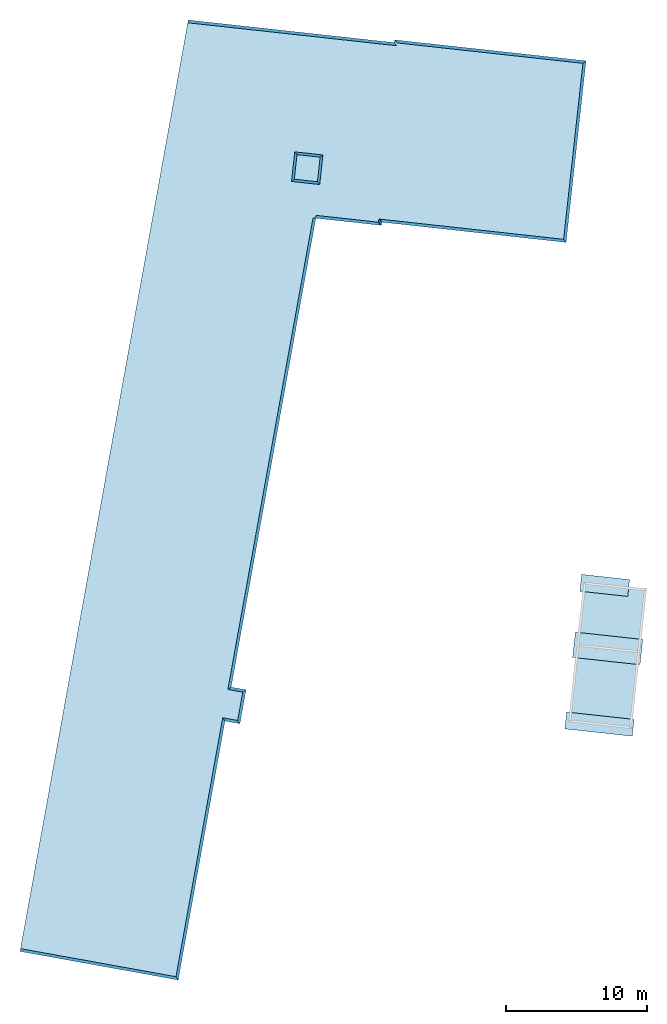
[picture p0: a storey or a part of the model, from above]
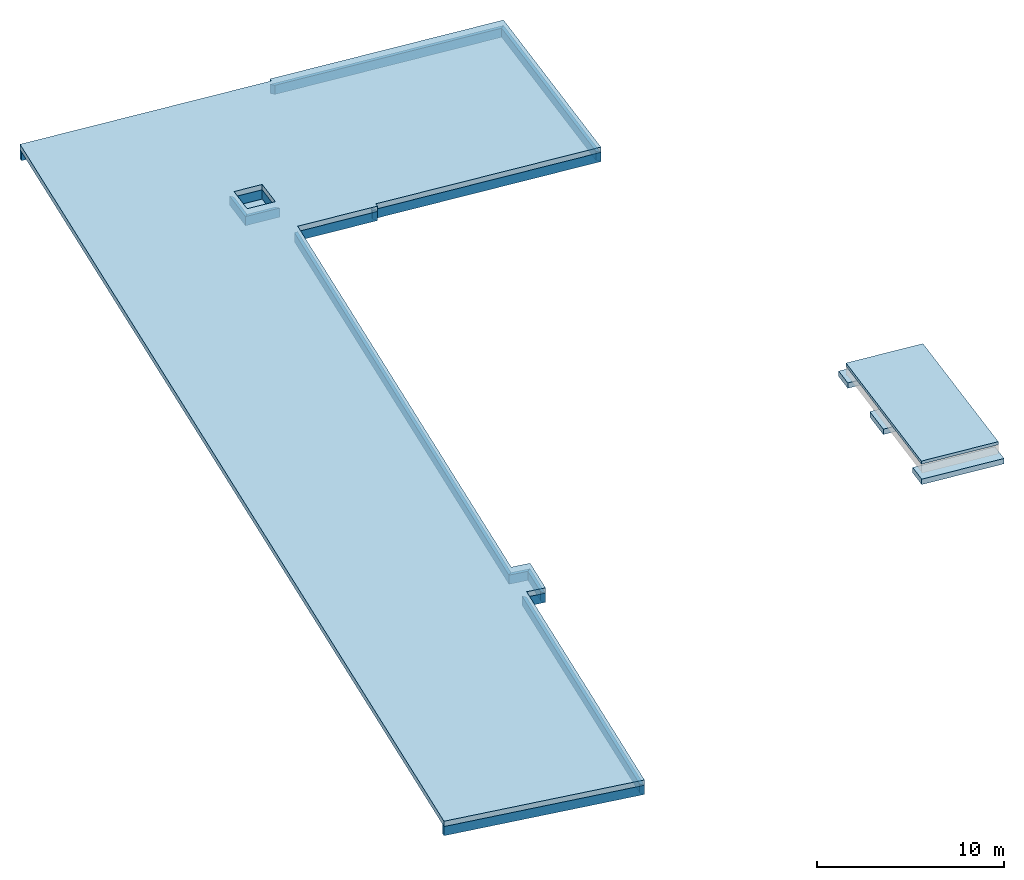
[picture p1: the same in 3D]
Properties of the parts of a building model (IFC2X3), part 1 of 10

# File
Description: ViewDefinition [CoordinationView_V2.0], Option [Elements to export: Visible elements (on all stories)], Option [Partial Structure Display: Entire Model], Option [IFC Domain: All], Option [Structural Function: All Elements], Option [Convert Grid elements: On], Option [Convert IFC Annotations and Archicad 2D elements: Off], Option [Convert 2D symbols of Doors and Windows: Off], Option [Export geometries that Participates in Collision Detection only: Off], Option [Split complex elements: Off], Option [Material Preservation: Explode where necessary], Option [Elements in Solid Element Operations: Extruded/revolved], Option [Elements with junctions: Extruded/revolved without junctions], Option [IFC Model position: Survey Point and Project Origin], Option [Curtain Wall export mode: Container Element], Option [Railing export mode: Single Element], Option [Stair export mode: Container Element], Option [Properties To Export: All properties], Option [Space containment: Off], Option [Geometry to type objects: Off], Option [Element Properties: Off], Option [Building Material Properties: Off], Option [Element Parameters: Off], Option [Component Parameters: Off], Option [IFC Base Quantities: Off], Option [Door Window Parameters: Off], Option [IFC Space boundaries: Off], Option [Archicad Zone Categories as IFC Space classification data: Off], Option [Element Classifications: On]
File name: /Users/julienlaragne/Desktop/ORLEANS TOUR jan 2023/ÉCOLE BOURG D OISANS jan 2023.ifc
Time: 2023-01-25T17:30:47
Author: Architect
Organization: Building Designer Office
Written by: The EXPRESS Data Manager Version 5.02.0100.09 : 18 Aug 2016
Made in: IFC file generated by Graphisoft Archicad 26.0.0 FRA FULL Macintosh version (IFC add-on version: 3001 FRA FULL).
Authorization: The authorising person

# IfcProject, BO
Phase: PRO

# IfcSite, Site
RefLatitude: 45, 3, 7, 23600; RefLongitude: 6, 1, 48, 230400; RefElevation: 719.29 m

# IfcBuildingStorey (4)
In: Bâtiment
Name | Elevation (m)
Fondations | -1.1
RDC | 0
R+1 | 3.2
Toit & PM | 6.55

# IfcBeam: _BA banché 180 x 100, POUTRE
In: R+1
Classification: Poutre (Classification ARCHICAD); Poutre (Classification Archicad); Material: _BA banché
ArchiCADProperties - ID de l'élément: POUTRE; Lien et ID d'élément: POUTRE; Calque: 10_M x baseGO__; Matériau de construction / Composite / Profil / Hachure: _BA banché; Matériau de construction: _BA banché; Nom de zone liée: Circulation 2; Verrouillé: no; Nom d'étage d'implantation: R+1; Numéro d'étage d'implantation: 1; Type d'élément: Poutre; Type de structure: Basique; ID de Parent: POUTRE; Matériaux de construction (Tous): _BA banché; Surfaces (Toutes): _Béton - Lissé; Angle d'inclinaison: 0 deg; Nombre de percements: 0; Surface supérieure: _Béton - Lissé; Surface inférieure: _Béton - Lissé; Position: Intérieur; État de rénovation: Existant; Affichage sur filtre de rénovation: Tous les filtres appropriés; Fonction structurelle: Élément porteur; Coupe transversale de Poutre: Rectangulaire; Surface de fin: _Béton - Lissé; Surface gauche: _Béton - Lissé; Surface droite: _Béton - Lissé; Angle d'inclinaison de Poutre: 0 deg; Génération de modèle analytique structurel: yes; Classification ARCHICAD - 20: Poutre
Pset_BeamCommon - Reference: _BA banché 180 x 100; Span: 2.39006 m; Slope: 0 deg; IsExternal: no; LoadBearing: yes
AC_Pset_RenovationAndPhasing - Renovation Status: Existing

# IfcBeam: _BA banché 240 x 100, POUTRE
In: R+1
Classification: Poutre (Classification ARCHICAD); Poutre (Classification Archicad); Material: _BA banché
ArchiCADProperties - ID de l'élément: POUTRE; Lien et ID d'élément: POUTRE; Calque: 10_M x baseGO__; Matériau de construction / Composite / Profil / Hachure: _BA banché; Matériau de construction: _BA banché; Nom de zone liée: Circulation 2; Verrouillé: no; Nom d'étage d'implantation: R+1; Numéro d'étage d'implantation: 1; Type d'élément: Poutre; Type de structure: Basique; ID de Parent: POUTRE; Matériaux de construction (Tous): _BA banché; Surfaces (Toutes): _Béton - Lissé; Angle d'inclinaison: 0 deg; Nombre de percements: 0; Surface supérieure: _Béton - Lissé; Surface inférieure: _Béton - Lissé; Position: Intérieur; État de rénovation: Existant; Affichage sur filtre de rénovation: Tous les filtres appropriés; Fonction structurelle: Élément porteur; Coupe transversale de Poutre: Rectangulaire; Surface de fin: _Béton - Lissé; Surface gauche: _Béton - Lissé; Surface droite: _Béton - Lissé; Angle d'inclinaison de Poutre: 0 deg; Génération de modèle analytique structurel: yes; Classification ARCHICAD - 20: Poutre
Pset_BeamCommon - Reference: _BA banché 240 x 100; Span: 2.39006 m; Slope: 0 deg; IsExternal: no; LoadBearing: yes
AC_Pset_RenovationAndPhasing - Renovation Status: Existing

# IfcBeam: _BA banché RAL9007 180 x 300, POUTRE
In: R+1
Classification: Poutre (Classification ARCHICAD); Poutre (Classification Archicad); Material: _BA banché RAL9007
ArchiCADProperties - ID de l'élément: POUTRE; Lien et ID d'élément: POUTRE; Calque: 10_M x baseGO__; Matériau de construction / Composite / Profil / Hachure: _BA banché RAL9007; Matériau de construction: _BA banché RAL9007; Nom de zone liée: Terrasse; Verrouillé: no; Nom d'étage d'implantation: R+1; Numéro d'étage d'implantation: 1; Type d'élément: Poutre; Type de structure: Basique; ID de Parent: POUTRE; Matériaux de construction (Tous): _BA banché RAL9007; Surfaces (Toutes): _MENEAU gris RAL 9007; _Enduit minéral RAL7004; Angle d'inclinaison: 0 deg; Nombre de percements: 0; Surface supérieure: _MENEAU gris RAL 9007; Surface inférieure: _Enduit minéral RAL7004; Position: Intérieur; État de rénovation: Existant; Affichage sur filtre de rénovation: Tous les filtres appropriés; Fonction structurelle: Élément porteur; Coupe transversale de Poutre: Rectangulaire; Surface de fin: _MENEAU gris RAL 9007; Surface gauche: _Enduit minéral RAL7004; Surface droite: _Enduit minéral RAL7004; Angle d'inclinaison de Poutre: 0 deg; Génération de modèle analytique structurel: yes; Classification ARCHICAD - 20: Poutre
Pset_BeamCommon - Reference: _BA banché RAL9007 180 x 300; Span: 4.895 m; Slope: 0 deg; IsExternal: no; LoadBearing: yes
AC_Pset_RenovationAndPhasing - Renovation Status: Existing

# IfcBuildingElementPart (15)
In: RDC
Name | Material
10 x _Fini placo poché 590 | _Fini placo poché 590
5 x _Cloison armature 300 | _Cloison armature 300

# IfcBuildingElementProxy: 160 x 170 x 20, Panel-Main-190
In: R+1
Classification: Element de construction non défini (Classification Archicad); Material: Matériau de construction IFC
ArchiCADProperties - ID de l'élément: Panel-Main-190; Lien et ID d'élément: Panel-Main-190; Calque: 10_M x baseGO__; Nom Élément de Bibliothèque: Panneau MR 21; Matériau de construction / Composite / Profil / Hachure: MANQUANT; Matériau de construction: MANQUANT; Verrouillé: no; Nom d'étage d'implantation: R+1; Numéro d'étage d'implantation: 1; Type d'élément: Panneau (Mur-rideau); ID de Parent: pare-vue CTA; Surfaces (Toutes): _Bois-Horiz ocre; Angle d'inclinaison: 90 deg; Surface latérale: GENERAL; État de rénovation: Existant; Affichage sur filtre de rénovation: Tous les filtres appropriés; Abbréviation d'orientation: E; Angle par rapport nord: -100.24 deg; Fonction de panneau: Fixe; Surface intérieure: GENERAL; Surface extérieure: GENERAL; Catégorie de panneau: Panneau personnalisé; Type de panneau: Panneau MR 21; Angle d'inclinaison Panneau mur-rideau: 90 deg
AC_Pset_Panneau_MR_21 - Afficher points chauds 2D en 3D: yes; Modèle schématique automatique: yes; 0-fixe, 1-porte, 2-fenêtre: 0; Direction haut: 0 deg; Direction d'ouverture (ac_openingDir): 0; Angle panneau arrière: 90 deg; Niveau de détail 2D: -1; Stylo coupe: Ouvertures - Coupé non structurel; Hachure coupée: Sans Trame; Stylo hachure coupée: Fond - Couleur 1; Stylo fond hachure coupée: Fond - Couleur 1; Hachure revêtement: Hachure solide; Hachure intérieure: Isolation laine de verre; Stylo hachure revêtement: Ouvertures - Général; Stylo hachure intérieure: Ouvertures - Général; Stylo fond hachure revêtement: Fond - Couleur 1; Stylo fond hachure intérieure: Fond - Couleur 1; Ombre: yes; Intérieur: _Bois-Horiz ocre; Extérieur: _Bois-Horiz ocre; Coût: 0; Surface vitrée totale (gs_list_glassarea_tmp): 0; Supplanter surface vitrée: no; Surface vitrée totale (gs_list_glassarea): 0; Périmètre total vitrage: 0; Type de groupe (FM_Type): Objets par défaut; Type de groupe (iFMType): 1; Numéro de série: Sans; Poids de l'objet: 0; Unité poids de l'objet: kg
AC_Pset_RenovationAndPhasing - Renovation Status: Non défini

# IfcBuildingElementProxy: 245 x 170 x 20, Panel-Main-190
In: R+1
Classification: Element de construction non défini (Classification Archicad); Material: Matériau de construction IFC
ArchiCADProperties - ID de l'élément: Panel-Main-190; Lien et ID d'élément: Panel-Main-190; Calque: 10_M x baseGO__; Nom Élément de Bibliothèque: Panneau MR 21; Matériau de construction / Composite / Profil / Hachure: MANQUANT; Matériau de construction: MANQUANT; Verrouillé: no; Nom d'étage d'implantation: R+1; Numéro d'étage d'implantation: 1; Type d'élément: Panneau (Mur-rideau); ID de Parent: pare-vue CTA; Surfaces (Toutes): _Bois-Horiz ocre; Angle d'inclinaison: 90 deg; Surface latérale: GENERAL; État de rénovation: Existant; Affichage sur filtre de rénovation: Tous les filtres appropriés; Abbréviation d'orientation: E; Angle par rapport nord: -100.24 deg; Fonction de panneau: Fixe; Surface intérieure: GENERAL; Surface extérieure: GENERAL; Catégorie de panneau: Panneau personnalisé; Type de panneau: Panneau MR 21; Angle d'inclinaison Panneau mur-rideau: 90 deg
AC_Pset_Panneau_MR_21 - Afficher points chauds 2D en 3D: yes; Modèle schématique automatique: yes; 0-fixe, 1-porte, 2-fenêtre: 0; Direction haut: 0 deg; Direction d'ouverture (ac_openingDir): 0; Angle panneau arrière: 90 deg; Niveau de détail 2D: -1; Stylo coupe: Ouvertures - Coupé non structurel; Hachure coupée: Sans Trame; Stylo hachure coupée: Fond - Couleur 1; Stylo fond hachure coupée: Fond - Couleur 1; Hachure revêtement: Hachure solide; Hachure intérieure: Isolation laine de verre; Stylo hachure revêtement: Ouvertures - Général; Stylo hachure intérieure: Ouvertures - Général; Stylo fond hachure revêtement: Fond - Couleur 1; Stylo fond hachure intérieure: Fond - Couleur 1; Ombre: yes; Intérieur: _Bois-Horiz ocre; Extérieur: _Bois-Horiz ocre; Coût: 0; Surface vitrée totale (gs_list_glassarea_tmp): 0; Supplanter surface vitrée: no; Surface vitrée totale (gs_list_glassarea): 0; Périmètre total vitrage: 0; Type de groupe (FM_Type): Objets par défaut; Type de groupe (iFMType): 1; Numéro de série: Sans; Poids de l'objet: 0; Unité poids de l'objet: kg
AC_Pset_RenovationAndPhasing - Renovation Status: Non défini

# IfcBuildingElementProxy: 470 x 170 x 20, Panel-Main-847
In: R+1
ArchiCADProperties - ID de l'élément: Panel-Main-847; Lien et ID d'élément: Panel-Main-847; Calque: 10_M x baseGO__; Nom Élément de Bibliothèque: Porte mr 21; Matériau de construction / Composite / Profil / Hachure: MANQUANT; Matériau de construction: MANQUANT; Nom de zone liée: local CTA; Verrouillé: no; Nom d'étage d'implantation: R+1; Numéro d'étage d'implantation: 1; Type d'élément: Panneau (Mur-rideau); ID de Parent: pare-vue CTA; Matériaux de construction (Tous): _Acier; Bois - Equarri 02; Surfaces (Toutes): _Men ext_RAL9007; _Métal - Acier; _INVISIBLE_; _Bois-Horiz ocre; Angle d'inclinaison: 90 deg; De Zone: local CTA; Surface latérale: GENERAL; État de rénovation: Existant; Affichage sur filtre de rénovation: Tous les filtres appropriés; Abbréviation d'orientation: S; Angle par rapport nord: 169.76 deg; Fonction de panneau: Porte; Surface intérieure: GENERAL; Orientation: G; Surface extérieure: GENERAL; Catégorie de panneau: Panneau personnalisé; Type de panneau: Porte mr 21; Angle d'inclinaison Panneau mur-rideau: 90 deg
AC_Pset_Porte_mr_21 - Afficher points chauds 2D en 3D: yes; Modèle schématique automatique: yes; 0-fixe, 1-porte, 2-fenêtre: 1; Direction d'ouverture (gs_opening_dir): Extérieur; Direction d'ouverture (gs_opening_dir_m): 2; Type d'ouverture (gs_optype): Battant; Type d'ouverture (gs_optype_m): 2; Direction haut: 0 deg; Jonction éléments cadree (gs_SashText_typ): Assemblage à onglet; Jonction éléments cadree (gs_SashText_typ_m): 1; Côté ouverture (G/D): G; Direction d'ouverture (0/1/2): 2; Type de cadre (frameType): Sous-cadre; Type de cadre (iFrameType): 1; Type battant: Battant de porte personnalisé; Nbre panneaux horizontaux: 2; Nbre panneaux verticaux: 2; Position grille (grillPosition): Les deux; Position grille (grillPosition_m): 3; Nom de battant de porte: Battant porte CTA; Type poignée (gs_handle_typ): Sans; Type poignée (gs_handle_typ_m): 0; Seuil (bTreshold): no; Angle ouverture en 2D: 45 deg; Angle ouverture horizontal: 0 deg; Angle ouverture vertical: 0 deg; Suppl. Opt. vue pour aff. symb. 2D: no; Type ligne ouverture: 1; Forme ligne ouverture (or_SwingType): Courbé; Forme ligne ouverture (or_iSwingType): 1; Forme ligne ouverture (or_SlidingType): Sans; Forme ligne ouverture (or_iSlidingType): 0; Stylo ligne ouverture 2D/3D (or_opLinePen): Ouvertures - Général; Stylo ligne ouverture 2D/3D (or_iOpLinePen): 3; Suppl. Opt. vue pour proj. 3D: no; Afficher ligne d'ouverture: yes; Type ligne côté ouverture (or_opLineType3dIn): Ligne continue; Type ligne côté ouverture (or_iOpLineType3dIn): 0; Type ligne côté opposé (or_opLineType3dOut): Ligne continue; Type ligne côté opposé (or_iOpLineType3dOut): 0; Orient. ligne (or_oplineStyle): Poignée; Orient. ligne (or_iOplineStyle): 1; Niveau de détail 2D: 1; Stylo panneaux: Eléments 2D - Général; Stylo cadre: Eléments 2D - Général; Stylo seuil: Eléments 2D - Général; Stylo vitrage: Eléments 2D - Général; Hachure de battant: Sans Trame; Hachure de cadre: Sans Trame; Hachure seuil: Sans Trame; Stylo hachure de battant: Eléments 2D - Général; Stylo hachure cadre: Eléments 2D - Général; Stylo hachure recouvr. seuil: Eléments 2D - Général; Stylo fond de hachure battant: Transparent; Stylo fond de hachure cadre: Transparent; Stylo fond de hachure de seuil: Transparent; Stylo coupe/contour: Eléments 2D - Général; Hachure coupée: Sans Trame; Stylo hachure coupée: Fond - Couleur 1; Stylo fond hachure coupée: Fond - Couleur 1; Niveau de détail 3D (gs_detlevel_3D): Simple; Niveau de détail 3D (gs_detlevel_3d_m): 1; Ombre: yes; Résolution: 5; Cadre (matFrame): _Men ext_RAL9007; Battant (matSash): _Bois-Horiz ocre; Grille: _Métal - Zinc; Vitrage (matGlass): _Transp - Verre; Seuil (matTreshold): _Métal - Acier inoxydable; Poignée: _Men ext_RAL9007; Accessoire poignée: _Men ext_RAL9007; Adaptateur: _Métal - Zinc; Fixation: _INVISIBLE_; Coût: 0; Surface vitrée totale (gs_list_glassarea_tmp): 0; Supplanter surface vitrée: no; Surface vitrée totale (gs_list_glassarea): 0; Périmètre total vitrage: 0; Type de groupe (FM_Type): Objets par défaut; Type de groupe (iFMType): 1; Numéro de série: Sans; Poids de l'objet: 0; Unité poids de l'objet: kg; Affichage symbolique de l'ouverture: no
AC_Pset_RenovationAndPhasing - Renovation Status: Non défini

# IfcBuildingElementProxy: 600 x 170 x 20 (5)
In: R+1
Classification: Element de construction non défini (Classification Archicad); Material: Matériau de construction IFC
ArchiCADProperties - ID de l'élément: Panel-Main-190; Lien et ID d'élément: Panel-Main-190; Calque: 10_M x baseGO__; Nom Élément de Bibliothèque: Panneau MR 21; Matériau de construction / Composite / Profil / Hachure: MANQUANT; Matériau de construction: MANQUANT; Verrouillé: no; Nom d'étage d'implantation: R+1; Numéro d'étage d'implantation: 1; Type d'élément: Panneau (Mur-rideau); ID de Parent: pare-vue CTA; Surfaces (Toutes): _Bois-Horiz ocre; Angle d'inclinaison: 90 deg; Surface latérale: GENERAL; État de rénovation: Existant; Affichage sur filtre de rénovation: Tous les filtres appropriés; Abbréviation d'orientation: E; Angle par rapport nord: -100.24 deg; Fonction de panneau: Fixe; Surface intérieure: GENERAL; Surface extérieure: GENERAL; Catégorie de panneau: Panneau personnalisé; Type de panneau: Panneau MR 21; Angle d'inclinaison Panneau mur-rideau: 90 deg
AC_Pset_Panneau_MR_21 - Afficher points chauds 2D en 3D: yes; Modèle schématique automatique: yes; 0-fixe, 1-porte, 2-fenêtre: 0; Direction haut: 0 deg; Direction d'ouverture (ac_openingDir): 0; Angle panneau arrière: 90 deg; Niveau de détail 2D: -1; Stylo coupe: Ouvertures - Coupé non structurel; Hachure coupée: Sans Trame; Stylo hachure coupée: Fond - Couleur 1; Stylo fond hachure coupée: Fond - Couleur 1; Hachure revêtement: Hachure solide; Hachure intérieure: Isolation laine de verre; Stylo hachure revêtement: Ouvertures - Général; Stylo hachure intérieure: Ouvertures - Général; Stylo fond hachure revêtement: Fond - Couleur 1; Stylo fond hachure intérieure: Fond - Couleur 1; Ombre: yes; Intérieur: _Bois-Horiz ocre; Extérieur: _Bois-Horiz ocre; Coût: 0; Surface vitrée totale (gs_list_glassarea_tmp): 0; Supplanter surface vitrée: no; Surface vitrée totale (gs_list_glassarea): 0; Périmètre total vitrage: 0; Type de groupe (FM_Type): Objets par défaut; Type de groupe (iFMType): 1; Numéro de série: Sans; Poids de l'objet: 0; Unité poids de l'objet: kg
AC_Pset_RenovationAndPhasing - Renovation Status: Non défini

# IfcBuildingElementProxy: Basin 03 16 (8)
Classification: Element de construction non défini (Classification Archicad); Material: Matériau de construction IFC
ArchiCADProperties - Calque: 21_App Sanit_____; Nom Élément de Bibliothèque: Basin 03 16; Matériau de construction / Composite / Profil / Hachure: Sans Trame; Type Hachure: Sans Trame; Verrouillé: no; Type d'élément: Équipement; Surfaces (Toutes): _Metal-Inox; _Sanitaire-porcelaine; Position: Non défini; État de rénovation: Existant; Affichage sur filtre de rénovation: Tous les filtres appropriés; Surface: _Peinture-11
AC_Pset_Basin_03_16 - 3D (gs_detlevel_3D): Detailed; 3D (gs_detlevel_3D_m): 2; Show 2D Hotspots in 3D: no; Set Program: no; Tap Type (tapGroup): Single Level Mixer; Tap Type (iTapGroup): 1; Tap Style (gs_tap_type): Style 1; Tap Style (gs_tap_type_m): 1; Hot Water Connection: yes; Tool Type (ConToolType_1): 2; MEP System (ConSystem_1): Undefined; Shape Type (ConType_1): Circle; Connection Type (ConConnectorType_1): Soudé; Cold Water Connection: yes; Tool Type (ConToolType_2): 2; MEP System (ConSystem_2): Undefined; Shape Type (ConType_2): Circle; Connection Type (ConConnectorType_2): Soudé; Waste Water Connection: yes; Tool Type (ConToolType_3): 2; MEP System (ConSystem_3): Undefined; Shape Type (ConType_3): Circle; Connection Type (ConConnectorType_3): Soudé; Resolution: 12; Shadow: yes; 2D Detail Level (gs_detlevel_2D): Scale Sensitive; 2D Detail Level (gs_detlevel_2D_m): 0; Tap Symbol Type (TapSymbol): Detailed; Tap Symbol Type (TapSymbol_m): 2; Contour Pen: Eléments 2D - Général; Fill Type: Sans Trame; Fill Background Pen: Transparent; Basin Material: _Sanitaire-porcelaine; Tap Material: _Métal - Or; Drain Material: _Metal-Inox; Connection Material: _Metal-Inox; Use System Material: no; System Material: _Peinture - Cadmium jaune; Version: 4; Number of Connections: 3; Cost: 0; Type de groupe: 12; Area: 0; Volume: 0; Object Weight: 0; Object Weight Unit: kg
AC_Pset_RenovationAndPhasing - Renovation Status: Existing
Name | In | ID de l'élément = Lien et ID d'élément = ID de Parent | Zones conflictuelles = Nom de zone liée | Nom d'étage d'implantation | Numéro d'étage d'implantation | Fonction structurelle | Angle de rotation (deg) | Fill Pen | Group Type
lavabo-WC | RDC | lavabo-WC | Sanitaires | RDC | 0 | Non défini | 180 | Général - Dessin 0.12 | Sanitation
lavabo-WC | RDC | lavabo-WC | Sanitaires | RDC | 0 | Non défini | 273.96 | Jaune | Sanitation
lavabo-WC | RDC | lavabo-WC | Sanitaires | RDC | 0 | Non défini | 0 | Général - Dessin 0.12 | Sanitaires
lavabo-WC | RDC | lavabo-WC | Sanitaires | RDC | 0 | Non défini | 93.9336 | Jaune | Sanitation
2 x lavabo-BlocSanit | RDC | lavabo-BlocSanit |  | RDC | 0 | Élément non porteur | 184.017 | Général - Dessin 0.12 | Sanitation
lavabo-couloir | R+1 | lavabo-couloir | Sanitaires | R+1 | 1 | Non défini | 0 | Général - Dessin 0.12 | Sanitaires
lavabo-couloir | R+1 | lavabo-couloir | Sanitaires | R+1 | 1 | Non défini | 179.985 | Général - Dessin 0.12 | Sanitation

# IfcBuildingElementProxy: Elément Modèle 215, MOBILIER-001
In: R+1
Material: Matériau de construction IFC
AC_Pset_RenovationAndPhasing - Renovation Status: Existing

# IfcBuildingElementProxy: Elément Modèle 216, Bois - Equarri 02
In: R+1
Material: Bois - Equarri 02
AC_Pset_RenovationAndPhasing - Renovation Status: Existing

# IfcBuildingElementProxy: Elément simple avec deux portes 21 (11)
Classification: Element de construction non défini (Classification Archicad); Material: Matériau de construction IFC
ArchiCADProperties - Calque: 21_App Sanit_____; Nom Élément de Bibliothèque: Elément simple avec deux portes 21; Matériau de construction / Composite / Profil / Hachure: Sans Trame; Type Hachure: Sans Trame; Verrouillé: no; Type d'élément: Équipement; Position: Non défini; État de rénovation: Existant; Affichage sur filtre de rénovation: Tous les filtres appropriés; Fonction structurelle: Non défini; Surface: _Peinture - Ocre jaune
AC_Pset_Elément_simple_avec_deux_portes_21 - Niveau de détail 3D: Détaillé; 3D: 2; Afficher points chauds 2D en 3D: no; Définir programme: no; Taille A B =: Comptoir; Taille 'A' 'B' = Taille élément: no; Type plinthe (gs_toe_type): Entier; Type plinthe (gs_toe_type_m): 1; Nbre d'étagères: 1; Visibilité arête comptoir 3D (side_vis): Droite; Côtés visibles: 2; Visibilité arête comptoir 3D (side_vis_mirror): Gauche; Porte: Style 1; Style porte: 1; Biseau arête: no; Largeurs Portes égales: yes; Angle ouverture porte: 0 deg; Nb. grilles porte vert.: 1; Nb. grilles porte hor.: 2; Tiroir (bDrawer): no; Tiroir no.: 2; Front de tiroir identique à porte: no; Bouton (gs_knob_type): Style 1; Style bouton: 1; Placement (gs_knob_p): Vertical; Placement (gs_knob_p_m): 0; Double face: no; Panneau de finition gauche (left_panel): no; Panneau de finition droit (right_panel): no; Panneau de finition gauche (left_panel_mirror): no; Panneau de finition droit (right_panel_mirror): no; Panneau de finition arrière: no; Type panneau de fin: Style 1; Comptoir (gs_count_type): Rectangulaire; Type comptoir: 1; Evier (gs_sink_type): Style 4; Style évier: 4; Evier sous plan de travail: no; Robinet (gs_tap_type): Style 3; Style de robinet: 3; Connexion d'eau chaude: yes; Type outil (ConToolType_1): 2; Système MEP (ConSystem_1): Non défini; Type de forme (ConType_1): Cercle; Type connexion (ConConnectorType_1): Soudé; Connexion d'eau froide: yes; Type outil (ConToolType_2): 2; Système MEP (ConSystem_2): Non défini; Type de forme (ConType_2): Cercle; Type connexion (ConConnectorType_2): Soudé; Connexion eau résiduaire: yes; Type outil (ConToolType_3): 2; Système MEP (ConSystem_3): Non défini; Type de forme (ConType_3): Cercle; Type connexion (ConConnectorType_3): Soudé; Type symbole meuble: Type 1; Visibilité arête 2D (side_vis2D): Les deux; Visibilité arête 2D (side_vis2D_m): 3; Visibilité arête 2D (side_vis2D_mirror): Les deux; Type symbole évier (SinkSymbol): Détaillé; Type symbole évier (SinkSymbol_m): 2; Type symbole robinet (TapSymbol): Détaillé; Type symbole robinet (TapSymbol_m): 2; Stylo contour: gris moyen (007); Motif de hachure: Sans Trame; Stylo hachure: Fond - Couleur 1; Stylo fond de hachure: Fond - Couleur 1; Résolution: 10; Ombre: yes; Edition points chauds extra: yes; Meuble (gs_cabinet_mat): _Mur int blanc; Dosseret: _Carrelage - Blanc mat 15x15; Plinthe: _MENEAU gris RAL 9007; Porte (vitre): _Verre clair (rapide); Tiroir (DrawerMat): _Mur int blanc; Panneau de fin: _Men ext_RAL9007; Bouton (gs_knob_mat): _Métal - Acier inoxydable; Etagère: _Mur int blanc; Evier (gs_sink_mat): _Métal - Chrome; Robinet (gs_tap_mat): _Métal - Acier inoxydable; Connexion: _Métal - Acier inoxydable; Utiliser surface de système: no; Surface de système: _Peinture - Cadmium jaune; Nombre connexions: 3; Coût: 0; Aire: 0; Volume: 0; Type de groupe (FM_Type): Equipement CVCA; Type de groupe (iFMType): 12; Poids de l'objet: 0; Unité poids de l'objet: kg
AC_Pset_RenovationAndPhasing - Renovation Status: Existing
Name | In | ID de l'élément = Lien et ID d'élément = ID de Parent | Zones conflictuelles = Nom de zone liée | Nom d'étage d'implantation | Numéro d'étage d'implantation | Surfaces (Toutes) | Angle de rotation (deg) | Comptoir (count_mat) | Porte (cadre)
evier-classe | RDC | evier-classe | Salle de classe 1 | RDC | 0 | _Métal - Acier inoxydable; _Métal - Chrome; _Mur int blanc; _Classe 1-RAL2000; _Carrelage - Blanc mat 15x15; _MENEAU gris RAL 9007; _Transp - Invisible | 90 | _Transp - Invisible | _Classe 1-RAL2000
evier-classe | RDC | evier-classe | Salle de classe 5 | RDC | 0 | _Métal - Acier inoxydable; _Métal - Chrome; _Mur int blanc; _Carrelage - Blanc mat 15x15; _Classe 5-RAL4006; _MENEAU gris RAL 9007; _Transp - Invisible | 90 | _Transp - Invisible | _Classe 5-RAL4006
evier-classe | RDC | evier-classe | Salle de classe 2 | RDC | 0 | _Métal - Acier inoxydable; _Métal - Chrome; _Mur int blanc; _Carrelage - Blanc mat 15x15; _MENEAU gris RAL 9007; _Classe 2-RAL5018; _Transp - Invisible | 90 | _Transp - Invisible | _Classe 2-RAL5018
evier-classe | RDC | evier-classe | Salle de classe 3 | RDC | 0 | _Métal - Acier inoxydable; _Métal - Chrome; _Mur int blanc; _Carrelage - Blanc mat 15x15; _MENEAU gris RAL 9007; _Classe 3-RAL3003; _Transp - Invisible | 90 | _Transp - Invisible | _Classe 3-RAL3003
evier-classe | RDC | evier-classe | Salle de classe 4 | RDC | 0 | _Métal - Acier inoxydable; _Métal - Chrome; _Mur int blanc; _Carrelage - Blanc mat 15x15; _MENEAU gris RAL 9007; _Classe 4-RAL6026; _Transp - Invisible | 90 | _Transp - Invisible | _Classe 4-RAL6026
evier-maitres | R+1 | evier-maitres | Salle de réunion (maîtres) | R+1 | 1 | _Métal - Acier inoxydable; _Métal - Chrome; _Mur int blanc; _Carrelage - Blanc mat 15x15; _MENEAU gris RAL 9007 | 273.97 | _Carrelage - Blanc mat 15x15 | _Mur int blanc
evier-classe | R+1 | evier-classe | Salle de classe 6 | R+1 | 1 | _Métal - Acier inoxydable; _Métal - Chrome; _Mur int blanc; _Classe 1-RAL2000; _Carrelage - Blanc mat 15x15; _MENEAU gris RAL 9007; _Transp - Invisible | 90 | _Transp - Invisible | _Classe 1-RAL2000
evier-classe | R+1 | evier-classe | Salle de classe 7 | R+1 | 1 | _Métal - Acier inoxydable; _Métal - Chrome; _Mur int blanc; _Carrelage - Blanc mat 15x15; _MENEAU gris RAL 9007; _Classe 2-RAL5018; _Transp - Invisible | 90 | _Transp - Invisible | _Classe 2-RAL5018
evier-classe | R+1 | evier-classe | Salle de classe 8 | R+1 | 1 | _Métal - Acier inoxydable; _Métal - Chrome; _Mur int blanc; _Carrelage - Blanc mat 15x15; _MENEAU gris RAL 9007; _Classe 3-RAL3003; _Transp - Invisible | 90 | _Transp - Invisible | _Classe 3-RAL3003
evier-classe | R+1 | evier-classe | Salle de classe 10 | R+1 | 1 | _Métal - Acier inoxydable; _Métal - Chrome; _Mur int blanc; _Carrelage - Blanc mat 15x15; _Classe 5-RAL4006; _MENEAU gris RAL 9007; _Transp - Invisible | 90 | _Transp - Invisible | _Classe 5-RAL4006
evier-classe | R+1 | evier-classe | Salle de classe 9 | R+1 | 1 | _Métal - Acier inoxydable; _Métal - Chrome; _Mur int blanc; _Carrelage - Blanc mat 15x15; _MENEAU gris RAL 9007; _Classe 4-RAL6026; _Transp - Invisible | 90 | _Transp - Invisible | _Classe 4-RAL6026

# IfcBuildingElementProxy: Evier Belfast 21 (3)
In: RDC
Classification: Element de construction non défini (Classification Archicad); Material: Matériau de construction IFC
ArchiCADProperties - ID de l'élément: lavabo_BlocSanit; Lien et ID d'élément: lavabo_BlocSanit; Calque: 21_App Sanit_____; Nom Élément de Bibliothèque: Evier Belfast 21; Matériau de construction / Composite / Profil / Hachure: Sans Trame; Type Hachure: Sans Trame; Verrouillé: no; Nom d'étage d'implantation: RDC; Numéro d'étage d'implantation: 0; Type d'élément: Équipement; ID de Parent: lavabo_BlocSanit; Surfaces (Toutes): _Metal-Inox; _Sanitaire-porcelaine; Position: Non défini; État de rénovation: Existant; Affichage sur filtre de rénovation: Tous les filtres appropriés; Angle de rotation: 184.017 deg; Surface: _Peinture - Ocre jaune
AC_Pset_Evier_Belfast_21 - Afficher points chauds 2D en 3D: no; Définir programme: no; Niveau de détail 3D (gs_detlevel_3D): Détaillé; Styles évier (gs_sink_type): Style 1; Styles robinet (gs_tap_type): Sans; Connexion d'eau chaude: yes; Type outil (ConToolType_1): 2; Système MEP (ConSystem_1): Non défini; Type de forme (ConType_1): Cercle; Type connexion (ConConnectorType_1): Soudé; Connexion d'eau froide: yes; Type outil (ConToolType_2): 2; Système MEP (ConSystem_2): Non défini; Type de forme (ConType_2): Cercle; Type connexion (ConConnectorType_2): Soudé; Connexion eau résiduaire: yes; Type outil (ConToolType_3): 2; Système MEP (ConSystem_3): Non défini; Type de forme (ConType_3): Cercle; Type connexion (ConConnectorType_3): Soudé; Connexion eau résiduaire 2: no; Type outil (ConToolType_4): 2; Système MEP (ConSystem_4): Non défini; Type de forme (ConType_4): Cercle; Type connexion (ConConnectorType_4): Soudé; Connexion eau résiduaire 3: no; Type outil (ConToolType_5): 2; Système MEP (ConSystem_5): Non défini; Type de forme (ConType_5): Cercle; Type connexion (ConConnectorType_5): Soudé; Type symbole évier (SinkSymbol): Simple; Type symbole robinet (TapSymbol): Détaillé; Stylo contour: Eléments 2D - Général; Motif de hachure: Sans Trame; Stylo hachure: Général - Dessin 0.12; Stylo fond de hachure: Transparent; Résolution: 16; Ombre: yes; Evier: _Sanitaire-porcelaine; Robinet: _Metal-Inox; Connexion: _Metal-Inox; Utiliser surface de système: no; Surface de système: _Peinture - Cadmium jaune; Niveau de détail 3D (gs_detlevel_3D_m): 2; Styles évier (gs_sink_type_m): 1; Styles robinet (gs_tap_type_m): 0; Type symbole évier (SinkSymbol_m): 1; Type symbole robinet (TapSymbol_m): 2; Nombre connexions: 3; Coût: 0; Type de groupe (FM_Type): Equipement CVCA; Type de groupe (iFMType): 12; Aire: 0; Volume: 0; Poids de l'objet: 0; Unité poids de l'objet: kg
AC_Pset_RenovationAndPhasing - Renovation Status: Existing
Name | Fonction structurelle
2 x lavabo_BlocSanit | Élément non porteur
lavabo_BlocSanit | Non défini

# IfcBuildingElementProxy: Fenêtre double 21 (30)
Classification: Element de construction non défini (Classification Archicad); Fenêtre (Classification ARCHICAD); Material: Matériau de construction IFC
ArchiCADProperties - Calque: 10_M x baseGO__; Nom Élément de Bibliothèque: Fenêtre double 21; Matériau de construction / Composite / Profil / Hachure: Sans Trame; Type Hachure: Sans Trame; Verrouillé: no; Type d'élément: Fenêtre; ID de Parent: M ext-Est; État de rénovation: Existant; Affichage sur filtre de rénovation: Tous les filtres appropriés; Fonction structurelle: Non défini; Structure de Mur: _M ext 18 +18 gris; Nom élément de bibliothèque d'ouverture: Fenêtre double 21; Index hachure latérale ouverture: Sans Trame; Classification ARCHICAD - 21: Fenêtre
AC_Pset_Fenêtre_double_21 - Contours Mur (0-Sans,1-Tout,2-Côté,3-Longueur): 0; Point ch.0-Non,1-2D,2-3D,3-Tous: 3; Option affichage en plan: 3; Angle de position baie: 0 deg; Trou reprend surface latérale de mur: yes; Division de surface du trou courbe dans murs courbes: no; Afficher points chauds 2D en 3D: yes; Type de mur: 1; Type de direction de mur: 1; Position ancre ébrasuer: 1; Fonction de debug Fenêtre Angle: no; Placement (1=Angle, 0=Centre): no; Basculer: no; Démolition / Nouvelle constr.: 1; Nouveau motif de hachure de mur: Parpaing; Nouveau stylo de hachure de mur: Général - Dessin 0.12; Nouveau stylo fond hachure mur: Fond - Couleur 1; Afficher nouv. constr. sur mur: no; Type de ligne démolition: 4; Aff. param. Démolition/Nouveau: no; Fonction Fenêtre Angle: yes; Angle Murs: 90 deg; Murs connectés d'épaiss. diff.: no; Poteau d'angle: no; Coin 2: no; Angle de coin 2: 90 deg; Murs connectés d'épaiss. diff. 2: no; Coin 1: no; Angle de coin 1: 90 deg; Murs connectés d'épaiss. diff. 1: no; Type connexion angle 1: 1; Type connexion angle 2: 1; Entièrement éditable: yes; Niveau de détail 2D: 2; Afficher ébrasure sur symbole: 1; Niveau de détail 3D: 2; Activer niveau détail 3D: 14; Taille nominale: 0; Taille trou comme taille nominale: yes; Taille ébrasure comme nominale: no; Taille unité comme nominale: no; Transmettre taille nominale actuelle à sélection: no; Largeur cadre uniforme: no; Traverse supérieure: no; Traverse supérieure divisée: no; Traverse inférieure: no; Traverse inférieure divisée: no; Panneaux verticaux (gs_PanesConfigVertical): Asymétrique; Panneaux verticaux (gs_iPanesConfigVertical): 3; Direction vitrage fixe (FixGlassDir): Par direction d'ouverture; Direction vitrage fixe (FixGlassDir_m): 1; Type d'opération châssis princ. 2: Battant symétrie; Type d'ouverture (gs_optype_m_01): 4; Type d'ouverture (gs_optype_m_07): 1; Type d'ouverture (gs_optype_m_03): 1; Type d'ouverture (gs_optype_m_06): 1; Type d'ouverture (gs_optype_m_02): 1; Type châssis (MullionStyle_00): Pas de grille; Type châssis (iMullionStyle_00): 1; Type châssis, châssis princ. 1: Pas de grille; Type châssis (iMullionStyle_05): 1; Type châssis, châssis princ. 2: Pas de grille; Type châssis (iMullionStyle_01): 1; Type châssis (iMullionStyle_07): 1; Type châssis (iMullionStyle_03): 1; Type châssis (iMullionStyle_06): 1; Type châssis (iMullionStyle_02): 1; Châssis vitré: no; Meneau jusqu'en haut: no; Meneau jusqu'en bas: no; Edition point chaud de grille: yes; Position grille (MullionPosition): Les deux; Position grille (iMullionPosition): 3; Nbre panneaux V châssis princ. 1: 2; Nbre panneaux H châssis princ. 1: 2; Nbre panneaux V 2 châssis princ. 1: 2; Nbre panneaux H 2 châssis princ. 1: 2; Nbre panneaux V châssis princ. 2: 2; Nbre panneaux H châssis princ. 2: 2; Nbre panneaux V 2 châssis princ. 2: 2; Nbre panneaux H 2 châssis princ. 2: 2; Nbre panneaux V châssis inf.1: 2; Nbre panneaux H châssis inf.1: 2; Nbre panneaux V 2 châssis inf. 1: 2; Nbre panneaux H 2 châssis inf. 1: 2; Nbre panneaux V châssis inf. 2: 2; Nbre panneaux H châssis inf. 2: 2; Nbre panneaux V 2 châssis inf. 2: 2; Nbre panneaux H 2 châssis inf. 2: 2; Nbre panneaux V châssis imposte 1: 2; Nbre panneaux H châssis imposte 1: 2; Nbre panneaux V 2 châssis imposte 1: 2; Nbre panneaux H 2 châssis imposte 1: 2; Nbre panneaux V châssis imposte 2: 2; Nbre panneaux H châssis imposte 2: 2; Nbre panneaux V 2 châssis imposte 2: 2; Nbre panneaux H 2 châssis imposte 2: 2; Style persiennes (iLouverStyle): 1; Angle d'ouverture persiennes: 0 deg; Chambranle extérieur (gs_trim_outside): no; Type chambr. ext. (gs_trimtype_out): Simple; Type chambr. ext. (gs_trimtype_out_int): 1; Type tête chambr. ext.: 1; Chapiteau architrave: yes; Type chapiteau architrave: 1; Chambranle inférieur extérieur: yes; Couvre surface mur ext.: yes; Largeurs uniformes de chambranle (gs_trim_outside_uniform): yes; Chambranle intérieur.: no; Type chambr. intérieur (gs_trimtype_in): Simple; Type chambr. intérieur (gs_trimtype_in_int): 1; Couvre surface mur int.: yes; Largeurs uniformes de chambranle (gs_trim_inside_uniform): yes; Appui (gs_sill_outside): yes; Dépassement appui: no; Type d'appui/seuil: 1; Appui courbe dans murs courbes: yes; Isolation sous appui: yes; Utiliser couche isolation mur: no; Niveau détail 3D seuil brique: 1; Tablette (gs_board_inside): no; Angle tablette: 0 deg; Tabl. courbe dans murs courbes: yes; Tableau dans murs polygonaux: 1; Aération naturelle: no; Type d'aération naturelle: 2; Châssis principal 1: yes; Châssis principal 2: no; Châssis inférieur 1: no; Châssis inférieur 2: no; Châssis imposte 1: no; Châssis imposte 2: no; Volet: yes; Type volet: 6; Types volet activés: 126; Nombre de panneaux: 2; Nombre de panneaux 2: 1; Position panneau (gs_shutter_panelPos): Symétrique; Position panneau (gs_shutter_iPanelPos): 1; Hauteur volet automatique: yes; Cadre supplémentaire: no; Type de couverture (gs_slidingShutter_cover): Profil en Z; Type de couverture (gs_slidingShutter_iCover): 1; Direction articulation (gs_foldingShutter_stacking): Intérieur; Direction articulation (gs_foldingShutter_iStacking): 1; Ouvert en 3D: yes; Angle ouverture en 3D: 180 deg; Afficher symbole 2D: no; Afficher lignes d'ouverture sur symbole: no; Type de panneau: (gs_shutPanel_type): Style 1; Type de panneau: (gs_shutPanel_iType): 1; Largeur cadre inf. différente: no; Largeur volets automatiques: yes; Angle persienne: 30 deg; Nombre trous horizontaux: 5; Nombre trous verticaux: 8; Placement volet roulant (gs_shutRoll_placement): A fenêtre; Placement volet roulant (gs_shutRoll_iPlacement): 2; Type boîte (gs_shutRoll_boxType): Rectangulaire; Type boîte (gs_shutRoll_iBoxType): 1; Position rampe (gs_shutRoll_railPos): Sur revêtement; Position rampe (gs_shutRoll_iRailPos): 1; Afficher revêtement derrière parasol (gs_shutRoll_showCasingBehind): no; Isolation derrière cellule (gs_shutRoll_cutWallBehind): no; Inclure hauteur dans hauteur de trou de mur: no; Angle supérieur boîte: 10 deg; Taille boîte par défaut (gs_shutRoll_boxDefaultSize): A largeur d'ébrasure; Taille boîte par défaut (gs_shutRoll_iBoxDefaultSize): 1; Placement stores (gs_shutLam_placement): Fixé sur façade; Placement stores (gs_shutLam_iPlacement): 1; Isolation derrière cellule (gs_shutLam_cutWallBehind): no; Boîte ouverte: yes; Rampe: yes; Position rampe (gs_shutLam_railPos): Sur revêtement; Position rampe (gs_shutLam_iRailPos): 1; Afficher revêtement derrière parasol (gs_shutLam_showCasingBehind): no; Angle de rotation des lamelles (gs_shutLam_rotation): 45 deg; Angle de rotation des lamelles (gs_shutLam2_rotation): 45 deg; Linteau (bMasonryArch): no; Linteau (gs_masonry_arch_int): 2; Type linteau (gs_masonry_arch_structure): Stuc; Type linteau (gs_masonry_arch_structure_int): 1; Arche sur linteau: yes; Niche sous arche: yes; Angle inclinaison: 75 deg; Surface niche personnalisée: no; Type ébrasure (gs_reveal_type_new): Baie simple; Type ébrasure (gs_reveal_type_int): 2; Type ébrasure inférieure (gs_reveal_type_bottom): Uniforme; Type ébrasure inférieure (gs_reveal_type_bottom_int): 1; Type ébrasure extérieure: Baie simple; Type ébrasure (gs_reveal_doubleOuterTypeInt): 0; Type ébrasure intérieure: Baie simple; Type ébrasure (gs_reveal_doubleInnerTypeInt): 0; Profondeur montant uniforme: yes; Côté angle 2: 20 deg; Côté angle: 20 deg; Angle côté supérieur: 20 deg; Angle côté inférieur: 20 deg; Utiliser composant finition mur: no; Tourner automatiquement plâtre surface intérieure: yes; Tourner plâtre surface intérieure: 0; Tourner automatiquement plâtre surface extérieure: yes; Tourner plâtre surface extérieure: 0; Peut être coté en 2D: no; Afficher en 3D: no; Type de fermeture (gs_closure_type): Pas de fermeture; Type de fermeture (gs_closure_type_int): 1; Tourner couche sur côté (gs_cavity_side): Les deux; Tourner couche sur côté (iCavityClosureSide): 1; Nbre de couches retournées: 1; Num. à partir de (gs_nTurnDir): Face extérieure; Num. à partir de (iCavityClosureTurnDir): 1; Placer fermeture sur côté 2: yes; Placer fermeture sur côté 1: yes; Placer fermeture en haut: no; Placer fermeture en bas: no; Placer fermeture sur couche: 1; Placer fermeture de côté (gs_cc_dutch_ClosureToSide): 1; Ecart à couche externe: yes; Tourner couche sur fermeture: no; Insérer bande d'isolation: yes; Afficher bande d'isolation: yes; Stylo contour (gs_penJoint): Ouvertures - Coupé non structurel; Type de ligne de contour (gs_ltJoint): 1; Motif de hachure (gs_fillJoint): Isolation polystyrène; Stylo hachure (gs_penJointFg): Général - Dessin 0.12; Stylo fond de hachure (gs_penJointBg): Eléments 2D - Dessin; Surface personnalisée: no; Surface: _Men ext_RAL9007; Stylo contour (gs_penPlug): Ouvertures - Coupé non structurel; Type de ligne de contour (gs_ltPlug): 1; Motif de hachure (gs_fillPlug): Isolation polystyrène; Stylo hachure (gs_penPlugFg): Général - Dessin 0.12; Stylo fond de hachure (gs_penPlugBg): Eléments 2D - Dessin; Côté montant édité: 1; Côté mur édité: 1; Numéro couche éditée: 1; Tourner couche: no; Considérer couches comme plâtre: no; Tourner épaiseur: 1; Orientation hachure: 1; Ligne de séparation tournant: no; Stylo ligne de séparation: Général - Dessin 0.12; Dernier côté sélectionné: no; Méthode fermeture changée auto.: no; Connexion à gauche: no; Connexion à droite: no; Connexion en haut: no; Connexion en bas: no; Incrustation allège: no; Tailles incrustation mur (gs_parapet_sizes_st): Automatique; Tailles incrustation mur (iParapetSize): 1; Cotes largeur et longueur auto: yes; Incrustation base mur à (gs_parapet_bottom_st): Etage actuel; Incrustation base mur à (iParapetBottom): 1; Afficher allège masquée: yes; Type ligne allège masquée: 1; Angle ouv. châssis principal 1 (openingAngle_05): 0 deg; Angle ouv. châssis principal 1 (openingAngle2_05): 0 deg; Angle ouv. châssis principal 2 (openingAngle_01): 0 deg; Angle ouv. châssis principal 2 (openingAngle2_01): 0 deg; Angle d'ouverture châssis inf. 1 (openingAngle_07): 0 deg; Angle d'ouverture châssis inf. 1 (openingAngle2_07): 0 deg; Angle d'ouverture châssis inf. 2 (openingAngle_03): 0 deg; Angle d'ouverture châssis inf. 2 (openingAngle2_03): 0 deg; Angle ouv. châssis imposte 1 (openingAngle_06): 0 deg; Angle ouv. châssis imposte 1 (openingAngle2_06): 0 deg; Angle ouv. châssis imposte 2 (openingAngle_02): 0 deg; Angle ouv. châssis imposte 2 (openingAngle2_02): 0 deg; Angle ouverture en 2D: 0 deg; Suppl. Opt. vue pour aff. symb. 2D: no; Type ligne ouverture: 1; Forme ligne ouverture (or_SwingType): Courbé; Forme ligne ouverture (or_iSwingType): 1; Forme ligne ouverture (or_SlidingType): Sans; Forme ligne ouverture (or_iSlidingType): 0; Stylo ligne ouverture 2D/3D (or_opLinePen): Général - Dessin 0.12; Stylo ligne ouverture 2D/3D (or_iOpLinePen): 1; Suppl. Opt. vue pour proj. 3D: no; Afficher ligne d'ouverture: yes; Type ligne côté ouverture (or_opLineType3dIn): Ligne continue; Type ligne côté ouverture (or_iOpLineType3dIn): 0; Type ligne côté opposé (or_opLineType3dOut): Ligne continue; Type ligne côté opposé (or_iOpLineType3dOut): 0; Orient. ligne (or_oplineStyle): Poignée; Orient. ligne (or_iOplineStyle): 1; Stylo ligne non coupée: Ouvertures - Général; Stylo ligne coupée: Ouvertures - Général; Stylo ligne coupée chambranle des deux côtés: Ouvertures - Général; Ligne de contour de mur (gs_wcont_line): Des deux côtés; Ligne de contour de mur (iWallContourLine): 4; Type ligne contour int. mur: 1; Type ligne contour ext. mur: 1; Type ligne contour int. mur masqué: 26; Type ligne contour ext. mur masqué: 26; Stylo ligne contour de mur: Ouvertures - Général; Utiliser hachures: yes; Motif de hachure cadre: Sans Trame; Stylo hachure cadre: Général - Dessin 0.12; Stylo fond de hachure cadre: Ouvertures - fonds de hachure; Motif de hachure châssis: Lame d'air; Stylo fond de châssis: Général - Dessin 0.12; Stylo fond de hachure châssis: Ouvertures - fonds de hachure; Type hachure non coupée: Sans Trame; Stylo hachure non coupée: Général - Dessin 0.12; Stylo fond de hachure non coupé: Ouvertures - fonds de hachure; Motif hachure symbole en plan: Sans Trame; Stylo hachure symbole en plan: Fond - Couleur 1; Stylo fond hachure symbole plan: Fond - Couleur 1; Stylo appui 3D et non coupé: Général - Dessin 0.12; Stylo contour appui en Coupe: Ouvertures - Général; Motif hachure appui en Coupe: Lame d'air; Stylo hachure d'appui en Coupe: Ouvertures - Général; Stylo fond hachure appui Coupe: Ouvertures - fonds de hachure; Stylo contour isolation coupe: Ouvertures - Général; Motif hachure isolation Coupe: Sans Trame; Stylo hachure isolation Coupe: Général - Dessin 0.12; Stylo fond hachure isol. Coupe: Ouvertures - fonds de hachure; Stylo latte 3D et non coupé: Général - Dessin 0.12; Stylo contour latte en Coupe: Général - Dessin 0.12; Motif hachure tablette en Coupe: Lame d'air; Stylo hachure tablette en Coupe: Fond - Couleur 1; Stylo fond hach. tablette Coupe: Fond - Couleur 1; Type hachure chambr. intérieur: Lame d'air; Stylo hachure chambr. int.: Fond - Couleur 1; Stylo fond hachure chambr. int.: Fond - Couleur 1; Type hachure chambr. ext.: Lame d'air; Stylo hachure chambr. ext.: Fond - Couleur 1; Stylo fond hachure chambr. ext.: Fond - Couleur 1; Motif de hachure arche coupe: Sans Trame; Stylo hachure en coupe d'arche: Fond - Couleur 1; Stylo fond hachure appui arche Coupe: Fond - Couleur 1; Motif de hachure de Coupe de Profil de ventilation: Lame d'air; Stylo de hachure de Coupe de Profil de ventilation: Fond - Couleur 1; Stylo de fond de hachure de Coupe de Profil de ventilation: Fond - Couleur 1; Type de ligne symbole volet: 1; Stylo ligne coupée volet: Général - Dessin 0.12; Type hachure coupée volet: Sans Trame; Stylo hachure coupée volet: Général - Dessin 0.12; Stylo fond hachure coupé volet: Ouvertures - fonds de hachure; Motif de hachure d'isolation de volet: Dallage; Stylo de hachure d'isolation de volet: Général - Dessin 0.12; Stylo de fond d'isolation de volet: Fond de fenêtre; Jonction éléments cadree: 2; Stylo cadre: Ouvertures - Général; Stylo châssis: Ouvertures - Général; Stylo vitrage: Ouvertures - Général; Stylo linteau: Murs - Général; Ombre: yes; Surfaces de fenêtre uniformes: no; Cadre extérieur: _Men ext_RAL9007; Cadre intérieur: _Men ext_RAL9007; Châssis extérieur: _Men ext_RAL9007; Châssis intérieur: _Men ext_RAL9007; Persiennes: _Men ext_RAL9007; Vitrage (gs_glass_mat): _Verre clair (rapide); Grille extérieure: _Men ext_RAL9007; Grille intérieure: _Men ext_RAL9007; Panneau solide extérieur: _Men ext_RAL9007; Panneau solide intérieur: _Men ext_RAL9007; Surfaces uniformes de chambranle: yes; Chambranle intérieur: _Men ext_RAL9007; Chambranle extérieur (gs_trim_out_mat): _Men ext_RAL9007; Profil Ventilation: _Métal BAVETTE; Panneau volet: _Men ext_RAL9007; Cadre panneau volet: _Men ext_RAL9007; Rail volet roulant: _Men ext_RAL9007; Boîte store vénitien: _Métal - Acier inoxydable; Segments store vénitien: _Peinture - Blanc brillant; Rail volet coulissant: _Métal - Acier inoxydable; Appui (gs_sill_mat): _Métal BAVETTE; Mortier appui briques: _Enduit - Blanc nature; Tablette (gs_board_mat): _Men ext_RAL9007; Brique linteau: _Coupe3D_; Mortier linteau: _Enduit - Blanc nature; Clef de voûte linteau: _Pierre - Grès 01; Niche: _Mur int Hall; Surface poteau d'angle: _Men ext_RAL9007; Direction d'ouverture: 1; Afficher comme imposte: no; Stylo ligne tête de mur: Général - Dessin 0.12; Type de ligne tête de mur: 21; Prof. linteau sur symbole: no; Type ligne symbole prof. linteau: 21; Stylo symbole prof. linteau: Texte d'annotation - Général; Fenêtre appartient à Zone vers laquelle elle donne: no; Coût: 0; Surface vitrée totale (gs_list_glassarea_tmp): 0; Supplanter surface vitrée: no; Périmètre total vitrage: 0; Performance air libre (mm2/l/m): 0; Type de groupe (FM_Type): Objets par défaut; Type de groupe (iFMType): 1; Poids de l'objet: 0; Unité poids de l'objet: kg; Définition d'orientation de fenêtre: 0; Opération IFC (ifc_optypestr): Vertical double; Opération IFC (ifc_optype): 2; Angle ouverture volet: 180 deg; Style lignes d'ouverture: 1
AC_Pset_RenovationAndPhasing - Renovation Status: Existing
Name | In | ID de l'élément = Lien et ID d'élément | Nom de zone liée = À Zone | Nom d'étage d'implantation | Numéro d'étage d'implantation | Surfaces (Toutes) | Position | Dimensions ébrasure = Dimensions trou mur = Dimensions unité = Taille L x H nominale | Taille L x H x E nominale | Panneaux horizontaux (gs_PanesConfig) | Panneaux horizontaux (gs_iPanesConfig) | Châssis uniformes | Type d'ouverture châssis princ. 1 | Type d'ouverture (gs_optype_m_05) | Angle appui (deg) | Stylo ligne non coupée 3D/Coupe | Boîte volet roulant = Lames volet roulant | Surface vitrée totale (gs_list_glassarea)
2 x Fen classe-200 | RDC | Fen classe-200 | Salle de classe 1 | RDC | 0 | _Men ext_RAL9007; _Verre clair (rapide); _Métal BAVETTE; _Classe 1-RAL2000; _Enduit minéral blanc | Non défini | 200×150 | 200×150×36 | Panneaux uniformes | 1 | no | Bascule | 5 | 0 | classe1 | _Classe 1-RAL2000 | 2.236
2 x Fen classe-200 | RDC | Fen classe-200 | Salle de classe 2 | RDC | 0 | _Men ext_RAL9007; _Verre clair (rapide); _Métal BAVETTE; _Enduit minéral blanc; _Classe 2-RAL5018 | Non défini | 200×150 | 200×150×36 | Panneaux uniformes | 1 | no | Bascule | 5 | 0 | classe2 | _Classe 2-RAL5018 | 2.236
2 x Fen classe-200 | RDC | Fen classe-200 | Salle de classe 3 | RDC | 0 | _Men ext_RAL9007; _Verre clair (rapide); _Métal BAVETTE; _Enduit minéral blanc; _Classe 3-RAL3003 | Non défini | 200×150 | 200×150×36 | Panneaux uniformes | 1 | yes | Bascule | 5 | 0 | classe3 | _Classe 3-RAL3003 | 2.236
2 x Fen classe-200 | RDC | Fen classe-200 | Salle de classe 4 | RDC | 0 | _Men ext_RAL9007; _Verre clair (rapide); _Métal BAVETTE; _Enduit minéral blanc; _Classe 4-RAL6026 | Non défini | 200×150 | 200×150×36 | Panneaux uniformes | 1 | yes | Bascule | 5 | 0 | classe4 | _Classe 4-RAL6026 | 2.236
2 x Fen classe-200 | RDC | Fen classe-200 | Salle de classe 5 | RDC | 0 | _Men ext_RAL9007; _Verre clair (rapide); _Métal BAVETTE; _Enduit minéral blanc; _Classe 5-RAL4006 | Non défini | 200×150 | 200×150×36 | Panneaux uniformes | 1 | yes | Bascule | 5 | 0 | classe5 | _Classe 5-RAL4006 | 2.236
2 x Fen classe-200 | R+1 | Fen classe-200 | Salle de classe 9 | R+1 | 1 | _Men ext_RAL9007; _Verre clair (rapide); _Métal BAVETTE; _Enduit minéral blanc; _Classe 4-RAL6026 | Extérieur | 200×150 | 200×150×36 | Panneaux uniformes | 1 | yes | Bascule | 5 | 0 | classe4 | _Classe 4-RAL6026 | 2.236
2 x Fen classe-200 | R+1 | Fen classe-200 | Salle de classe 10 | R+1 | 1 | _Men ext_RAL9007; _Verre clair (rapide); _Métal BAVETTE; _Enduit minéral blanc; _Classe 5-RAL4006 | Extérieur | 200×150 | 200×150×36 | Panneaux uniformes | 1 | yes | Bascule | 5 | 0 | classe5 | _Classe 5-RAL4006 | 2.236
2 x Fen classe-150 | R+1 | Fen classe-150 | Salle de classe 10 | R+1 | 1 | _Men ext_RAL9007; _Verre clair (rapide); _Métal BAVETTE; _Enduit minéral blanc; _Classe 5-RAL4006 | Extérieur | 150×150 | 150×150×36 | Asymétrique | 3 | yes | Châssis fixe | 2 | 0 | classe5 | _Classe 5-RAL4006 | 1.521
2 x Fen classe-150 | R+1 | Fen classe-150 | Salle de classe 9 | R+1 | 1 | _Men ext_RAL9007; _Verre clair (rapide); _Métal BAVETTE; _Enduit minéral blanc; _Classe 4-RAL6026 | Extérieur | 150×150 | 150×150×36 | Asymétrique | 3 | yes | Châssis fixe | 2 | 0 | classe4 | _Classe 4-RAL6026 | 1.521
2 x Fen classe-200 | R+1 | Fen classe-200 | Salle de classe 6 | R+1 | 1 | _Men ext_RAL9007; _Verre clair (rapide); _Métal BAVETTE; _Classe 1-RAL2000; _Enduit minéral blanc | Non défini | 200×150 | 200×150×36 | Panneaux uniformes | 1 | no | Bascule | 5 | 0 | classe1 | _Classe 1-RAL2000 | 2.236
2 x Fen classe-200 | R+1 | Fen classe-200 | Salle de classe 7 | R+1 | 1 | _Men ext_RAL9007; _Verre clair (rapide); _Métal BAVETTE; _Enduit minéral blanc; _Classe 2-RAL5018 | Extérieur | 200×150 | 200×150×36 | Panneaux uniformes | 1 | no | Bascule | 5 | 0 | classe2 | _Classe 2-RAL5018 | 2.236
2 x Fen classe-150 | R+1 | Fen classe-150 | Salle de classe 7 | R+1 | 1 | _Men ext_RAL9007; _Verre clair (rapide); _Métal BAVETTE; _Enduit minéral blanc; _Classe 2-RAL5018 | Extérieur | 150×150 | 150×150×36 | Asymétrique | 3 | yes | Châssis fixe | 2 | 0 | classe2 | _Classe 2-RAL5018 | 1.521
2 x Fen classe-150 | R+1 | Fen classe-150 | Salle de classe 6 | R+1 | 1 | _Men ext_RAL9007; _Verre clair (rapide); _Métal BAVETTE; _Classe 1-RAL2000; _Enduit minéral blanc | Extérieur | 150×150 | 150×150×36 | Asymétrique | 3 | yes | Châssis fixe | 2 | 0 | classe1 | _Classe 1-RAL2000 | 1.521
2 x Fen classe-200 | R+1 | Fen classe-200 | Salle de classe 8 | R+1 | 1 | _Men ext_RAL9007; _Verre clair (rapide); _Métal BAVETTE; _Enduit minéral blanc; _Classe 3-RAL3003 | Extérieur | 200×150 | 200×150×36 | Panneaux uniformes | 1 | yes | Bascule | 5 | 0 | classe3 | _Classe 3-RAL3003 | 2.236
Fen classe-150 | R+1 | Fen classe-150 | Salle de classe 8 | R+1 | 1 | _Men ext_RAL9007; _Verre clair (rapide); _Métal BAVETTE; _Enduit minéral blanc; _Classe 3-RAL3003 | Extérieur | 150×150 | 150×150×36 | Asymétrique | 3 | yes | Châssis fixe | 2 | 0 | classe3 | _Classe 3-RAL3003 | 1.521
Fen classe-150 | R+1 | Fen classe-150 | Salle de classe 8 | R+1 | 1 | _Men ext_RAL9007; _Verre clair (rapide); _Métal BAVETTE; _Enduit minéral blanc; _Classe 3-RAL3003 | Extérieur | 150×150 | 150×150×36 | Asymétrique | 3 | yes | Châssis fixe | 2 | 2 | classe3 | _Classe 3-RAL3003 | 1.521

# IfcBuildingElementProxy: Fenêtre horizontale à châssis multiples 21 (11)
Material: Matériau de construction IFC
ArchiCADProperties - Nom Élément de Bibliothèque: Fenêtre horizontale à châssis multiples 21; Verrouillé: no; Type d'élément: Fenêtre; État de rénovation: Existant; Affichage sur filtre de rénovation: Tous les filtres appropriés; Fonction structurelle: Non défini; Nom élément de bibliothèque d'ouverture: Fenêtre horizontale à châssis multiples 21
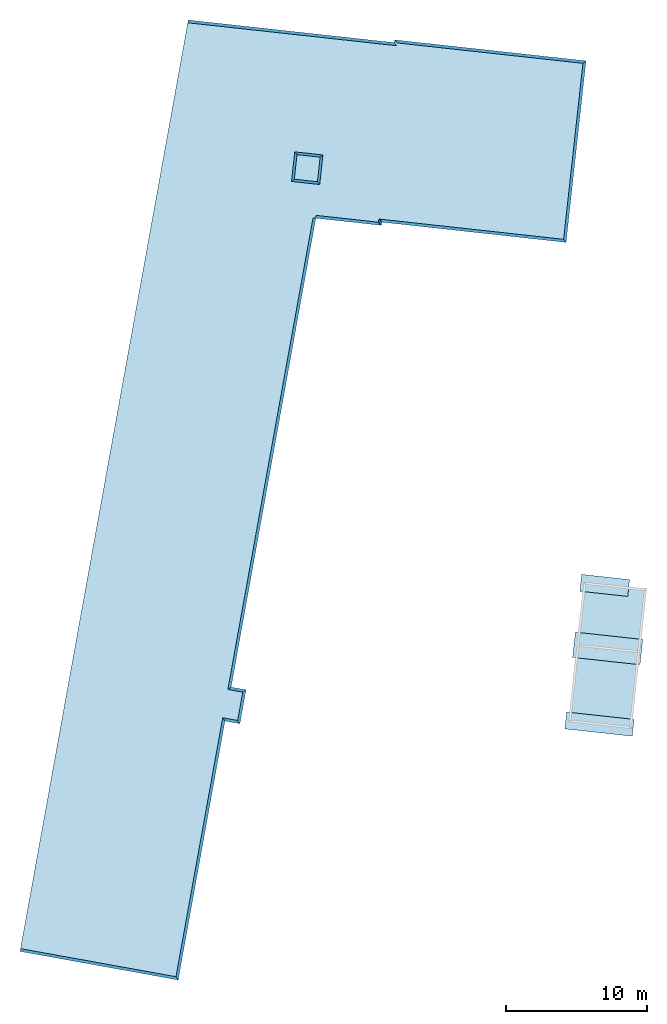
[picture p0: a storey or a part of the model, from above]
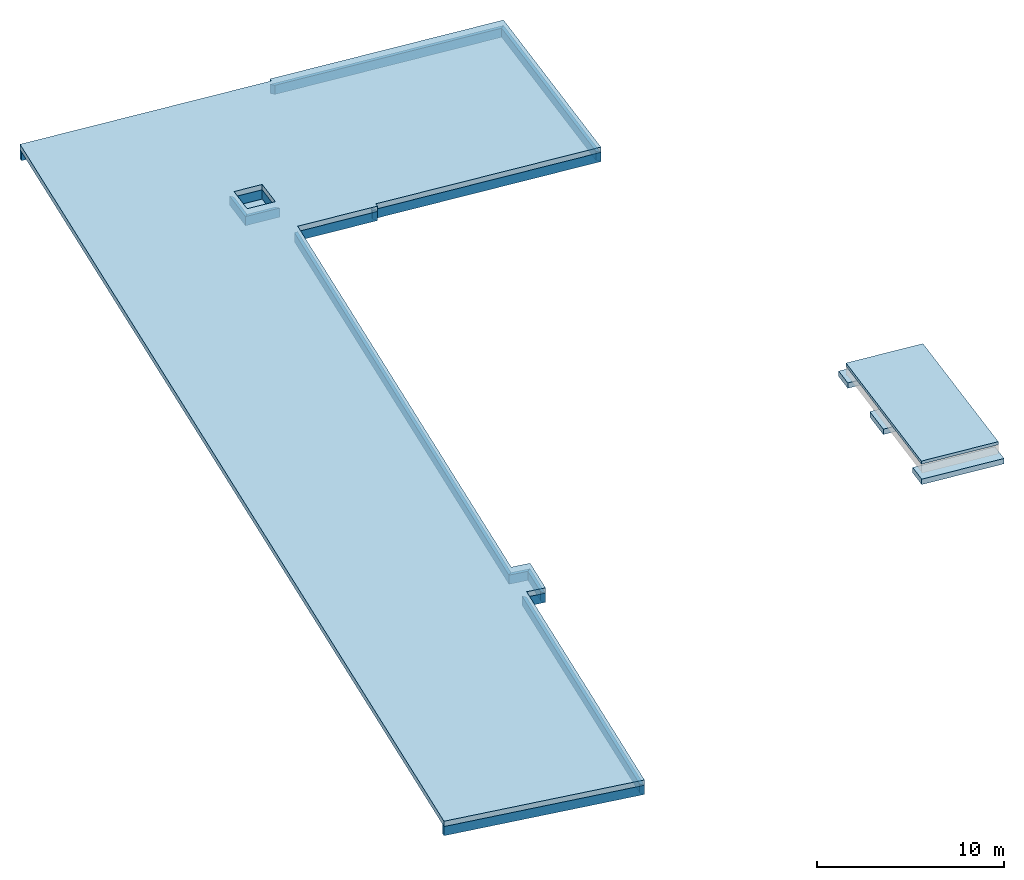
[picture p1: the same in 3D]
Properties of the parts of a building model (IFC2X3), part 2 of 10

# IfcBuildingElementProxy: Fenêtre horizontale à châssis multiples 21 (11)
AC_Pset_Fenêtre_horizontale_à_châssis_multiples_21 - Contours Mur (0-Sans,1-Tout,2-Côté,3-Longueur): 0; Point ch.0-Non,1-2D,2-3D,3-Tous: 3; Option affichage en plan: 3; Angle de position baie: 0 deg; Division de surface du trou courbe dans murs courbes: no; Afficher points chauds 2D en 3D: yes; Type de mur: 1; Position ancre ébrasuer: 1; Fonction de debug Fenêtre Angle: no; Placement (1=Angle, 0=Centre): no; Basculer: no; Démolition / Nouvelle constr.: 1; Nouveau motif de hachure de mur: Parpaing; Nouveau stylo de hachure de mur: Général - Dessin 0.12; Nouveau stylo fond hachure mur: Fond - Couleur 1; Afficher nouv. constr. sur mur: no; Aff. param. Démolition/Nouveau: no; Fonction Fenêtre Angle: yes; Angle Murs: 90 deg; Murs connectés d'épaiss. diff.: no; Poteau d'angle: no; Coin 2: no; Angle de coin 2: 90 deg; Murs connectés d'épaiss. diff. 2: no; Coin 1: no; Angle de coin 1: 90 deg; Murs connectés d'épaiss. diff. 1: no; Type connexion angle 1: 1; Type connexion angle 2: 1; Entièrement éditable: yes; Afficher ébrasure sur symbole: 1; Niveau de détail 3D: 2; Activer niveau détail 3D: 14; Taille nominale: 0; Taille trou comme taille nominale: yes; Taille ébrasure comme nominale: no; Taille unité comme nominale: no; Transmettre taille nominale actuelle à sélection: no; Multiplier unité: no; Nombre de copies: 2; Conserver distance d'axe: yes; Direction vitrage fixe (FixGlassDir): Par direction d'ouverture; Direction vitrage fixe (FixGlassDir_m): 1; Type d'ouverture Châssis 4: Vitrage fixe; Type d'ouverture (gs_optype_m_04): 1; Type d'ouverture Châssis 5: Vitrage fixe; Type d'ouverture (gs_optype_m_05): 1; Type d'ouverture Châssis 6: Vitrage fixe; Type d'ouverture (gs_optype_m_06): 1; Type d'ouverture Châssis 7: Vitrage fixe; Type d'ouverture (gs_optype_m_07): 1; Type d'ouverture Châssis 8: Vitrage fixe; Type d'ouverture (gs_optype_m_08): 1; Type d'ouverture Châssis 9: Vitrage fixe; Type d'ouverture (gs_optype_m_09): 1; Type d'ouverture Châssis 10: Vitrage fixe; Type d'ouverture (gs_optype_m_10): 1; Type de châssis Châssis 1: Pas de grille; Type châssis (iMullionStyle_01): 1; Type de châssis Châssis 2: Pas de grille; Type châssis (iMullionStyle_02): 1; Type de châssis Châssis 3: Pas de grille; Type châssis (iMullionStyle_03): 1; Type de châssis Châssis 4: Pas de grille; Type châssis (iMullionStyle_04): 1; Type de châssis Châssis 5: Pas de grille; Type châssis (iMullionStyle_05): 1; Type de châssis Châssis 6: Pas de grille; Type châssis (iMullionStyle_06): 1; Type de châssis Châssis 7: Pas de grille; Type châssis (iMullionStyle_07): 1; Type de châssis Châssis 8: Pas de grille; Type châssis (iMullionStyle_08): 1; Type de châssis Châssis 9: Pas de grille; Type châssis (iMullionStyle_09): 1; Type châssis (iMullionStyle_10): 1; Edition point chaud de grille: yes; Position grille (MullionPosition): Les deux; Position grille (iMullionPosition): 3; Nbre de panneaux verticaux 2 Châssis 1: 2; Nbre de panneaux horizontaux 2 Châssis 1: 2; Nbre de panneaux verticaux Châssis 2: 2; Nbre de panneaux horizontaux Châssis 2: 2; Nbre de panneaux verticaux 2 Châssis 2: 2; Nbre de panneaux horizontaux 2 Châssis 2: 2; Nbre de panneaux verticaux Châssis 3: 2; Nbre de panneaux horizontaux Châssis 3: 2; Nbre de panneaux verticaux 2 Châssis 3: 2; Nbre de panneaux horizontaux 2 Châssis 3: 2; Nbre de panneaux verticaux Châssis 4: 2; Nbre de panneaux horizontaux Châssis 4: 2; Nbre de panneaux verticaux 2 Châssis 4: 2; Nbre de panneaux horizontaux 2 Châssis 4: 2; Nbre de panneaux verticaux Châssis 5: 2; Nbre de panneaux horizontaux Châssis 5: 2; Nbre de panneaux verticaux 2 Châssis 5: 2; Nbre de panneaux horizontaux 2 Châssis 5: 2; Nbre de panneaux verticaux Châssis 6: 2; Nbre de panneaux horizontaux Châssis 6: 2; Nbre de panneaux verticaux 2 Châssis 6: 2; Nbre de panneaux horizontaux 2 Châssis 6: 2; Nbre de panneaux verticaux Châssis 7: 2; Nbre de panneaux horizontaux Châssis 7: 2; Nbre de panneaux verticaux 2 Châssis 7: 2; Nbre de panneaux horizontaux 2 Châssis 7: 2; Nbre de panneaux verticaux Châssis 8: 2; Nbre de panneaux horizontaux Châssis 8: 2; Nbre de panneaux verticaux 2 Châssis 8: 2; Nbre de panneaux horizontaux 2 Châssis 8: 2; Nbre de panneaux verticaux Châssis 9: 2; Nbre de panneaux horizontaux Châssis 9: 2; Nbre de panneaux verticaux 2 Châssis 9: 2; Nbre de panneaux horizontaux 2 Châssis 9: 2; Nbre de panneaux verticaux Châssis 10: 2; Nbre de panneaux horizontaux Châssis 10: 2; Nbre de panneaux verticaux 2 Châssis 10: 2; Nbre de panneaux horizontaux 2 Châssis 10: 2; Style persiennes (iLouverStyle): 1; Angle d'ouverture persiennes: 0 deg; Chambranle extérieur (gs_trim_outside): no; Type chambr. ext. (gs_trimtype_out): Simple; Type chambr. ext. (gs_trimtype_out_int): 1; Type tête chambr. ext.: 1; Chapiteau architrave: yes; Type chapiteau architrave: 1; Chambranle inférieur extérieur: yes; Couvre surface mur ext.: yes; Largeurs uniformes de chambranle (gs_trim_outside_uniform): yes; Chambranle intérieur.: no; Type chambr. intérieur (gs_trimtype_in): Simple; Type chambr. intérieur (gs_trimtype_in_int): 1; Couvre surface mur int.: yes; Largeurs uniformes de chambranle (gs_trim_inside_uniform): yes; Dépassement appui: no; Angle appui: 3 deg; Appui courbe dans murs courbes: yes; Isolation sous appui: yes; Utiliser couche isolation mur: no; Niveau détail 3D seuil brique: 1; Tablette (gs_board_inside): no; Angle tablette: 0 deg; Tabl. courbe dans murs courbes: yes; Tableau dans murs polygonaux: 1; Aération naturelle: no; Type d'aération naturelle: 2; Châssis 2: no; Châssis 3: no; Châssis 4: no; Châssis 5: no; Châssis 6: no; Châssis 7: no; Châssis 8: no; Châssis 9: no; Châssis 10: no; Volet: no; Type volet: 1; Types volet activés: 126; Nombre de panneaux (gs_shutter_nPanels): 2; Nombre de panneaux 2: 1; Position panneau (gs_shutter_panelPos): Symétrique; Position panneau (gs_shutter_iPanelPos): 1; Hauteur volet automatique: yes; Cadre supplémentaire: no; Type de couverture (gs_slidingShutter_cover): Profil en Z; Type de couverture (gs_slidingShutter_iCover): 1; Direction articulation (gs_foldingShutter_stacking): Intérieur; Direction articulation (gs_foldingShutter_iStacking): 1; Ouvert en 3D: yes; Angle ouverture en 3D: 180 deg; Afficher symbole 2D: yes; Afficher lignes d'ouverture sur symbole: no; Type de panneau: (gs_shutPanel_type): Style 1; Type de panneau: (gs_shutPanel_iType): 1; Largeur cadre inf. différente: no; Largeur volets automatiques: yes; Angle persienne: 30 deg; Nombre trous horizontaux: 5; Nombre trous verticaux: 8; Placement volet roulant (gs_shutRoll_placement): Sur façade; Placement volet roulant (gs_shutRoll_iPlacement): 1; Type boîte (gs_shutRoll_boxType): Rectangulaire; Type boîte (gs_shutRoll_iBoxType): 1; Position rampe (gs_shutRoll_railPos): Sur revêtement; Position rampe (gs_shutRoll_iRailPos): 1; Afficher revêtement derrière parasol (gs_shutRoll_showCasingBehind): no; Isolation derrière cellule (gs_shutRoll_cutWallBehind): no; Inclure hauteur dans hauteur de trou de mur: no; Angle supérieur boîte: 10 deg; Taille boîte par défaut (gs_shutRoll_boxDefaultSize): Largeur ébrasure; Taille boîte par défaut (gs_shutRoll_iBoxDefaultSize): 1; Placement stores (gs_shutLam_placement): Fixé sur façade; Placement stores (gs_shutLam_iPlacement): 1; Isolation derrière cellule (gs_shutLam_cutWallBehind): no; Boîte ouverte: yes; Rampe: yes; Position rampe (gs_shutLam_railPos): Sur revêtement; Position rampe (gs_shutLam_iRailPos): 1; Afficher revêtement derrière parasol (gs_shutLam_showCasingBehind): no; Angle de rotation des lamelles (gs_shutLam_rotation): 45 deg; Angle de rotation des lamelles (gs_shutLam2_rotation): 45 deg; Linteau (bMasonryArch): no; Linteau (gs_masonry_arch_int): 2; Type linteau (gs_masonry_arch_structure): Stuc; Type linteau (gs_masonry_arch_structure_int): 1; Arche sur linteau: yes; Niche sous arche: yes; Angle inclinaison: 75 deg; Surface niche personnalisée: no; Type ébrasure inférieure (gs_reveal_type_bottom): Uniforme; Type ébrasure inférieure (gs_reveal_type_bottom_int): 1; Type ébrasure extérieure: Baie simple; Type ébrasure (gs_reveal_doubleOuterTypeInt): 0; Type ébrasure intérieure: Baie simple; Type ébrasure (gs_reveal_doubleInnerTypeInt): 0; Profondeur montant uniforme: yes; Côté angle 2: 20 deg; Côté angle: 20 deg; Angle côté supérieur: 20 deg; Angle côté inférieur: 20 deg; Utiliser composant finition mur: no; Tourner plâtre surface intérieure: 0; Tourner plâtre surface extérieure: 0; Peut être coté en 2D: no; Afficher en 3D: no; Type de fermeture (gs_closure_type): Pas de fermeture; Type de fermeture (gs_closure_type_int): 1; Tourner couche sur côté (gs_cavity_side): Les deux; Tourner couche sur côté (iCavityClosureSide): 1; Nbre de couches retournées: 1; Num. à partir de (gs_nTurnDir): Face extérieure; Num. à partir de (iCavityClosureTurnDir): 1; Placer fermeture sur côté 2: yes; Placer fermeture sur côté 1: yes; Placer fermeture en haut: no; Placer fermeture en bas: no; Placer fermeture sur couche: 1; Placer fermeture de côté (gs_cc_dutch_ClosureToSide): 1; Ecart à couche externe: yes; Tourner couche sur fermeture: no; Insérer bande d'isolation: yes; Afficher bande d'isolation: yes; Stylo contour (gs_penJoint): Ouvertures - Coupé non structurel; Type de ligne de contour (gs_ltJoint): 1; Motif de hachure (gs_fillJoint): Isolation polystyrène; Stylo hachure (gs_penJointFg): Général - Dessin 0.12; Stylo fond de hachure (gs_penJointBg): Eléments 2D - Dessin; Surface personnalisée: no; Stylo contour (gs_penPlug): Ouvertures - Coupé non structurel; Type de ligne de contour (gs_ltPlug): 1; Motif de hachure (gs_fillPlug): Isolation polystyrène; Stylo hachure (gs_penPlugFg): Général - Dessin 0.12; Stylo fond de hachure (gs_penPlugBg): Eléments 2D - Dessin; Côté montant édité: 1; Côté mur édité: 1; Numéro couche éditée: 1; Tourner couche: no; Considérer couches comme plâtre: no; Tourner épaiseur: 1; Orientation hachure: 1; Ligne de séparation tournant: no; Stylo ligne de séparation: Général - Dessin 0.12; Dernier côté sélectionné: no; Méthode fermeture changée auto.: no; Connexion à gauche: no; Connexion à droite: no; Connexion en haut: no; Connexion en bas: no; Incrustation allège: no; Tailles incrustation mur (gs_parapet_sizes_st): Automatique; Tailles incrustation mur (iParapetSize): 1; Cotes largeur et longueur auto: yes; Incrustation base mur à (gs_parapet_bottom_st): Etage actuel; Incrustation base mur à (iParapetBottom): 1; Afficher allège masquée: yes; Type ligne allège masquée: 1; Angle d'ouverture de Châssis 1 (openingAngle2_01): 0 deg; Angle d'ouverture de Châssis 2 (openingAngle_02): 0 deg; Angle d'ouverture de Châssis 2 (openingAngle2_02): 0 deg; Angle d'ouverture de Châssis 3 (openingAngle_03): 0 deg; Angle d'ouverture de Châssis 3 (openingAngle2_03): 0 deg; Angle d'ouverture de Châssis 4 (openingAngle_04): 0 deg; Angle d'ouverture de Châssis 4 (openingAngle2_04): 0 deg; Angle d'ouverture de Châssis 5 (openingAngle_05): 0 deg; Angle d'ouverture de Châssis 5 (openingAngle2_05): 0 deg; Angle d'ouverture de Châssis 6 (openingAngle_06): 0 deg; Angle d'ouverture de Châssis 6 (openingAngle2_06): 0 deg; Angle d'ouverture de Châssis 7 (openingAngle_07): 0 deg; Angle d'ouverture de Châssis 7 (openingAngle2_07): 0 deg; Angle d'ouverture de Châssis 8 (openingAngle_08): 0 deg; Angle d'ouverture de Châssis 8 (openingAngle2_08): 0 deg; Angle d'ouverture de Châssis 9 (openingAngle_09): 0 deg; Angle d'ouverture de Châssis 9 (openingAngle2_09): 0 deg; Angle d'ouverture de Châssis 10 (openingAngle_10): 0 deg; Angle d'ouverture de Châssis 10 (openingAngle2_10): 0 deg; Angle ouverture en 2D: 0 deg; Type ligne ouverture: 1; Forme ligne ouverture (or_SwingType): Courbé; Forme ligne ouverture (or_iSwingType): 1; Forme ligne ouverture (or_SlidingType): Sans; Forme ligne ouverture (or_iSlidingType): 0; Suppl. Opt. vue pour proj. 3D: no; Type ligne côté ouverture (or_opLineType3dIn): Ligne continue; Type ligne côté ouverture (or_iOpLineType3dIn): 0; Type ligne côté opposé (or_opLineType3dOut): Ligne continue; Type ligne côté opposé (or_iOpLineType3dOut): 0; Orient. ligne (or_oplineStyle): Poignée; Orient. ligne (or_iOplineStyle): 1; Stylo ligne non coupée: Ouvertures - Général; Stylo ligne coupée chambranle des deux côtés: Ouvertures - Général; Type ligne contour int. mur: 1; Type ligne contour ext. mur: 1; Stylo ligne contour de mur: Ouvertures - Général; Motif de hachure cadre: Sans Trame; Motif de hachure châssis: Lame d'air; Type hachure non coupée: Sans Trame; Motif hachure symbole en plan: Sans Trame; Stylo appui 3D et non coupé: Général - Dessin 0.12; Stylo contour appui en Coupe: Général - Dessin 0.12; Stylo contour isolation coupe: Général - Dessin 0.12; Motif hachure isolation Coupe: Isolation polystyrène; Stylo hachure isolation Coupe: Général - Dessin 0.12; Stylo fond hachure isol. Coupe: Fond - Couleur 1; Stylo latte 3D et non coupé: Général - Dessin 0.12; Stylo contour latte en Coupe: Général - Dessin 0.12; Motif hachure tablette en Coupe: Lame d'air; Stylo hachure tablette en Coupe: Fond - Couleur 1; Stylo fond hach. tablette Coupe: Fond - Couleur 1; Type hachure chambr. intérieur: Lame d'air; Stylo hachure chambr. int.: Fond - Couleur 1; Stylo fond hachure chambr. int.: Fond - Couleur 1; Type hachure chambr. ext.: Lame d'air; Stylo hachure chambr. ext.: Fond - Couleur 1; Stylo fond hachure chambr. ext.: Fond - Couleur 1; Stylo hachure en coupe d'arche: Fond - Couleur 1; Stylo fond hachure appui arche Coupe: Fond - Couleur 1; Motif de hachure de Coupe de Profil de ventilation: Lame d'air; Stylo de hachure de Coupe de Profil de ventilation: Fond - Couleur 1; Stylo de fond de hachure de Coupe de Profil de ventilation: Fond - Couleur 1; Type de ligne symbole volet: 1; Stylo ligne coupée volet: Général - Dessin 0.12; Stylo ligne non coupée 3D/Coupe: Général - Dessin 0.12; Stylo hachure coupée volet: Général - Dessin 0.12; Stylo fond hachure coupé volet: Fond de fenêtre; Motif de hachure d'isolation de volet: Dallage; Stylo de hachure d'isolation de volet: Général - Dessin 0.12; Stylo de fond d'isolation de volet: Fond de fenêtre; Jonction éléments cadree: 2; Stylo cadre: Ouvertures - Général; Stylo châssis: Ouvertures - Général; Stylo linteau: Murs - Général; Ombre: yes; Surfaces uniformes de chambranle: yes; Profil Ventilation: _Métal BAVETTE; Boîte volet roulant: _Métal - Acier inoxydable; Lames volet roulant: _Peinture - Blanc brillant; Rail volet roulant: _Peinture - Blanc brillant; Boîte store vénitien: _Métal - Acier inoxydable; Segments store vénitien: _Peinture - Blanc brillant; Rail volet coulissant: _Métal - Acier inoxydable; Mortier appui briques: _Enduit - Blanc nature; Brique linteau: _Coupe3D_; Mortier linteau: _Enduit - Blanc nature; Clef de voûte linteau: _Pierre - Grès 01; Niche: _Mur int Hall; Afficher comme imposte: no; Stylo ligne tête de mur: Général - Dessin 0.12; Type de ligne tête de mur: 21; Prof. linteau sur symbole: no; Type ligne symbole prof. linteau: 21; Stylo symbole prof. linteau: Texte d'annotation - Général; Fenêtre appartient à Zone vers laquelle elle donne: no; Coût: 0; Surface vitrée totale (gs_list_glassarea_tmp): 0; Supplanter surface vitrée: no; Périmètre total vitrage: 0; Performance air libre (mm2/l/m): 0; Type de groupe (FM_Type): Objets par défaut; Type de groupe (iFMType): 1; Poids de l'objet: 0; Unité poids de l'objet: kg; Définition d'orientation de fenêtre: 0; Angle ouverture volet: 180 deg; Style lignes d'ouverture: 1
AC_Pset_RenovationAndPhasing - Renovation Status: Existing
Name | In | Classification | ID de l'élément = Lien et ID d'élément | Calque | Matériau de construction / Composite / Profil / Hachure = Type Hachure = Index hachure latérale ouverture | Nom de zone liée | Nom d'étage d'implantation | Numéro d'étage d'implantation | ID de Parent | Surfaces (Toutes) | À Zone | Position | Dimensions ébrasure = Dimensions trou mur = Dimensions unité = Taille L x H nominale | Taille L x H x E nominale | Structure de Mur | Classification ARCHICAD - 21 | Trou reprend surface latérale de mur | Type de direction de mur | Type de ligne démolition = Type ligne contour int. mur masqué = Type ligne contour ext. mur masqué | Niveau de détail 2D | Nombre de panneaux (gs_panes_number) | Configuration panneaux | Panneaux horizontaux = Stylo ligne ouverture 2D/3D (or_iOpLinePen) | Largeur cadre uniforme | Châssis uniformes | Type d'ouverture Châssis 1 | Type d'ouverture (gs_optype_m_01) | Type d'ouverture Châssis 2 | Type d'ouverture (gs_optype_m_02) | Type d'ouverture Châssis 3 | Type d'ouverture (gs_optype_m_03) | Type châssis (MullionStyle_00) | Type châssis (iMullionStyle_00) | Nbre de panneaux verticaux Châssis 1 | Nbre de panneaux horizontaux Châssis 1 | Appui (gs_sill_outside) | Type d'appui/seuil | Châssis 1 | Type ébrasure (gs_reveal_type_new) | Type ébrasure (gs_reveal_type_int) | Tourner automatiquement plâtre surface intérieure = Tourner automatiquement plâtre surface extérieure | Surface = Persiennes = Chambranle intérieur = Chambranle extérieur (gs_trim_out_mat) = Panneau volet = Cadre panneau volet = Tablette (gs_board_mat) = Surface poteau d'angle | Angle d'ouverture de Châssis 1 (openingAngle_01) (deg) | Suppl. Opt. vue pour aff. symb. 2D | Stylo ligne ouverture 2D/3D (or_opLinePen) | Afficher ligne d'ouverture | Stylo ligne coupée | Ligne de contour de mur (gs_wcont_line) | Ligne de contour de mur (iWallContourLine) | Utiliser hachures | Stylo hachure cadre = Stylo fond de châssis = Stylo hachure non coupée | Stylo fond de hachure cadre = Stylo fond de hachure châssis | Stylo fond de hachure non coupé | Stylo hachure symbole en plan | Stylo fond hachure symbole plan | Motif hachure appui en Coupe | Stylo hachure d'appui en Coupe | Stylo fond hachure appui Coupe | Motif de hachure arche coupe = Type hachure coupée volet | Stylo vitrage | Surfaces de fenêtre uniformes | Cadre extérieur = Cadre intérieur | Châssis extérieur = Châssis intérieur | Vitrage (gs_glass_mat) | Grille extérieure = Grille intérieure = Panneau solide extérieur = Panneau solide intérieur | Appui (gs_sill_mat) | Direction d'ouverture | Surface vitrée totale (gs_list_glassarea) | Opération IFC (ifc_optypestr) | Opération IFC (ifc_optype)
Fen bureau | RDC | Element de construction non défini (Classification Archicad); Fenêtre (Classification ARCHICAD) | Fen bureau | 10_M x baseGO__ | Sans Trame | Activités RASED | RDC | 0 | M ext-Ouest | _Men ext_RAL9007; _Verre clair (rapide); _Métal BAVETTE | Activités RASED | Non défini | 290×70 | 290×70×36 | _M ext 18 +18 gris | Fenêtre | yes | 0 | 4 | 1 | 3 | Panneaux uniformes | 1 | no | yes | Accrochée par le bas | 7 | Accrochée par le bas | 7 | Accrochée par le bas | 7 | Pas de grille | 1 | 2 | 1 | yes | 11 | yes | Baie simple | 2 | yes | _Men ext_RAL9007 | 0 | no | Général - Dessin 0.12 | yes | Ouvertures - Général | Des deux côtés | 4 | no | Général - Dessin 0.12 | Transparent | Transparent | Fond - Couleur 1 | Fond - Couleur 1 | Sans Trame | Général - Dessin 0.12 | Transparent | Sans Trame | Ouvertures - Général | yes | _Men ext_RAL9007 | _Men ext_RAL9007 | _Verre clair (rapide) | _Men ext_RAL9007 | _Métal BAVETTE | 1 | 1.22 | Triple vertical | 4
Fen bureau | RDC | Element de construction non défini (Classification Archicad); Fenêtre (Classification ARCHICAD) | Fen bureau | 10_M x baseGO__ | Sans Trame | Bureau RASED | RDC | 0 | M ext-Ouest | _Men ext_RAL9007; _Verre clair (rapide); _Métal BAVETTE | Bureau RASED | Non défini | 290×70 | 290×70×36 | _M ext 18 +18 gris | Fenêtre | yes | 0 | 4 | 1 | 3 | Panneaux uniformes | 1 | no | yes | Accrochée par le bas | 7 | Accrochée par le bas | 7 | Accrochée par le bas | 7 | Pas de grille | 1 | 2 | 1 | yes | 11 | yes | Baie simple | 2 | yes | _Men ext_RAL9007 | 0 | no | Général - Dessin 0.12 | yes | Ouvertures - Général | Des deux côtés | 4 | no | Général - Dessin 0.12 | Transparent | Transparent | Fond - Couleur 1 | Fond - Couleur 1 | Sans Trame | Général - Dessin 0.12 | Transparent | Sans Trame | Ouvertures - Général | yes | _Men ext_RAL9007 | _Men ext_RAL9007 | _Verre clair (rapide) | _Men ext_RAL9007 | _Métal BAVETTE | 1 | 1.22 | Triple vertical | 4
Baie salle-pluri-Est | RDC | Element de construction non défini (Classification Archicad); Fenêtre (Classification ARCHICAD) | Baie salle-pluri-Est | 10_M x baseGO__ | Sans Trame | Salle plurivalente | RDC | 0 | M ext pluri-Est | _Men ext_RAL9007; _Verre clair (rapide) | Salle plurivalente | Non défini | 630×240 | 630×240×56 | _M ext pluri Est | Fenêtre | yes | 1 | 4 | 1 | 6 | Panneaux uniformes | 1 | yes | yes | Vitrage fixe | 1 | Vitrage fixe | 1 | Vitrage fixe | 1 | A carreaux | 2 | 4 | 1 | no | 11 | yes | Baie simple | 2 | yes | _Men ext_RAL9007 | 0 | yes | Général - Dessin 0.12 | yes | Ouvertures - Général | Des deux côtés | 4 | no | Général - Dessin 0.12 | Transparent | Transparent | Fond - Couleur 1 | Fond - Couleur 1 | Sans Trame | Général - Dessin 0.12 | Transparent | Sans Trame | Ouvertures - Général | yes | _Men ext_RAL9007 | _Men ext_RAL9007 | _Verre clair (rapide) | _Men ext_RAL9007 | _Métal BAVETTE | 1 | 11.6944 | Autre | 10
Bandeau BlocSanit | RDC | Element de construction non défini (Classification Archicad); Fenêtre (Classification ARCHICAD) | Bandeau BlocSanit | 10_M x baseGO__ | Hachure solide |  | RDC | 0 | M-Ext_BlocSanit | _Men ext_RAL9007; _Transp - Verre |  | Non défini | 590×45 | 590×45×30 | _M ext 18 +12 | Fenêtre | yes | 0 | 37 | 1 | 5 | Asymétrique | 3 | no | yes | Vitrage fixe | 1 | Vitrage fixe | 1 | Vitrage fixe | 1 | Pas de grille | 1 | 2 | 2 | yes | 11 | no | Baie simple | 2 | yes | _Bois - Pin granuleux horizontal | 30 | no | Ouvertures - Général | yes | Ouvertures - Coupé structurel | Des deux côtés | 4 | no | Ouvertures - Hachures coupées | Fond - Couleur 1 | Fond - Couleur 1 | Fond - Couleur 1 | Fond - Couleur 1 | Lame d'air | Fond - Couleur 1 | Fond - Couleur 1 | Isolation - Panneau rigide | Eléments 2D - Général | no | _Men ext_RAL9007 | _Bois - Acajou horizontal | _Transp - Verre | _Bois - Pin granuleux horizontal | _Men ext_RAL9007 | 0 | 1.911 | Autre | 10
Fen vide-sur-hall-Est | R+1 | Element de construction non défini (Classification Archicad); Fenêtre (Classification ARCHICAD) | Fen vide-sur-hall-Est | 10_M x baseGO__ | Sans Trame (3) |  | R+1 | 1 | M ext-hall-Est | _Verre clair (rapide); _Métal BAVETTE; _chassis int |  | Extérieur | 230×122 | 230×122×36 | _M ext 18 +18 gris | Fenêtre | yes | 1 | 4 | 1 | 2 | Panneaux uniformes | 1 | yes | yes | Vitrage fixe | 1 | Accrochée par le bas | 7 | Vitrage fixe | 1 | Pas de grille | 1 | 2 | 1 | yes | 11 | yes | Baie simple | 2 | yes | _Men ext_RAL9007 | 0 | yes | Général - Dessin 0.12 | yes | Ouvertures - Général | Intérieur | 2 | yes | Général - Dessin 0.12 | Transparent | Général - fonds de hachures | Fond - Couleur 1 | Fond - Couleur 1 | Sans Trame | Général - Dessin 0.12 | Transparent | Sans Trame | Ouvertures - Général | yes | _chassis int | _chassis int | _Verre clair (rapide) | _chassis int | _Métal BAVETTE | 1 | 2.0145 | Vertical double | 2
Baie vide-sur-hall-Est | R+1 | Element de construction non défini (Classification Archicad); Fenêtre (Classification ARCHICAD) | Baie vide-sur-hall-Est | 10_M x baseGO__ | Sans Trame (3) |  | R+1 | 1 | M ext-hall-Est | _Men ext_RAL9007; _Verre clair (rapide); _Métal BAVETTE |  | Extérieur | 680×122 | 680×122×36 | _M ext 18 +18 gris | Fenêtre | yes | 1 | 4 | 1 | 4 | Panneaux uniformes | 1 | yes | yes | Vitrage fixe | 1 | Vitrage fixe | 1 | Vitrage fixe | 1 | Pas de grille | 1 | 2 | 1 | yes | 11 | yes | Baie simple | 2 | yes | _Men ext_RAL9007 | 0 | yes | Général - Dessin 0.12 | yes | Ouvertures - Général | Intérieur | 2 | yes | Général - Dessin 0.12 | Transparent | Général - fonds de hachures | Fond - Couleur 1 | Fond - Couleur 1 | Sans Trame | Général - Dessin 0.12 | Transparent | Sans Trame | Ouvertures - Général | yes | _Men ext_RAL9007 | _Men ext_RAL9007 | _Verre clair (rapide) | _Men ext_RAL9007 | _Métal BAVETTE | 1 | 6.87475 | Autre | 10
Fen vide-sur-hall-Est | R+1 | Element de construction non défini (Classification Archicad); Fenêtre (Classification ARCHICAD) | Fen vide-sur-hall-Est | 10_M x baseGO__ | Sans Trame (3) |  | R+1 | 1 | M ext-hall-Est | _Men ext_RAL9007; _Verre clair (rapide); _Métal BAVETTE |  | Extérieur | 230×122 | 230×122×36 | _M ext 18 +18 gris | Fenêtre | yes | 1 | 4 | 1 | 2 | Panneaux uniformes | 1 | yes | yes | Accrochée par le bas | 7 | Vitrage fixe | 1 | Vitrage fixe | 1 | Pas de grille | 1 | 2 | 1 | yes | 11 | yes | Baie simple | 2 | yes | _Men ext_RAL9007 | 0 | yes | Général - Dessin 0.12 | yes | Ouvertures - Général | Intérieur | 2 | yes | Général - Dessin 0.12 | Transparent | Général - fonds de hachures | Fond - Couleur 1 | Fond - Couleur 1 | Sans Trame | Général - Dessin 0.12 | Transparent | Sans Trame | Ouvertures - Général | yes | _Men ext_RAL9007 | _Men ext_RAL9007 | _Verre clair (rapide) | _Men ext_RAL9007 | _Métal BAVETTE | 1 | 2.0145 | Vertical double | 2
45 | R+1 | Element de construction non défini (Classification Archicad); Porte (Classification ARCHICAD) | 45 | 10_M refendGO__ | Sans Trame (3) | Salle de réunion (maîtres) | R+1 | 1 | M refend | _Verre clair (rapide); _Mur int Hall |  | Intérieur | 596×150 | 596×150×18 | _BA banché RAL9007 | Porte | no | 0 | 4 | 4 | 5 | Panneaux uniformes | 1 | no | no | Vitrage fixe | 1 | Vitrage fixe | 1 | Vitrage fixe | 1 | Pas de grille | 1 | 2 | 2 | no | 1 | yes | Pas d'ébrasure - arête | 1 | yes | _Men ext_RAL9007 | 0 | yes | Général - Dessin 0.12 | yes | Ouvertures - Général | Des deux côtés | 4 | yes | Général - Dessin 0.12 | Transparent | Transparent | Général - Dessin 0.12 | Transparent | Lame d'air | Fond - Couleur 1 | Fond - Couleur 1 | Sans Trame | Ouvertures - Général | no | _Mur int Hall | _Men ext_RAL9007 | _Verre clair (rapide) | _Men ext_RAL9007 | _Men ext_RAL9007 | 1 | 7.51938 | Autre | 10 | Description: réunion; Pset_FireRatingProperties - FireResistanceRating: CF 1/2H; ArchiCADProperties - De Zone: Salle de réunion (maîtres); Résistance au feu: CF 1/2H; AC_Pset_Fenêtre_horizontale_à_châssis_multiples_21 - Degré de protection au feu: CF 1/2H
44 | R+1 | Element de construction non défini (Classification Archicad); Porte (Classification ARCHICAD) | 44 | 10_M refendGO__ | Sans Trame (3) | Salle de réunion (maîtres) | R+1 | 1 | M refend | _Verre clair (rapide); _Mur int Hall | Salle de réunion (maîtres) | Intérieur | 357×120 | 357×120×18 | _BA banché RAL9007 | Porte | yes | 0 | 4 | 4 | 4 | Panneaux uniformes | 1 | no | no | Vitrage fixe | 1 | Vitrage fixe | 1 | Vitrage fixe | 1 | Pas de grille | 1 | 2 | 2 | no | 1 | yes | Pas d'ébrasure - arête | 1 | yes | _Men ext_RAL9007 | 0 | yes | Général - Dessin 0.12 | yes | Ouvertures - Général | Des deux côtés | 4 | yes | Général - Dessin 0.12 | Transparent | Transparent | Général - Dessin 0.12 | Transparent | Lame d'air | Fond - Couleur 1 | Fond - Couleur 1 | Sans Trame | Ouvertures - Général | no | _Mur int Hall | _Men ext_RAL9007 | _Verre clair (rapide) | _Men ext_RAL9007 | _Men ext_RAL9007 | 0 | 3.41264 | Autre | 10 | Description: réunion; Pset_FireRatingProperties - FireResistanceRating: CF 1/2H; ArchiCADProperties - Résistance au feu: CF 1/2H; AC_Pset_Fenêtre_horizontale_à_châssis_multiples_21 - Degré de protection au feu: CF 1/2H
Baie couloir | R+1 | Element de construction non défini (Classification Archicad); Fenêtre (Classification ARCHICAD) | Baie couloir | 10_M x baseGO__ | Sans Trame (3) | Circulation 3 | R+1 | 1 | M ext entretien-Est | _Men ext_RAL9007; _Verre clair (rapide); _Métal BAVETTE | Circulation 3 | Extérieur | 815×160 | 815×160×36 | _M ext 18 +18 MILIEU | Fenêtre | yes | 0 | 4 | 1 | 7 | Panneaux uniformes | 1 | no | yes | Vitrage fixe | 1 | Vitrage fixe | 1 | Vitrage fixe | 1 | Pas de grille | 1 | 2 | 2 | yes | 11 | yes | Baie simple | 2 | yes | _Men ext_RAL9007 | 0 | no | Général - Dessin 0.12 | no | Ouvertures - Général | Des deux côtés | 4 | no | Général - Dessin 0.12 | Transparent | Transparent | Général - Dessin 0.12 | Transparent | Sans Trame | Général - Dessin 0.12 | Transparent | Sans Trame | Ouvertures - Général | yes | _Men ext_RAL9007 | _Men ext_RAL9007 | _Verre clair (rapide) | _Men ext_RAL9007 | _Métal BAVETTE | 1 | 11.4074 | Autre | 10
43 | R+1 | Element de construction non défini (Classification Archicad); Porte (Classification ARCHICAD) | 43 | 20_Cloison________ | Sans Trame (3) | Salle de réunion (maîtres) | R+1 | 1 | Clois reunion | _Verre clair (rapide); _Mur int Hall | Salle de réunion (maîtres) | Intérieur | 285×120 | 285×120×10 | _Cloison 10cm | Porte | yes | 0 | 4 | 4 | 3 | Panneaux uniformes | 1 | no | no | Vitrage fixe | 1 | Vitrage fixe | 1 | Vitrage fixe | 1 | Pas de grille | 1 | 2 | 2 | no | 1 | yes | Pas d'ébrasure - arête | 1 | no | _Men ext_RAL9007 | 0 | yes | Général - Dessin 0.12 | yes | Ouvertures - Général | Des deux côtés | 4 | yes | Général - Dessin 0.12 | Transparent | Transparent | Général - Dessin 0.12 | Transparent | Lame d'air | Fond - Couleur 1 | Fond - Couleur 1 | Sans Trame | Ouvertures - Général | no | _Mur int Hall | _Men ext_RAL9007 | _Verre clair (rapide) | _Men ext_RAL9007 | _Men ext_RAL9007 | 0 | 2.7468 | Triple vertical | 4 | Description: réunion; Pset_FireRatingProperties - FireResistanceRating: CF 1/2H; ArchiCADProperties - Résistance au feu: CF 1/2H; AC_Pset_Fenêtre_horizontale_à_châssis_multiples_21 - Degré de protection au feu: CF 1/2H

# IfcBuildingElementProxy: Fenêtre ronde 21, oeil-de-boeuf
In: RDC
Classification: Element de construction non défini (Classification Archicad); Fenêtre (Classification ARCHICAD); Material: Matériau de construction IFC
ArchiCADProperties - ID de l'élément: oeil-de-boeuf; Lien et ID d'élément: oeil-de-boeuf; Calque: 10_M x baseGO__; Nom Élément de Bibliothèque: Fenêtre ronde 21; Matériau de construction / Composite / Profil / Hachure: Sans Trame; Type Hachure: Sans Trame; Nom de zone liée: Local entretien; Verrouillé: no; Nom d'étage d'implantation: RDC; Numéro d'étage d'implantation: 0; Type d'élément: Fenêtre; ID de Parent: M ext entretien-Est; Surfaces (Toutes): _Men ext_RAL9007; _Verre clair (rapide); De Zone: Local entretien; Position: Non défini; État de rénovation: Existant; Affichage sur filtre de rénovation: Tous les filtres appropriés; Fonction structurelle: Non défini; Dimensions ébrasure: 120×120; Dimensions trou mur: 120×120; Dimensions unité: 120×120; Taille L x H nominale: 120×120; Taille L x H x E nominale: 120×120×42; Structure de Mur: _M ext bard. 6+18+18 gris; Nom élément de bibliothèque d'ouverture: Fenêtre ronde 21; Index hachure latérale ouverture: Sans Trame; Classification ARCHICAD - 21: Fenêtre
AC_Pset_Fenêtre_ronde_21 - Contours Mur (0-Sans,1-Tout,2-Côté,3-Longueur): 0; Point ch.0-Non,1-2D,2-3D,3-Tous: 3; Option affichage en plan: 3; Angle de position baie: 0 deg; Trou reprend surface latérale de mur: yes; Division de surface du trou courbe dans murs courbes: no; Afficher points chauds 2D en 3D: yes; Type de mur: 1; Type de direction de mur: 1; Position ancre ébrasuer: 1; Basculer: no; Démolition / Nouvelle constr.: 1; Nouveau motif de hachure de mur: Parpaing; Nouveau stylo de hachure de mur: Général - Dessin 0.12; Nouveau stylo fond hachure mur: Fond - Couleur 1; Afficher nouv. constr. sur mur: no; Type de ligne démolition: 4; Aff. param. Démolition/Nouveau: no; Entièrement éditable: yes; Niveau de détail 2D: 2; Afficher ébrasure sur symbole: 1; Niveau de détail 3D: 2; Activer niveau détail 3D: 14; Taille nominale: 0; Taille trou comme taille nominale: yes; Taille ébrasure comme nominale: no; Taille unité comme nominale: no; Transmettre taille nominale actuelle à sélection: no; Châssis uniformes: no; Direction vitrage fixe (FixGlassDir): Par direction d'ouverture; Direction vitrage fixe (FixGlassDir_m): 1; Type d'opération châssis princ.: Vitrage fixe; Type d'ouverture: 1; Type châssis (MullionStyle_00): Pas de grille; Type châssis (iMullionStyle_00): 1; Type châssis (MullionStyle_01): Pas de grille; Type châssis (iMullionStyle_01): 1; Position grille (MullionPosition): Les deux; Position grille (iMullionPosition): 3; Nombre panneaux verticalement: 3; Nombre panneaux horizontalement: 3; Nombre panneaux verticalement 2: 2; Nombre panneaux horizontalement 2: 2; Chambranle extérieur (gs_trim_outside): no; Type chambr. ext. (gs_trimtype_out): Simple; Type chambr. ext. (gs_trimtype_out_int): 1; Largeurs uniformes de chambranle (gs_trim_outside_uniform): no; Chambranle intérieur.: yes; Type chambr. intérieur (gs_trimtype_in): Simple; Type chambr. intérieur (gs_trimtype_in_int): 1; Largeurs uniformes de chambranle (gs_trim_inside_uniform): no; Appui (gs_sill_outside): no; Dépassement appui: no; Type d'appui/seuil: 1; Angle appui: 3 deg; Appui courbe dans murs courbes: yes; Isolation sous appui: yes; Utiliser couche isolation mur: no; Niveau détail 3D seuil brique: 1; Tablette (gs_board_inside): no; Angle tablette: 0 deg; Tabl. courbe dans murs courbes: yes; Tableau dans murs polygonaux: 1; Volet: no; Type volet: 1; Types volet activés: 38; Nombre de panneaux: 2; Nombre de panneaux 2: 1; Position panneau (gs_shutter_panelPos): Symétrique; Position panneau (gs_shutter_iPanelPos): 1; Hauteur volet automatique: yes; Cadre supplémentaire: no; Type de couverture (gs_slidingShutter_cover): Profil en Z; Type de couverture (gs_slidingShutter_iCover): 1; Direction articulation (gs_foldingShutter_stacking): Intérieur; Direction articulation (gs_foldingShutter_iStacking): 1; Ouvert en 3D: yes; Angle ouverture en 3D: 180 deg; Afficher symbole 2D: yes; Afficher lignes d'ouverture sur symbole: no; Type de panneau: (gs_shutPanel_type): Style 1; Type de panneau: (gs_shutPanel_iType): 1; Largeur cadre inf. différente: no; Largeur volets automatiques: yes; Angle persienne: 30 deg; Nombre trous horizontaux: 5; Nombre trous verticaux: 8; Placement volet roulant (gs_shutRoll_placement): Sur façade; Placement volet roulant (gs_shutRoll_iPlacement): 1; Type boîte (gs_shutRoll_boxType): Rectangulaire; Type boîte (gs_shutRoll_iBoxType): 1; Position rampe (gs_shutRoll_railPos): Sur revêtement; Position rampe (gs_shutRoll_iRailPos): 1; Afficher revêtement derrière parasol (gs_shutRoll_showCasingBehind): no; Isolation derrière cellule (gs_shutRoll_cutWallBehind): no; Inclure hauteur dans hauteur de trou de mur: no; Angle supérieur boîte: 10 deg; Taille boîte par défaut (gs_shutRoll_boxDefaultSize): Largeur ébrasure; Taille boîte par défaut (gs_shutRoll_iBoxDefaultSize): 1; Placement stores (gs_shutLam_placement): Fixé sur façade; Placement stores (gs_shutLam_iPlacement): 1; Isolation derrière cellule (gs_shutLam_cutWallBehind): no; Boîte ouverte: yes; Rampe: yes; Position rampe (gs_shutLam_railPos): Sur revêtement; Position rampe (gs_shutLam_iRailPos): 1; Afficher revêtement derrière parasol (gs_shutLam_showCasingBehind): no; Angle de rotation des lamelles (gs_shutLam_rotation): 45 deg; Angle de rotation des lamelles (gs_shutLam2_rotation): 45 deg; Linteau (bMasonryArch): no; Linteau (gs_masonry_arch_int): 7; Type linteau (gs_masonry_arch_structure): Stuc; Type linteau (gs_masonry_arch_structure_int): 1; Arche sur linteau: yes; Niche sous arche: yes; Angle inclinaison: 75 deg; Surface niche personnalisée: no; Type ébrasure (gs_reveal_type_new): Pas d'ébrasure - arête; Type ébrasure (gs_reveal_type_int): 1; Type ébrasure inférieure (gs_reveal_type_bottom): Baie simple; Type ébrasure inférieure (gs_reveal_type_bottom_int): 2; Type ébrasure extérieure: Baie simple; Type ébrasure (gs_reveal_doubleOuterTypeInt): 0; Type ébrasure intérieure: Baie simple; Type ébrasure (gs_reveal_doubleInnerTypeInt): 0; Profondeur montant uniforme: yes; Côté angle 2: 20 deg; Côté angle: 20 deg; Angle côté supérieur: 20 deg; Angle côté inférieur: 20 deg; Utiliser composant finition mur: no; Tourner automatiquement plâtre surface intérieure: yes; Tourner plâtre surface intérieure: 0; Tourner automatiquement plâtre surface extérieure: yes; Tourner plâtre surface extérieure: 0; Peut être coté en 2D: no; Afficher en 3D: no; Type de fermeture (gs_closure_type): Pas de fermeture; Type de fermeture (gs_closure_type_int): 1; Tourner couche sur côté (gs_cavity_side): Les deux; Tourner couche sur côté (iCavityClosureSide): 1; Nbre de couches retournées: 1; Num. à partir de (gs_nTurnDir): Face extérieure; Num. à partir de (iCavityClosureTurnDir): 1; Placer fermeture sur côté 2: yes; Placer fermeture sur côté 1: yes; Placer fermeture en haut: no; Placer fermeture en bas: no; Placer fermeture sur couche: 1; Placer fermeture de côté (gs_cc_dutch_ClosureToSide): 1; Ecart à couche externe: yes; Tourner couche sur fermeture: no; Insérer bande d'isolation: yes; Afficher bande d'isolation: yes; Stylo contour (gs_penJoint): Ouvertures - Coupé non structurel; Type de ligne de contour (gs_ltJoint): 1; Motif de hachure (gs_fillJoint): Isolation polystyrène; Stylo hachure (gs_penJointFg): Général - Dessin 0.12; Stylo fond de hachure (gs_penJointBg): Eléments 2D - Dessin; Surface personnalisée: no; Surface: _Men ext_RAL9007; Stylo contour (gs_penPlug): Ouvertures - Coupé non structurel; Type de ligne de contour (gs_ltPlug): 1; Motif de hachure (gs_fillPlug): Isolation polystyrène; Stylo hachure (gs_penPlugFg): Général - Dessin 0.12; Stylo fond de hachure (gs_penPlugBg): Eléments 2D - Dessin; Côté montant édité: 1; Côté mur édité: 1; Numéro couche éditée: 1; Tourner couche: no; Considérer couches comme plâtre: no; Tourner épaiseur: 1; Orientation hachure: 1; Ligne de séparation tournant: no; Stylo ligne de séparation: Général - Dessin 0.12; Dernier côté sélectionné: no; Méthode fermeture changée auto.: no; Connexion à gauche: no; Connexion à droite: no; Connexion en haut: no; Connexion en bas: no; Incrustation allège: no; Tailles incrustation mur (gs_parapet_sizes_st): Automatique; Tailles incrustation mur (iParapetSize): 1; Cotes largeur et longueur auto: yes; Incrustation base mur à (gs_parapet_bottom_st): Etage actuel; Incrustation base mur à (iParapetBottom): 1; Afficher allège masquée: yes; Type ligne allège masquée: 1; Angle ouv. châssis principal (openingAngle_01): 0 deg; Angle ouv. châssis principal (openingAngle2_01): 0 deg; Angle ouverture en 2D: 0 deg; Suppl. Opt. vue pour aff. symb. 2D: no; Type ligne ouverture: 1; Forme ligne ouverture (or_SwingType): Courbé; Forme ligne ouverture (or_iSwingType): 1; Forme ligne ouverture (or_SlidingType): Sans; Forme ligne ouverture (or_iSlidingType): 0; Stylo ligne ouverture 2D/3D (or_opLinePen): Ouvertures - Général; Stylo ligne ouverture 2D/3D (or_iOpLinePen): 3; Suppl. Opt. vue pour proj. 3D: no; Afficher ligne d'ouverture: yes; Type ligne côté ouverture (or_opLineType3dIn): Ligne continue; Type ligne côté ouverture (or_iOpLineType3dIn): 0; Type ligne côté opposé (or_opLineType3dOut): Ligne continue; Type ligne côté opposé (or_iOpLineType3dOut): 0; Orient. ligne (or_oplineStyle): Poignée; Orient. ligne (or_iOplineStyle): 1; Stylo ligne non coupée: Ouvertures - Général; Stylo ligne coupée: Ouvertures - Général; Stylo ligne coupée chambranle des deux côtés: Ouvertures - Général; Ligne de contour de mur (gs_wcont_line): Des deux côtés; Ligne de contour de mur (iWallContourLine): 4; Type ligne contour int. mur: 1; Type ligne contour ext. mur: 1; Type ligne contour int. mur masqué: 4; Type ligne contour ext. mur masqué: 4; Stylo ligne contour de mur: Ouvertures - Général; Utiliser hachures: yes; Motif de hachure cadre: Sans Trame; Stylo hachure cadre: Général - Dessin 0.12; Stylo fond de hachure cadre: Ouvertures - fonds de hachure; Motif de hachure châssis: Lame d'air; Stylo fond de châssis: Ouvertures - Hachures coupées; Stylo fond de hachure châssis: Fond - Couleur 1; Type hachure non coupée: Sans Trame; Stylo hachure non coupée: Général - Dessin 0.12; Stylo fond de hachure non coupé: Ouvertures - fonds de hachure; Motif hachure symbole en plan: Sans Trame; Stylo hachure symbole en plan: Général - Dessin 0.12; Stylo fond hachure symbole plan: Ouvertures - fonds de hachure; Stylo appui 3D et non coupé: Général - Dessin 0.12; Stylo contour appui en Coupe: Général - Dessin 0.12; Motif hachure appui en Coupe: Lame d'air; Stylo hachure d'appui en Coupe: Fond - Couleur 1; Stylo fond hachure appui Coupe: Fond - Couleur 1; Stylo contour isolation coupe: Général - Dessin 0.12; Motif hachure isolation Coupe: Isolation polystyrène; Stylo hachure isolation Coupe: Général - Dessin 0.12; Stylo fond hachure isol. Coupe: Fond - Couleur 1; Stylo latte 3D et non coupé: Général - Dessin 0.12; Stylo contour latte en Coupe: Général - Dessin 0.12; Motif hachure tablette en Coupe: Lame d'air; Stylo hachure tablette en Coupe: Fond - Couleur 1; Stylo fond hach. tablette Coupe: Fond - Couleur 1; Type hachure chambr. intérieur: Sans Trame; Stylo hachure chambr. int.: Ouvertures - Général; Stylo fond hachure chambr. int.: Ouvertures - fonds de hachure; Type hachure chambr. ext.: Lame d'air; Stylo hachure chambr. ext.: Fond - Couleur 1; Stylo fond hachure chambr. ext.: Fond - Couleur 1; Motif de hachure arche coupe: Sans Trame; Stylo hachure en coupe d'arche: Fond - Couleur 1; Stylo fond hachure appui arche Coupe: Fond - Couleur 1; Type de ligne symbole volet: 1; Stylo ligne coupée volet: Général - Dessin 0.12; Stylo ligne non coupée 3D/Coupe: Général - Dessin 0.12; Type hachure coupée volet: Sans Trame; Stylo hachure coupée volet: Général - Dessin 0.12; Stylo fond hachure coupé volet: Fond de fenêtre; Motif de hachure d'isolation de volet: Dallage; Stylo de hachure d'isolation de volet: Général - Dessin 0.12; Stylo de fond d'isolation de volet: Fond de fenêtre; Résolution de courbe: 32; Stylo cadre: Ouvertures - Général; Stylo châssis: Ouvertures - Général; Stylo vitrage: Ouvertures - Général; Stylo linteau: Murs - Général; Ombre: yes; Surfaces de fenêtre uniformes: no; Cadre extérieur: _Men ext_RAL9007; Cadre intérieur: _Men ext_RAL9007; Châssis extérieur: _Men ext_RAL9007; Châssis intérieur: _Men ext_RAL9007; Vitrage (gs_glass_mat): _Verre clair (rapide); Grille extérieure: _Men ext_RAL9007; Grille intérieure: _Men ext_RAL9007; Panneau solide extérieur: _Men ext_RAL9007; Panneau solide intérieur: _Men ext_RAL9007; Surfaces uniformes de chambranle: yes; Chambranle intérieur: _Men ext_RAL9007; Chambranle extérieur (gs_trim_out_mat): _Men ext_RAL9007; Panneau volet: _Men ext_RAL9007; Cadre panneau volet: _Men ext_RAL9007; Boîte volet roulant: _Métal - Acier inoxydable; Lames volet roulant: _Peinture - Blanc brillant; Rail volet roulant: _Peinture - Blanc brillant; Boîte store vénitien: _Métal - Acier inoxydable; Segments store vénitien: _Peinture - Blanc brillant; Rail volet coulissant: _Métal - Acier inoxydable; Appui (gs_sill_mat): _Men ext_RAL9007; Mortier appui briques: _Enduit - Blanc nature; Tablette (gs_board_mat): _Men ext_RAL9007; Brique linteau: _Coupe3D_; Mortier linteau: _Enduit - Blanc nature; Clef de voûte linteau: _Pierre - Grès 01; Niche: _Mur int Hall; Direction d'ouverture: 1; Prof. linteau sur symbole: no; Type ligne symbole prof. linteau: 21; Stylo symbole prof. linteau: Texte d'annotation - Général; Fenêtre appartient à Zone vers laquelle elle donne: no; Coût: 0; Surface vitrée totale (gs_list_glassarea_tmp): 0; Supplanter surface vitrée: no; Surface vitrée totale (gs_list_glassarea): 0.865901; Périmètre total vitrage: 0; Type de groupe (FM_Type): Objets par défaut; Type de groupe (iFMType): 1; Poids de l'objet: 0; Unité poids de l'objet: kg; Définition d'orientation de fenêtre: 0; Opération IFC (ifc_optypestr): Autre; Opération IFC (ifc_optype): 10; Angle ouverture volet: 180 deg; Style lignes d'ouverture: 1
AC_Pset_RenovationAndPhasing - Renovation Status: Existing

# IfcBuildingElementProxy: Fenêtre variable 21 (43)
Classification: Element de construction non défini (Classification Archicad); Fenêtre (Classification ARCHICAD); Material: Matériau de construction IFC
ArchiCADProperties - Calque: 10_M x baseGO__; Nom Élément de Bibliothèque: Fenêtre variable 21; Matériau de construction / Composite / Profil / Hachure: Air space; Type Hachure: Air space; Verrouillé: no; Type d'élément: Fenêtre; Surfaces (Toutes): _Men ext_RAL9007; _Verre clair (rapide); _Métal BAVETTE; État de rénovation: Existant; Affichage sur filtre de rénovation: Tous les filtres appropriés; Fonction structurelle: Non défini; Nom élément de bibliothèque d'ouverture: Fenêtre variable 21; Index hachure latérale ouverture: Air space; Classification ARCHICAD - 21: Fenêtre
AC_Pset_Fenêtre_variable_21 - Contours Mur (0-Sans,1-Tout,2-Côté,3-Longueur): 0; Point ch.0-Non,1-2D,2-3D,3-Tous: 3; Option affichage en plan: 3; Angle de position baie: 0 deg; Division de surface du trou courbe dans murs courbes: no; Afficher points chauds 2D en 3D: yes; Type de mur: 1; Type de direction de mur: 0; Position ancre ébrasuer: 1; Fonction de debug Fenêtre Angle: no; Placement (1=Angle, 0=Centre): no; Basculer: no; Démolition / Nouvelle constr.: 1; Nouveau motif de hachure de mur: Parpaing; Nouveau stylo de hachure de mur: Général - Dessin 0.12; Nouveau stylo fond hachure mur: Fond - Couleur 1; Afficher nouv. constr. sur mur: no; Type de ligne démolition: 4; Aff. param. Démolition/Nouveau: no; Fonction Fenêtre Angle: yes; Angle Murs: 90 deg; Murs connectés d'épaiss. diff.: no; Poteau d'angle: no; Coin 2: no; Angle de coin 2: 90 deg; Murs connectés d'épaiss. diff. 2: no; Coin 1: no; Angle de coin 1: 90 deg; Murs connectés d'épaiss. diff. 1: no; Type connexion angle 1: 1; Type connexion angle 2: 1; Entièrement éditable: yes; Niveau de détail 2D: 1; Afficher ébrasure sur symbole: 1; Niveau de détail 3D: 2; Activer niveau détail 3D: 14; Taille nominale: 0; Taille trou comme taille nominale: yes; Taille ébrasure comme nominale: no; Taille unité comme nominale: no; Transmettre taille nominale actuelle à sélection: no; Panneaux horizontaux (gs_PanesConfig): Panneaux uniformes; Panneaux horizontaux (gs_iPanesConfig): 1; Traverse supérieure: no; Châssis vitré (gs_bSLight): no; Panneaux verticaux (gs_PanesConfigVertical): Asymétrique; Panneaux verticaux (gs_iPanesConfigVertical): 3; Meneau jusqu'en haut: yes; Meneau jusqu'en bas: no; Châssis uniformes: no; Direction vitrage fixe (FixGlassDir): Par direction d'ouverture; Direction vitrage fixe (FixGlassDir_m): 1; Type ouverture panneau adj.: Vitrage fixe; Type d'ouverture (gs_optype_m_05): 1; Type ouverture châssis inf.: Vitrage fixe; Type d'ouverture (gs_optype_m_03): 1; Type ouverture châssis imposte: Vitrage fixe; Type d'ouverture (gs_optype_m_02): 1; Type châssis (MullionStyle_00): Pas de grille; Type châssis (iMullionStyle_00): 1; Type châssis tierce vitrée: Pas de grille; Type châssis (iMullionStyle_05): 1; Type châssis, châssis imposte: Pas de grille; Type châssis (iMullionStyle_02): 1; Panneau personnalisé symétrie (gs_bMirr_cust_panel_01): no; Panneau personnalisé symétrie (gs_bMirr_cust_panel2_01): no; Panneau personnalisé symétrie (gs_bMirr_cust_panel_02): no; Panneau personnalisé symétrie (gs_bMirr_cust_panel2_02): no; Panneau personnalisé symétrie (gs_bMirr_cust_panel_03): no; Panneau personnalisé symétrie (gs_bMirr_cust_panel2_03): no; Panneau personnalisé symétrie (gs_bMirr_cust_panel_05): no; Panneau personnalisé symétrie (gs_bMirr_cust_panel2_05): no; Edition point chaud de grille: yes; Position grille (MullionPosition): Les deux; Position grille (iMullionPosition): 3; Nbre panneaux H châssis princ.: 2; Nbre panneaux V 2 châssis princ.: 2; Nbre panneaux H 2 châssis princ.: 2; Nbre panneaux V tierce vitrée: 3; Nbre panneaux H tierce vitrée: 2; Nbre panneaux V 2 tierce vitrée: 3; Nbre panneaux H 2 tierce vitrée: 2; Nbre panneaux H châssis inf.: 2; Nbre panneaux V 2 châssis inf.: 2; Nbre panneaux H 2 châssis inf.: 2; Nbre panneaux V châssis imposte: 2; Nbre panneaux H châssis imposte: 2; Nbre panneaux V 2 châssis imposte: 2; Nbre panneaux H 2 châssis imposte: 2; Style persiennes (iLouverStyle): 1; Angle d'ouverture persiennes: 0 deg; Chambranle extérieur (gs_trim_outside): no; Type chambr. ext. (gs_trimtype_out): Simple; Type chambr. ext. (gs_trimtype_out_int): 1; Type tête chambr. ext.: 1; Chapiteau architrave: yes; Type chapiteau architrave: 1; Chambranle inférieur extérieur: yes; Couvre surface mur ext.: yes; Largeurs uniformes de chambranle (gs_trim_outside_uniform): yes; Chambranle intérieur.: no; Type chambr. intérieur (gs_trimtype_in): Simple; Type chambr. intérieur (gs_trimtype_in_int): 1; Couvre surface mur int.: yes; Largeurs uniformes de chambranle (gs_trim_inside_uniform): yes; Appui (gs_sill_outside): yes; Dépassement appui: no; Type d'appui/seuil: 11; Angle appui: 3 deg; Appui courbe dans murs courbes: yes; Isolation sous appui: yes; Utiliser couche isolation mur: no; Niveau détail 3D seuil brique: 1; Tablette (gs_board_inside): no; Angle tablette: 0 deg; Tableau dans murs polygonaux: 1; Aération naturelle: no; Type d'aération naturelle: 2; Châssis principal: no; Châssis vitré (isVentilationProfileInSash_05): no; Châssis inférieur: no; Châssis imposte: yes; Volet: no; Nombre de panneaux: 2; Nombre de panneaux 2: 1; Position panneau (gs_shutter_panelPos): Symétrique; Position panneau (gs_shutter_iPanelPos): 1; Hauteur volet automatique: yes; Cadre supplémentaire: no; Type de couverture (gs_slidingShutter_cover): Profil en Z; Type de couverture (gs_slidingShutter_iCover): 1; Direction articulation (gs_foldingShutter_stacking): Intérieur; Direction articulation (gs_foldingShutter_iStacking): 1; Ouvert en 3D: yes; Angle ouverture en 3D: 180 deg; Afficher symbole 2D: yes; Afficher lignes d'ouverture sur symbole: no; Type de panneau: (gs_shutPanel_type): Style 1; Type de panneau: (gs_shutPanel_iType): 1; Largeur cadre inf. différente: no; Largeur volets automatiques: yes; Angle persienne: 30 deg; Nombre trous horizontaux: 5; Nombre trous verticaux: 8; Placement volet roulant (gs_shutRoll_placement): Sur façade; Placement volet roulant (gs_shutRoll_iPlacement): 1; Type boîte (gs_shutRoll_boxType): Rectangulaire; Type boîte (gs_shutRoll_iBoxType): 1; Position rampe (gs_shutRoll_railPos): Sur revêtement; Position rampe (gs_shutRoll_iRailPos): 1; Afficher revêtement derrière parasol (gs_shutRoll_showCasingBehind): no; Isolation derrière cellule (gs_shutRoll_cutWallBehind): no; Inclure hauteur dans hauteur de trou de mur: no; Angle supérieur boîte: 10 deg; Taille boîte par défaut (gs_shutRoll_boxDefaultSize): Largeur ébrasure; Taille boîte par défaut (gs_shutRoll_iBoxDefaultSize): 1; Placement stores (gs_shutLam_placement): Fixé sur façade; Placement stores (gs_shutLam_iPlacement): 1; Isolation derrière cellule (gs_shutLam_cutWallBehind): no; Boîte ouverte: yes; Rampe: yes; Position rampe (gs_shutLam_railPos): Sur revêtement; Position rampe (gs_shutLam_iRailPos): 1; Afficher revêtement derrière parasol (gs_shutLam_showCasingBehind): no; Angle de rotation des lamelles (gs_shutLam_rotation): 45 deg; Angle de rotation des lamelles (gs_shutLam2_rotation): 45 deg; Linteau (bMasonryArch): no; Linteau (gs_masonry_arch_int): 2; Type linteau (gs_masonry_arch_structure): Stuc; Type linteau (gs_masonry_arch_structure_int): 1; Arche sur linteau: yes; Niche sous arche: yes; Angle inclinaison: 75 deg; Surface niche personnalisée: no; Type ébrasure (gs_reveal_type_new): Baie simple; Type ébrasure (gs_reveal_type_int): 2; Type ébrasure inférieure (gs_reveal_type_bottom): Uniforme; Type ébrasure inférieure (gs_reveal_type_bottom_int): 1; Type ébrasure extérieure: Baie simple; Type ébrasure (gs_reveal_doubleOuterTypeInt): 0; Type ébrasure intérieure: Baie simple; Type ébrasure (gs_reveal_doubleInnerTypeInt): 0; Profondeur montant uniforme: yes; Côté angle 2: 20 deg; Côté angle: 20 deg; Angle côté supérieur: 20 deg; Angle côté inférieur: 20 deg; Utiliser composant finition mur: no; Tourner automatiquement plâtre surface intérieure: yes; Tourner plâtre surface intérieure: 0; Tourner automatiquement plâtre surface extérieure: yes; Tourner plâtre surface extérieure: 0; Peut être coté en 2D: no; Afficher en 3D: no; Type de fermeture (gs_closure_type): Pas de fermeture; Type de fermeture (gs_closure_type_int): 1; Tourner couche sur côté (gs_cavity_side): Les deux; Tourner couche sur côté (iCavityClosureSide): 1; Nbre de couches retournées: 1; Num. à partir de (gs_nTurnDir): Face extérieure; Num. à partir de (iCavityClosureTurnDir): 1; Placer fermeture sur côté 2: yes; Placer fermeture sur côté 1: yes; Placer fermeture en haut: no; Placer fermeture en bas: no; Placer fermeture sur couche: 1; Placer fermeture de côté (gs_cc_dutch_ClosureToSide): 1; Ecart à couche externe: yes; Tourner couche sur fermeture: no; Insérer bande d'isolation: yes; Afficher bande d'isolation: yes; Stylo contour (gs_penJoint): Ouvertures - Coupé non structurel; Type de ligne de contour (gs_ltJoint): 1; Motif de hachure (gs_fillJoint): Isolation polystyrène; Stylo hachure (gs_penJointFg): Général - Dessin 0.12; Stylo fond de hachure (gs_penJointBg): Eléments 2D - Dessin; Surface personnalisée: no; Surface: _Men ext_RAL9007; Stylo contour (gs_penPlug): Ouvertures - Coupé non structurel; Type de ligne de contour (gs_ltPlug): 1; Motif de hachure (gs_fillPlug): Isolation polystyrène; Stylo hachure (gs_penPlugFg): Général - Dessin 0.12; Stylo fond de hachure (gs_penPlugBg): Eléments 2D - Dessin; Côté montant édité: 1; Côté mur édité: 1; Numéro couche éditée: 1; Tourner couche: no; Considérer couches comme plâtre: no; Tourner épaiseur: 1; Orientation hachure: 1; Ligne de séparation tournant: no; Stylo ligne de séparation: Général - Dessin 0.12; Dernier côté sélectionné: no; Méthode fermeture changée auto.: no; Connexion en haut: no; Connexion en bas: no; Incrustation allège: no; Tailles incrustation mur (gs_parapet_sizes_st): Automatique; Tailles incrustation mur (iParapetSize): 1; Cotes largeur et longueur auto: yes; Incrustation base mur à (gs_parapet_bottom_st): Etage actuel; Incrustation base mur à (iParapetBottom): 1; Afficher allège masquée: yes; Type ligne allège masquée: 1; Angle ouv. châssis principal (openingAngle2_01): 0 deg; Angle ouv. tierce vitrée (openingAngle_05): 0 deg; Angle ouv. tierce vitrée (openingAngle2_05): 0 deg; Angle d'ouverture châssis inf. (openingAngle_03): 0 deg; Angle d'ouverture châssis inf. (openingAngle2_03): 0 deg; Angle ouv. châssis imposte (openingAngle_02): 0 deg; Angle ouv. châssis imposte (openingAngle2_02): 0 deg; Angle ouverture en 2D: 0 deg; Suppl. Opt. vue pour aff. symb. 2D: no; Type ligne ouverture: 1; Forme ligne ouverture (or_SwingType): Courbé; Forme ligne ouverture (or_iSwingType): 1; Forme ligne ouverture (or_SlidingType): Sans; Forme ligne ouverture (or_iSlidingType): 0; Stylo ligne ouverture 2D/3D (or_opLinePen): Général - Dessin 0.12; Stylo ligne ouverture 2D/3D (or_iOpLinePen): 1; Suppl. Opt. vue pour proj. 3D: no; Type ligne côté ouverture (or_opLineType3dIn): Tirets; Type ligne côté ouverture (or_iOpLineType3dIn): 1; Type ligne côté opposé (or_opLineType3dOut): Tirets; Type ligne côté opposé (or_iOpLineType3dOut): 1; Orient. ligne (or_oplineStyle): Poignée; Orient. ligne (or_iOplineStyle): 1; Stylo ligne non coupée: Ouvertures - Général; Stylo ligne coupée: Ouvertures - Général; Stylo ligne coupée chambranle des deux côtés: Ouvertures - Général; Ligne de contour de mur (gs_wcont_line): Des deux côtés; Ligne de contour de mur (iWallContourLine): 4; Type ligne contour int. mur: 1; Type ligne contour ext. mur: 1; Type ligne contour int. mur masqué: 4; Type ligne contour ext. mur masqué: 4; Stylo ligne contour de mur: Ouvertures - Général; Utiliser hachures: no; Motif de hachure cadre: Sans Trame; Stylo hachure cadre: Général - Dessin 0.12; Stylo fond de hachure cadre: Transparent; Motif de hachure châssis: Sans Trame*; Stylo fond de châssis: Général - Dessin 0.12; Stylo fond de hachure châssis: Transparent; Type hachure non coupée: Sans Trame; Stylo hachure non coupée: Général - Dessin 0.12; Stylo fond de hachure non coupé: Transparent; Motif hachure symbole en plan: Sans Trame; Stylo hachure symbole en plan: Général - Dessin 0.12; Stylo fond hachure symbole plan: Transparent; Stylo appui 3D et non coupé: Général - Dessin 0.12; Stylo contour appui en Coupe: Général - Dessin 0.12; Motif hachure appui en Coupe: Sans Trame; Stylo hachure d'appui en Coupe: Général - Dessin 0.12; Stylo fond hachure appui Coupe: Transparent; Stylo contour isolation coupe: Général - Dessin 0.12; Motif hachure isolation Coupe: Isolation polystyrène; Stylo hachure isolation Coupe: Général - Dessin 0.12; Stylo fond hachure isol. Coupe: Fond - Couleur 1; Stylo latte 3D et non coupé: Général - Dessin 0.12; Stylo contour latte en Coupe: Général - Dessin 0.12; Motif hachure tablette en Coupe: Lame d'air; Stylo hachure tablette en Coupe: Fond - Couleur 1; Stylo fond hach. tablette Coupe: Fond - Couleur 1; Type hachure chambr. intérieur: Lame d'air; Stylo hachure chambr. int.: Fond - Couleur 1; Stylo fond hachure chambr. int.: Fond - Couleur 1; Type hachure chambr. ext.: Lame d'air; Stylo hachure chambr. ext.: Fond - Couleur 1; Stylo fond hachure chambr. ext.: Fond - Couleur 1; Motif de hachure arche coupe: Sans Trame; Stylo hachure en coupe d'arche: Fond - Couleur 1; Stylo fond hachure appui arche Coupe: Fond - Couleur 1; Motif de hachure de Coupe de Profil de ventilation: Lame d'air; Stylo de hachure de Coupe de Profil de ventilation: Fond - Couleur 1; Stylo de fond de hachure de Coupe de Profil de ventilation: Fond - Couleur 1; Type de ligne symbole volet: 1; Stylo ligne coupée volet: Général - Dessin 0.12; Stylo ligne non coupée 3D/Coupe: Général - Dessin 0.12; Type hachure coupée volet: Sans Trame; Stylo hachure coupée volet: Général - Dessin 0.12; Stylo fond hachure coupé volet: Fond de fenêtre; Motif de hachure d'isolation de volet: Dallage; Stylo de hachure d'isolation de volet: Général - Dessin 0.12; Stylo de fond d'isolation de volet: Fond de fenêtre; Jonction éléments cadree: 2; Stylo cadre: Ouvertures - Général; Stylo vitrage: Ouvertures - Général; Stylo linteau: Murs - Général; Ombre: yes; Surfaces de fenêtre uniformes: yes; Cadre extérieur: _Men ext_RAL9007; Cadre intérieur: _Men ext_RAL9007; Châssis extérieur: _Men ext_RAL9007; Châssis intérieur: _Men ext_RAL9007; Persiennes: _Men ext_RAL9007; Vitrage (gs_glass_mat): _Verre clair (rapide); Grille extérieure: _Men ext_RAL9007; Grille intérieure: _Men ext_RAL9007; Panneau solide extérieur: _Men ext_RAL9007; Panneau solide intérieur: _Men ext_RAL9007; Surfaces uniformes de chambranle: yes; Chambranle intérieur: _Men ext_RAL9007; Chambranle extérieur (gs_trim_out_mat): _Men ext_RAL9007; Profil Ventilation: _Métal BAVETTE; Panneau volet: _Men ext_RAL9007; Cadre panneau volet: _Men ext_RAL9007; Boîte volet roulant: _Métal - Acier inoxydable; Lames volet roulant: _Peinture - Blanc brillant; Rail volet roulant: _Peinture - Blanc brillant; Boîte store vénitien: _Métal - Acier inoxydable; Segments store vénitien: _Peinture - Blanc brillant; Rail volet coulissant: _Métal - Acier inoxydable; Appui (gs_sill_mat): _Métal BAVETTE; Mortier appui briques: _Enduit - Blanc nature; Brique linteau: _Coupe3D_; Mortier linteau: _Enduit - Blanc nature; Clef de voûte linteau: _Pierre - Grès 01; Niche: _Mur int Hall; Surface poteau d'angle: _Men ext_RAL9007; Afficher comme imposte: no; Stylo ligne tête de mur: Général - Dessin 0.12; Type de ligne tête de mur: 21; Prof. linteau sur symbole: no; Type ligne symbole prof. linteau: 21; Stylo symbole prof. linteau: Texte d'annotation - Général; Fenêtre appartient à Zone vers laquelle elle donne: no; Coût: 0; Surface vitrée totale (gs_list_glassarea_tmp): 0; Supplanter surface vitrée: no; Périmètre total vitrage: 0; Performance air libre (mm2/l/m): 0; Type de groupe (FM_Type): Objets par défaut; Type de groupe (iFMType): 1; Poids de l'objet: 0; Unité poids de l'objet: kg; Définition d'orientation de fenêtre: 0; Angle ouverture volet: 180 deg; Style lignes d'ouverture: 1
AC_Pset_RenovationAndPhasing - Renovation Status: Existing
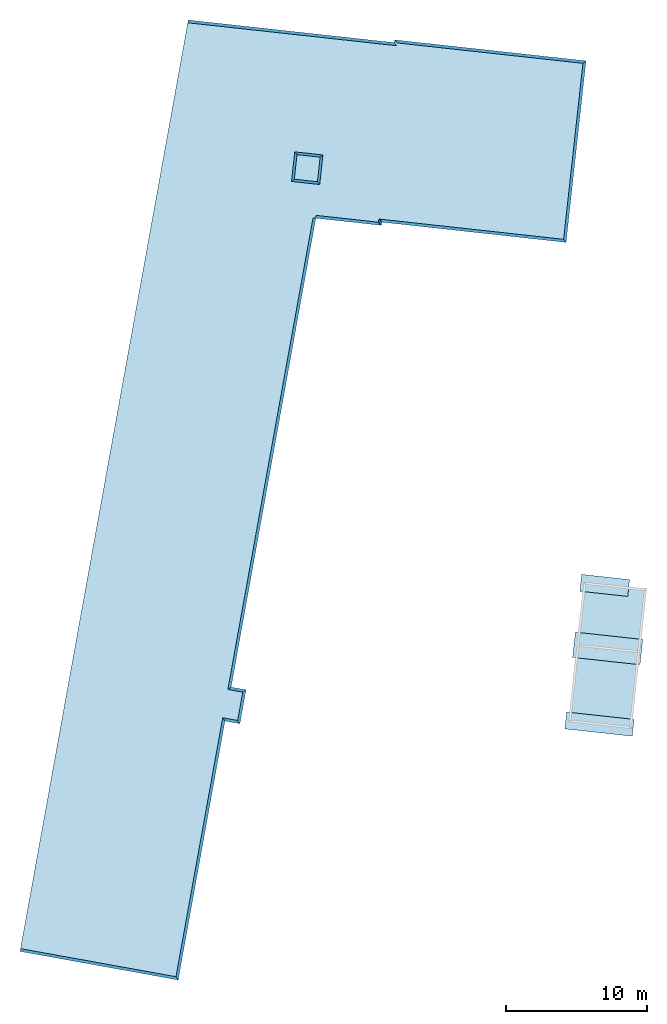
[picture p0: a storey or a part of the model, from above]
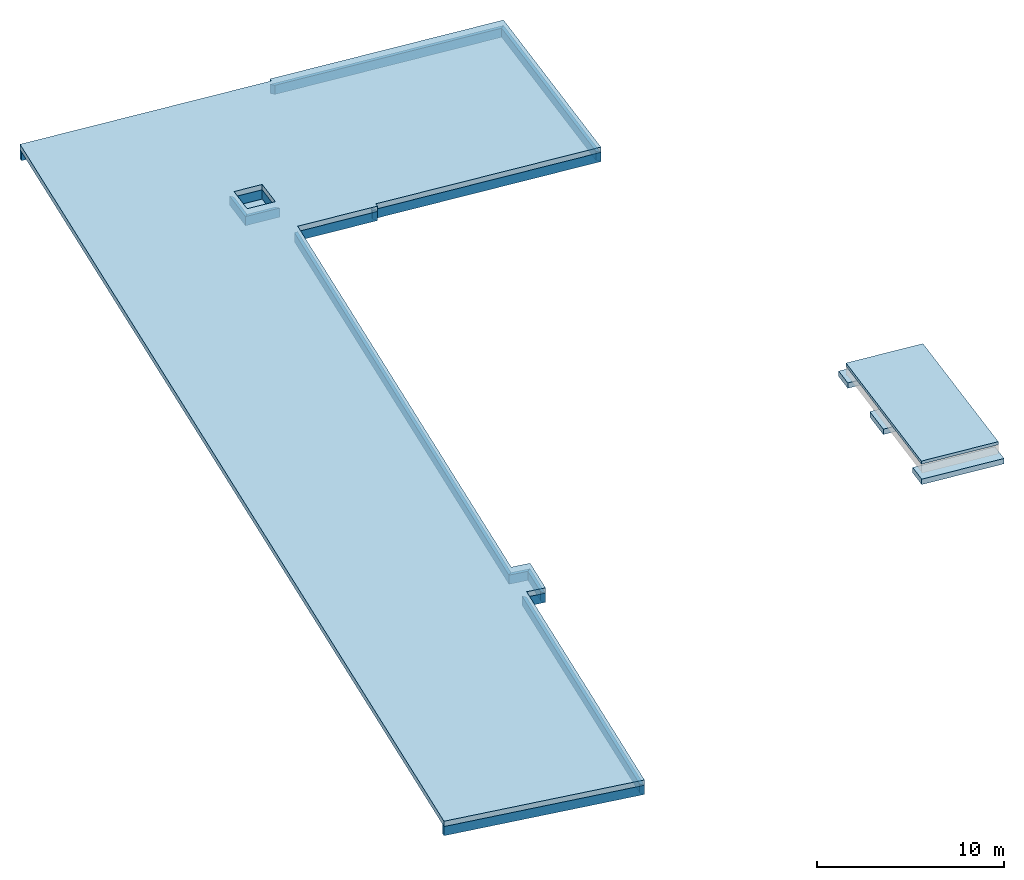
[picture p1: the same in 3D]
Properties of the parts of a building model (IFC2X3), part 3 of 10

# IfcBuildingElementProxy: Fenêtre variable 21 (43)
Name | In | ID de l'élément = Lien et ID d'élément | Nom de zone liée = À Zone | Nom d'étage d'implantation | Numéro d'étage d'implantation | ID de Parent | Position | Dimensions ébrasure = Dimensions trou mur = Dimensions unité = Taille L x H nominale | Taille L x H x E nominale | Structure de Mur | Trou reprend surface latérale de mur | Largeur cadre uniforme | Traverse inférieure | Type d'opération châssis princ. | Type d'ouverture (gs_optype_m_01) | Type châssis, châssis princ. = Type châssis, châssis inf. | Type châssis (iMullionStyle_01) = Type châssis (iMullionStyle_03) | Nbre panneaux V châssis princ. = Nbre panneaux V châssis inf. | Tabl. courbe dans murs courbes | Type volet | Types volet activés | Connexion à gauche | Connexion à droite | Angle ouv. châssis principal (openingAngle_01) (deg) | Afficher ligne d'ouverture | Stylo châssis | Tablette (gs_board_mat) | Direction d'ouverture | Surface vitrée totale (gs_list_glassarea) | Opération IFC (ifc_optypestr) | Opération IFC (ifc_optype)
7 x Fen couloir | RDC | Fen couloir | Circulation 1 | RDC | 0 | M ext-Ouest | Non défini | 191×70 | 191×70×36 | _M ext couloir | yes | yes | no | Vitrage fixe | 1 | Pas de grille | 1 | 2 | yes | 1 | 126 | no | no | 0 | yes | Général - Dessin 0.12 | _Men ext_RAL9007 | 1 | 0.968 | Simple | 1
6 x Fen salle-pluri-Nord | RDC | Fen salle-pluri-Nord |  | RDC | 0 | M ext pluri-Nord | Non défini | 166×78 | 166×78×56 | _M ext pluri Nord | no | yes | no | Vitrage fixe | 1 | Pas de grille | 1 | 2 | yes | 1 | 126 | no | no | 0 | yes | Général - Dessin 0.12 | _Men ext_RAL9007 | 1 | 0.9513 | Simple | 1
5 x Fen couloir | RDC | Fen couloir | Circulation 1 | RDC | 0 | M ext-Ouest | Non défini | 238×70 | 238×70×36 | _M ext couloir | yes | yes | no | Vitrage fixe | 1 | Pas de grille | 1 | 2 | yes | 1 | 126 | no | no | 0 | yes | Général - Dessin 0.12 | _Men ext_RAL9007 | 1 | 1.2265 | Simple | 1
Fen couloir | RDC | Fen couloir | Circulation 1 | RDC | 0 | M ext-Ouest | Non défini | 238×70 | 238×70×36 | _M ext couloir | yes | yes | no | Vitrage fixe | 1 | Pas de grille | 1 | 2 | no | 1 | 126 | no | no | 0 | yes | Général - Dessin 0.12 | _Bois - Pin granuleux horiz | 1 | 1.2265 | Simple | 1
3 x Fen couloir | RDC | Fen couloir | Circulation 1 | RDC | 0 | M ext-Ouest | Non défini | 193×70 | 193×70×36 | _M ext couloir | yes | yes | no | Vitrage fixe | 1 | Pas de grille | 1 | 2 | yes | 1 | 126 | no | no | 0 | yes | Général - Dessin 0.12 | _Men ext_RAL9007 | 1 | 0.98175 | Simple | 1
Baie angle-Nord | R+1 | Baie angle-Nord | Circulation 2 | R+1 | 1 | M ext-Nord | Extérieur | 116×220 | 116×220×36 | _M ext 18 +18 gris | yes | no | yes | Vitrage fixe | 1 | Pas de grille | 1 | 2 | yes | 6 | 102 | yes | no | 45 | no | Ouvertures - Général | _Men ext_RAL9007 | 1 | 2.10834 | Horizontal double | 3
Baie vide-sur-hall-Nord | R+1 | Baie vide-sur-hall-Nord |  | R+1 | 1 | M ext-Nord | Extérieur | 105×220 | 105×220×36 | _M ext 18 +18 gris | yes | no | yes | Vitrage fixe | 1 | Pas de grille | 1 | 2 | yes | 6 | 102 | yes | no | 45 | no | Ouvertures - Général | _Men ext_RAL9007 | 0 | 1.88955 | Horizontal double | 3
Baie angle-Nord | R+1 | Baie angle-Nord |  | R+1 | 1 | M ext-Nord | Extérieur | 116×220 | 116×220×36 | _M ext 18 +18 gris | yes | no | yes | Vitrage fixe | 1 | Pas de grille | 1 | 2 | yes | 6 | 64 | yes | yes | 45 | no | Ouvertures - Général | _Men ext_RAL9007 | 1 | 2.10834 | Horizontal double | 3
Baie angle-Nord | R+1 | Baie angle-Nord |  | R+1 | 1 | M ext-Nord | Extérieur | 232×220 | 232×220×36 | _M ext 18 +18 gris | yes | no | yes | Accrochée par le bas | 7 | A carreaux | 2 | 1 | yes | 6 | 102 | yes | no | 0 | no | Ouvertures - Général | _Men ext_RAL9007 | 1 | 3.79404 | Horizontal double | 3
Baie angle-Nord | R+1 | Baie angle-Nord | Circulation 2 | R+1 | 1 | M ext-Nord | Extérieur | 116×220 | 116×220×36 | _M ext 18 +18 gris | yes | no | yes | Vitrage fixe | 1 | Pas de grille | 1 | 2 | yes | 6 | 64 | yes | yes | 45 | no | Ouvertures - Général | _Men ext_RAL9007 | 1 | 2.10834 | Horizontal double | 3
2 x Baie vide-sur-hall-Nord | R+1 | Baie vide-sur-hall-Nord |  | R+1 | 1 | M ext-Nord | Extérieur | 105×220 | 105×220×36 | _M ext 18 +18 gris | yes | no | yes | Vitrage fixe | 1 | Pas de grille | 1 | 2 | yes | 6 | 64 | yes | yes | 45 | no | Ouvertures - Général | _Men ext_RAL9007 | 0 | 1.88955 | Horizontal double | 3
Baie vide-sur-hall-Nord | R+1 | Baie vide-sur-hall-Nord |  | R+1 | 1 | M ext-Nord | Extérieur | 105×220 | 105×220×36 | _M ext 18 +18 gris | yes | no | yes | Vitrage fixe | 1 | Pas de grille | 1 | 2 | yes | 6 | 102 | no | yes | 45 | no | Ouvertures - Général | _Men ext_RAL9007 | 0 | 1.88955 | Horizontal double | 3
Fen couloir | R+1 | Fen couloir | Circulation 2 | R+1 | 1 | M ext-Ouest | Extérieur | 120×220 | 120×220×36 | _M ext 18 +18 | yes | no | yes | Bascule | 5 | Pas de grille | 1 | 2 | yes | 1 | 126 | no | no | 0 | no | Ouvertures - Général | _Men ext_RAL9007 | 1 | 2.14826 | Horizontal double | 3 | ArchiCADProperties - Orientation: G; AC_Pset_Fenêtre_variable_21 - Orientation de fenêtre: G
2 x Fen couloir | R+1 | Fen couloir | Circulation 2 | R+1 | 1 | M ext-Ouest | Extérieur | 120×220 | 120×220×36 | _M ext 18 +18 | yes | no | yes | Bascule | 5 | Pas de grille | 1 | 2 | yes | 1 | 126 | no | no | 0 | no | Ouvertures - Général | _Men ext_RAL9007 | 1 | 2.14826 | Horizontal double | 3 | ArchiCADProperties - Orientation: D; AC_Pset_Fenêtre_variable_21 - Orientation de fenêtre: D
3 x Fen couloir | R+1 | Fen couloir | Circulation 3 | R+1 | 1 | M ext entretien-Est | Extérieur | 120×220 | 120×220×36 | _M ext 18 +18 MILIEU | yes | no | yes | Bascule | 5 | Pas de grille | 1 | 2 | yes | 1 | 126 | no | no | 0 | no | Ouvertures - Général | _Men ext_RAL9007 | 1 | 2.14826 | Horizontal double | 3 | ArchiCADProperties - Orientation: G; AC_Pset_Fenêtre_variable_21 - Orientation de fenêtre: G
2 x Fen couloir | R+1 | Fen couloir | Circulation 3 | R+1 | 1 | M ext entretien-Est | Extérieur | 120×220 | 120×220×36 | _M ext 18 +18 MILIEU | yes | no | yes | Bascule | 5 | Pas de grille | 1 | 2 | yes | 1 | 126 | no | no | 0 | no | Ouvertures - Général | _Men ext_RAL9007 | 1 | 2.14826 | Horizontal double | 3 | ArchiCADProperties - Orientation: D; AC_Pset_Fenêtre_variable_21 - Orientation de fenêtre: D
Fen couloir | R+1 | Fen couloir | Circulation 3 | R+1 | 1 | M ext entretien-Est | Extérieur | 120×220 | 120×220×36 | _M ext 18 +18 MILIEU | yes | no | yes | Bascule | 5 | Pas de grille | 1 | 2 | yes | 1 | 126 | no | no | 0 | yes | Ouvertures - Général | _Men ext_RAL9007 | 1 | 2.14826 | Horizontal double | 3 | ArchiCADProperties - Orientation: D; AC_Pset_Fenêtre_variable_21 - Orientation de fenêtre: D
Baie angle-Ouest | R+1 | Baie angle-Ouest | Circulation 2 | R+1 | 1 | M ext-Ouest | Extérieur | 120×220 | 120×220×36 | _M ext 18 +18 gris | yes | no | yes | Vitrage fixe | 1 | Pas de grille | 1 | 2 | yes | 6 | 102 | yes | no | 45 | no | Ouvertures - Général | _Men ext_RAL9007 | 1 | 2.1879 | Horizontal double | 3
2 x Baie angle-Ouest | R+1 | Baie angle-Ouest | Circulation 2 | R+1 | 1 | M ext-Ouest | Extérieur | 120×220 | 120×220×36 | _M ext 18 +18 gris | yes | no | yes | Vitrage fixe | 1 | Pas de grille | 1 | 2 | yes | 6 | 64 | yes | yes | 45 | no | Ouvertures - Général | _Men ext_RAL9007 | 1 | 2.1879 | Horizontal double | 3
Baie angle-Ouest | R+1 | Baie angle-Ouest | Circulation 2 | R+1 | 1 | M ext-Ouest | Extérieur | 120×220 | 120×220×36 | _M ext 18 +18 gris | yes | no | yes | Vitrage fixe | 1 | Pas de grille | 1 | 2 | yes | 6 | 102 | no | yes | 45 | no | Ouvertures - Général | _Men ext_RAL9007 | 1 | 2.1879 | Horizontal double | 3

# IfcBuildingElementProxy: Fenêtre verticale à châssis multiples 21 (11)
Classification: Element de construction non défini (Classification Archicad); Fenêtre (Classification ARCHICAD); Material: Matériau de construction IFC
ArchiCADProperties - Calque: 10_M x baseGO__; Nom Élément de Bibliothèque: Fenêtre verticale à châssis multiples 21; Verrouillé: no; Type d'élément: Fenêtre; Surfaces (Toutes): _Men ext_RAL9007; _Verre clair (rapide); Position: Non défini; État de rénovation: Existant; Affichage sur filtre de rénovation: Tous les filtres appropriés; Fonction structurelle: Non défini; Nom élément de bibliothèque d'ouverture: Fenêtre verticale à châssis multiples 21; Classification ARCHICAD - 21: Fenêtre
AC_Pset_Fenêtre_verticale_à_châssis_multiples_21 - Contours Mur (0-Sans,1-Tout,2-Côté,3-Longueur): 0; Point ch.0-Non,1-2D,2-3D,3-Tous: 3; Option affichage en plan: 3; Angle de position baie: 0 deg; Division de surface du trou courbe dans murs courbes: no; Afficher points chauds 2D en 3D: yes; Type de mur: 1; Type de direction de mur: 1; Position ancre ébrasuer: 1; Fonction de debug Fenêtre Angle: no; Placement (1=Angle, 0=Centre): no; Basculer: no; Démolition / Nouvelle constr.: 1; Nouveau motif de hachure de mur: Parpaing; Nouveau stylo de hachure de mur: Général - Dessin 0.12; Nouveau stylo fond hachure mur: Fond - Couleur 1; Afficher nouv. constr. sur mur: no; Type de ligne démolition: 4; Aff. param. Démolition/Nouveau: no; Fonction Fenêtre Angle: yes; Angle Murs: 90 deg; Murs connectés d'épaiss. diff.: no; Poteau d'angle: no; Coin 2: no; Angle de coin 2: 90 deg; Murs connectés d'épaiss. diff. 2: no; Coin 1: no; Angle de coin 1: 90 deg; Murs connectés d'épaiss. diff. 1: no; Type connexion angle 1: 1; Type connexion angle 2: 1; Châssis à afficher dans symbole (gs_ShowSashOnSymbol): 1er châssis; Châssis à afficher dans symbole (gs_iShowSashOnSymbol): 1; Entièrement éditable: yes; Niveau de détail 2D: 1; Afficher ébrasure sur symbole: 1; Niveau de détail 3D: 2; Activer niveau détail 3D: 14; Taille nominale: 0; Taille trou comme taille nominale: yes; Taille ébrasure comme nominale: no; Taille unité comme nominale: no; Transmettre taille nominale actuelle à sélection: no; Multiplier unité: no; Nombre de copies: 2; Conserver distance d'axe: yes; Configuration panneaux: Asymétrique; Panneaux verticaux: 3; Largeur cadre uniforme: no; Direction vitrage fixe (FixGlassDir): Par direction d'ouverture; Direction vitrage fixe (FixGlassDir_m): 1; Type d'ouverture Châssis 8: Vitrage fixe; Type d'ouverture (gs_optype_m_08): 1; Type d'ouverture Châssis 9: Vitrage fixe; Type d'ouverture (gs_optype_m_09): 1; Type d'ouverture Châssis 10: Vitrage fixe; Type d'ouverture (gs_optype_m_10): 1; Type de châssis Châssis 4: Pas de grille; Type châssis (iMullionStyle_04): 1; Type de châssis Châssis 5: Pas de grille; Type châssis (iMullionStyle_05): 1; Type de châssis Châssis 6: Pas de grille; Type châssis (iMullionStyle_06): 1; Type de châssis Châssis 7: Pas de grille; Type châssis (iMullionStyle_07): 1; Type de châssis Châssis 8: Pas de grille; Type châssis (iMullionStyle_08): 1; Type de châssis Châssis 9: Pas de grille; Type châssis (iMullionStyle_09): 1; Type châssis (iMullionStyle_10): 1; Edition point chaud de grille: yes; Position grille (MullionPosition): Les deux; Position grille (iMullionPosition): 3; Nbre de panneaux horizontaux Châssis 1: 1; Nbre de panneaux verticaux Châssis 2: 2; Nbre de panneaux horizontaux Châssis 2: 2; Nbre de panneaux verticaux 2 Châssis 2: 2; Nbre de panneaux horizontaux 2 Châssis 2: 2; Nbre de panneaux verticaux Châssis 3: 2; Nbre de panneaux horizontaux Châssis 3: 2; Nbre de panneaux verticaux 2 Châssis 3: 2; Nbre de panneaux horizontaux 2 Châssis 3: 2; Nbre de panneaux verticaux Châssis 4: 2; Nbre de panneaux horizontaux Châssis 4: 2; Nbre de panneaux verticaux 2 Châssis 4: 2; Nbre de panneaux horizontaux 2 Châssis 4: 2; Nbre de panneaux verticaux Châssis 5: 2; Nbre de panneaux horizontaux Châssis 5: 2; Nbre de panneaux verticaux 2 Châssis 5: 2; Nbre de panneaux horizontaux 2 Châssis 5: 2; Nbre de panneaux verticaux Châssis 6: 2; Nbre de panneaux horizontaux Châssis 6: 2; Nbre de panneaux verticaux 2 Châssis 6: 2; Nbre de panneaux horizontaux 2 Châssis 6: 2; Nbre de panneaux verticaux Châssis 7: 2; Nbre de panneaux horizontaux Châssis 7: 2; Nbre de panneaux verticaux 2 Châssis 7: 2; Nbre de panneaux horizontaux 2 Châssis 7: 2; Nbre de panneaux verticaux Châssis 8: 2; Nbre de panneaux horizontaux Châssis 8: 2; Nbre de panneaux verticaux 2 Châssis 8: 2; Nbre de panneaux horizontaux 2 Châssis 8: 2; Nbre de panneaux verticaux Châssis 9: 2; Nbre de panneaux horizontaux Châssis 9: 2; Nbre de panneaux verticaux 2 Châssis 9: 2; Nbre de panneaux horizontaux 2 Châssis 9: 2; Nbre de panneaux verticaux Châssis 10: 2; Nbre de panneaux horizontaux Châssis 10: 2; Nbre de panneaux verticaux 2 Châssis 10: 2; Nbre de panneaux horizontaux 2 Châssis 10: 2; Style persiennes (iLouverStyle): 1; Angle d'ouverture persiennes: 0 deg; Chambranle extérieur (gs_trim_outside): no; Type chambr. ext. (gs_trimtype_out): Simple; Type chambr. ext. (gs_trimtype_out_int): 1; Type tête chambr. ext.: 1; Chapiteau architrave: yes; Type chapiteau architrave: 1; Chambranle inférieur extérieur: yes; Couvre surface mur ext.: yes; Largeurs uniformes de chambranle (gs_trim_outside_uniform): yes; Chambranle intérieur.: no; Type chambr. intérieur (gs_trimtype_in): Simple; Type chambr. intérieur (gs_trimtype_in_int): 1; Couvre surface mur int.: yes; Largeurs uniformes de chambranle (gs_trim_inside_uniform): yes; Appui (gs_sill_outside): no; Dépassement appui: no; Type d'appui/seuil: 11; Angle appui: 3 deg; Appui courbe dans murs courbes: yes; Isolation sous appui: yes; Utiliser couche isolation mur: no; Niveau détail 3D seuil brique: 1; Tablette (gs_board_inside): no; Angle tablette: 0 deg; Tabl. courbe dans murs courbes: yes; Tableau dans murs polygonaux: 1; Aération naturelle: no; Type d'aération naturelle: 2; Châssis 1: yes; Châssis 2: no; Châssis 3: no; Châssis 4: no; Châssis 5: no; Châssis 6: no; Châssis 7: no; Châssis 8: no; Châssis 9: no; Châssis 10: no; Volet: no; Nombre de panneaux (gs_shutter_nPanels): 2; Nombre de panneaux 2: 1; Position panneau (gs_shutter_panelPos): Symétrique; Position panneau (gs_shutter_iPanelPos): 1; Hauteur volet automatique: yes; Cadre supplémentaire: no; Type de couverture (gs_slidingShutter_cover): Profil en Z; Type de couverture (gs_slidingShutter_iCover): 1; Direction articulation (gs_foldingShutter_stacking): Intérieur; Direction articulation (gs_foldingShutter_iStacking): 1; Ouvert en 3D: yes; Angle ouverture en 3D: 180 deg; Afficher symbole 2D: yes; Afficher lignes d'ouverture sur symbole: no; Type de panneau: (gs_shutPanel_type): Style 1; Type de panneau: (gs_shutPanel_iType): 1; Largeur cadre inf. différente: no; Largeur volets automatiques: yes; Angle persienne: 30 deg; Nombre trous horizontaux: 5; Nombre trous verticaux: 8; Placement volet roulant (gs_shutRoll_placement): Sur façade; Placement volet roulant (gs_shutRoll_iPlacement): 1; Type boîte (gs_shutRoll_boxType): Rectangulaire; Type boîte (gs_shutRoll_iBoxType): 1; Position rampe (gs_shutRoll_railPos): Sur revêtement; Position rampe (gs_shutRoll_iRailPos): 1; Afficher revêtement derrière parasol (gs_shutRoll_showCasingBehind): no; Isolation derrière cellule (gs_shutRoll_cutWallBehind): no; Inclure hauteur dans hauteur de trou de mur: no; Angle supérieur boîte: 10 deg; Taille boîte par défaut (gs_shutRoll_boxDefaultSize): Largeur ébrasure; Taille boîte par défaut (gs_shutRoll_iBoxDefaultSize): 1; Placement stores (gs_shutLam_placement): Fixé sur façade; Placement stores (gs_shutLam_iPlacement): 1; Isolation derrière cellule (gs_shutLam_cutWallBehind): no; Boîte ouverte: yes; Rampe: yes; Position rampe (gs_shutLam_railPos): Sur revêtement; Position rampe (gs_shutLam_iRailPos): 1; Afficher revêtement derrière parasol (gs_shutLam_showCasingBehind): no; Angle de rotation des lamelles (gs_shutLam_rotation): 45 deg; Angle de rotation des lamelles (gs_shutLam2_rotation): 45 deg; Linteau (bMasonryArch): no; Linteau (gs_masonry_arch_int): 2; Type linteau (gs_masonry_arch_structure): Stuc; Type linteau (gs_masonry_arch_structure_int): 1; Arche sur linteau: yes; Niche sous arche: yes; Angle inclinaison: 75 deg; Surface niche personnalisée: no; Type ébrasure inférieure (gs_reveal_type_bottom): Uniforme; Type ébrasure inférieure (gs_reveal_type_bottom_int): 1; Type ébrasure extérieure: Baie simple; Type ébrasure (gs_reveal_doubleOuterTypeInt): 0; Type ébrasure intérieure: Baie simple; Type ébrasure (gs_reveal_doubleInnerTypeInt): 0; Profondeur montant uniforme: yes; Côté angle 2: 20 deg; Côté angle: 20 deg; Angle côté supérieur: 20 deg; Angle côté inférieur: 20 deg; Utiliser composant finition mur: no; Tourner automatiquement plâtre surface intérieure: yes; Tourner plâtre surface intérieure: 0; Tourner automatiquement plâtre surface extérieure: yes; Tourner plâtre surface extérieure: 0; Peut être coté en 2D: no; Afficher en 3D: no; Type de fermeture (gs_closure_type): Pas de fermeture; Type de fermeture (gs_closure_type_int): 1; Tourner couche sur côté (gs_cavity_side): Les deux; Tourner couche sur côté (iCavityClosureSide): 1; Nbre de couches retournées: 1; Num. à partir de (gs_nTurnDir): Face extérieure; Num. à partir de (iCavityClosureTurnDir): 1; Placer fermeture sur côté 2: yes; Placer fermeture sur côté 1: yes; Placer fermeture en haut: no; Placer fermeture en bas: no; Placer fermeture sur couche: 1; Placer fermeture de côté (gs_cc_dutch_ClosureToSide): 1; Ecart à couche externe: yes; Tourner couche sur fermeture: no; Insérer bande d'isolation: yes; Afficher bande d'isolation: yes; Stylo contour (gs_penJoint): Ouvertures - Coupé non structurel; Type de ligne de contour (gs_ltJoint): 1; Motif de hachure (gs_fillJoint): Isolation polystyrène; Stylo hachure (gs_penJointFg): Général - Dessin 0.12; Stylo fond de hachure (gs_penJointBg): Eléments 2D - Dessin; Surface personnalisée: no; Surface: _Men ext_RAL9007; Stylo contour (gs_penPlug): Ouvertures - Coupé non structurel; Type de ligne de contour (gs_ltPlug): 1; Motif de hachure (gs_fillPlug): Isolation polystyrène; Stylo hachure (gs_penPlugFg): Général - Dessin 0.12; Stylo fond de hachure (gs_penPlugBg): Eléments 2D - Dessin; Côté montant édité: 1; Côté mur édité: 1; Numéro couche éditée: 1; Tourner couche: no; Considérer couches comme plâtre: no; Tourner épaiseur: 1; Orientation hachure: 1; Ligne de séparation tournant: no; Stylo ligne de séparation: Général - Dessin 0.12; Dernier côté sélectionné: no; Méthode fermeture changée auto.: no; Connexion en haut: no; Connexion en bas: no; Incrustation allège: no; Tailles incrustation mur (gs_parapet_sizes_st): Automatique; Tailles incrustation mur (iParapetSize): 1; Cotes largeur et longueur auto: yes; Incrustation base mur à (gs_parapet_bottom_st): Etage actuel; Incrustation base mur à (iParapetBottom): 1; Afficher allège masquée: yes; Type ligne allège masquée: 1; Angle d'ouverture de Châssis 1 (openingAngle_01): 0 deg; Angle d'ouverture de Châssis 1 (openingAngle2_01): 0 deg; Angle d'ouverture de Châssis 2 (openingAngle_02): 0 deg; Angle d'ouverture de Châssis 2 (openingAngle2_02): 0 deg; Angle d'ouverture de Châssis 3 (openingAngle_03): 0 deg; Angle d'ouverture de Châssis 3 (openingAngle2_03): 0 deg; Angle d'ouverture de Châssis 4 (openingAngle_04): 0 deg; Angle d'ouverture de Châssis 4 (openingAngle2_04): 0 deg; Angle d'ouverture de Châssis 5 (openingAngle_05): 0 deg; Angle d'ouverture de Châssis 5 (openingAngle2_05): 0 deg; Angle d'ouverture de Châssis 6 (openingAngle_06): 0 deg; Angle d'ouverture de Châssis 6 (openingAngle2_06): 0 deg; Angle d'ouverture de Châssis 7 (openingAngle_07): 0 deg; Angle d'ouverture de Châssis 7 (openingAngle2_07): 0 deg; Angle d'ouverture de Châssis 8 (openingAngle_08): 0 deg; Angle d'ouverture de Châssis 8 (openingAngle2_08): 0 deg; Angle d'ouverture de Châssis 9 (openingAngle_09): 0 deg; Angle d'ouverture de Châssis 9 (openingAngle2_09): 0 deg; Angle d'ouverture de Châssis 10 (openingAngle_10): 0 deg; Angle d'ouverture de Châssis 10 (openingAngle2_10): 0 deg; Angle ouverture en 2D: 0 deg; Suppl. Opt. vue pour aff. symb. 2D: yes; Type ligne ouverture: 1; Forme ligne ouverture (or_SwingType): Courbé; Forme ligne ouverture (or_iSwingType): 1; Forme ligne ouverture (or_SlidingType): Sans; Forme ligne ouverture (or_iSlidingType): 0; Stylo ligne ouverture 2D/3D (or_opLinePen): Général - Dessin 0.12; Stylo ligne ouverture 2D/3D (or_iOpLinePen): 1; Suppl. Opt. vue pour proj. 3D: no; Type ligne côté ouverture (or_opLineType3dIn): Ligne continue; Type ligne côté ouverture (or_iOpLineType3dIn): 0; Type ligne côté opposé (or_opLineType3dOut): Ligne continue; Type ligne côté opposé (or_iOpLineType3dOut): 0; Orient. ligne (or_oplineStyle): Poignée; Orient. ligne (or_iOplineStyle): 1; Stylo ligne non coupée: Ouvertures - Général; Stylo ligne coupée: Ouvertures - Général; Stylo ligne coupée chambranle des deux côtés: Ouvertures - Général; Ligne de contour de mur (gs_wcont_line): Des deux côtés; Ligne de contour de mur (iWallContourLine): 4; Type ligne contour int. mur masqué: 4; Type ligne contour ext. mur masqué: 4; Stylo ligne contour de mur: Ouvertures - Général; Motif de hachure cadre: Sans Trame; Stylo hachure cadre: Général - Dessin 0.12; Stylo fond de hachure cadre: Transparent; Motif de hachure châssis: Lame d'air; Stylo fond de châssis: Général - Dessin 0.12; Stylo fond de hachure châssis: Transparent; Type hachure non coupée: Sans Trame; Stylo hachure non coupée: Général - Dessin 0.12; Stylo fond de hachure non coupé: Transparent; Motif hachure symbole en plan: Sans Trame; Stylo appui 3D et non coupé: Général - Dessin 0.12; Stylo contour appui en Coupe: Général - Dessin 0.12; Motif hachure appui en Coupe: Sans Trame; Stylo hachure d'appui en Coupe: Général - Dessin 0.12; Stylo fond hachure appui Coupe: Transparent; Stylo contour isolation coupe: Général - Dessin 0.12; Motif hachure isolation Coupe: Isolation polystyrène; Stylo hachure isolation Coupe: Général - Dessin 0.12; Stylo fond hachure isol. Coupe: Fond - Couleur 1; Stylo latte 3D et non coupé: Général - Dessin 0.12; Stylo contour latte en Coupe: Général - Dessin 0.12; Motif hachure tablette en Coupe: Lame d'air; Stylo hachure tablette en Coupe: Fond - Couleur 1; Stylo fond hach. tablette Coupe: Fond - Couleur 1; Type hachure chambr. intérieur: Lame d'air; Stylo hachure chambr. int.: Fond - Couleur 1; Stylo fond hachure chambr. int.: Fond - Couleur 1; Type hachure chambr. ext.: Lame d'air; Stylo hachure chambr. ext.: Fond - Couleur 1; Stylo fond hachure chambr. ext.: Fond - Couleur 1; Motif de hachure arche coupe: Sans Trame; Stylo hachure en coupe d'arche: Fond - Couleur 1; Stylo fond hachure appui arche Coupe: Fond - Couleur 1; Motif de hachure de Coupe de Profil de ventilation: Lame d'air; Stylo de hachure de Coupe de Profil de ventilation: Fond - Couleur 1; Stylo de fond de hachure de Coupe de Profil de ventilation: Fond - Couleur 1; Type de ligne symbole volet: 1; Stylo ligne coupée volet: Général - Dessin 0.12; Stylo ligne non coupée 3D/Coupe: Général - Dessin 0.12; Type hachure coupée volet: Sans Trame; Stylo hachure coupée volet: Général - Dessin 0.12; Stylo fond hachure coupé volet: Fond de fenêtre; Motif de hachure d'isolation de volet: Dallage; Stylo de hachure d'isolation de volet: Général - Dessin 0.12; Stylo de fond d'isolation de volet: Fond de fenêtre; Jonction éléments cadree: 2; Stylo cadre: Ouvertures - Général; Stylo châssis: Ouvertures - Général; Stylo vitrage: Ouvertures - Général; Stylo linteau: Murs - Général; Ombre: yes; Surfaces de fenêtre uniformes: yes; Cadre extérieur: _Men ext_RAL9007; Cadre intérieur: _Men ext_RAL9007; Châssis extérieur: _Men ext_RAL9007; Châssis intérieur: _Men ext_RAL9007; Persiennes: _Men ext_RAL9007; Vitrage (gs_glass_mat): _Verre clair (rapide); Grille extérieure: _Men ext_RAL9007; Grille intérieure: _Men ext_RAL9007; Panneau solide extérieur: _Men ext_RAL9007; Panneau solide intérieur: _Men ext_RAL9007; Surfaces uniformes de chambranle: yes; Chambranle intérieur: _Men ext_RAL9007; Chambranle extérieur (gs_trim_out_mat): _Men ext_RAL9007; Profil Ventilation: _Métal BAVETTE; Panneau volet: _Men ext_RAL9007; Cadre panneau volet: _Men ext_RAL9007; Boîte volet roulant: _Métal - Acier inoxydable; Lames volet roulant: _Peinture - Blanc brillant; Rail volet roulant: _Peinture - Blanc brillant; Boîte store vénitien: _Métal - Acier inoxydable; Segments store vénitien: _Peinture - Blanc brillant; Rail volet coulissant: _Métal - Acier inoxydable; Appui (gs_sill_mat): _Métal BAVETTE; Mortier appui briques: _Enduit - Blanc nature; Tablette (gs_board_mat): _Men ext_RAL9007; Brique linteau: _Coupe3D_; Mortier linteau: _Enduit - Blanc nature; Clef de voûte linteau: _Pierre - Grès 01; Niche: _Mur int Hall; Surface poteau d'angle: _Men ext_RAL9007; Direction d'ouverture: 1; Afficher comme imposte: no; Stylo ligne tête de mur: Général - Dessin 0.12; Type de ligne tête de mur: 21; Prof. linteau sur symbole: no; Type ligne symbole prof. linteau: 21; Stylo symbole prof. linteau: Texte d'annotation - Général; Fenêtre appartient à Zone vers laquelle elle donne: no; Coût: 0; Surface vitrée totale (gs_list_glassarea_tmp): 0; Supplanter surface vitrée: no; Périmètre total vitrage: 0; Performance air libre (mm2/l/m): 0; Type de groupe (FM_Type): Objets par défaut; Type de groupe (iFMType): 1; Poids de l'objet: 0; Unité poids de l'objet: kg; Définition d'orientation de fenêtre: 0; Angle ouverture volet: 180 deg; Style lignes d'ouverture: 1
AC_Pset_RenovationAndPhasing - Renovation Status: Existing
Name | In | ID de l'élément = Lien et ID d'élément | Matériau de construction / Composite / Profil / Hachure = Type Hachure = Index hachure latérale ouverture | Nom de zone liée | Nom d'étage d'implantation | Numéro d'étage d'implantation | ID de Parent | À Zone | Dimensions ébrasure = Dimensions trou mur = Dimensions unité = Taille L x H nominale | Taille L x H x E nominale | Structure de Mur | Trou reprend surface latérale de mur = Utiliser hachures | Nombre de panneaux (gs_panes_number) | Châssis uniformes = Connexion à gauche = Afficher ligne d'ouverture | Type d'ouverture Châssis 1 = Type d'ouverture Châssis 2 | Type d'ouverture (gs_optype_m_01) = Type d'ouverture (gs_optype_m_02) = Type ligne contour int. mur | Type d'ouverture Châssis 3 = Type d'ouverture Châssis 5 = Type d'ouverture Châssis 6 = Type d'ouverture Châssis 7 | Type d'ouverture (gs_optype_m_03) = Type d'ouverture (gs_optype_m_05) = Type d'ouverture (gs_optype_m_06) = Type d'ouverture (gs_optype_m_07) | Type d'ouverture Châssis 4 | Type d'ouverture (gs_optype_m_04) | Type châssis (MullionStyle_00) = Type de châssis Châssis 3 | Type châssis (iMullionStyle_00) = Type châssis (iMullionStyle_03) | Type de châssis Châssis 1 | Type châssis (iMullionStyle_01) | Type de châssis Châssis 2 | Type châssis (iMullionStyle_02) | Nbre de panneaux verticaux Châssis 1 | Nbre de panneaux verticaux 2 Châssis 1 = Nbre de panneaux horizontaux 2 Châssis 1 = Type ébrasure (gs_reveal_type_int) | Type volet | Types volet activés | Type ébrasure (gs_reveal_type_new) | Connexion à droite | Type ligne contour ext. mur | Stylo hachure symbole en plan | Stylo fond hachure symbole plan | Surface vitrée totale (gs_list_glassarea) | Opération IFC (ifc_optypestr) | Opération IFC (ifc_optype)
2 x Baie salle-pluri-Sud -detail- | RDC | Baie salle-pluri-Sud -detail- | Sans Trame | Salle plurivalente | RDC | 0 | M ext pluri-Sud | Salle plurivalente | 100×240 | 100×240×36 | _M ext 18 +18 gris | no | 4 | yes | Vitrage fixe | 1 | Vitrage fixe | 1 | Accrochée par le bas | 7 | Pas de grille | 1 | Pas de grille | 1 | Pas de grille | 1 | 4 | 2 | 6 | 102 | Baie simple | no | 5 | Fond - Couleur 1 | Fond - Couleur 1 | 1.686 | Autre | 10
3 x Baie salle-pluri-Sud -detail- | RDC | Baie salle-pluri-Sud -detail- | Sans Trame | Salle plurivalente | RDC | 0 | M ext pluri-Sud | Salle plurivalente | 100×240 | 100×240×36 | _M ext 18 +18 gris | no | 4 | yes | Vitrage fixe | 1 | Vitrage fixe | 1 | Vitrage fixe | 1 | Pas de grille | 1 | Pas de grille | 1 | Pas de grille | 1 | 4 | 2 | 6 | 64 | Baie simple | yes | 5 | Fond - Couleur 1 | Fond - Couleur 1 | 1.818 | Autre | 10
2 x Baie salle-pluri-Sud -detail- | RDC | Baie salle-pluri-Sud -detail- | Sans Trame | Salle plurivalente | RDC | 0 | M ext pluri-Sud | Salle plurivalente | 100×240 | 100×240×36 | _M ext 18 +18 gris | no | 4 | yes | Vitrage fixe | 1 | Vitrage fixe | 1 | Accrochée par le bas | 7 | Pas de grille | 1 | Pas de grille | 1 | Pas de grille | 1 | 4 | 2 | 6 | 64 | Baie simple | yes | 5 | Fond - Couleur 1 | Fond - Couleur 1 | 1.686 | Autre | 10
Baie terrasse_ATTENTE | R+1 | Baie terrasse_ATTENTE | Sans Trame (3) | Terrasse | R+1 | 1 | MR-enCours | Circulation 3 | 126×290 | 126×290×7 | _M. ossat. terrasse | yes | 2 | no | Châssis fixe | 2 | Battant | 3 | Battant | 3 | Panneau solide | 15 | Divisé | 6 | Panneau solide | 15 | 1 | 1 | 1 | 126 | Pas d'ébrasure - arête | no | 1 | Général - Dessin 0.12 | Transparent | 2.51646 | Horizontal double | 3 | ArchiCADProperties - De Zone: Terrasse
Baie terrasse_ATTENTE | R+1 | Baie terrasse_ATTENTE | Sans Trame (3) | Terrasse | R+1 | 1 | MR-enCours | Circulation 3 | 126×290 | 126×290×7 | _M. ossat. terrasse | yes | 2 | no | Châssis fixe | 2 | Battant | 3 | Battant | 3 | Pas de grille | 1 | Divisé | 6 | Panneau solide | 15 | 1 | 1 | 1 | 102 | Pas d'ébrasure - arête | yes | 1 | Général - Dessin 0.12 | Transparent | 2.51646 | Horizontal double | 3 | ArchiCADProperties - De Zone: Terrasse
Baie terrasse_ATTENTE | R+1 | Baie terrasse_ATTENTE | Sans Trame (3) | Terrasse | R+1 | 1 | MR-enCours |  | 150×255 | 150×255×7 | _M. ossat. terrasse | yes | 1 | no | Châssis fixe | 2 | Battant | 3 | Battant | 3 | Panneau solide | 15 | Divisé | 6 | Panneau solide | 15 | 1 | 1 | 1 | 126 | Pas d'ébrasure - arête | no | 1 | Général - Dessin 0.12 | Transparent | 3.0686 | Simple | 1 | ArchiCADProperties - De Zone: Terrasse
Baie terrasse_ATTENTE | R+1 | Baie terrasse_ATTENTE | Sans Trame (3) | Circulation 3 | R+1 | 1 | MR-enCours | Circulation 3 | 128×290 | 128×290×7 | _M. ossat. terrasse | yes | 2 | no | Châssis fixe | 2 | Battant | 3 | Battant | 3 | Panneau solide | 15 | Divisé | 6 | Panneau solide | 15 | 1 | 1 | 1 | 126 | Pas d'ébrasure - arête | no | 1 | Général - Dessin 0.12 | Transparent | 2.5564 | Horizontal double | 3 | ArchiCADProperties - Zones conflictuelles: Terrasse

# IfcBuildingElementProxy: IFC Extruded (4)
In: RDC
AC_Pset_RenovationAndPhasing - Renovation Status: Existing
Name | Material
2 x _BA banché RAL9007 | _BA banché RAL9007
2 x Bois - Bardage | Bois - Bardage

# IfcBuildingElementProxy: IfcBuildingElementProxy (66)
Classification: Element de construction non défini (Classification Archicad)
ArchiCADProperties - Verrouillé: no; État de rénovation: Existant; Affichage sur filtre de rénovation: Tous les filtres appropriés
AC_Pset_RenovationAndPhasing - Renovation Status: Existing
Name | In | Material | ID de l'élément = Lien et ID d'élément | Calque | Nom d'étage d'implantation | Numéro d'étage d'implantation | Type d'élément | Étage supérieur lié absolu | Étage supérieur lié relatif | Étage supérieur lié | ID de Parent | Matériaux de construction (Tous) | Surfaces (Toutes) | Nom Élément de Bibliothèque | Index volée | Type de segment | Index de marche
VOLEE-002 | RDC | _BA banché | VOLEE-002 | 10_M refendGO__ | RDC | 0 | Structure (Escalier) | R+1 | Étage d'implantation + 1 | Étage d'implantation + 1 (R+1) | ESC-001 | _BA banché | _Béton - Lissé | ArchiCADProperties - Matériau de construction / Composite / Profil / Hachure: _BA banché; Type construction: Monolithique; Type forme: Plat; Position structure escalier: Sous l'escalier; Index volée structure escalier: 1
C-MARCHE-001 | RDC | Bois - Massif 01 | C-MARCHE-001 | 10_M refendGO__ | RDC | 0 | Contremarche (Escalier) | R+1 | Étage d'implantation + 1 | Étage d'implantation + 1 (R+1) | ESC-001 | Bois - Massif 01 | _Sol PVC couloir | Contremarche intégrée | 1 | Volée | 1
C-MARCHE-002 | RDC | Bois - Massif 01 | C-MARCHE-002 | 10_M refendGO__ | RDC | 0 | Contremarche (Escalier) | R+1 | Étage d'implantation + 1 | Étage d'implantation + 1 (R+1) | ESC-001 | Bois - Massif 01 | _Sol PVC couloir | Contremarche intégrée | 1 | Volée | 2
C-MARCHE-003 | RDC | Bois - Massif 01 | C-MARCHE-003 | 10_M refendGO__ | RDC | 0 | Contremarche (Escalier) | R+1 | Étage d'implantation + 1 | Étage d'implantation + 1 (R+1) | ESC-001 | Bois - Massif 01 | _Sol PVC couloir | Contremarche intégrée | 1 | Volée | 3
C-MARCHE-004 | RDC | Bois - Massif 01 | C-MARCHE-004 | 10_M refendGO__ | RDC | 0 | Contremarche (Escalier) | R+1 | Étage d'implantation + 1 | Étage d'implantation + 1 (R+1) | ESC-001 | Bois - Massif 01 | _Sol PVC couloir | Contremarche intégrée | 1 | Volée | 4
C-MARCHE-005 | RDC | Bois - Massif 01 | C-MARCHE-005 | 10_M refendGO__ | RDC | 0 | Contremarche (Escalier) | R+1 | Étage d'implantation + 1 | Étage d'implantation + 1 (R+1) | ESC-001 | Bois - Massif 01 | _Sol PVC couloir | Contremarche intégrée | 1 | Volée | 5
C-MARCHE-006 | RDC | Bois - Massif 01 | C-MARCHE-006 | 10_M refendGO__ | RDC | 0 | Contremarche (Escalier) | R+1 | Étage d'implantation + 1 | Étage d'implantation + 1 (R+1) | ESC-001 | Bois - Massif 01 | _Sol PVC couloir | Contremarche intégrée | 1 | Volée | 6
C-MARCHE-007 | RDC | Bois - Massif 01 | C-MARCHE-007 | 10_M refendGO__ | RDC | 0 | Contremarche (Escalier) | R+1 | Étage d'implantation + 1 | Étage d'implantation + 1 (R+1) | ESC-001 | Bois - Massif 01 | _Sol PVC couloir | Contremarche intégrée | 1 | Volée | 7
C-MARCHE-008 | RDC | Bois - Massif 01 | C-MARCHE-008 | 10_M refendGO__ | RDC | 0 | Contremarche (Escalier) | R+1 | Étage d'implantation + 1 | Étage d'implantation + 1 (R+1) | ESC-001 | Bois - Massif 01 | _Sol PVC couloir | Contremarche intégrée | 1 | Volée | 8
C-MARCHE-009 | RDC | Bois - Massif 01 | C-MARCHE-009 | 10_M refendGO__ | RDC | 0 | Contremarche (Escalier) | R+1 | Étage d'implantation + 1 | Étage d'implantation + 1 (R+1) | ESC-001 | Bois - Massif 01 | _Sol PVC couloir | Contremarche intégrée | 1 | Volée | 9
C-MARCHE-010 | RDC | Bois - Massif 01 | C-MARCHE-010 | 10_M refendGO__ | RDC | 0 | Contremarche (Escalier) | R+1 | Étage d'implantation + 1 | Étage d'implantation + 1 (R+1) | ESC-001 | Bois - Massif 01 | _Sol PVC couloir | Contremarche intégrée | 1 | Volée | 10
C-MARCHE-011 | RDC | Bois - Massif 01 | C-MARCHE-011 | 10_M refendGO__ | RDC | 0 | Contremarche (Escalier) | R+1 | Étage d'implantation + 1 | Étage d'implantation + 1 (R+1) | ESC-001 | Bois - Massif 01 | _Sol PVC couloir | Contremarche intégrée | 1 | Volée | 11
C-MARCHE-012 | RDC | Bois - Massif 01 | C-MARCHE-012 | 10_M refendGO__ | RDC | 0 | Contremarche (Escalier) | R+1 | Étage d'implantation + 1 | Étage d'implantation + 1 (R+1) | ESC-001 | Bois - Massif 01 | _Sol PVC couloir | Contremarche intégrée | 1 | Volée | 12
C-MARCHE-013 | RDC | Bois - Massif 01 | C-MARCHE-013 | 10_M refendGO__ | RDC | 0 | Contremarche (Escalier) | R+1 | Étage d'implantation + 1 | Étage d'implantation + 1 (R+1) | ESC-001 | Bois - Massif 01 | _Sol PVC couloir | Contremarche intégrée | 1 | Volée | 13
C-MARCHE-014 | RDC | Bois - Massif 01 | C-MARCHE-014 | 10_M refendGO__ | RDC | 0 | Contremarche (Escalier) | R+1 | Étage d'implantation + 1 | Étage d'implantation + 1 (R+1) | ESC-001 | Bois - Massif 01 | _Sol PVC couloir | Contremarche intégrée | 1 | Volée | 14
C-MARCHE-015 | RDC | Bois - Massif 01 | C-MARCHE-015 | 10_M refendGO__ | RDC | 0 | Contremarche (Escalier) | R+1 | Étage d'implantation + 1 | Étage d'implantation + 1 (R+1) | ESC-001 | Bois - Massif 01 | _Sol PVC couloir | Contremarche intégrée | 1 | Volée | 15
C-MARCHE-016 | RDC | Bois - Massif 01 | C-MARCHE-016 | 10_M refendGO__ | RDC | 0 | Contremarche (Escalier) | R+1 | Étage d'implantation + 1 | Étage d'implantation + 1 (R+1) | ESC-001 | Bois - Massif 01 | _Sol PVC couloir | Contremarche intégrée | 1 | Volée | 16
C-MARCHE-017 | RDC | Bois - Massif 01 | C-MARCHE-017 | 10_M refendGO__ | RDC | 0 | Contremarche (Escalier) | R+1 | Étage d'implantation + 1 | Étage d'implantation + 1 (R+1) | ESC-001 | Bois - Massif 01 | _Sol PVC couloir | Contremarche intégrée | 1 | Volée | 17
C-MARCHE-018 | RDC | Bois - Massif 01 | C-MARCHE-018 | 10_M refendGO__ | RDC | 0 | Contremarche (Escalier) | R+1 | Étage d'implantation + 1 | Étage d'implantation + 1 (R+1) | ESC-001 | Bois - Massif 01 | _Sol PVC couloir | Contremarche intégrée | 1 | Volée | 18
C-MARCHE-019 | RDC | Bois - Massif 01 | C-MARCHE-019 | 10_M refendGO__ | RDC | 0 | Contremarche (Escalier) | R+1 | Étage d'implantation + 1 | Étage d'implantation + 1 (R+1) | ESC-001 | Bois - Massif 01 | _Sol PVC couloir | Contremarche intégrée | 1 | Volée | 19
C-MARCHE-020 | RDC | Bois - Massif 01 | C-MARCHE-020 | 10_M refendGO__ | RDC | 0 | Contremarche (Escalier) | R+1 | Étage d'implantation + 1 | Étage d'implantation + 1 (R+1) | ESC-001 | Bois - Massif 01 | _Sol PVC couloir | Contremarche intégrée | 1 | Volée | 20
MARCHE-001 | RDC | Bois - Massif 01 | MARCHE-001 | 10_M refendGO__ | RDC | 0 | Giron (Escalier) | R+1 | Étage d'implantation + 1 | Étage d'implantation + 1 (R+1) | ESC-001 | Bois - Massif 01 | _Plastique - Caoutchouc (2); _Sol PVC couloir | Marche 21 | 1 | Volée | 1
MARCHE-002 | RDC | Bois - Massif 01 | MARCHE-002 | 10_M refendGO__ | RDC | 0 | Giron (Escalier) | R+1 | Étage d'implantation + 1 | Étage d'implantation + 1 (R+1) | ESC-001 | Bois - Massif 01 | _Plastique - Caoutchouc (2); _Sol PVC couloir | Marche 21 | 1 | Volée | 2
MARCHE-003 | RDC | Bois - Massif 01 | MARCHE-003 | 10_M refendGO__ | RDC | 0 | Giron (Escalier) | R+1 | Étage d'implantation + 1 | Étage d'implantation + 1 (R+1) | ESC-001 | Bois - Massif 01 | _Plastique - Caoutchouc (2); _Sol PVC couloir | Marche 21 | 1 | Volée | 3
MARCHE-004 | RDC | Bois - Massif 01 | MARCHE-004 | 10_M refendGO__ | RDC | 0 | Giron (Escalier) | R+1 | Étage d'implantation + 1 | Étage d'implantation + 1 (R+1) | ESC-001 | Bois - Massif 01 | _Plastique - Caoutchouc (2); _Sol PVC couloir | Marche 21 | 1 | Volée | 4
MARCHE-005 | RDC | Bois - Massif 01 | MARCHE-005 | 10_M refendGO__ | RDC | 0 | Giron (Escalier) | R+1 | Étage d'implantation + 1 | Étage d'implantation + 1 (R+1) | ESC-001 | Bois - Massif 01 | _Plastique - Caoutchouc (2); _Sol PVC couloir | Marche 21 | 1 | Volée | 5
MARCHE-006 | RDC | Bois - Massif 01 | MARCHE-006 | 10_M refendGO__ | RDC | 0 | Giron (Escalier) | R+1 | Étage d'implantation + 1 | Étage d'implantation + 1 (R+1) | ESC-001 | Bois - Massif 01 | _Plastique - Caoutchouc (2); _Sol PVC couloir | Marche 21 | 1 | Volée | 6
MARCHE-007 | RDC | Bois - Massif 01 | MARCHE-007 | 10_M refendGO__ | RDC | 0 | Giron (Escalier) | R+1 | Étage d'implantation + 1 | Étage d'implantation + 1 (R+1) | ESC-001 | Bois - Massif 01 | _Plastique - Caoutchouc (2); _Sol PVC couloir | Marche 21 | 1 | Volée | 7
MARCHE-008 | RDC | Bois - Massif 01 | MARCHE-008 | 10_M refendGO__ | RDC | 0 | Giron (Escalier) | R+1 | Étage d'implantation + 1 | Étage d'implantation + 1 (R+1) | ESC-001 | Bois - Massif 01 | _Plastique - Caoutchouc (2); _Sol PVC couloir | Marche 21 | 1 | Volée | 8
MARCHE-009 | RDC | Bois - Massif 01 | MARCHE-009 | 10_M refendGO__ | RDC | 0 | Giron (Escalier) | R+1 | Étage d'implantation + 1 | Étage d'implantation + 1 (R+1) | ESC-001 | Bois - Massif 01 | _Plastique - Caoutchouc (2); _Sol PVC couloir | Marche 21 | 1 | Volée | 9
MARCHE-010 | RDC | Bois - Massif 01 | MARCHE-010 | 10_M refendGO__ | RDC | 0 | Giron (Escalier) | R+1 | Étage d'implantation + 1 | Étage d'implantation + 1 (R+1) | ESC-001 | Bois - Massif 01 | _Plastique - Caoutchouc (2); _Sol PVC couloir | Marche 21 | 1 | Volée | 10
MARCHE-011 | RDC | Bois - Massif 01 | MARCHE-011 | 10_M refendGO__ | RDC | 0 | Giron (Escalier) | R+1 | Étage d'implantation + 1 | Étage d'implantation + 1 (R+1) | ESC-001 | Bois - Massif 01 | _Plastique - Caoutchouc (2); _Sol PVC couloir | Marche 21 | 1 | Volée | 11
MARCHE-012 | RDC | Bois - Massif 01 | MARCHE-012 | 10_M refendGO__ | RDC | 0 | Giron (Escalier) | R+1 | Étage d'implantation + 1 | Étage d'implantation + 1 (R+1) | ESC-001 | Bois - Massif 01 | _Plastique - Caoutchouc (2); _Sol PVC couloir | Marche 21 | 1 | Volée | 12
MARCHE-013 | RDC | Bois - Massif 01 | MARCHE-013 | 10_M refendGO__ | RDC | 0 | Giron (Escalier) | R+1 | Étage d'implantation + 1 | Étage d'implantation + 1 (R+1) | ESC-001 | Bois - Massif 01 | _Plastique - Caoutchouc (2); _Sol PVC couloir | Marche 21 | 1 | Volée | 13
MARCHE-014 | RDC | Bois - Massif 01 | MARCHE-014 | 10_M refendGO__ | RDC | 0 | Giron (Escalier) | R+1 | Étage d'implantation + 1 | Étage d'implantation + 1 (R+1) | ESC-001 | Bois - Massif 01 | _Plastique - Caoutchouc (2); _Sol PVC couloir | Marche 21 | 1 | Volée | 14
MARCHE-015 | RDC | Bois - Massif 01 | MARCHE-015 | 10_M refendGO__ | RDC | 0 | Giron (Escalier) | R+1 | Étage d'implantation + 1 | Étage d'implantation + 1 (R+1) | ESC-001 | Bois - Massif 01 | _Plastique - Caoutchouc (2); _Sol PVC couloir | Marche 21 | 1 | Volée | 15
MARCHE-016 | RDC | Bois - Massif 01 | MARCHE-016 | 10_M refendGO__ | RDC | 0 | Giron (Escalier) | R+1 | Étage d'implantation + 1 | Étage d'implantation + 1 (R+1) | ESC-001 | Bois - Massif 01 | _Plastique - Caoutchouc (2); _Sol PVC couloir | Marche 21 | 1 | Volée | 16
MARCHE-017 | RDC | Bois - Massif 01 | MARCHE-017 | 10_M refendGO__ | RDC | 0 | Giron (Escalier) | R+1 | Étage d'implantation + 1 | Étage d'implantation + 1 (R+1) | ESC-001 | Bois - Massif 01 | _Plastique - Caoutchouc (2); _Sol PVC couloir | Marche 21 | 1 | Volée | 17
MARCHE-018 | RDC | Bois - Massif 01 | MARCHE-018 | 10_M refendGO__ | RDC | 0 | Giron (Escalier) | R+1 | Étage d'implantation + 1 | Étage d'implantation + 1 (R+1) | ESC-001 | Bois - Massif 01 | _Plastique - Caoutchouc (2); _Sol PVC couloir | Marche 21 | 1 | Volée | 18
MARCHE-019 | RDC | Bois - Massif 01 | MARCHE-019 | 10_M refendGO__ | RDC | 0 | Giron (Escalier) | R+1 | Étage d'implantation + 1 | Étage d'implantation + 1 (R+1) | ESC-001 | Bois - Massif 01 | _Plastique - Caoutchouc (2); _Sol PVC couloir | Marche 21 | 1 | Volée | 19
MARCHE-020 | RDC | Bois - Massif 01 | MARCHE-020 | 10_M refendGO__ | RDC | 0 | Giron (Escalier) | R+1 | Étage d'implantation + 1 | Étage d'implantation + 1 (R+1) | ESC-001 | Bois - Massif 01 | _Plastique - Caoutchouc (2); _Sol PVC couloir | Marche 21 | 1 | Volée | 20
VOLEE-002 | RDC | _BA banché | VOLEE-002 | 10_M x baseGO__ | RDC | 0 | Structure (Escalier) | R+1 | Étage d'implantation + 1 | Étage d'implantation + 1 (R+1) | ESC-2 | _BA banché | _Béton - Lissé | ArchiCADProperties - Matériau de construction / Composite / Profil / Hachure: _BA banché; Type construction: Monolithique; Type forme: Plat; Position structure escalier: Sous l'escalier; Index volée structure escalier: 1
MARCHE-021 | RDC | _BA banché | MARCHE-021 | 10_M x baseGO__ | RDC | 0 | Giron (Escalier) | R+1 | Étage d'implantation + 1 | Étage d'implantation + 1 (R+1) | ESC-2 | _BA banché | _Béton - Lissé | Marche 21 | 1 | Volée | 1
MARCHE-021 | RDC | _BA banché | MARCHE-021 | 10_M x baseGO__ | RDC | 0 | Giron (Escalier) | R+1 | Étage d'implantation + 1 | Étage d'implantation + 1 (R+1) | ESC-2 | _BA banché | _Béton - Lissé | Marche 21 | 1 | Volée | 2
MARCHE-021 | RDC | _BA banché | MARCHE-021 | 10_M x baseGO__ | RDC | 0 | Giron (Escalier) | R+1 | Étage d'implantation + 1 | Étage d'implantation + 1 (R+1) | ESC-2 | _BA banché | _Béton - Lissé | Marche 21 | 1 | Volée | 3
MARCHE-021 | RDC | _BA banché | MARCHE-021 | 10_M x baseGO__ | RDC | 0 | Giron (Escalier) | R+1 | Étage d'implantation + 1 | Étage d'implantation + 1 (R+1) | ESC-2 | _BA banché | _Béton - Lissé | Marche 21 | 1 | Volée | 4
MARCHE-021 | RDC | _BA banché | MARCHE-021 | 10_M x baseGO__ | RDC | 0 | Giron (Escalier) | R+1 | Étage d'implantation + 1 | Étage d'implantation + 1 (R+1) | ESC-2 | _BA banché | _Béton - Lissé | Marche 21 | 1 | Volée | 5
MARCHE-021 | RDC | _BA banché | MARCHE-021 | 10_M x baseGO__ | RDC | 0 | Giron (Escalier) | R+1 | Étage d'implantation + 1 | Étage d'implantation + 1 (R+1) | ESC-2 | _BA banché | _Béton - Lissé | Marche 21 | 1 | Volée | 6
MARCHE-021 | RDC | _BA banché | MARCHE-021 | 10_M x baseGO__ | RDC | 0 | Giron (Escalier) | R+1 | Étage d'implantation + 1 | Étage d'implantation + 1 (R+1) | ESC-2 | _BA banché | _Béton - Lissé | Marche 21 | 1 | Volée | 7
MARCHE-021 | RDC | _BA banché | MARCHE-021 | 10_M x baseGO__ | RDC | 0 | Giron (Escalier) | R+1 | Étage d'implantation + 1 | Étage d'implantation + 1 (R+1) | ESC-2 | _BA banché | _Béton - Lissé | Marche 21 | 1 | Volée | 8
MARCHE-021 | RDC | _BA banché | MARCHE-021 | 10_M x baseGO__ | RDC | 0 | Giron (Escalier) | R+1 | Étage d'implantation + 1 | Étage d'implantation + 1 (R+1) | ESC-2 | _BA banché | _Béton - Lissé | Marche 21 | 1 | Volée | 9
MARCHE-021 | RDC | _BA banché | MARCHE-021 | 10_M x baseGO__ | RDC | 0 | Giron (Escalier) | R+1 | Étage d'implantation + 1 | Étage d'implantation + 1 (R+1) | ESC-2 | _BA banché | _Béton - Lissé | Marche 21 | 1 | Volée | 10
MARCHE-021 | RDC | _BA banché | MARCHE-021 | 10_M x baseGO__ | RDC | 0 | Giron (Escalier) | R+1 | Étage d'implantation + 1 | Étage d'implantation + 1 (R+1) | ESC-2 | _BA banché | _Béton - Lissé | Marche 21 | 1 | Volée | 11
MARCHE-021 | RDC | _BA banché | MARCHE-021 | 10_M x baseGO__ | RDC | 0 | Giron (Escalier) | R+1 | Étage d'implantation + 1 | Étage d'implantation + 1 (R+1) | ESC-2 | _BA banché | _Béton - Lissé | Marche 21 | 1 | Volée | 12
MARCHE-021 | RDC | _BA banché | MARCHE-021 | 10_M x baseGO__ | RDC | 0 | Giron (Escalier) | R+1 | Étage d'implantation + 1 | Étage d'implantation + 1 (R+1) | ESC-2 | _BA banché | _Béton - Lissé | Marche 21 | 1 | Volée | 13
MARCHE-021 | RDC | _BA banché | MARCHE-021 | 10_M x baseGO__ | RDC | 0 | Giron (Escalier) | R+1 | Étage d'implantation + 1 | Étage d'implantation + 1 (R+1) | ESC-2 | _BA banché | _Béton - Lissé | Marche 21 | 1 | Volée | 14
MARCHE-021 | RDC | _BA banché | MARCHE-021 | 10_M x baseGO__ | RDC | 0 | Giron (Escalier) | R+1 | Étage d'implantation + 1 | Étage d'implantation + 1 (R+1) | ESC-2 | _BA banché | _Béton - Lissé | Marche 21 | 1 | Volée | 15
MARCHE-021 | RDC | _BA banché | MARCHE-021 | 10_M x baseGO__ | RDC | 0 | Giron (Escalier) | R+1 | Étage d'implantation + 1 | Étage d'implantation + 1 (R+1) | ESC-2 | _BA banché | _Béton - Lissé | Marche 21 | 1 | Volée | 16
MARCHE-021 | RDC | _BA banché | MARCHE-021 | 10_M x baseGO__ | RDC | 0 | Giron (Escalier) | R+1 | Étage d'implantation + 1 | Étage d'implantation + 1 (R+1) | ESC-2 | _BA banché | _Béton - Lissé | Marche 21 | 1 | Volée | 17
MARCHE-021 | RDC | _BA banché | MARCHE-021 | 10_M x baseGO__ | RDC | 0 | Giron (Escalier) | R+1 | Étage d'implantation + 1 | Étage d'implantation + 1 (R+1) | ESC-2 | _BA banché | _Béton - Lissé | Marche 21 | 1 | Volée | 18
MARCHE-021 | RDC | _BA banché | MARCHE-021 | 10_M x baseGO__ | RDC | 0 | Giron (Escalier) | R+1 | Étage d'implantation + 1 | Étage d'implantation + 1 (R+1) | ESC-2 | _BA banché | _Béton - Lissé | Marche 21 | 1 | Volée | 19
MARCHE-021 | RDC | _BA banché | MARCHE-021 | 10_M x baseGO__ | RDC | 0 | Giron (Escalier) | R+1 | Étage d'implantation + 1 | Étage d'implantation + 1 (R+1) | ESC-2 | _BA banché | _Béton - Lissé | Marche 21 | 1 | Volée | 20
HANDRAIL END - 001 | R+1 | Bois - Massif 01 | HANDRAIL END - 001 | 20_Serrurerie______ | R+1 | 1 | Extrémité de main courante (Garde-corps) |  |  |  | main-courante esc ext | Bois - Massif 01 | _Men ext_RAL9007 | ArchiCADProperties - Matériau de construction / Composite / Profil / Hachure: Main courante ronde; Profil complexe: Main courante ronde; Index de segment: 2
MOBILIER-001 | R+1 | Bois - Massif 01 |  | 20_Serrurerie______ | R+1 | 1 | Main courante (Garde-corps) |  |  |  | main-courante esc ext | Bois - Massif 01 | _Men ext_RAL9007 | Garde-corps profilé 21 | ArchiCADProperties - Matériau de construction / Composite / Profil / Hachure: Main courante ronde; Profil complexe: Main courante ronde; Index de segment: 2
MOBILIER-001 | R+1 | Bois - Massif 01 |  | 20_Serrurerie______ | R+1 | 1 | Main courante (Garde-corps) |  |  |  | main-courante esc ext | Bois - Massif 01; Métal - Inox | _Men ext_RAL9007; _Métal - Zinc | Garde-corps profilé 21 | ArchiCADProperties - Matériau de construction / Composite / Profil / Hachure: Main courante ronde; Profil complexe: Main courante ronde; Index de segment: 3
MOBILIER-001 | R+1 | Bois - Massif 01 |  | 20_Serrurerie______ | R+1 | 1 | Main courante (Garde-corps) |  |  |  | main-courante esc ext | Bois - Massif 01 | _Men ext_RAL9007 | Garde-corps profilé 21 | ArchiCADProperties - Matériau de construction / Composite / Profil / Hachure: Main courante ronde; Profil complexe: Main courante ronde; Index de segment: 4

# IfcBuildingElementProxy: Panneau principal 160 x 147 x 20, Panel-Main-253
In: R+1
Classification: Element de construction non défini (Classification Archicad); Material: Matériau de construction IFC
ArchiCADProperties - ID de l'élément: Panel-Main-253; Lien et ID d'élément: Panel-Main-253; Calque: 10_M x baseGO__; Nom Élément de Bibliothèque: Panneau MR 21; Matériau de construction / Composite / Profil / Hachure: MANQUANT; Matériau de construction: MANQUANT; Verrouillé: no; Nom d'étage d'implantation: R+1; Numéro d'étage d'implantation: 1; Type d'élément: Panneau (Mur-rideau); ID de Parent: pare-vue CTA; Surfaces (Toutes): _Bois-Horiz ocre; Angle d'inclinaison: 90 deg; Surface latérale: GENERAL; État de rénovation: Existant; Affichage sur filtre de rénovation: Tous les filtres appropriés; Abbréviation d'orientation: E; Angle par rapport nord: -100.24 deg; Fonction de panneau: Fixe; Surface intérieure: GENERAL; Surface extérieure: GENERAL; Catégorie de panneau: Panneau principal; Type de panneau: Panneau MR 21; Angle d'inclinaison Panneau mur-rideau: 90 deg
AC_Pset_Panneau_MR_21 - Afficher points chauds 2D en 3D: yes; Modèle schématique automatique: yes; 0-fixe, 1-porte, 2-fenêtre: 0; Direction haut: 0 deg; Direction d'ouverture (ac_openingDir): 0; Angle panneau arrière: 90 deg; Niveau de détail 2D: -1; Stylo coupe: Eléments 2D - Général; Hachure coupée: Sans Trame; Stylo hachure coupée: Fond - Couleur 1; Stylo fond hachure coupée: Fond - Couleur 1; Hachure revêtement: Hachure solide; Hachure intérieure: Bois; Stylo hachure revêtement: Eléments 2D - Général; Stylo hachure intérieure: Eléments 2D - Général; Stylo fond hachure revêtement: Transparent; Stylo fond hachure intérieure: Transparent; Ombre: yes; Intérieur: _Bois-Horiz ocre; Extérieur: _Bois-Horiz ocre; Coût: 0; Surface vitrée totale (gs_list_glassarea_tmp): 0; Supplanter surface vitrée: no; Surface vitrée totale (gs_list_glassarea): 0; Périmètre total vitrage: 0; Type de groupe (FM_Type): Objets par défaut; Type de groupe (iFMType): 1; Numéro de série: Sans; Poids de l'objet: 0; Unité poids de l'objet: kg
AC_Pset_RenovationAndPhasing - Renovation Status: Non défini

# IfcBuildingElementProxy: Panneau principal 160 x 170 x 20 (15)
In: R+1
Classification: Element de construction non défini (Classification Archicad); Material: Matériau de construction IFC
ArchiCADProperties - Calque: 10_M x baseGO__; Nom Élément de Bibliothèque: Panneau MR 21; Matériau de construction / Composite / Profil / Hachure: MANQUANT; Matériau de construction: MANQUANT; Verrouillé: no; Nom d'étage d'implantation: R+1; Numéro d'étage d'implantation: 1; Type d'élément: Panneau (Mur-rideau); ID de Parent: pare-vue CTA; Surfaces (Toutes): _Bois-Horiz ocre; Angle d'inclinaison: 90 deg; Surface latérale: GENERAL; État de rénovation: Existant; Affichage sur filtre de rénovation: Tous les filtres appropriés; Abbréviation d'orientation: E; Angle par rapport nord: -100.24 deg; Fonction de panneau: Fixe; Surface intérieure: GENERAL; Surface extérieure: GENERAL; Catégorie de panneau: Panneau principal; Type de panneau: Panneau MR 21; Angle d'inclinaison Panneau mur-rideau: 90 deg
AC_Pset_Panneau_MR_21 - Afficher points chauds 2D en 3D: yes; Modèle schématique automatique: yes; 0-fixe, 1-porte, 2-fenêtre: 0; Direction haut: 0 deg; Direction d'ouverture (ac_openingDir): 0; Angle panneau arrière: 90 deg; Niveau de détail 2D: -1; Stylo coupe: Eléments 2D - Général; Hachure coupée: Sans Trame; Stylo hachure coupée: Fond - Couleur 1; Stylo fond hachure coupée: Fond - Couleur 1; Hachure revêtement: Hachure solide; Hachure intérieure: Bois; Stylo hachure revêtement: Eléments 2D - Général; Stylo hachure intérieure: Eléments 2D - Général; Stylo fond hachure revêtement: Transparent; Stylo fond hachure intérieure: Transparent; Ombre: yes; Intérieur: _Bois-Horiz ocre; Extérieur: _Bois-Horiz ocre; Coût: 0; Surface vitrée totale (gs_list_glassarea_tmp): 0; Supplanter surface vitrée: no; Surface vitrée totale (gs_list_glassarea): 0; Périmètre total vitrage: 0; Type de groupe (FM_Type): Objets par défaut; Type de groupe (iFMType): 1; Numéro de série: Sans; Poids de l'objet: 0; Unité poids de l'objet: kg
AC_Pset_RenovationAndPhasing - Renovation Status: Non défini
Name | ID de l'élément = Lien et ID d'élément
Panel-Main-681 | Panel-Main-681
Panel-Main-682 | Panel-Main-682
Panel-Main-673 | Panel-Main-673
Panel-Main-688 | Panel-Main-688
Panel-Main-687 | Panel-Main-687
Panel-Main-674 | Panel-Main-674
Panel-Main-677 | Panel-Main-677
Panel-Main-683 | Panel-Main-683
Panel-Main-685 | Panel-Main-685
Panel-Main-678 | Panel-Main-678
Panel-Main-675 | Panel-Main-675
Panel-Main-680 | Panel-Main-680
Panel-Main-676 | Panel-Main-676
Panel-Main-679 | Panel-Main-679
Panel-Main-686 | Panel-Main-686

# IfcBuildingElementProxy: Panneau principal 190 x 147 x 20, Panel-Main-798
In: R+1
Classification: Element de construction non défini (Classification Archicad); Material: Matériau de construction IFC
ArchiCADProperties - ID de l'élément: Panel-Main-798; Lien et ID d'élément: Panel-Main-798; Calque: 10_M x baseGO__; Nom Élément de Bibliothèque: Panneau MR 21; Matériau de construction / Composite / Profil / Hachure: MANQUANT; Matériau de construction: MANQUANT; Verrouillé: no; Nom d'étage d'implantation: R+1; Numéro d'étage d'implantation: 1; Type d'élément: Panneau (Mur-rideau); ID de Parent: pare-vue CTA; Surfaces (Toutes): _Bois-Horiz ocre; Angle d'inclinaison: 90 deg; Surface latérale: GENERAL; État de rénovation: Existant; Affichage sur filtre de rénovation: Tous les filtres appropriés; Abbréviation d'orientation: S; Angle par rapport nord: 169.76 deg; Fonction de panneau: Fixe; Surface intérieure: GENERAL; Surface extérieure: GENERAL; Catégorie de panneau: Panneau principal; Type de panneau: Panneau MR 21; Angle d'inclinaison Panneau mur-rideau: 90 deg
AC_Pset_Panneau_MR_21 - Afficher points chauds 2D en 3D: yes; Modèle schématique automatique: yes; 0-fixe, 1-porte, 2-fenêtre: 0; Direction haut: 0 deg; Direction d'ouverture (ac_openingDir): 0; Angle panneau arrière: 90 deg; Niveau de détail 2D: -1; Stylo coupe: Eléments 2D - Général; Hachure coupée: Sans Trame; Stylo hachure coupée: Fond - Couleur 1; Stylo fond hachure coupée: Fond - Couleur 1; Hachure revêtement: Hachure solide; Hachure intérieure: Bois; Stylo hachure revêtement: Eléments 2D - Général; Stylo hachure intérieure: Eléments 2D - Général; Stylo fond hachure revêtement: Transparent; Stylo fond hachure intérieure: Transparent; Ombre: yes; Intérieur: _Bois-Horiz ocre; Extérieur: _Bois-Horiz ocre; Coût: 0; Surface vitrée totale (gs_list_glassarea_tmp): 0; Supplanter surface vitrée: no; Surface vitrée totale (gs_list_glassarea): 0; Périmètre total vitrage: 0; Type de groupe (FM_Type): Objets par défaut; Type de groupe (iFMType): 1; Numéro de série: Sans; Poids de l'objet: 0; Unité poids de l'objet: kg
AC_Pset_RenovationAndPhasing - Renovation Status: Non défini

# IfcBuildingElementProxy: Panneau principal 190 x 170 x 20 (16)
In: R+1
Classification: Element de construction non défini (Classification Archicad); Material: Matériau de construction IFC
ArchiCADProperties - Calque: 10_M x baseGO__; Nom Élément de Bibliothèque: Panneau MR 21; Matériau de construction / Composite / Profil / Hachure: MANQUANT; Matériau de construction: MANQUANT; Verrouillé: no; Nom d'étage d'implantation: R+1; Numéro d'étage d'implantation: 1; Type d'élément: Panneau (Mur-rideau); ID de Parent: pare-vue CTA; Surfaces (Toutes): _Bois-Horiz ocre; Angle d'inclinaison: 90 deg; Surface latérale: GENERAL; État de rénovation: Existant; Affichage sur filtre de rénovation: Tous les filtres appropriés; Abbréviation d'orientation: S; Angle par rapport nord: 169.76 deg; Fonction de panneau: Fixe; Surface intérieure: GENERAL; Surface extérieure: GENERAL; Catégorie de panneau: Panneau principal; Type de panneau: Panneau MR 21; Angle d'inclinaison Panneau mur-rideau: 90 deg
AC_Pset_Panneau_MR_21 - Afficher points chauds 2D en 3D: yes; Modèle schématique automatique: yes; 0-fixe, 1-porte, 2-fenêtre: 0; Direction haut: 0 deg; Direction d'ouverture (ac_openingDir): 0; Angle panneau arrière: 90 deg; Niveau de détail 2D: -1; Stylo coupe: Eléments 2D - Général; Hachure coupée: Sans Trame; Stylo hachure coupée: Fond - Couleur 1; Stylo fond hachure coupée: Fond - Couleur 1; Hachure revêtement: Hachure solide; Hachure intérieure: Bois; Stylo hachure revêtement: Eléments 2D - Général; Stylo hachure intérieure: Eléments 2D - Général; Stylo fond hachure revêtement: Transparent; Stylo fond hachure intérieure: Transparent; Ombre: yes; Intérieur: _Bois-Horiz ocre; Extérieur: _Bois-Horiz ocre; Coût: 0; Surface vitrée totale (gs_list_glassarea_tmp): 0; Supplanter surface vitrée: no; Surface vitrée totale (gs_list_glassarea): 0; Périmètre total vitrage: 0; Type de groupe (FM_Type): Objets par défaut; Type de groupe (iFMType): 1; Numéro de série: Sans; Poids de l'objet: 0; Unité poids de l'objet: kg
AC_Pset_RenovationAndPhasing - Renovation Status: Non défini
Name | ID de l'élément = Lien et ID d'élément | Nom de zone liée = À Zone
Panel-Main-249 | Panel-Main-249 | local CTA
Panel-Main-261 | Panel-Main-261
Panel-Main-256 | Panel-Main-256 | local CTA
Panel-Main-257 | Panel-Main-257 | local CTA
Panel-Main-248 | Panel-Main-248 | local CTA
Panel-Main-252 | Panel-Main-252 | local CTA
Panel-Main-254 | Panel-Main-254 | local CTA
Panel-Main-255 | Panel-Main-255 | local CTA
Panel-Main-250 | Panel-Main-250 | local CTA
Panel-Main-260 | Panel-Main-260
Panel-Main-247 | Panel-Main-247 | local CTA
Panel-Main-246 | Panel-Main-246 | local CTA
Panel-Main-258 | Panel-Main-258 | local CTA
Panel-Main-259 | Panel-Main-259 | local CTA
Panel-Main-253 | Panel-Main-253 | local CTA
Panel-Main-251 | Panel-Main-251 | local CTA

# IfcBuildingElementProxy: Panneau principal 215 x 147 x 20, Panel-Main-791
In: R+1
Classification: Element de construction non défini (Classification Archicad); Material: Matériau de construction IFC
ArchiCADProperties - ID de l'élément: Panel-Main-791; Lien et ID d'élément: Panel-Main-791; Calque: 10_M x baseGO__; Nom Élément de Bibliothèque: Panneau MR 21; Matériau de construction / Composite / Profil / Hachure: MANQUANT; Matériau de construction: MANQUANT; Verrouillé: no; Nom d'étage d'implantation: R+1; Numéro d'étage d'implantation: 1; Type d'élément: Panneau (Mur-rideau); ID de Parent: pare-vue CTA; Surfaces (Toutes): _Bois-Horiz ocre; Angle d'inclinaison: 90 deg; Surface latérale: GENERAL; État de rénovation: Existant; Affichage sur filtre de rénovation: Tous les filtres appropriés; Abbréviation d'orientation: S; Angle par rapport nord: 169.76 deg; Fonction de panneau: Fixe; Surface intérieure: GENERAL; Surface extérieure: GENERAL; Catégorie de panneau: Panneau principal; Type de panneau: Panneau MR 21; Angle d'inclinaison Panneau mur-rideau: 90 deg
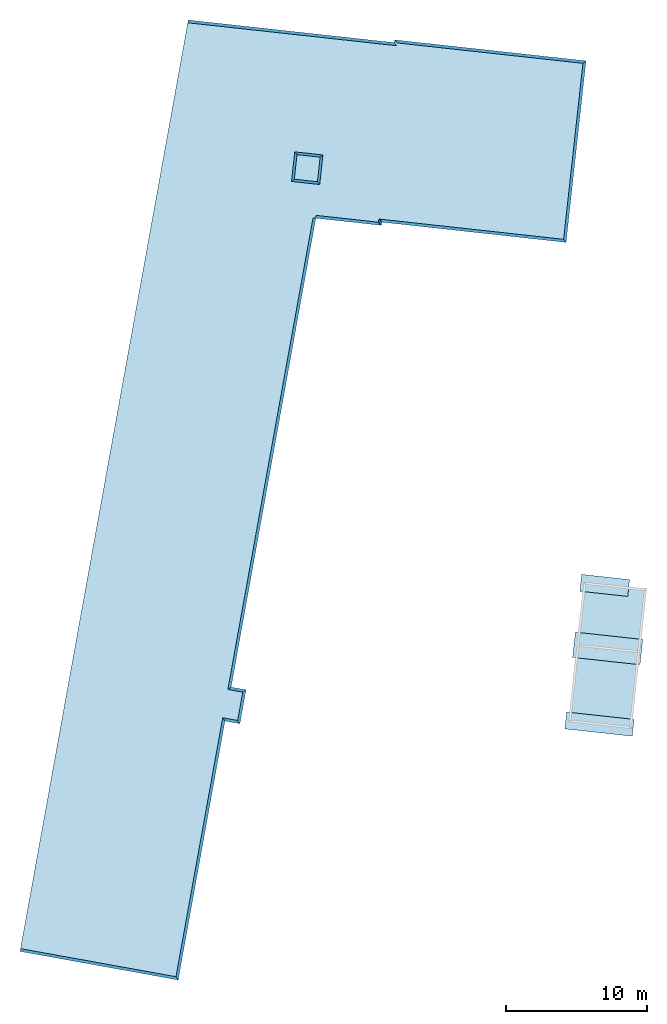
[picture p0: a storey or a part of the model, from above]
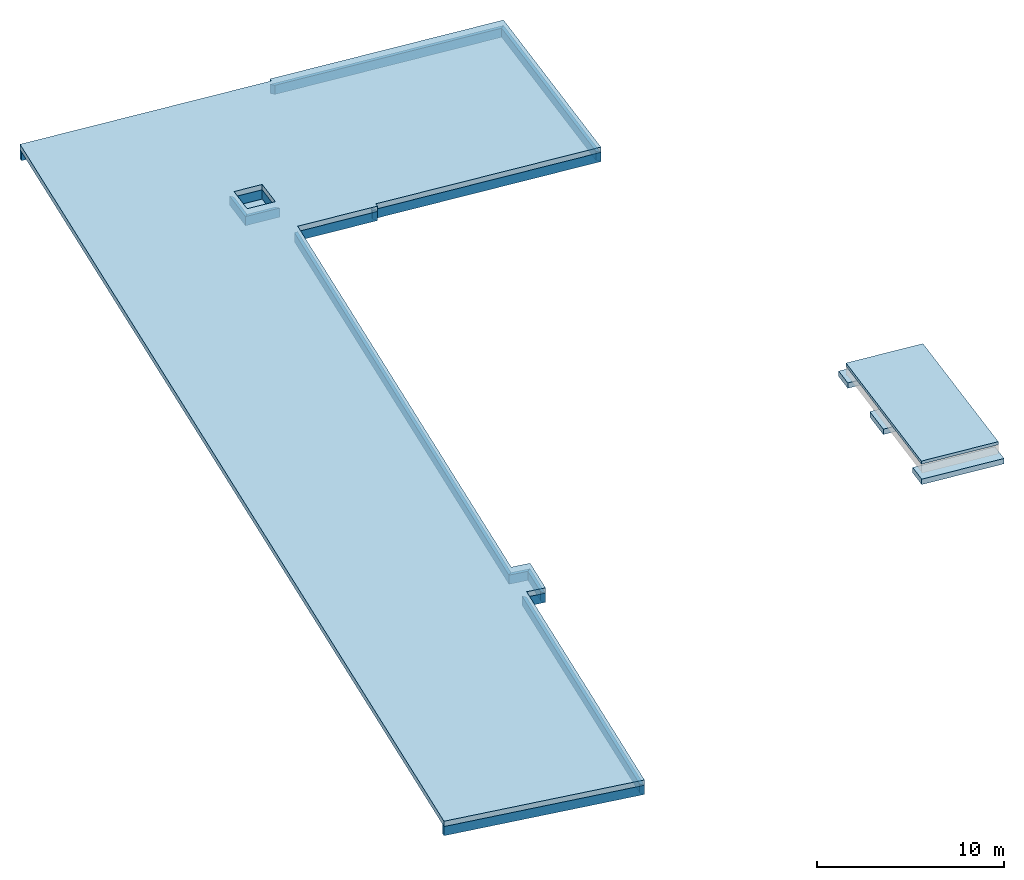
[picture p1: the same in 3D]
Properties of the parts of a building model (IFC2X3), part 4 of 10

# IfcBuildingElementProxy: Panneau principal 215 x 147 x 20, Panel-Main-791
AC_Pset_Panneau_MR_21 - Afficher points chauds 2D en 3D: yes; Modèle schématique automatique: yes; 0-fixe, 1-porte, 2-fenêtre: 0; Direction haut: 0 deg; Direction d'ouverture (ac_openingDir): 0; Angle panneau arrière: 90 deg; Niveau de détail 2D: -1; Stylo coupe: Eléments 2D - Général; Hachure coupée: Sans Trame; Stylo hachure coupée: Fond - Couleur 1; Stylo fond hachure coupée: Fond - Couleur 1; Hachure revêtement: Hachure solide; Hachure intérieure: Bois; Stylo hachure revêtement: Eléments 2D - Général; Stylo hachure intérieure: Eléments 2D - Général; Stylo fond hachure revêtement: Transparent; Stylo fond hachure intérieure: Transparent; Ombre: yes; Intérieur: _Bois-Horiz ocre; Extérieur: _Bois-Horiz ocre; Coût: 0; Surface vitrée totale (gs_list_glassarea_tmp): 0; Supplanter surface vitrée: no; Surface vitrée totale (gs_list_glassarea): 0; Périmètre total vitrage: 0; Type de groupe (FM_Type): Objets par défaut; Type de groupe (iFMType): 1; Numéro de série: Sans; Poids de l'objet: 0; Unité poids de l'objet: kg
AC_Pset_RenovationAndPhasing - Renovation Status: Non défini

# IfcBuildingElementProxy: Panneau principal 215 x 170 x 20 (16)
In: R+1
Classification: Element de construction non défini (Classification Archicad); Material: Matériau de construction IFC
ArchiCADProperties - Calque: 10_M x baseGO__; Nom Élément de Bibliothèque: Panneau MR 21; Matériau de construction / Composite / Profil / Hachure: MANQUANT; Matériau de construction: MANQUANT; Verrouillé: no; Nom d'étage d'implantation: R+1; Numéro d'étage d'implantation: 1; Type d'élément: Panneau (Mur-rideau); ID de Parent: pare-vue CTA; Surfaces (Toutes): _Bois-Horiz ocre; Angle d'inclinaison: 90 deg; Surface latérale: GENERAL; État de rénovation: Existant; Affichage sur filtre de rénovation: Tous les filtres appropriés; Abbréviation d'orientation: S; Angle par rapport nord: 169.76 deg; Fonction de panneau: Fixe; Surface intérieure: GENERAL; Surface extérieure: GENERAL; Catégorie de panneau: Panneau principal; Type de panneau: Panneau MR 21; Angle d'inclinaison Panneau mur-rideau: 90 deg
AC_Pset_Panneau_MR_21 - Afficher points chauds 2D en 3D: yes; Modèle schématique automatique: yes; 0-fixe, 1-porte, 2-fenêtre: 0; Direction haut: 0 deg; Direction d'ouverture (ac_openingDir): 0; Angle panneau arrière: 90 deg; Niveau de détail 2D: -1; Stylo coupe: Eléments 2D - Général; Hachure coupée: Sans Trame; Stylo hachure coupée: Fond - Couleur 1; Stylo fond hachure coupée: Fond - Couleur 1; Hachure revêtement: Hachure solide; Hachure intérieure: Bois; Stylo hachure revêtement: Eléments 2D - Général; Stylo hachure intérieure: Eléments 2D - Général; Stylo fond hachure revêtement: Transparent; Stylo fond hachure intérieure: Transparent; Ombre: yes; Intérieur: _Bois-Horiz ocre; Extérieur: _Bois-Horiz ocre; Coût: 0; Surface vitrée totale (gs_list_glassarea_tmp): 0; Supplanter surface vitrée: no; Surface vitrée totale (gs_list_glassarea): 0; Périmètre total vitrage: 0; Type de groupe (FM_Type): Objets par défaut; Type de groupe (iFMType): 1; Numéro de série: Sans; Poids de l'objet: 0; Unité poids de l'objet: kg
AC_Pset_RenovationAndPhasing - Renovation Status: Non défini
Name | ID de l'élément = Lien et ID d'élément | Nom de zone liée = À Zone
Panel-Main-308 | Panel-Main-308 | local CTA
Panel-Main-306 | Panel-Main-306 | local CTA
Panel-Main-316 | Panel-Main-316
Panel-Main-303 | Panel-Main-303 | local CTA
Panel-Main-314 | Panel-Main-314 | local CTA
Panel-Main-309 | Panel-Main-309 | local CTA
Panel-Main-313 | Panel-Main-313 | local CTA
Panel-Main-302 | Panel-Main-302 | local CTA
Panel-Main-304 | Panel-Main-304 | local CTA
Panel-Main-311 | Panel-Main-311 | local CTA
Panel-Main-305 | Panel-Main-305 | local CTA
Panel-Main-307 | Panel-Main-307 | local CTA
Panel-Main-315 | Panel-Main-315 | local CTA
Panel-Main-310 | Panel-Main-310 | local CTA
Panel-Main-312 | Panel-Main-312 | local CTA
Panel-Main-317 | Panel-Main-317

# IfcBuildingElementProxy: Panneau principal 245 x 147 x 20, Panel-Main-231
In: R+1
Classification: Element de construction non défini (Classification Archicad); Material: Matériau de construction IFC
ArchiCADProperties - ID de l'élément: Panel-Main-231; Lien et ID d'élément: Panel-Main-231; Calque: 10_M x baseGO__; Nom Élément de Bibliothèque: Panneau MR 21; Matériau de construction / Composite / Profil / Hachure: MANQUANT; Matériau de construction: MANQUANT; Verrouillé: no; Nom d'étage d'implantation: R+1; Numéro d'étage d'implantation: 1; Type d'élément: Panneau (Mur-rideau); ID de Parent: pare-vue CTA; Surfaces (Toutes): _Bois-Horiz ocre; Angle d'inclinaison: 90 deg; Surface latérale: GENERAL; État de rénovation: Existant; Affichage sur filtre de rénovation: Tous les filtres appropriés; Abbréviation d'orientation: E; Angle par rapport nord: -100.24 deg; Fonction de panneau: Fixe; Surface intérieure: GENERAL; Surface extérieure: GENERAL; Catégorie de panneau: Panneau principal; Type de panneau: Panneau MR 21; Angle d'inclinaison Panneau mur-rideau: 90 deg
AC_Pset_Panneau_MR_21 - Afficher points chauds 2D en 3D: yes; Modèle schématique automatique: yes; 0-fixe, 1-porte, 2-fenêtre: 0; Direction haut: 0 deg; Direction d'ouverture (ac_openingDir): 0; Angle panneau arrière: 90 deg; Niveau de détail 2D: -1; Stylo coupe: Eléments 2D - Général; Hachure coupée: Sans Trame; Stylo hachure coupée: Fond - Couleur 1; Stylo fond hachure coupée: Fond - Couleur 1; Hachure revêtement: Hachure solide; Hachure intérieure: Bois; Stylo hachure revêtement: Eléments 2D - Général; Stylo hachure intérieure: Eléments 2D - Général; Stylo fond hachure revêtement: Transparent; Stylo fond hachure intérieure: Transparent; Ombre: yes; Intérieur: _Bois-Horiz ocre; Extérieur: _Bois-Horiz ocre; Coût: 0; Surface vitrée totale (gs_list_glassarea_tmp): 0; Supplanter surface vitrée: no; Surface vitrée totale (gs_list_glassarea): 0; Périmètre total vitrage: 0; Type de groupe (FM_Type): Objets par défaut; Type de groupe (iFMType): 1; Numéro de série: Sans; Poids de l'objet: 0; Unité poids de l'objet: kg
AC_Pset_RenovationAndPhasing - Renovation Status: Non défini

# IfcBuildingElementProxy: Panneau principal 245 x 170 x 20 (15)
In: R+1
Classification: Element de construction non défini (Classification Archicad); Material: Matériau de construction IFC
ArchiCADProperties - Calque: 10_M x baseGO__; Nom Élément de Bibliothèque: Panneau MR 21; Matériau de construction / Composite / Profil / Hachure: MANQUANT; Matériau de construction: MANQUANT; Verrouillé: no; Nom d'étage d'implantation: R+1; Numéro d'étage d'implantation: 1; Type d'élément: Panneau (Mur-rideau); ID de Parent: pare-vue CTA; Surfaces (Toutes): _Bois-Horiz ocre; Angle d'inclinaison: 90 deg; Surface latérale: GENERAL; État de rénovation: Existant; Affichage sur filtre de rénovation: Tous les filtres appropriés; Abbréviation d'orientation: E; Angle par rapport nord: -100.24 deg; Fonction de panneau: Fixe; Surface intérieure: GENERAL; Surface extérieure: GENERAL; Catégorie de panneau: Panneau principal; Type de panneau: Panneau MR 21; Angle d'inclinaison Panneau mur-rideau: 90 deg
AC_Pset_Panneau_MR_21 - Afficher points chauds 2D en 3D: yes; Modèle schématique automatique: yes; 0-fixe, 1-porte, 2-fenêtre: 0; Direction haut: 0 deg; Direction d'ouverture (ac_openingDir): 0; Angle panneau arrière: 90 deg; Niveau de détail 2D: -1; Stylo coupe: Eléments 2D - Général; Hachure coupée: Sans Trame; Stylo hachure coupée: Fond - Couleur 1; Stylo fond hachure coupée: Fond - Couleur 1; Hachure revêtement: Hachure solide; Hachure intérieure: Bois; Stylo hachure revêtement: Eléments 2D - Général; Stylo hachure intérieure: Eléments 2D - Général; Stylo fond hachure revêtement: Transparent; Stylo fond hachure intérieure: Transparent; Ombre: yes; Intérieur: _Bois-Horiz ocre; Extérieur: _Bois-Horiz ocre; Coût: 0; Surface vitrée totale (gs_list_glassarea_tmp): 0; Supplanter surface vitrée: no; Surface vitrée totale (gs_list_glassarea): 0; Périmètre total vitrage: 0; Type de groupe (FM_Type): Objets par défaut; Type de groupe (iFMType): 1; Numéro de série: Sans; Poids de l'objet: 0; Unité poids de l'objet: kg
AC_Pset_RenovationAndPhasing - Renovation Status: Non défini
Name | ID de l'élément = Lien et ID d'élément
Panel-Main-528 | Panel-Main-528
Panel-Main-539 | Panel-Main-539
Panel-Main-538 | Panel-Main-538
Panel-Main-533 | Panel-Main-533
Panel-Main-529 | Panel-Main-529
Panel-Main-532 | Panel-Main-532
Panel-Main-526 | Panel-Main-526
Panel-Main-535 | Panel-Main-535
Panel-Main-527 | Panel-Main-527
Panel-Main-531 | Panel-Main-531
Panel-Main-525 | Panel-Main-525
Panel-Main-534 | Panel-Main-534
Panel-Main-540 | Panel-Main-540
Panel-Main-530 | Panel-Main-530
Panel-Main-537 | Panel-Main-537

# IfcBuildingElementProxy: Panneau principal 450 x 147 x 20 (4)
In: R+1
Classification: Element de construction non défini (Classification Archicad); Material: Matériau de construction IFC
ArchiCADProperties - Calque: 10_M x baseGO__; Nom Élément de Bibliothèque: Panneau MR 21; Matériau de construction / Composite / Profil / Hachure: MANQUANT; Matériau de construction: MANQUANT; Verrouillé: no; Nom d'étage d'implantation: R+1; Numéro d'étage d'implantation: 1; Type d'élément: Panneau (Mur-rideau); ID de Parent: pare-vue CTA; Surfaces (Toutes): _Bois-Horiz ocre; Angle d'inclinaison: 90 deg; Surface latérale: GENERAL; État de rénovation: Existant; Affichage sur filtre de rénovation: Tous les filtres appropriés; Abbréviation d'orientation: S; Angle par rapport nord: 169.76 deg; Fonction de panneau: Fixe; Surface intérieure: GENERAL; Surface extérieure: GENERAL; Catégorie de panneau: Panneau principal; Type de panneau: Panneau MR 21; Angle d'inclinaison Panneau mur-rideau: 90 deg
AC_Pset_Panneau_MR_21 - Afficher points chauds 2D en 3D: yes; Modèle schématique automatique: yes; 0-fixe, 1-porte, 2-fenêtre: 0; Direction haut: 0 deg; Direction d'ouverture (ac_openingDir): 0; Angle panneau arrière: 90 deg; Niveau de détail 2D: -1; Stylo coupe: Eléments 2D - Général; Hachure coupée: Sans Trame; Stylo hachure coupée: Fond - Couleur 1; Stylo fond hachure coupée: Fond - Couleur 1; Hachure revêtement: Hachure solide; Hachure intérieure: Bois; Stylo hachure revêtement: Eléments 2D - Général; Stylo hachure intérieure: Eléments 2D - Général; Stylo fond hachure revêtement: Transparent; Stylo fond hachure intérieure: Transparent; Ombre: yes; Intérieur: _Bois-Horiz ocre; Extérieur: _Bois-Horiz ocre; Coût: 0; Surface vitrée totale (gs_list_glassarea_tmp): 0; Supplanter surface vitrée: no; Surface vitrée totale (gs_list_glassarea): 0; Périmètre total vitrage: 0; Type de groupe (FM_Type): Objets par défaut; Type de groupe (iFMType): 1; Numéro de série: Sans; Poids de l'objet: 0; Unité poids de l'objet: kg
AC_Pset_RenovationAndPhasing - Renovation Status: Non défini
Name | ID de l'élément = Lien et ID d'élément
Panel-Main-796 | Panel-Main-796
Panel-Main-797 | Panel-Main-797
Panel-Main-793 | Panel-Main-793
Panel-Main-792 | Panel-Main-792

# IfcBuildingElementProxy: Panneau principal 450 x 170 x 20 (64)
In: R+1
Classification: Element de construction non défini (Classification Archicad); Material: Matériau de construction IFC
ArchiCADProperties - Calque: 10_M x baseGO__; Nom Élément de Bibliothèque: Panneau MR 21; Matériau de construction / Composite / Profil / Hachure: MANQUANT; Matériau de construction: MANQUANT; Verrouillé: no; Nom d'étage d'implantation: R+1; Numéro d'étage d'implantation: 1; Type d'élément: Panneau (Mur-rideau); ID de Parent: pare-vue CTA; Surfaces (Toutes): _Bois-Horiz ocre; Angle d'inclinaison: 90 deg; Surface latérale: GENERAL; État de rénovation: Existant; Affichage sur filtre de rénovation: Tous les filtres appropriés; Abbréviation d'orientation: S; Angle par rapport nord: 169.76 deg; Fonction de panneau: Fixe; Surface intérieure: GENERAL; Surface extérieure: GENERAL; Catégorie de panneau: Panneau principal; Type de panneau: Panneau MR 21; Angle d'inclinaison Panneau mur-rideau: 90 deg
AC_Pset_Panneau_MR_21 - Afficher points chauds 2D en 3D: yes; Modèle schématique automatique: yes; 0-fixe, 1-porte, 2-fenêtre: 0; Direction haut: 0 deg; Direction d'ouverture (ac_openingDir): 0; Angle panneau arrière: 90 deg; Niveau de détail 2D: -1; Stylo coupe: Eléments 2D - Général; Hachure coupée: Sans Trame; Stylo hachure coupée: Fond - Couleur 1; Stylo fond hachure coupée: Fond - Couleur 1; Hachure revêtement: Hachure solide; Hachure intérieure: Bois; Stylo hachure revêtement: Eléments 2D - Général; Stylo hachure intérieure: Eléments 2D - Général; Stylo fond hachure revêtement: Transparent; Stylo fond hachure intérieure: Transparent; Ombre: yes; Intérieur: _Bois-Horiz ocre; Extérieur: _Bois-Horiz ocre; Coût: 0; Surface vitrée totale (gs_list_glassarea_tmp): 0; Supplanter surface vitrée: no; Surface vitrée totale (gs_list_glassarea): 0; Périmètre total vitrage: 0; Type de groupe (FM_Type): Objets par défaut; Type de groupe (iFMType): 1; Numéro de série: Sans; Poids de l'objet: 0; Unité poids de l'objet: kg
AC_Pset_RenovationAndPhasing - Renovation Status: Non défini
Name | ID de l'élément = Lien et ID d'élément | Nom de zone liée = À Zone
42 x Panel-Main-208 | Panel-Main-208 | local CTA
6 x Panel-Main-208 | Panel-Main-208
Panel-Main-242 | Panel-Main-242 | local CTA
Panel-Main-243 | Panel-Main-243
Panel-Main-244 | Panel-Main-244
Panel-Main-229 | Panel-Main-229 | local CTA
Panel-Main-230 | Panel-Main-230 | local CTA
Panel-Main-231 | Panel-Main-231 | local CTA
Panel-Main-232 | Panel-Main-232 | local CTA
Panel-Main-233 | Panel-Main-233 | local CTA
Panel-Main-234 | Panel-Main-234 | local CTA
Panel-Main-235 | Panel-Main-235 | local CTA
Panel-Main-236 | Panel-Main-236 | local CTA
Panel-Main-237 | Panel-Main-237 | local CTA
Panel-Main-238 | Panel-Main-238 | local CTA
Panel-Main-239 | Panel-Main-239 | local CTA
Panel-Main-240 | Panel-Main-240 | local CTA
Panel-Main-241 | Panel-Main-241 | local CTA

# IfcBuildingElementProxy: Panneau principal 470 x 147 x 20 (2)
In: R+1
Classification: Element de construction non défini (Classification Archicad); Material: Matériau de construction IFC
ArchiCADProperties - Calque: 10_M x baseGO__; Nom Élément de Bibliothèque: Panneau MR 21; Matériau de construction / Composite / Profil / Hachure: MANQUANT; Matériau de construction: MANQUANT; Verrouillé: no; Nom d'étage d'implantation: R+1; Numéro d'étage d'implantation: 1; Type d'élément: Panneau (Mur-rideau); ID de Parent: pare-vue CTA; Surfaces (Toutes): _Bois-Horiz ocre; Angle d'inclinaison: 90 deg; Surface latérale: GENERAL; État de rénovation: Existant; Affichage sur filtre de rénovation: Tous les filtres appropriés; Abbréviation d'orientation: S; Angle par rapport nord: 169.76 deg; Fonction de panneau: Fixe; Surface intérieure: GENERAL; Surface extérieure: GENERAL; Catégorie de panneau: Panneau principal; Type de panneau: Panneau MR 21; Angle d'inclinaison Panneau mur-rideau: 90 deg
AC_Pset_Panneau_MR_21 - Afficher points chauds 2D en 3D: yes; Modèle schématique automatique: yes; 0-fixe, 1-porte, 2-fenêtre: 0; Direction haut: 0 deg; Direction d'ouverture (ac_openingDir): 0; Angle panneau arrière: 90 deg; Niveau de détail 2D: -1; Stylo coupe: Eléments 2D - Général; Hachure coupée: Sans Trame; Stylo hachure coupée: Fond - Couleur 1; Stylo fond hachure coupée: Fond - Couleur 1; Hachure revêtement: Hachure solide; Hachure intérieure: Bois; Stylo hachure revêtement: Eléments 2D - Général; Stylo hachure intérieure: Eléments 2D - Général; Stylo fond hachure revêtement: Transparent; Stylo fond hachure intérieure: Transparent; Ombre: yes; Intérieur: _Bois-Horiz ocre; Extérieur: _Bois-Horiz ocre; Coût: 0; Surface vitrée totale (gs_list_glassarea_tmp): 0; Supplanter surface vitrée: no; Surface vitrée totale (gs_list_glassarea): 0; Périmètre total vitrage: 0; Type de groupe (FM_Type): Objets par défaut; Type de groupe (iFMType): 1; Numéro de série: Sans; Poids de l'objet: 0; Unité poids de l'objet: kg
AC_Pset_RenovationAndPhasing - Renovation Status: Non défini
Name | ID de l'élément = Lien et ID d'élément
Panel-Main-795 | Panel-Main-795
Panel-Main-794 | Panel-Main-794

# IfcBuildingElementProxy: Panneau principal 470 x 170 x 20 (6)
In: R+1
Classification: Element de construction non défini (Classification Archicad); Material: Matériau de construction IFC
ArchiCADProperties - ID de l'élément: Panel-Main-208; Lien et ID d'élément: Panel-Main-208; Calque: 10_M x baseGO__; Nom Élément de Bibliothèque: Panneau MR 21; Matériau de construction / Composite / Profil / Hachure: MANQUANT; Matériau de construction: MANQUANT; Verrouillé: no; Nom d'étage d'implantation: R+1; Numéro d'étage d'implantation: 1; Type d'élément: Panneau (Mur-rideau); ID de Parent: pare-vue CTA; Surfaces (Toutes): _Bois-Horiz ocre; Angle d'inclinaison: 90 deg; Surface latérale: GENERAL; État de rénovation: Existant; Affichage sur filtre de rénovation: Tous les filtres appropriés; Abbréviation d'orientation: S; Angle par rapport nord: 169.76 deg; Fonction de panneau: Fixe; Surface intérieure: GENERAL; Surface extérieure: GENERAL; Catégorie de panneau: Panneau principal; Type de panneau: Panneau MR 21; Angle d'inclinaison Panneau mur-rideau: 90 deg
AC_Pset_Panneau_MR_21 - Afficher points chauds 2D en 3D: yes; Modèle schématique automatique: yes; 0-fixe, 1-porte, 2-fenêtre: 0; Direction haut: 0 deg; Direction d'ouverture (ac_openingDir): 0; Angle panneau arrière: 90 deg; Niveau de détail 2D: -1; Stylo coupe: Eléments 2D - Général; Hachure coupée: Sans Trame; Stylo hachure coupée: Fond - Couleur 1; Stylo fond hachure coupée: Fond - Couleur 1; Hachure revêtement: Hachure solide; Hachure intérieure: Bois; Stylo hachure revêtement: Eléments 2D - Général; Stylo hachure intérieure: Eléments 2D - Général; Stylo fond hachure revêtement: Transparent; Stylo fond hachure intérieure: Transparent; Ombre: yes; Intérieur: _Bois-Horiz ocre; Extérieur: _Bois-Horiz ocre; Coût: 0; Surface vitrée totale (gs_list_glassarea_tmp): 0; Supplanter surface vitrée: no; Surface vitrée totale (gs_list_glassarea): 0; Périmètre total vitrage: 0; Type de groupe (FM_Type): Objets par défaut; Type de groupe (iFMType): 1; Numéro de série: Sans; Poids de l'objet: 0; Unité poids de l'objet: kg
AC_Pset_RenovationAndPhasing - Renovation Status: Non défini
Name
4 x Panel-Main-208
2 x Panel-Main-208 | ArchiCADProperties - Nom de zone liée: local CTA; À Zone: local CTA

# IfcBuildingElementProxy: Panneau principal 600 x 147 x 20 (5)
In: R+1
Classification: Element de construction non défini (Classification Archicad); Material: Matériau de construction IFC
ArchiCADProperties - Calque: 10_M x baseGO__; Nom Élément de Bibliothèque: Panneau MR 21; Matériau de construction / Composite / Profil / Hachure: MANQUANT; Matériau de construction: MANQUANT; Verrouillé: no; Nom d'étage d'implantation: R+1; Numéro d'étage d'implantation: 1; Type d'élément: Panneau (Mur-rideau); ID de Parent: pare-vue CTA; Surfaces (Toutes): _Bois-Horiz ocre; Angle d'inclinaison: 90 deg; Surface latérale: GENERAL; État de rénovation: Existant; Affichage sur filtre de rénovation: Tous les filtres appropriés; Abbréviation d'orientation: E; Angle par rapport nord: -100.24 deg; Fonction de panneau: Fixe; Surface intérieure: GENERAL; Surface extérieure: GENERAL; Catégorie de panneau: Panneau principal; Type de panneau: Panneau MR 21; Angle d'inclinaison Panneau mur-rideau: 90 deg
AC_Pset_Panneau_MR_21 - Afficher points chauds 2D en 3D: yes; Modèle schématique automatique: yes; 0-fixe, 1-porte, 2-fenêtre: 0; Direction haut: 0 deg; Direction d'ouverture (ac_openingDir): 0; Angle panneau arrière: 90 deg; Niveau de détail 2D: -1; Stylo coupe: Eléments 2D - Général; Hachure coupée: Sans Trame; Stylo hachure coupée: Fond - Couleur 1; Stylo fond hachure coupée: Fond - Couleur 1; Hachure revêtement: Hachure solide; Hachure intérieure: Bois; Stylo hachure revêtement: Eléments 2D - Général; Stylo hachure intérieure: Eléments 2D - Général; Stylo fond hachure revêtement: Transparent; Stylo fond hachure intérieure: Transparent; Ombre: yes; Intérieur: _Bois-Horiz ocre; Extérieur: _Bois-Horiz ocre; Coût: 0; Surface vitrée totale (gs_list_glassarea_tmp): 0; Supplanter surface vitrée: no; Surface vitrée totale (gs_list_glassarea): 0; Périmètre total vitrage: 0; Type de groupe (FM_Type): Objets par défaut; Type de groupe (iFMType): 1; Numéro de série: Sans; Poids de l'objet: 0; Unité poids de l'objet: kg
AC_Pset_RenovationAndPhasing - Renovation Status: Non défini
Name | ID de l'élément = Lien et ID d'élément
Panel-Main-256 | Panel-Main-256
Panel-Main-248 | Panel-Main-248
Panel-Main-255 | Panel-Main-255
Panel-Main-246 | Panel-Main-246
Panel-Main-247 | Panel-Main-247

# IfcBuildingElementProxy: Panneau principal 600 x 170 x 20 (75)
In: R+1
Classification: Element de construction non défini (Classification Archicad); Material: Matériau de construction IFC
ArchiCADProperties - Calque: 10_M x baseGO__; Nom Élément de Bibliothèque: Panneau MR 21; Matériau de construction / Composite / Profil / Hachure: MANQUANT; Matériau de construction: MANQUANT; Verrouillé: no; Nom d'étage d'implantation: R+1; Numéro d'étage d'implantation: 1; Type d'élément: Panneau (Mur-rideau); ID de Parent: pare-vue CTA; Surfaces (Toutes): _Bois-Horiz ocre; Angle d'inclinaison: 90 deg; Surface latérale: GENERAL; État de rénovation: Existant; Affichage sur filtre de rénovation: Tous les filtres appropriés; Abbréviation d'orientation: E; Angle par rapport nord: -100.24 deg; Fonction de panneau: Fixe; Surface intérieure: GENERAL; Surface extérieure: GENERAL; Catégorie de panneau: Panneau principal; Type de panneau: Panneau MR 21; Angle d'inclinaison Panneau mur-rideau: 90 deg
AC_Pset_Panneau_MR_21 - Afficher points chauds 2D en 3D: yes; Modèle schématique automatique: yes; 0-fixe, 1-porte, 2-fenêtre: 0; Direction haut: 0 deg; Direction d'ouverture (ac_openingDir): 0; Angle panneau arrière: 90 deg; Niveau de détail 2D: -1; Stylo coupe: Eléments 2D - Général; Hachure coupée: Sans Trame; Stylo hachure coupée: Fond - Couleur 1; Stylo fond hachure coupée: Fond - Couleur 1; Hachure revêtement: Hachure solide; Hachure intérieure: Bois; Stylo hachure revêtement: Eléments 2D - Général; Stylo hachure intérieure: Eléments 2D - Général; Stylo fond hachure revêtement: Transparent; Stylo fond hachure intérieure: Transparent; Ombre: yes; Intérieur: _Bois-Horiz ocre; Extérieur: _Bois-Horiz ocre; Coût: 0; Surface vitrée totale (gs_list_glassarea_tmp): 0; Supplanter surface vitrée: no; Surface vitrée totale (gs_list_glassarea): 0; Périmètre total vitrage: 0; Type de groupe (FM_Type): Objets par défaut; Type de groupe (iFMType): 1; Numéro de série: Sans; Poids de l'objet: 0; Unité poids de l'objet: kg
AC_Pset_RenovationAndPhasing - Renovation Status: Non défini
Name | ID de l'élément = Lien et ID d'élément
45 x Panel-Main-259 | Panel-Main-259
Panel-Main-492 | Panel-Main-492
Panel-Main-491 | Panel-Main-491
Panel-Main-490 | Panel-Main-490
Panel-Main-489 | Panel-Main-489
Panel-Main-493 | Panel-Main-493
Panel-Main-494 | Panel-Main-494
Panel-Main-495 | Panel-Main-495
Panel-Main-496 | Panel-Main-496
Panel-Main-497 | Panel-Main-497
Panel-Main-498 | Panel-Main-498
Panel-Main-499 | Panel-Main-499
Panel-Main-501 | Panel-Main-501
Panel-Main-502 | Panel-Main-502
Panel-Main-503 | Panel-Main-503
Panel-Main-504 | Panel-Main-504
Panel-Main-522 | Panel-Main-522
Panel-Main-507 | Panel-Main-507
Panel-Main-508 | Panel-Main-508
Panel-Main-509 | Panel-Main-509
Panel-Main-510 | Panel-Main-510
Panel-Main-511 | Panel-Main-511
Panel-Main-512 | Panel-Main-512
Panel-Main-513 | Panel-Main-513
Panel-Main-514 | Panel-Main-514
Panel-Main-515 | Panel-Main-515
Panel-Main-516 | Panel-Main-516
Panel-Main-517 | Panel-Main-517
Panel-Main-519 | Panel-Main-519
Panel-Main-520 | Panel-Main-520
Panel-Main-521 | Panel-Main-521

# IfcBuildingElementProxy: Porte 21 (22)
Material: Matériau de construction IFC
ArchiCADProperties - Nom Élément de Bibliothèque: Porte 21; Verrouillé: no; Type d'élément: Porte; État de rénovation: Existant; Affichage sur filtre de rénovation: Tous les filtres appropriés; Fonction structurelle: Non défini; Nom élément de bibliothèque d'ouverture: Porte 21
AC_Pset_Porte_21 - Contours Mur (0-Sans,1-Tout,2-Côté,3-Longueur): 0; Point ch.0-Non,1-2D,2-3D,3-Tous: 3; Afficher points chauds 2D en 3D: yes; Option affichage en plan: 3; Angle de position baie: 0 deg; Division de surface du trou courbe dans murs courbes: no; Type de mur: 1; Position ancre ébrasuer: 1; Basculer: no; Démolition / Nouvelle constr.: 1; Nouveau motif de hachure de mur: Parpaing; Nouveau stylo de hachure de mur: Général - Dessin 0.12; Nouveau stylo fond hachure mur: Fond - Couleur 1; Afficher nouv. constr. sur mur: no; Type de ligne démolition: 1; Aff. param. Démolition/Nouveau: no; Afficher comme imposte: no; Châssis vitré (gs_SidelightTransomRelation): Sous imposte; Châssis vitré (gs_SidelightTransomRelation_m): 1; Tierce vitrée 1: no; Imposte: no; Tolérances uniformes: yes; Taille ébrasure comme nominale: no; Taille unité comme nominale: no; Taille battant comme nominale: no; Transmettre taille nominale actuelle à sélection: no; Afficher points chaud éditables: yes; Afficher ébrasure sur symbole: 1; Affichage symbolique de l'ouverture: no; Niveau de détail 3D: 2; Direction ouverture tiere vitrée (gs_opening_dir_sl): Opposé à battant; Direction ouverture tiere vitrée (gs_opening_dir_sl_m): 2; Cadre porte (gs_pocket_door_frame): yes; Epaisseur cadre=Epaisseur mur: no; Epaisseur cadre uniforme: yes; Battant centré: yes; Style cadre changé automatiquement: no; Nombre de battants: 4; Nombre de battants - côté 2: 3; Configuration battants (gs_LeavesConfig): Battants uniformes; Configuration battants (gs_iLeavesConfig): 1; Position grille (gs_grill_pos): Les deux; Position grille (gs_grill_pos_m): 3; Nombre panneaux verticalement: 4; Nombre panneaux horizontalement: 3; Nbre panneaux vert. côté 1: 4; Nbre panneaux hor. côté 1: 3; Afficher comme panneau vitre sur symbole: no; Afficher symbole porte chinoise: no; Afficher symbole comme panneau étanche: no; Afficher poignée sur symbole: no; Plaque bas de porte extérieure (bKickBoardOut): no; Plaque bas de porte intérieure (bKickBoardIn): no; Châssis uniformes: no; Type d'ouverture (gs_optype_m_05): 3; Type d'ouverture (gs_optype_m_02): 1; Type d'ouverture (gs_optype_m_06): 1; Type d'ouverture (gs_optype_m_10): 1; Type châssis (MullionStyle_00): Pas de grille; Type châssis (iMullionStyle_00): 1; Type châssis (iMullionStyle_05): 1; Type châssis (iMullionStyle_09): 1; Type châssis (iMullionStyle_02): 1; Type châssis (iMullionStyle_06): 1; Type châssis (iMullionStyle_10): 1; Edition point chaud de grille: yes; Position grille (MullionPosition): Les deux; Position grille (iMullionPosition): 3; Nbre panneaux V châssis princ. côté 1: 4; Nbre panneaux H châssis princ. côté 1: 2; Nbre panneaux V 2 châssis princ. côté 1: 4; Nbre panneaux H 2 châssis princ. côté 1: 2; Nbre panneaux V châssis princ. côté 2: 4; Nbre panneaux H châssis princ. côté 2: 2; Nbre panneaux V 2 châssis princ. côté 2: 4; Nbre panneaux H 2 châssis princ. côté 2: 2; Nbre panneaux V imposte centre: 2; Nbre panneaux H imposte centre: 2; Nbre panneaux V 2 imposte centre: 2; Nbre panneaux H 2 imposte centre: 2; Nbre panneaux vert. imposte côté 1: 2; Nbre panneaux hor. imposte côté 1: 2; Nbre panneaux V 2 imposte côté 1: 2; Nbre panneaux H 2 imposte côté 1: 2; Nbre panneaux vert. imposte côté 2: 2; Nbre panneaux hor. imposte côté 2: 2; Nbre panneaux V 2 imposte côté 2: 2; Nbre panneaux H 2 imposte côté 2: 2; Chambranle extérieur (gs_trim_outside): no; Type chambr. ext. (gs_trimtype_out): Simple; Type chambr. ext. (gs_trimtype_out_int): 1; Type tête chambr. ext.: 1; Chapiteau architrave: yes; Type chapiteau architrave: 1; Couvre surface mur ext.: yes; Largeurs uniformes de chambranle (gs_trim_outside_uniform): yes; Chambranle intérieur.: no; Type chambr. intérieur (gs_trimtype_in): Simple; Type chambr. intérieur (gs_trimtype_in_int): 1; Couvre surface mur int.: yes; Largeurs uniformes de chambranle (gs_trim_inside_uniform): yes; Seuil (bThreshold): no; Type seuil: 2; Angle seuil: 3.1996 deg; Seuil changé automatiquement: no; Appui - porte: no; Appui - Tierce vitrée côté 1: no; Appui - Tierce vitrée côté 2: no; Dépassement appui: no; Type d'appui/seuil: 1; Angle appui: 3 deg; Appui courbe dans murs courbes: yes; Isolation sous appui: yes; Utiliser couche isolation mur: no; Niveau détail 3D seuil brique: 1; Style appui changé automatiquement: no; Tablette - côté tierce vitrée 1: no; Tablette - côté tierce vitrée 2: no; Tablette - porte: no; Angle tablette: 0 deg; Tabl. courbe dans murs courbes: yes; Tableau dans murs polygonaux: 1; Aération naturelle: no; Type d'aération naturelle: 2; Volet: no; Nombre de panneaux: 2; Nombre de panneaux 2: 1; Position panneau (gs_shutter_panelPos): Symétrique; Position panneau (gs_shutter_iPanelPos): 1; Hauteur volet automatique: yes; Cadre supplémentaire: no; Type de couverture (gs_slidingShutter_cover): Profil en Z; Type de couverture (gs_slidingShutter_iCover): 1; Direction articulation (gs_foldingShutter_stacking): Intérieur; Direction articulation (gs_foldingShutter_iStacking): 1; Ouvert en 3D: yes; Angle ouverture en 3D (gs_shutter_opAngle): 180 deg; Afficher symbole 2D: yes; Afficher lignes d'ouverture sur symbole: no; Type de panneau: (gs_shutPanel_type): Style 1; Type de panneau: (gs_shutPanel_iType): 1; Largeur cadre inf. différente: no; Largeur volets automatiques: yes; Angle persienne: 30 deg; Nombre trous horizontaux: 5; Nombre trous verticaux: 8; Placement volet roulant (gs_shutRoll_placement): Sur façade; Placement volet roulant (gs_shutRoll_iPlacement): 1; Type boîte (gs_shutRoll_boxType): Rectangulaire; Type boîte (gs_shutRoll_iBoxType): 1; Position rampe (gs_shutRoll_railPos): Sur revêtement; Position rampe (gs_shutRoll_iRailPos): 1; Afficher revêtement derrière parasol (gs_shutRoll_showCasingBehind): no; Isolation derrière cellule (gs_shutRoll_cutWallBehind): no; Inclure hauteur dans hauteur de trou de mur: no; Angle supérieur boîte: 10 deg; Taille boîte par défaut (gs_shutRoll_boxDefaultSize): Largeur ébrasure; Taille boîte par défaut (gs_shutRoll_iBoxDefaultSize): 1; Placement stores (gs_shutLam_placement): Fixé sur façade; Placement stores (gs_shutLam_iPlacement): 1; Isolation derrière cellule (gs_shutLam_cutWallBehind): no; Boîte ouverte: yes; Rampe (gs_shutLam_bRail): yes; Position rampe (gs_shutLam_railPos): Sur revêtement; Position rampe (gs_shutLam_iRailPos): 1; Afficher revêtement derrière parasol (gs_shutLam_showCasingBehind): no; Angle de rotation des lamelles (gs_shutLam_rotation): 45 deg; Angle de rotation des lamelles (gs_shutLam2_rotation): 45 deg; Linteau (bMasonryArch): no; Linteau (gs_masonry_arch_int): 2; Type linteau (gs_masonry_arch_structure): Stuc; Type linteau (gs_masonry_arch_structure_int): 1; Arche sur linteau: yes; Niche sous arche: yes; Angle inclinaison: 75 deg; Surface niche personnalisée: no; Définir profondeur montant sur côté: 1; Profondeur montant uniforme: yes; Type ébrasure extérieure: Baie simple; Type ébrasure intérieure: Baie simple; Côté angle 2: 20 deg; Côté angle: 20 deg; Angle côté supérieur: 20 deg; Angle côté inférieur: 20 deg; Côté angle extérieur 2: 20 deg; Côté angle extérieur: 20 deg; Angle extérieur côté sup.: 20 deg; Angle extérieur côté inf.: 20 deg; Rampe sous battants: no; Rampe (gs_door_rail_ext): Sans; Rampe (gs_door_rail_ext_m): 1; Utiliser composant finition mur: no; Tourner plâtre surface intérieure: 0; Tourner plâtre surface extérieure: 0; Peut être coté en 2D: no; Afficher en 3D: no; Type de fermeture (gs_closure_type): Pas de fermeture; Type de fermeture (gs_closure_type_int): 1; Tourner couche sur côté (gs_cavity_side): Les deux; Tourner couche sur côté (iCavityClosureSide): 1; Nbre de couches retournées: 1; Num. à partir de (gs_nTurnDir): Face extérieure; Num. à partir de (iCavityClosureTurnDir): 1; Placer fermeture sur côté 1: yes; Placer fermeture sur côté 2: yes; Placer fermeture en haut: no; Placer fermeture en bas: no; Placer fermeture sur couche: 1; Placer fermeture de côté (gs_cc_dutch_ClosureToSide): 1; Ecart à couche externe: yes; Tourner couche sur fermeture: no; Insérer bande d'isolation: yes; Afficher bande d'isolation: yes; Stylo contour (gs_penJoint): Ouvertures - Coupé non structurel; Type de ligne de contour (gs_ltJoint): 1; Motif de hachure (gs_fillJoint): Isolation polystyrène; Stylo hachure (gs_penJointFg): Général - Dessin 0.12; Stylo fond de hachure (gs_penJointBg): Eléments 2D - Dessin; Surface personnalisée: no; Stylo contour (gs_penPlug): Ouvertures - Coupé non structurel; Type de ligne de contour (gs_ltPlug): 1; Motif de hachure (gs_fillPlug): Isolation polystyrène; Stylo hachure (gs_penPlugFg): Général - Dessin 0.12; Stylo fond de hachure (gs_penPlugBg): Eléments 2D - Dessin; Côté montant édité: 1; Côté mur édité: 1; Numéro couche éditée: 1; Tourner couche: no; Considérer couches comme plâtre: no; Tourner épaiseur: 1; Orientation hachure: 1; Ligne de séparation tournant: no; Stylo ligne de séparation: Général - Dessin 0.12; Dernier côté sélectionné: no; Méthode fermeture changée auto.: no; Connexion en haut: no; Type d'ouverture (gs_leaf_optype): Battant; Type d'ouverture (gs_leaf_optype_m): 1; Ouverture panneau de fin côté 1: no; Ouverture panneau de fin côté 2: no; Angle ouverture 2D côté 2: 90 deg; Angle ouverture en 3D (gs_open_3D): 0 deg; Angle ouv. battant fin 3D côté 2: 0 deg; Angle ouv. châssis principal côté 1 (openingAngle_05): 0 deg; Angle ouv. châssis principal côté 1 (openingAngle2_05): 0 deg; Angle ouv. châssis principal côté 2 (openingAngle_09): 0 deg; Angle ouv. châssis principal côté 2 (openingAngle2_09): 0 deg; Angle ouv. imposte centre (openingAngle_02): 0 deg; Angle ouv. imposte centre (openingAngle2_02): 0 deg; Angle ouverture imposte côté 1 (openingAngle_06): 0 deg; Angle ouverture imposte côté 1 (openingAngle2_06): 0 deg; Angle ouverture imposte côté 2 (openingAngle_10): 0 deg; Angle ouverture imposte côté 2 (openingAngle2_10): 0 deg; Type ligne ouverture: 1; Forme ligne ouverture (or_SwingType): Courbé; Forme ligne ouverture (or_iSwingType): 1; Forme ligne ouverture (or_SlidingType): Sans; Forme ligne ouverture (or_iSlidingType): 0; Suppl. Opt. vue pour proj. porte 3D: no; Afficher ligne d'ouverture (or_bOplines3d): yes; Orient. ligne (or_oplineStyle): Poignée; Orient. ligne (or_iOplineStyle): 1; Suppl. Opt. vue mod. pr proj. 3D tierce/imposte: no; Afficher ligne d'ouverture (or_bWinOplines3d): yes; Type ligne côté ouverture (or_winOpLineType3dIn): Ligne continue; Type ligne côté ouverture (or_iWinOpLineType3dIn): 0; Type ligne côté opposé (or_winOpLineType3dOut): Ligne continue; Type ligne côté opposé (or_iWinOpLineType3dOut): 0; Orient. ligne (or_winOplineStyle): Poignée; Orient. ligne (or_iWinOplineStyle): 1; Stylo ligne ouverture 2D/3D (or_winOpLinePen): Ouvertures - Général; Stylo ligne ouverture 2D/3D (or_iWinOpLinePen): 3; Stylo du symbole: Ouvertures - Général; Ligne de contour de mur (gs_wcont_line): Sans; Ligne de contour de mur (iWallContourLine): 1; Type ligne contour int. mur: 1; Type ligne contour ext. mur: 1; Ligne contour de tierce vitrée ds mur (gs_wcont_line_sl): Des deux côtés; Ligne contour de tierce vitrée ds mur (iWallContourLineSl): 4; Type ligne contour int. tierce vitrée ds mur: 1; Type ligne contour ext. tierce vitrée ds mur: 1; Stylo ligne contour de mur: Ouvertures - Général; Stylo hachure cadre: Ouvertures - Hachures coupées; Stylo hachure symbole étanche: Général - Dessin 0.12; Stylo fond hachure symbole étanche: Général - Dessin 0.12; Stylo hachure symbole plan de tierce vitrée: Fond - Couleur 1; Stylo fond hachure symbole plan de tierce vitrée: Fond - Couleur 1; Type ligne seuil et appui: 1; Stylo contour de seuil en coupe: Ouvertures - Général; Stylo hachure seuil en Coupe: Fond - Couleur 1; Stylo fond hachure coupe Seuil: Fond - Couleur 1; Stylo appui 3D et non coupé: Général - Dessin 0.12; Stylo contour appui en Coupe: Général - Dessin 0.12; Motif hachure appui en Coupe: Lame d'air; Stylo hachure d'appui en Coupe: Fond - Couleur 1; Stylo fond hachure appui Coupe: Fond - Couleur 1; Stylo contour isolation coupe: Général - Dessin 0.12; Motif hachure isolation Coupe: Isolation polystyrène; Stylo hachure isolation Coupe: Général - Dessin 0.12; Stylo fond hachure isol. Coupe: Fond - Couleur 1; Stylo latte 3D et non coupé: Général - Dessin 0.12; Stylo contour latte en Coupe: Général - Dessin 0.12; Motif hachure tablette en Coupe: Lame d'air; Stylo hachure tablette en Coupe: Fond - Couleur 1; Stylo fond hach. tablette Coupe: Fond - Couleur 1; Type hachure chambr. intérieur: Lame d'air; Stylo hachure chambr. int.: Fond - Couleur 1; Stylo fond hachure chambr. int.: Fond - Couleur 1; Type hachure chambr. ext.: Lame d'air; Stylo hachure chambr. ext.: Fond - Couleur 1; Stylo fond hachure chambr. ext.: Fond - Couleur 1; Stylo hachure en coupe d'arche: Fond - Couleur 1; Stylo fond hachure appui arche Coupe: Fond - Couleur 1; Motif de hachure de Coupe de Profil de ventilation: Lame d'air; Stylo de hachure de Coupe de Profil de ventilation: Fond - Couleur 1; Stylo de fond de hachure de Coupe de Profil de ventilation: Fond - Couleur 1; Type de ligne symbole volet: 1; Stylo ligne coupée volet: Général - Dessin 0.12; Stylo ligne non coupée 3D/Coupe: Général - Dessin 0.12; Stylo hachure coupée volet: Général - Dessin 0.12; Stylo fond hachure coupé volet: Fond de fenêtre; Motif de hachure d'isolation de volet: Dallage; Stylo de hachure d'isolation de volet: Général - Dessin 0.12; Stylo de fond d'isolation de volet: Fond de fenêtre; Valeurs côté ouverture (gs_opside_list): Personnalisé; Valeurs côté ouverture (gs_opside_list_m): 0; Jonction éléments cadree (gs_SashText_typ): Assemblage bout à bout; Jonction éléments cadree (gs_SashText_typ_num): 2; Stylo linteau: Murs - Général; Résolution de courbe: 32; Ombre: yes; Surfaces de porte uniformes: no; Verrou (gs_lock_mat): _Peinture - Anthracite; Rampe (gs_rail_mat): _Métal - Fer; Plaque bas de porte: _Métal BAVETTE; Surfaces uniformes de chambranle: yes; Profil Ventilation: _Métal BAVETTE; Boîte volet roulant: _Métal - Acier inoxydable; Lames volet roulant: _Peinture - Blanc brillant; Rail volet roulant: _Peinture - Blanc brillant; Boîte store vénitien: _Métal - Acier inoxydable; Segments store vénitien: _Peinture - Blanc brillant; Rail volet coulissant: _Métal - Acier inoxydable; Métal seuil: _Métal BAVETTE; Appui (gs_sill_mat): _Coupe3D_; Mortier appui briques: _Enduit - Blanc nature; Poignée: _Métal - Acier inoxydable; Accessoires poignée: _Métal - Fer; Plaque bas de porte extérieure (matKickBoardOut): _Métal - Acier inoxydable; Plaque bas de porte intérieure (matKickBoardIn): _Métal - Acier inoxydable; Brique linteau: _Coupe3D_; Mortier linteau: _Enduit - Blanc nature; Clef de voûte linteau: _Pierre - Grès 01; Niche: _Mur int Hall; Porte appartient à Zone vers laquelle elle donne: yes; Coût: 0; Emplacement comme: Personnalisé; Surface vitrée totale (gs_list_glassarea_tmp): 0; Supplanter surface vitrée: no; Périmètre total vitrage: 0; Performance air libre (mm2/l/m): 0; Type de groupe (FM_Type): Autres; Type de groupe (iFMType): 25; Poids de l'objet: 0; Unité poids de l'objet: kg; Définition orientation porte: 0; Fermeture porte: no; Type panneau de vision: Nbre panneaux vision; Dispositif main. ouvert.: no; Opération IFC (ifc_optypestr): Porte simple battant simple; Opération IFC (ifc_optype): 1
AC_Pset_RenovationAndPhasing - Renovation Status: Existing
Name | In | Description | Classification | FireResistanceRating | ID de l'élément = Lien et ID d'élément | Calque | Matériau de construction / Composite / Profil / Hachure = Type Hachure = Index hachure latérale ouverture | Zones conflictuelles | Nom de zone liée | Nom d'étage d'implantation | Numéro d'étage d'implantation | ID de Parent | Surfaces (Toutes) | Position | Dimensions ébrasure = Dimensions trou mur = Dimensions unité | Dimensions sortie | Dimensions battant | Taille L x H nominale | Taille L x H x E nominale | Résistance au feu = Degré de protection au feu | Structure de Mur | Orientation = Orientation porte | Classification ARCHICAD - 21 | Trou reprend surface latérale de mur | Type de direction de mur | Direction d'ouverture | Valeur incrustation allège | Tierce vitrée 2 = Connexion sur côté 1 = Connexion sur côté 2 = Utiliser hachures | Taille nominale | Taille trou comme taille nominale | Taille sortie comme nominale | Niveau de détail 2D | Style de cadre (gs_frame_style) | Style de cadre (gs_frame_style_m) | Largeur cadre uniforme | Style panneau de porte | Poignée d'ouverture (gs_handle_type) | Poignée d'ouverture (gs_handle_type_m) | Type d'ouverture (gs_optype_m_09) | Type volet | Types volet activés | Type ébrasure (gs_reveal_type_new) | Type ébrasure (gs_reveal_type_int) | Type ébrasure inférieure (gs_reveal_type_bottom) | Type ébrasure inférieure (gs_reveal_type_bottom_int) | Type ébrasure (gs_reveal_doubleOuterTypeInt) = Type ébrasure (gs_reveal_doubleInnerTypeInt) | Tourner automatiquement plâtre surface intérieure = Tourner automatiquement plâtre surface extérieure | Surface = Battant 2 = Battant 3 = Grille extérieure (gs_grill_mat) = Grille intérieure (gs_grill_mat2) = Grille extérieure (gs_leaf_grill_mat) = Grille intérieure (gs_leaf_grill_mat2) = Panneau solide extérieur = Panneau solide intérieur = Persienne extérieure = Persienne intérieure = Chambranle intérieur = Chambranle extérieur (gs_trim_out_mat) = Panneau volet = Cadre panneau volet = Seuil (gs_treshold_mat) = Tablette (gs_board_mat) | Angle ouverture en 2D (deg) | Type ligne va-et-vient = Type ligne contour int. mur masqué = Type ligne contour ext. mur masqué = Type ligne contour int. tierce vitrée ds mur masqué = Type ligne contour ext. tierce vitrée ds mur masqué | Suppl. Opt. vue pour aff. symb. 2D | Type ligne côté ouverture (or_opLineType3dIn) = Type ligne côté opposé (or_opLineType3dOut) | Type ligne côté ouverture (or_iOpLineType3dIn) = Type ligne côté opposé (or_iOpLineType3dOut) | Stylo ligne ouverture 2D/3D (or_opLinePen) | Stylo ligne ouverture 2D/3D (or_iOpLinePen) | Stylo contour cadre = Stylo contour battant = Stylo cadre = Stylo panneaux = Stylo vitrage = Stylo vitrage battant | Stylo ligne coupée chambranle des deux côtés | Motif de hachure cadre = Motif hachure symbole plan de porte = Motif hachure symbole plan de tierce vitrée = Motif hachure de seuil en Coupe = Motif de hachure arche coupe = Type hachure coupée volet = Type hachure non coupée | Stylo fond de hachure cadre = Stylo fond de hachure battant = Stylo fond hachure symbole plan de porte | Motif de hachure battant | Stylo hachure de battant = Stylo hachure symbole plan de porte | Motif hachure symbole étanche | Stylo hachure non coupée | Stylo fond de hachure non coupé | Cadre extérieur | Cadre intérieur | Battant extérieur = Battant intérieur | Vitrage (gs_glass_mat) = Vitrage (gs_leaf_glass_mat) | Surface vitrée totale (gs_list_glassarea) | Largeurs de battant de porte
21 | RDC | sanitaire hall | Element de construction non défini (Classification Archicad); Porte (Classification ARCHICAD) | CF 1/2H | 21 | 10_M refendGO__ | Menuis1 | Sanitaires | Sanitaires | RDC | 0 | M refend | _Serpentin-noir; _Mur int Hall | Intérieur | 100×210 | 90×205 | 92×206 | 100×210 | 100×210×18 | P Pleine | _BA banché RAL9007 | G | Porte | yes | 0 | 1 | 2 | no | 0 | yes | no | 2 | Simple feuillure | 3 | yes | 1 | Poignée 6 | 13 | 3 | 1 | 126 | Pas d'ébrasure - arête | 1 | Uniforme | 1 | 2 | yes | _Men ext_RAL9007 | 90 | 4 | no | Ligne continue | 0 | Général - Dessin 0.12 | 1 | Ouvertures - Général | Eléments 2D - Général | Sans Trame | Ouvertures - fonds de hachure | Sans Trame | Ouvertures - Hachures coupées | Hachure solide | Fond - Couleur 1 | Fond - Couleur 1 | _Mur int Hall | _Mur int Hall | _Serpentin-noir | _Verre clair (rapide) | 0 | 0.92 | ArchiCADProperties - À Zone: Sanitaires
22 | RDC | sanitaire hall | Element de construction non défini (Classification Archicad); Porte (Classification ARCHICAD) | CF 1/2H | 22 | 10_M refendGO__ | Menuis1 | Sanitaires | Hall d'entrée | RDC | 0 | M refend | _Serpentin-noir; _Mur int Hall | Intérieur | 100×210 | 90×205 | 92×206 | 100×210 | 100×210×18 | P Pleine | _BA banché RAL9007 | D | Porte | yes | 0 | 1 | 2 | no | 0 | yes | no | 2 | Simple feuillure | 3 | yes | 1 | Poignée 6 | 13 | 3 | 1 | 126 | Pas d'ébrasure - arête | 1 | Uniforme | 1 | 0 | yes | _Men ext_RAL9007 | 90 | 4 | no | Ligne continue | 0 | Général - Dessin 0.12 | 1 | Ouvertures - Général | Eléments 2D - Général | Sans Trame | Ouvertures - fonds de hachure | Sans Trame | Ouvertures - Hachures coupées | Hachure solide | Fond - Couleur 1 | Fond - Couleur 1 | _Mur int Hall | _Mur int Hall | _Serpentin-noir | _Verre clair (rapide) | 0 | 0.92 | ArchiCADProperties - À Zone: Hall d'entrée
32 | RDC | TGBT | Element de construction non défini (Classification Archicad); Porte (Classification ARCHICAD) | CF 1/2H | 32 | 10_M refendGO__ | Menuis1 | local TGBT | Hall d'entrée | RDC | 0 | M refend | _Serpentin-noir; _Mur int Hall | Intérieur | 90×210 | 80×205 | 82×206 | 90×210 | 90×210×18 | CF 1/2H | _BA banché RAL9007 | D | Porte | yes | 0 | 1 | 2 | no | 0 | yes | no | 2 | Simple feuillure | 3 | yes | 1 | Poignée 6 | 13 | 3 | 1 | 126 | Pas d'ébrasure - arête | 1 | Uniforme | 1 | 0 | yes | _Men ext_RAL9007 | 90 | 4 | no | Ligne continue | 0 | Général - Dessin 0.12 | 1 | Ouvertures - Général | Eléments 2D - Général | Sans Trame | Ouvertures - fonds de hachure | Sans Trame | Ouvertures - Hachures coupées | Hachure solide | Fond - Couleur 1 | Fond - Couleur 1 | _Mur int Hall | _Mur int Hall | _Serpentin-noir | _Verre clair (rapide) | 0 | 0.82 | ArchiCADProperties - À Zone: Hall d'entrée
33 | RDC | rangement 2 | Element de construction non défini (Classification Archicad); Porte (Classification ARCHICAD) | CF 1/2H | 33 | 10_M refendGO__ | Menuis1 |  | Accès cour | RDC | 0 | M refend | _Serpentin-noir; _Huisserie-int | Intérieur | 90×210 | 80×205 | 82×206 | 90×210 | 90×210×18 | CF 1/2H | _BA banché RAL9007 | G | Porte | yes | 1 | 1 | 2 | no | 0 | yes | no | 2 | Simple feuillure | 3 | yes | 1 | Poignée 6 | 13 | 3 | 1 | 126 | Pas d'ébrasure - arête | 1 | Uniforme | 1 | 0 | yes | _Men ext_RAL9007 | 90 | 4 | no | Ligne continue | 0 | Général - Dessin 0.12 | 1 | Ouvertures - Général | Eléments 2D - Général | Sans Trame | Ouvertures - fonds de hachure | Sans Trame | Ouvertures - Hachures coupées | Hachure solide | Fond - Couleur 1 | Fond - Couleur 1 | _Huisserie-int | _Huisserie-int | _Serpentin-noir | _Verre clair (rapide) | 0 | 0.82 | ArchiCADProperties - À Zone: Accès cour; De Zone: Accès cour
34 | RDC | entretien | Element de construction non défini (Classification Archicad); Porte (Classification ARCHICAD) | CF 1/2H | 34 | 10_M x baseGO__ | Menuis1 | Accès cour | Local entretien | RDC | 0 | M ext entretien-Sud | _Serpentin-noir; _Huisserie-int | Intérieur | 100×210 | 90×205 | 92×206 | 100×210 | 100×210×36 | CF 1/2H | _M ext 18 +18 gris | D | Porte | yes | 1 | 0 | 3 | no | 0 | yes | no | 2 | Simple feuillure | 3 | yes | 1 | Poignée 6 | 13 | 3 | 1 | 126 | Pas d'ébrasure - arête | 1 | Uniforme | 1 | 0 | no | _Men ext_RAL9007 | 90 | 4 | no | Ligne continue | 0 | Général - Dessin 0.12 | 1 | Ouvertures - Général | Eléments 2D - Général | Sans Trame | Ouvertures - fonds de hachure | Sans Trame | Ouvertures - Hachures coupées | Hachure solide | Fond - Couleur 1 | Fond - Couleur 1 | _Huisserie-int | _Huisserie-int | _Serpentin-noir | _Verre clair (rapide) | 0 | 0.92 | ArchiCADProperties - À Zone: Local entretien; De Zone: Accès cour
24 | RDC | sanitaire couloir | Element de construction non défini (Classification Archicad); Porte (Classification ARCHICAD) | CF 1/2H | 24 | 10_M refendGO__ | Menuis1 | Sanitaires | Sanitaires | RDC | 0 | M refend | _Huisserie-int; _Grain de riz | Intérieur | 100×210 | 90×205 | 92×206 | 100×210 | 100×210×18 | P Pleine | _BA banché RAL9007 | G | Porte | yes | 1 | 1 | 2 | no | 0 | yes | no | 2 | Simple feuillure | 3 | yes | 1 | Poignée 6 | 13 | 3 | 1 | 126 | Pas d'ébrasure - arête | 1 | Uniforme | 1 | 0 | yes | _Men ext_RAL9007 | 90 | 4 | no | Ligne continue | 0 | Général - Dessin 0.12 | 1 | Ouvertures - Général | Eléments 2D - Général | Sans Trame | Ouvertures - fonds de hachure | Sans Trame | Ouvertures - Hachures coupées | Hachure solide | Fond - Couleur 1 | Fond - Couleur 1 | _Huisserie-int | _Huisserie-int | _Grain de riz | _Verre clair (rapide) | 0 | 0.92 | ArchiCADProperties - De Zone: Sanitaires
23 | RDC | sanitaire couloir | Element de construction non défini (Classification Archicad); Porte (Classification ARCHICAD) | CF 1/2H | 23 | 10_M refendGO__ | Menuis1 | Sanitaires | Sanitaires | RDC | 0 | M refend | _Huisserie-int; _Grain de riz | Intérieur | 100×210 | 90×205 | 92×206 | 100×210 | 100×210×18 | P Pleine | _BA banché RAL9007 | D | Porte | yes | 1 | 1 | 2 | no | 0 | yes | no | 2 | Simple feuillure | 3 | yes | 1 | Poignée 6 | 13 | 3 | 1 | 126 | Pas d'ébrasure - arête | 1 | Uniforme | 1 | 0 | yes | _Men ext_RAL9007 | 90 | 4 | no | Ligne continue | 0 | Général - Dessin 0.12 | 1 | Ouvertures - Général | Eléments 2D - Général | Sans Trame | Ouvertures - fonds de hachure | Sans Trame | Ouvertures - Hachures coupées | Hachure solide | Fond - Couleur 1 | Fond - Couleur 1 | _Huisserie-int | _Huisserie-int | _Grain de riz | _Verre clair (rapide) | 0 | 0.92 | ArchiCADProperties - De Zone: Sanitaires
P ext-pluri -detail- | RDC |  | Element de construction non défini (Classification Archicad); Fenêtre (Classification ARCHICAD) |  | P ext-pluri -detail- | 10_M x baseGO__ | Menuis1 |  | Salle plurivalente | RDC | 0 | M ext pluri-Sud | _Men ext_RAL9007; _Verre clair (rapide) | Non défini | 100×240 | 90×235 | 90×235 | 100×240 | 100×240×36 |  | _M ext 18 +18 gris | G | Fenêtre | no | 1 | 1 | 2 | yes | 0 | yes | no | 2 | Simple feuillure | 3 | no | 46 | Barre anti-panique 1 | 23 | 1 | 6 | 64 | Baie simple | 2 | Uniforme | 1 | 0 | no | _Men ext_RAL9007 | 90 | 4 | no | Tirets | 1 | Général - Dessin 0.12 | 1 | Ouvertures - Général | Ouvertures - Général | Sans Trame | Ouvertures - fonds de hachure | Sans Trame | Ouvertures - Hachures coupées | Hachure solide | Général - Dessin 0.12 | Transparent | _Men ext_RAL9007 | _Men ext_RAL9007 | _Men ext_RAL9007 | _Verre clair (rapide) | 1.12 | 0.90 | ArchiCADProperties - De Zone: Salle plurivalente; AC_Pset_Porte_21 - Type d'opération tierce vitrée côté 2: Vitrage fixe; Type châssis tierce vitrée côté 2: Pas de grille
27 | RDC | bureau | Element de construction non défini (Classification Archicad); Porte (Classification ARCHICAD) | CF 1/2H | 27 | 20_Cloison________ | Menuis1 | Attente / Tisanerie | Bureau RASED | RDC | 0 | cloisons-suppr | _Serpentin-noir; _Mur int Hall; _Huisserie-int | Intérieur | 100×210 | 90×205 | 92×206 | 100×210 | 100×210×10 | P Pleine | _Cloison 10cm | D | Porte | yes | 1 | 1 | 2 | no | 0 | yes | no | 2 | Simple feuillure | 3 | yes | 1 | Poignée 6 | 13 | 3 | 1 | 126 | Pas d'ébrasure - arête | 1 | Uniforme | 1 | 0 | yes | _Men ext_RAL9007 | 90 | 4 | no | Ligne continue | 0 | Général - Dessin 0.12 | 1 | Ouvertures - Général | Eléments 2D - Général | Sans Trame | Ouvertures - fonds de hachure | Sans Trame | Ouvertures - Hachures coupées | Hachure solide | Fond - Couleur 1 | Fond - Couleur 1 | _Huisserie-int | _Mur int Hall | _Serpentin-noir | _Verre clair (rapide) | 0 | 0.92 | ArchiCADProperties - À Zone: Bureau RASED; De Zone: Attente / Tisanerie
28 | RDC | maîtres | Element de construction non défini (Classification Archicad); Porte (Classification ARCHICAD) | CF 1/2H | 28 | 20_Cloison________ | Menuis1 | Attente / Tisanerie | Activités RASED | RDC | 0 | cloisons-suppr | _Serpentin-noir; _Mur int Hall; _Huisserie-int | Intérieur | 100×210 | 90×205 | 92×206 | 90×205 | 90×205×10 | P Pleine | _Cloison 10cm | G | Porte | yes | 1 | 1 | 2 | no | 8 | no | yes | 2 | Simple feuillure | 3 | yes | 1 | Poignée 6 | 13 | 3 | 1 | 126 | Pas d'ébrasure - arête | 1 | Uniforme | 1 | 0 | yes | _Men ext_RAL9007 | 90 | 4 | no | Ligne continue | 0 | Général - Dessin 0.12 | 1 | Ouvertures - Général | Eléments 2D - Général | Sans Trame | Ouvertures - fonds de hachure | Sans Trame | Ouvertures - Hachures coupées | Hachure solide | Fond - Couleur 1 | Fond - Couleur 1 | _Huisserie-int | _Mur int Hall | _Serpentin-noir | _Verre clair (rapide) | 0 | 0.92 | ArchiCADProperties - À Zone: Activités RASED; De Zone: Attente / Tisanerie
29 | RDC | rangement 1 | Element de construction non défini (Classification Archicad); Porte (Classification ARCHICAD) | CF 1/2H | 29 | 10_M refendGO__ | Menuis1 | Activités RASED | Rangt. 1 | RDC | 0 | M refend | _Serpentin-noir; _Huisserie-int | Intérieur | 90×210 | 80×205 | 82×206 | 90×210 | 90×210×18 | CF 1/2H | _BA banché RAL9007 | D | Porte | yes | 0 | 1 | 2 | no | 0 | yes | no | 2 | Simple feuillure | 3 | yes | 1 | Poignée 6 | 13 | 3 | 1 | 126 | Pas d'ébrasure - arête | 1 | Uniforme | 1 | 0 | yes | _Men ext_RAL9007 | 90 | 4 | no | Ligne continue | 0 | Général - Dessin 0.12 | 1 | Ouvertures - Général | Eléments 2D - Général | Sans Trame | Ouvertures - fonds de hachure | Sans Trame | Ouvertures - Hachures coupées | Hachure solide | Fond - Couleur 1 | Fond - Couleur 1 | _Huisserie-int | _Huisserie-int | _Serpentin-noir | _Verre clair (rapide) | 0 | 0.82 | ArchiCADProperties - À Zone: Rangt. 1; De Zone: Activités RASED
P_Int BlocSanit | RDC |  | Element de construction non défini (Classification Archicad); Porte (Classification ARCHICAD) |  | P_Int BlocSanit | 20_Cloison________ | Sans Trame |  |  | RDC | 0 | Clois_BlocSanit | _Menuis interieur | Non défini | 90×205 | 80×200 | 80×200 | 90×205 | 90×205×10 |  | _Cloison 10cm WC | G | Porte | yes | 0 | 1 | 2 | no | 0 | yes | no | 1 | Parallélépipédiques | 1 | no | 1 | Poignée 6 | 13 | 3 | 1 | 126 | Pas d'ébrasure - arête | 1 | Baie simple | 2 | 0 | yes | _Bois - Pin granuleux horizontal | 30 | 37 | no | Ligne continue | 0 | Ouvertures - Général | 3 | Eléments 2D - Général | Ouvertures - Général | Isolation - Panneau rigide | Fond - Couleur 1 | Lame d'air | Fond - Couleur 1 | Lambourdage | Fond - Couleur 1 | Fond - Couleur 1 | _Menuis interieur | _Menuis interieur | _Menuis interieur | _Transp - Verre | 0 | 0.80
P_Int BlocSanit | RDC |  | Element de construction non défini (Classification Archicad); Porte (Classification ARCHICAD) |  | P_Int BlocSanit | 20_Cloison________ | Sans Trame |  |  | RDC | 0 | Clois_BlocSanit | _Menuis interieur | Non défini | 90×205 | 80×200 | 80×200 | 90×205 | 90×205×10 |  | _Cloison 10cm WC | D | Porte | yes | 1 | 1 | 2 | no | 0 | yes | no | 1 | Parallélépipédiques | 1 | no | 1 | Poignée 6 | 13 | 3 | 1 | 126 | Pas d'ébrasure - arête | 1 | Baie simple | 2 | 0 | yes | _Bois - Pin granuleux horizontal | 30 | 37 | no | Ligne continue | 0 | Ouvertures - Général | 3 | Eléments 2D - Général | Ouvertures - Général | Isolation - Panneau rigide | Fond - Couleur 1 | Lame d'air | Fond - Couleur 1 | Lambourdage | Fond - Couleur 1 | Fond - Couleur 1 | _Menuis interieur | _Menuis interieur | _Menuis interieur | _Transp - Verre | 0 | 0.80
P_Int BlocSanit | RDC |  | Element de construction non défini (Classification Archicad); Porte (Classification ARCHICAD) |  | P_Int BlocSanit | 20_Cloison________ | Sans Trame |  |  | RDC | 0 | Clois_BlocSanit | _Menuis interieur | Non défini | 100×205 | 90×200 | 90×200 | 100×205 | 100×205×10 |  | _Cloison 10cm WC | G | Porte | yes | 1 | 0 | 3 | no | 0 | yes | no | 1 | Parallélépipédiques | 1 | no | 1 | Poignée 6 | 13 | 3 | 1 | 126 | Pas d'ébrasure - arête | 1 | Baie simple | 2 | 0 | yes | _Bois - Pin granuleux horizontal | 30 | 37 | no | Ligne continue | 0 | Ouvertures - Général | 3 | Eléments 2D - Général | Ouvertures - Général | Isolation - Panneau rigide | Fond - Couleur 1 | Lame d'air | Fond - Couleur 1 | Lambourdage | Fond - Couleur 1 | Fond - Couleur 1 | _Menuis interieur | _Menuis interieur | _Menuis interieur | _Transp - Verre | 0 | 0.90
3 x P_Int BlocSanit | RDC |  | Element de construction non défini (Classification Archicad); Porte (Classification ARCHICAD) |  | P_Int BlocSanit | 20_Cloison________ | Sans Trame |  |  | RDC | 0 | Clois_BlocSanit | _Menuis interieur | Non défini | 90×205 | 80×200 | 80×200 | 90×205 | 90×205×10 |  | _Cloison 10cm WC | G | Porte | yes | 1 | 1 | 2 | no | 0 | yes | no | 1 | Parallélépipédiques | 1 | no | 1 | Poignée 6 | 13 | 3 | 1 | 126 | Pas d'ébrasure - arête | 1 | Baie simple | 2 | 0 | yes | _Bois - Pin granuleux horizontal | 30 | 37 | no | Ligne continue | 0 | Ouvertures - Général | 3 | Eléments 2D - Général | Ouvertures - Général | Isolation - Panneau rigide | Fond - Couleur 1 | Lame d'air | Fond - Couleur 1 | Lambourdage | Fond - Couleur 1 | Fond - Couleur 1 | _Menuis interieur | _Menuis interieur | _Menuis interieur | _Transp - Verre | 0 | 0.80
P_Int BlocSanit | RDC |  | Element de construction non défini (Classification Archicad); Porte (Classification ARCHICAD) |  | P_Int BlocSanit | 20_Cloison________ | Sans Trame |  |  | RDC | 0 | Clois_BlocSanit | _Menuis interieur | Non défini | 100×205 | 90×200 | 90×200 | 100×205 | 100×205×10 |  | _Cloison 10cm WC | D | Porte | yes | 1 | 0 | 3 | no | 0 | yes | no | 1 | Parallélépipédiques | 1 | no | 1 | Poignée 6 | 13 | 3 | 1 | 126 | Pas d'ébrasure - arête | 1 | Baie simple | 2 | 0 | yes | _Bois - Pin granuleux horizontal | 30 | 37 | no | Ligne continue | 0 | Ouvertures - Général | 3 | Eléments 2D - Général | Ouvertures - Général | Isolation - Panneau rigide | Fond - Couleur 1 | Lame d'air | Fond - Couleur 1 | Lambourdage | Fond - Couleur 1 | Fond - Couleur 1 | _Menuis interieur | _Menuis interieur | _Menuis interieur | _Transp - Verre | 0 | 0.90
25 | R+1 | sanitaire couloir | Element de construction non défini (Classification Archicad); Porte (Classification ARCHICAD) | CF 1/2H | 25 | 10_M refendGO__ | Menuis1 | Sanitaires | Circulation 3 | R+1 | 1 | M refend | _Huisserie-int; _Grain de riz | Intérieur | 100×210 | 90×205 | 92×206 | 100×210 | 100×210×18 | P Pleine | _BA banché RAL9007 | G | Porte | yes | 1 | 1 | 2 | no | 0 | yes | no | 2 | Simple feuillure | 3 | yes | 1 | Poignée 6 | 13 | 3 | 1 | 126 | Pas d'ébrasure - arête | 1 | Uniforme | 1 | 0 | yes | _Men ext_RAL9007 | 90 | 4 | yes | Ligne continue | 0 | Ouvertures - Général | 3 | Ouvertures - Général | Eléments 2D - Général | Sans Trame | Ouvertures - fonds de hachure | Sans Trame | Ouvertures - Hachures coupées | Hachure solide | Fond - Couleur 1 | Fond - Couleur 1 | _Huisserie-int | _Huisserie-int | _Grain de riz | _Verre clair (rapide) | 0 | 0.92 | ArchiCADProperties - De Zone: Circulation 3
26 | R+1 | sanitaire couloir | Element de construction non défini (Classification Archicad); Porte (Classification ARCHICAD) | CF 1/2H | 26 | 10_M refendGO__ | Menuis1 | Sanitaires | Circulation 3 | R+1 | 1 | M refend | _Huisserie-int; _Grain de riz | Intérieur | 100×210 | 90×205 | 92×206 | 100×210 | 100×210×18 | P Pleine | _BA banché RAL9007 | D | Porte | yes | 1 | 1 | 2 | no | 0 | yes | no | 2 | Simple feuillure | 3 | yes | 1 | Poignée 6 | 13 | 3 | 1 | 126 | Pas d'ébrasure - arête | 1 | Uniforme | 1 | 0 | yes | _Men ext_RAL9007 | 90 | 4 | yes | Ligne continue | 0 | Ouvertures - Général | 3 | Ouvertures - Général | Eléments 2D - Général | Sans Trame | Ouvertures - fonds de hachure | Sans Trame | Ouvertures - Hachures coupées | Hachure solide | Fond - Couleur 1 | Fond - Couleur 1 | _Huisserie-int | _Huisserie-int | _Grain de riz | _Verre clair (rapide) | 0 | 0.92 | ArchiCADProperties - De Zone: Circulation 3
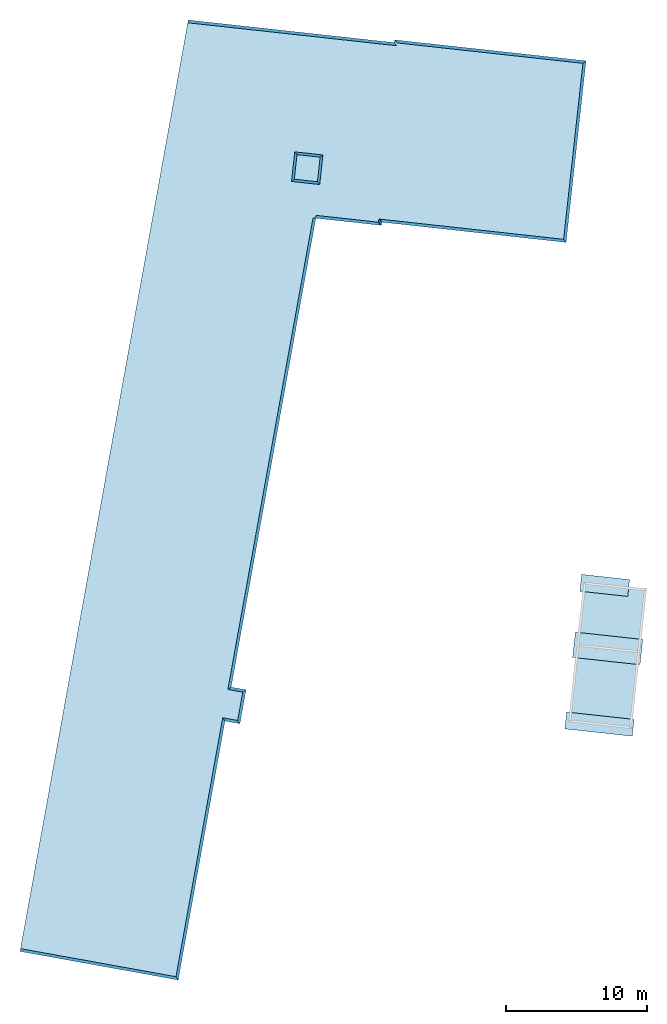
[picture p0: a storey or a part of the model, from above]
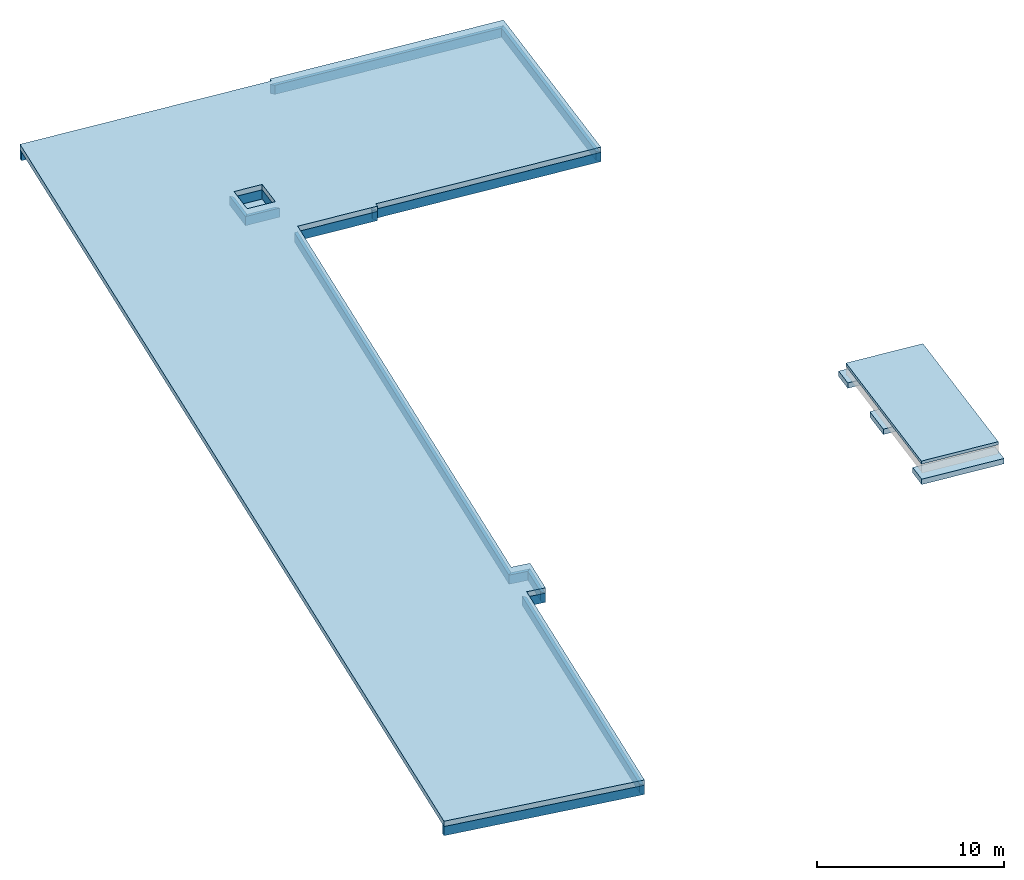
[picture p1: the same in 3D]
Properties of the parts of a building model (IFC2X3), part 5 of 10

# IfcBuildingElementProxy: Porte 21 (22)
Name | In | Description | Classification | FireResistanceRating | ID de l'élément = Lien et ID d'élément | Calque | Matériau de construction / Composite / Profil / Hachure = Type Hachure = Index hachure latérale ouverture | Zones conflictuelles | Nom de zone liée | Nom d'étage d'implantation | Numéro d'étage d'implantation | ID de Parent | Surfaces (Toutes) | Position | Dimensions ébrasure = Dimensions trou mur = Dimensions unité | Dimensions sortie | Dimensions battant | Taille L x H nominale | Taille L x H x E nominale | Résistance au feu = Degré de protection au feu | Structure de Mur | Orientation = Orientation porte | Classification ARCHICAD - 21 | Trou reprend surface latérale de mur | Type de direction de mur | Direction d'ouverture | Valeur incrustation allège | Tierce vitrée 2 = Connexion sur côté 1 = Connexion sur côté 2 = Utiliser hachures | Taille nominale | Taille trou comme taille nominale | Taille sortie comme nominale | Niveau de détail 2D | Style de cadre (gs_frame_style) | Style de cadre (gs_frame_style_m) | Largeur cadre uniforme | Style panneau de porte | Poignée d'ouverture (gs_handle_type) | Poignée d'ouverture (gs_handle_type_m) | Type d'ouverture (gs_optype_m_09) | Type volet | Types volet activés | Type ébrasure (gs_reveal_type_new) | Type ébrasure (gs_reveal_type_int) | Type ébrasure inférieure (gs_reveal_type_bottom) | Type ébrasure inférieure (gs_reveal_type_bottom_int) | Type ébrasure (gs_reveal_doubleOuterTypeInt) = Type ébrasure (gs_reveal_doubleInnerTypeInt) | Tourner automatiquement plâtre surface intérieure = Tourner automatiquement plâtre surface extérieure | Surface = Battant 2 = Battant 3 = Grille extérieure (gs_grill_mat) = Grille intérieure (gs_grill_mat2) = Grille extérieure (gs_leaf_grill_mat) = Grille intérieure (gs_leaf_grill_mat2) = Panneau solide extérieur = Panneau solide intérieur = Persienne extérieure = Persienne intérieure = Chambranle intérieur = Chambranle extérieur (gs_trim_out_mat) = Panneau volet = Cadre panneau volet = Seuil (gs_treshold_mat) = Tablette (gs_board_mat) | Angle ouverture en 2D (deg) | Type ligne va-et-vient = Type ligne contour int. mur masqué = Type ligne contour ext. mur masqué = Type ligne contour int. tierce vitrée ds mur masqué = Type ligne contour ext. tierce vitrée ds mur masqué | Suppl. Opt. vue pour aff. symb. 2D | Type ligne côté ouverture (or_opLineType3dIn) = Type ligne côté opposé (or_opLineType3dOut) | Type ligne côté ouverture (or_iOpLineType3dIn) = Type ligne côté opposé (or_iOpLineType3dOut) | Stylo ligne ouverture 2D/3D (or_opLinePen) | Stylo ligne ouverture 2D/3D (or_iOpLinePen) | Stylo contour cadre = Stylo contour battant = Stylo cadre = Stylo panneaux = Stylo vitrage = Stylo vitrage battant | Stylo ligne coupée chambranle des deux côtés | Motif de hachure cadre = Motif hachure symbole plan de porte = Motif hachure symbole plan de tierce vitrée = Motif hachure de seuil en Coupe = Motif de hachure arche coupe = Type hachure coupée volet = Type hachure non coupée | Stylo fond de hachure cadre = Stylo fond de hachure battant = Stylo fond hachure symbole plan de porte | Motif de hachure battant | Stylo hachure de battant = Stylo hachure symbole plan de porte | Motif hachure symbole étanche | Stylo hachure non coupée | Stylo fond de hachure non coupé | Cadre extérieur | Cadre intérieur | Battant extérieur = Battant intérieur | Vitrage (gs_glass_mat) = Vitrage (gs_leaf_glass_mat) | Surface vitrée totale (gs_list_glassarea) | Largeurs de battant de porte
30 | R+1 | reunion | Element de construction non défini (Classification Archicad); Porte (Classification ARCHICAD) | CF 1/2H | 30 | 10_M refendGO__ | Menuis1 | Circulation 2 | Salle de réunion (maîtres) | R+1 | 1 | M refend | _Serpentin-noir; _Mur int Hall | Intérieur | 100×210 | 90×205 | 92×206 | 100×210 | 100×210×18 | CF 1/2H | _BA banché RAL9007 | D | Porte | yes | 1 | 0 | 3 | no | 1 | yes | no | 2 | Simple feuillure | 3 | yes | 1 | Poignée 6 | 13 | 3 | 1 | 126 | Pas d'ébrasure - arête | 1 | Uniforme | 1 | 0 | yes | _Men ext_RAL9007 | 90 | 4 | no | Ligne continue | 0 | Général - Dessin 0.12 | 1 | Ouvertures - Général | Eléments 2D - Général | Sans Trame | Ouvertures - fonds de hachure | Sans Trame | Ouvertures - Hachures coupées | Hachure solide | Fond - Couleur 1 | Fond - Couleur 1 | _Mur int Hall | _Mur int Hall | _Serpentin-noir | _Verre clair (rapide) | 0 | 0.92 | ArchiCADProperties - À Zone: Salle de réunion (maîtres)
31 | R+1 | reunion | Element de construction non défini (Classification Archicad); Porte (Classification ARCHICAD) | CF 1/2H | 31 | 10_M refendGO__ | Menuis1 | Circulation 2 | Circulation 2 | R+1 | 1 | M refend | _Serpentin-noir; _Mur int Hall | Intérieur | 100×210 | 90×205 | 92×206 | 100×210 | 100×210×18 | CF 1/2H | _BA banché RAL9007 | G | Porte | yes | 1 | 0 | 3 | no | 0 | yes | no | 2 | Simple feuillure | 3 | yes | 1 | Poignée 6 | 13 | 3 | 1 | 126 | Pas d'ébrasure - arête | 1 | Uniforme | 1 | 0 | yes | _Men ext_RAL9007 | 90 | 4 | no | Ligne continue | 0 | Général - Dessin 0.12 | 1 | Ouvertures - Général | Eléments 2D - Général | Sans Trame | Ouvertures - fonds de hachure | Sans Trame | Ouvertures - Hachures coupées | Hachure solide | Fond - Couleur 1 | Fond - Couleur 1 | _Mur int Hall | _Mur int Hall | _Serpentin-noir | _Verre clair (rapide) | 0 | 0.92 | ArchiCADProperties - À Zone: Circulation 2

# IfcBuildingElementProxy: Porte avec tierce vitrée côté 2 21 (20)
Classification: Element de construction non défini (Classification Archicad); Porte (Classification ARCHICAD); Material: Matériau de construction IFC
Pset_FireRatingProperties - FireResistanceRating: CF 1/2H
ArchiCADProperties - Calque: 10_M refendGO__; Nom Élément de Bibliothèque: Porte avec tierce vitrée côté 2 21; Matériau de construction / Composite / Profil / Hachure: Sans Trame; Type Hachure: Sans Trame; Verrouillé: no; Type d'élément: Porte; ID de Parent: M refend; Position: Intérieur; État de rénovation: Existant; Affichage sur filtre de rénovation: Tous les filtres appropriés; Fonction structurelle: Non défini; Dimensions ébrasure: 140×210; Dimensions trou mur: 140×210; Dimensions unité: 140×210; Dimensions sortie: 86×205; Dimensions battant: 90×207; Taille L x H nominale: 140×210; Taille L x H x E nominale: 140×210×18; Résistance au feu: CF 1/2H; Structure de Mur: _BA banché RAL9007; Nom élément de bibliothèque d'ouverture: Porte avec tierce vitrée côté 2 21; Index hachure latérale ouverture: Sans Trame; Classification ARCHICAD - 21: Porte
AC_Pset_Porte_avec_tierce_vitrée_côté_2_21 - Contours Mur (0-Sans,1-Tout,2-Côté,3-Longueur): 0; Point ch.0-Non,1-2D,2-3D,3-Tous: 3; Afficher points chauds 2D en 3D: yes; Option affichage en plan: 3; Angle de position baie: 0 deg; Trou reprend surface latérale de mur: yes; Division de surface du trou courbe dans murs courbes: no; Type de mur: 1; Type de direction de mur: 0; Position ancre ébrasuer: 1; Direction d'ouverture: 0; Basculer: no; Valeur incrustation allège: 3; Démolition / Nouvelle constr.: 1; Nouveau motif de hachure de mur: Parpaing; Nouveau stylo de hachure de mur: Général - Dessin 0.12; Nouveau stylo fond hachure mur: Fond - Couleur 1; Afficher nouv. constr. sur mur: no; Type de ligne démolition: 1; Aff. param. Démolition/Nouveau: no; Afficher comme imposte: no; Tolérances uniformes: yes; Taille nominale: 0; Taille trou comme taille nominale: yes; Taille ébrasure comme nominale: no; Taille unité comme nominale: no; Taille sortie comme nominale: no; Taille battant comme nominale: no; Transmettre taille nominale actuelle à sélection: no; Afficher points chaud éditables: yes; Niveau de détail 2D: 2; Afficher ébrasure sur symbole: 1; Affichage symbolique de l'ouverture: no; Niveau de détail 3D: 2; Direction ouverture tiere vitrée (gs_opening_dir_sl): Opposé à battant; Direction ouverture tiere vitrée (gs_opening_dir_sl_m): 2; Cadre porte (gs_pocket_door_frame): yes; Style de cadre (gs_frame_style): Simple feuillure; Style de cadre (gs_frame_style_m): 3; Epaisseur cadre=Epaisseur mur: no; Epaisseur cadre uniforme: yes; Battant centré: yes; Largeur cadre uniforme: no; Style cadre changé automatiquement: no; Nombre de battants: 4; Nombre de battants - côté 2: 3; Style panneau de porte: 1; Configuration battants (gs_LeavesConfig): Battants uniformes; Configuration battants (gs_iLeavesConfig): 1; Position grille (gs_grill_pos): Les deux; Position grille (gs_grill_pos_m): 3; Nombre panneaux verticalement: 4; Nombre panneaux horizontalement: 3; Nbre panneaux vert. côté 1: 4; Nbre panneaux hor. côté 1: 3; Afficher comme panneau vitre sur symbole: no; Afficher symbole porte chinoise: no; Afficher symbole comme panneau étanche: no; Poignée d'ouverture (gs_handle_type): Poignée 6; Poignée d'ouverture (gs_handle_type_m): 13; Afficher poignée sur symbole: no; Plaque bas de porte extérieure (bKickBoardOut): no; Plaque bas de porte intérieure (bKickBoardIn): no; Châssis vitré (gs_SidelightTransomRelation): Sous imposte; Châssis vitré (gs_SidelightTransomRelation_m): 1; Tierce vitrée 1: no; Tierce vitrée 2: yes; Imposte: no; Division horizontale tierce vitrée: no; Châssis uniformes: no; Type d'ouverture (gs_optype_m_05): 1; Type ouverture panneau adj.: Vitrage fixe; Type d'ouverture (gs_optype_m_09): 1; Type d'ouverture (gs_optype_m_07): 1; Type d'ouverture (gs_optype_m_11): 1; Type d'ouverture (gs_optype_m_02): 1; Type d'ouverture (gs_optype_m_06): 1; Type d'ouverture (gs_optype_m_10): 1; Type châssis (MullionStyle_00): Pas de grille; Type châssis (iMullionStyle_00): 1; Type châssis (iMullionStyle_05): 1; Type châssis tierce vitrée: Pas de grille; Type châssis (iMullionStyle_09): 1; Type châssis (iMullionStyle_07): 15; Type châssis (iMullionStyle_11): 15; Type châssis (iMullionStyle_02): 1; Type châssis (iMullionStyle_06): 1; Type châssis (iMullionStyle_10): 1; Edition point chaud de grille: yes; Position grille (MullionPosition): Les deux; Position grille (iMullionPosition): 3; Nbre panneaux V tierce vitrée (hgn_05): 4; Nbre panneaux H tierce vitrée (vgn_05): 2; Nbre panneaux V 2 tierce vitrée (hgn2_05): 4; Nbre panneaux H 2 tierce vitrée (vgn2_05): 2; Nbre panneaux V tierce vitrée (hgn_09): 4; Nbre panneaux H tierce vitrée (vgn_09): 2; Nbre panneaux V 2 tierce vitrée (hgn2_09): 4; Nbre panneaux H 2 tierce vitrée (vgn2_09): 2; Nbre panneaux V tierce vitrée inf. (hgn_07): 4; Nbre panneaux hor. tierce vitrée inf. (vgn_07): 2; Nbre panneaux V 2 tierce vitrée inf. (hgn2_07): 4; Nbre panneaux H 2 tierce vitrée inf. (vgn2_07): 2; Nbre panneaux V tierce vitrée inf. (hgn_11): 4; Nbre panneaux hor. tierce vitrée inf. (vgn_11): 2; Nbre panneaux V 2 tierce vitrée inf. (hgn2_11): 4; Nbre panneaux H 2 tierce vitrée inf. (vgn2_11): 2; Nbre panneaux vert. imposte principale: 2; Nbre panneaux H imposte principale: 2; Nombre panneaux vert. 2 imposte principale: 2; Nombre panneaux horizontalement 2 imposte principale: 2; Nbre panneaux V imposte côté: 2; Nbre panneaux H imposte côté: 2; Nbre panneaux vert. 2 imposte côté: 2; Nbre panneaux hor. 2 imposte côté: 2; Nbre panneaux vert. imposte côté 2: 2; Nbre panneaux hor. imposte côté 2: 2; Nbre panneaux V 2 imposte côté 2: 2; Nbre panneaux H 2 imposte côté 2: 2; Style persiennes (iLouverStyle): 1; Angle d'ouverture persiennes: 0 deg; Chambranle extérieur (gs_trim_outside): no; Type chambr. ext. (gs_trimtype_out): Simple; Type chambr. ext. (gs_trimtype_out_int): 1; Type tête chambr. ext.: 1; Chapiteau architrave: yes; Type chapiteau architrave: 1; Couvre surface mur ext.: yes; Largeurs uniformes de chambranle (gs_trim_outside_uniform): yes; Chambranle intérieur.: no; Type chambr. intérieur (gs_trimtype_in): Simple; Type chambr. intérieur (gs_trimtype_in_int): 1; Couvre surface mur int.: yes; Largeurs uniformes de chambranle (gs_trim_inside_uniform): yes; Seuil (bThreshold): no; Type seuil: 2; Angle seuil: 3.1996 deg; Seuil changé automatiquement: no; Appui - porte: no; Appui - Tierce vitrée côté 1: no; Appui - Tierce vitrée: no; Dépassement appui: no; Type d'appui/seuil: 1; Angle appui: 3 deg; Appui courbe dans murs courbes: yes; Isolation sous appui: yes; Utiliser couche isolation mur: no; Niveau détail 3D seuil brique: 1; Style appui changé automatiquement: no; Tablette - côté tierce vitrée 1: no; Tablette - Tierce vitrée: no; Tablette - porte: no; Angle tablette: 0 deg; Tabl. courbe dans murs courbes: yes; Tableau dans murs polygonaux: 1; Aération naturelle: no; Type d'aération naturelle: 2; Châssis vitré (isVentilationProfileInSash_09): yes; Tierce vitrée inf.: no; Volet: no; Type volet: 1; Types volet activés: 126; Nombre de panneaux: 2; Nombre de panneaux 2: 1; Position panneau (gs_shutter_panelPos): Symétrique; Position panneau (gs_shutter_iPanelPos): 1; Hauteur volet automatique: yes; Cadre supplémentaire: no; Type de couverture (gs_slidingShutter_cover): Profil en Z; Type de couverture (gs_slidingShutter_iCover): 1; Direction articulation (gs_foldingShutter_stacking): Intérieur; Direction articulation (gs_foldingShutter_iStacking): 1; Ouvert en 3D: yes; Angle ouverture en 3D (gs_shutter_opAngle): 180 deg; Afficher symbole 2D: yes; Afficher lignes d'ouverture sur symbole: no; Type de panneau: (gs_shutPanel_type): Style 1; Type de panneau: (gs_shutPanel_iType): 1; Largeur cadre inf. différente: no; Largeur volets automatiques: yes; Angle persienne: 30 deg; Nombre trous horizontaux: 5; Nombre trous verticaux: 8; Placement volet roulant (gs_shutRoll_placement): Sur façade; Placement volet roulant (gs_shutRoll_iPlacement): 1; Type boîte (gs_shutRoll_boxType): Rectangulaire; Type boîte (gs_shutRoll_iBoxType): 1; Position rampe (gs_shutRoll_railPos): Sur revêtement; Position rampe (gs_shutRoll_iRailPos): 1; Afficher revêtement derrière parasol (gs_shutRoll_showCasingBehind): no; Isolation derrière cellule (gs_shutRoll_cutWallBehind): no; Inclure hauteur dans hauteur de trou de mur: no; Angle supérieur boîte: 10 deg; Taille boîte par défaut (gs_shutRoll_boxDefaultSize): Largeur ébrasure; Taille boîte par défaut (gs_shutRoll_iBoxDefaultSize): 1; Placement stores (gs_shutLam_placement): Fixé sur façade; Placement stores (gs_shutLam_iPlacement): 1; Isolation derrière cellule (gs_shutLam_cutWallBehind): no; Boîte ouverte: yes; Rampe (gs_shutLam_bRail): yes; Position rampe (gs_shutLam_railPos): Sur revêtement; Position rampe (gs_shutLam_iRailPos): 1; Afficher revêtement derrière parasol (gs_shutLam_showCasingBehind): no; Angle de rotation des lamelles (gs_shutLam_rotation): 45 deg; Angle de rotation des lamelles (gs_shutLam2_rotation): 45 deg; Linteau (bMasonryArch): no; Linteau (gs_masonry_arch_int): 2; Type linteau (gs_masonry_arch_structure): Stuc; Type linteau (gs_masonry_arch_structure_int): 1; Arche sur linteau: yes; Niche sous arche: yes; Angle inclinaison: 75 deg; Surface niche personnalisée: no; Type ébrasure (gs_reveal_type_new): Baie simple; Type ébrasure (gs_reveal_type_int): 2; Type ébrasure inférieure (gs_reveal_type_bottom): Uniforme; Type ébrasure inférieure (gs_reveal_type_bottom_int): 1; Définir profondeur montant sur côté: 1; Profondeur montant uniforme: yes; Type ébrasure extérieure: Baie simple; Type ébrasure (gs_reveal_doubleOuterTypeInt): 0; Type ébrasure intérieure: Baie simple; Type ébrasure (gs_reveal_doubleInnerTypeInt): 0; Côté angle 2: 20 deg; Côté angle: 20 deg; Angle côté supérieur: 20 deg; Angle côté inférieur: 20 deg; Côté angle extérieur 2: 20 deg; Côté angle extérieur: 20 deg; Angle extérieur côté sup.: 20 deg; Angle extérieur côté inf.: 20 deg; Rampe sous battants: no; Rampe (gs_door_rail_ext): Sans; Rampe (gs_door_rail_ext_m): 1; Utiliser composant finition mur: no; Tourner automatiquement plâtre surface intérieure: yes; Tourner plâtre surface intérieure: 0; Tourner automatiquement plâtre surface extérieure: yes; Tourner plâtre surface extérieure: 0; Peut être coté en 2D: no; Afficher en 3D: no; Type de fermeture (gs_closure_type): Pas de fermeture; Type de fermeture (gs_closure_type_int): 1; Tourner couche sur côté (gs_cavity_side): Les deux; Tourner couche sur côté (iCavityClosureSide): 1; Nbre de couches retournées: 1; Num. à partir de (gs_nTurnDir): Face extérieure; Num. à partir de (iCavityClosureTurnDir): 1; Placer fermeture sur côté 1: yes; Placer fermeture sur côté 2: yes; Placer fermeture en haut: no; Placer fermeture en bas: no; Placer fermeture sur couche: 1; Placer fermeture de côté (gs_cc_dutch_ClosureToSide): 1; Ecart à couche externe: yes; Tourner couche sur fermeture: no; Insérer bande d'isolation: yes; Afficher bande d'isolation: yes; Stylo contour (gs_penJoint): Ouvertures - Coupé non structurel; Type de ligne de contour (gs_ltJoint): 1; Motif de hachure (gs_fillJoint): Isolation polystyrène; Stylo hachure (gs_penJointFg): Général - Dessin 0.12; Stylo fond de hachure (gs_penJointBg): Eléments 2D - Dessin; Surface personnalisée: no; Surface: _Men ext_RAL9007; Stylo contour (gs_penPlug): Ouvertures - Coupé non structurel; Type de ligne de contour (gs_ltPlug): 1; Motif de hachure (gs_fillPlug): Isolation polystyrène; Stylo hachure (gs_penPlugFg): Général - Dessin 0.12; Stylo fond de hachure (gs_penPlugBg): Eléments 2D - Dessin; Côté montant édité: 1; Côté mur édité: 1; Numéro couche éditée: 1; Tourner couche: no; Considérer couches comme plâtre: no; Tourner épaiseur: 1; Orientation hachure: 1; Ligne de séparation tournant: no; Stylo ligne de séparation: Général - Dessin 0.12; Dernier côté sélectionné: no; Méthode fermeture changée auto.: no; Connexion sur côté 1: no; Connexion sur côté 2: no; Connexion en haut: no; Type d'ouverture (gs_leaf_optype): Battant; Type d'ouverture (gs_leaf_optype_m): 1; Ouverture panneau de fin côté 1: no; Ouverture panneau de fin côté 2: no; Angle ouverture en 2D: 90 deg; Angle ouverture 2D côté 2: 90 deg; Angle ouverture en 2D tierce vitrée 1: 0 deg; Angle ouverture en 2D tierce vitrée 2: 0 deg; Angle ouverture en 3D (gs_open_3D): 0 deg; Angle ouv. battant fin 3D côté 2: 0 deg; Angle ouv. tierce vitrée (openingAngle_05): 0 deg; Angle ouv. tierce vitrée (openingAngle2_05): 0 deg; Angle ouv. tierce vitrée (openingAngle_09): 0 deg; Angle ouv. tierce vitrée (openingAngle2_09): 0 deg; Angle ouv. tierce vitrée inf. (openingAngle_07): 0 deg; Angle ouv. tierce vitrée inf. (openingAngle2_07): 0 deg; Angle ouv. tierce vitrée inf. (openingAngle_11): 0 deg; Angle ouv. tierce vitrée inf. (openingAngle2_11): 0 deg; Angle ouverture imposte principale (openingAngle_02): 0 deg; Angle ouverture imposte principale (openingAngle2_02): 0 deg; Angle ouverture imposte côté (openingAngle_06): 0 deg; Angle ouverture imposte côté (openingAngle2_06): 0 deg; Angle ouverture imposte côté 2 (openingAngle_10): 0 deg; Angle ouverture imposte côté 2 (openingAngle2_10): 0 deg; Type ligne va-et-vient: 4; Suppl. Opt. vue pour aff. symb. 2D: no; Type ligne ouverture (or_swingLineType): 1; Forme ligne ouverture (or_SwingType): Courbé; Forme ligne ouverture (or_iSwingType): 1; Forme ligne ouverture (or_SlidingType): Sans; Forme ligne ouverture (or_iSlidingType): 0; Suppl. Opt. vue pour proj. porte 3D: no; Afficher ligne d'ouverture (or_bOplines3d): yes; Type ligne côté ouverture (or_opLineType3dIn): Tirets; Type ligne côté ouverture (or_iOpLineType3dIn): 1; Type ligne côté opposé (or_opLineType3dOut): Tirets; Type ligne côté opposé (or_iOpLineType3dOut): 1; Orient. ligne (or_oplineStyle): Poignée; Orient. ligne (or_iOplineStyle): 1; Stylo ligne ouverture 2D/3D (or_opLinePen): Général - Dessin 0.12; Stylo ligne ouverture 2D/3D (or_iOpLinePen): 1; Suppl. Opt. vue pour aff. symb. 2D de tierce vitrée: no; Type ligne ouverture (or_winSwingLineType): 1; Forme ligne ouverture (or_winSwingType): Courbé; Forme ligne ouverture (or_iWinSwingType): 1; Suppl. Opt. vue mod. pr proj. 3D tierce/imposte: no; Afficher ligne d'ouverture (or_bWinOplines3d): yes; Type ligne côté ouverture (or_winOpLineType3dIn): Ligne continue; Type ligne côté ouverture (or_iWinOpLineType3dIn): 0; Type ligne côté opposé (or_winOpLineType3dOut): Ligne continue; Type ligne côté opposé (or_iWinOpLineType3dOut): 0; Orient. ligne (or_winOplineStyle): Poignée; Orient. ligne (or_iWinOplineStyle): 1; Stylo ligne ouverture 2D/3D (or_winOpLinePen): Ouvertures - Général; Stylo ligne ouverture 2D/3D (or_iWinOpLinePen): 3; Stylo du symbole: Ouvertures - Général; Stylo contour cadre: Ouvertures - Général; Stylo ligne coupée chambranle des deux côtés: Général - Contours vus; Stylo contour battant: Ouvertures - Général; Ligne contour de porte ds mur (gs_wcont_line): Sans; Ligne contour de porte ds mur (iWallContourLine): 1; Type ligne contour int. porte ds mur: 1; Type ligne contour ext. porte ds mur: 1; Type ligne contour int. porte ds mur masqué: 4; Type ligne contour ext. porte ds mur masqué: 4; Ligne contour de tierce vitrée ds mur (gs_wcont_line_sl): Des deux côtés; Ligne contour de tierce vitrée ds mur (iWallContourLineSl): 4; Type ligne contour int. tierce vitrée ds mur: 1; Type ligne contour ext. tierce vitrée ds mur: 1; Type ligne contour int. tierce vitrée ds mur masqué: 4; Type ligne contour ext. tierce vitrée ds mur masqué: 4; Stylo ligne contour de mur: Ouvertures - Général; Utiliser hachures: no; Motif de hachure cadre: Sans Trame; Stylo hachure cadre: Ouvertures - Hachures coupées; Stylo fond de hachure cadre: Ouvertures - fonds de hachure; Motif de hachure battant: Sans Trame; Stylo hachure de battant: Ouvertures - Hachures coupées; Stylo fond de hachure battant: Ouvertures - fonds de hachure; Motif hachure symbole étanche: Hachure solide; Stylo hachure symbole étanche: Général - Dessin 0.12; Stylo fond hachure symbole étanche: Général - Dessin 0.12; Motif hachure symbole plan de porte: Sans Trame; Stylo hachure symbole plan de porte: Ouvertures - Hachures coupées; Stylo fond hachure symbole plan de porte: Ouvertures - fonds de hachure; Motif hachure symbole plan de tierce vitrée: Sans Trame; Stylo hachure symbole plan de tierce vitrée: Fond - Couleur 1; Stylo fond hachure symbole plan de tierce vitrée: Fond - Couleur 1; Type ligne seuil et appui: 1; Stylo contour de seuil en coupe: Ouvertures - Général; Motif hachure de seuil en Coupe: Sans Trame; Stylo hachure seuil en Coupe: Fond - Couleur 1; Stylo fond hachure coupe Seuil: Fond - Couleur 1; Stylo appui 3D et non coupé: Général - Dessin 0.12; Stylo contour appui en Coupe: Général - Dessin 0.12; Motif hachure appui en Coupe: Lame d'air; Stylo hachure d'appui en Coupe: Fond - Couleur 1; Stylo fond hachure appui Coupe: Fond - Couleur 1; Stylo contour isolation coupe: Général - Dessin 0.12; Motif hachure isolation Coupe: Isolation polystyrène; Stylo hachure isolation Coupe: Général - Dessin 0.12; Stylo fond hachure isol. Coupe: Fond - Couleur 1; Stylo latte 3D et non coupé: Général - Dessin 0.12; Stylo contour latte en Coupe: Général - Dessin 0.12; Motif hachure tablette en Coupe: Lame d'air; Stylo hachure tablette en Coupe: Fond - Couleur 1; Stylo fond hach. tablette Coupe: Fond - Couleur 1; Type hachure chambr. intérieur: Lame d'air; Stylo hachure chambr. int.: Fond - Couleur 1; Stylo fond hachure chambr. int.: Fond - Couleur 1; Type hachure chambr. ext.: Lame d'air; Stylo hachure chambr. ext.: Fond - Couleur 1; Stylo fond hachure chambr. ext.: Fond - Couleur 1; Motif de hachure arche coupe: Sans Trame; Stylo hachure en coupe d'arche: Fond - Couleur 1; Stylo fond hachure appui arche Coupe: Fond - Couleur 1; Motif de hachure de Coupe de Profil de ventilation: Lame d'air; Stylo de hachure de Coupe de Profil de ventilation: Fond - Couleur 1; Stylo de fond de hachure de Coupe de Profil de ventilation: Fond - Couleur 1; Type de ligne symbole volet: 1; Stylo ligne coupée volet: Général - Dessin 0.12; Stylo ligne non coupée 3D/Coupe: Général - Dessin 0.12; Type hachure coupée volet: Sans Trame; Stylo hachure coupée volet: Général - Dessin 0.12; Stylo fond hachure coupé volet: Fond de fenêtre; Motif de hachure d'isolation de volet: Dallage; Stylo de hachure d'isolation de volet: Général - Dessin 0.12; Stylo de fond d'isolation de volet: Fond de fenêtre; Type hachure non coupée: Sans Trame; Stylo hachure non coupée: Ouvertures - Hachures coupées; Stylo fond de hachure non coupé: Ouvertures - fonds de hachure; Valeurs côté ouverture (gs_opside_list): Personnalisé; Valeurs côté ouverture (gs_opside_list_m): 0; Jonction éléments cadree (gs_SashText_typ): Assemblage bout à bout; Jonction éléments cadree (gs_SashText_typ_num): 2; Stylo cadre: Ouvertures - Général; Stylo panneaux: Ouvertures - Général; Stylo vitrage: Ouvertures - Général; Stylo vitrage battant: Ouvertures - Général; Stylo linteau: Murs - Général; Résolution de courbe: 32; Ombre: yes; Surfaces de porte uniformes: no; Cadre extérieur: _Huisserie-int; Cadre intérieur: _Huisserie-int; Battant 2: _Men ext_RAL9007; Battant 3: _Men ext_RAL9007; Tierce vitrée extérieure: _Men ext_RAL9007; Tierce vitrée intérieure: _Men ext_RAL9007; Verrou (gs_lock_mat): _Peinture - Anthracite; Grille extérieure (gs_grill_mat): _Men ext_RAL9007; Grille intérieure (gs_grill_mat2): _Men ext_RAL9007; Grille extérieure (gs_leaf_grill_mat): _Men ext_RAL9007; Grille intérieure (gs_leaf_grill_mat2): _Men ext_RAL9007; Panneau solide extérieur: _Men ext_RAL9007; Panneau solide intérieur: _Men ext_RAL9007; Vitrage (gs_glass_mat): _Verre clair (rapide); Vitrage (gs_leaf_glass_mat): _Verre clair (rapide); Rampe (gs_rail_mat): _Métal - Fer; Persienne extérieure: _Men ext_RAL9007; Persienne intérieure: _Men ext_RAL9007; Persiennes: _Men ext_RAL9007; Plaque bas de porte: _Métal BAVETTE; Surfaces uniformes de chambranle: yes; Chambranle intérieur: _Men ext_RAL9007; Chambranle extérieur (gs_trim_out_mat): _Men ext_RAL9007; Profil Ventilation: _Métal BAVETTE; Panneau volet: _Men ext_RAL9007; Cadre panneau volet: _Men ext_RAL9007; Boîte volet roulant: _Métal - Acier inoxydable; Lames volet roulant: _Peinture - Blanc brillant; Rail volet roulant: _Peinture - Blanc brillant; Boîte store vénitien: _Métal - Acier inoxydable; Segments store vénitien: _Peinture - Blanc brillant; Rail volet coulissant: _Métal - Acier inoxydable; Seuil (gs_treshold_mat): _Men ext_RAL9007; Métal seuil: _Métal BAVETTE; Appui (gs_sill_mat): _Coupe3D_; Mortier appui briques: _Enduit - Blanc nature; Tablette (gs_board_mat): _Men ext_RAL9007; Poignée: _Métal - Acier inoxydable; Accessoires poignée: _Métal - Fer; Plaque bas de porte extérieure (matKickBoardOut): _Métal - Acier inoxydable; Plaque bas de porte intérieure (matKickBoardIn): _Métal - Acier inoxydable; Brique linteau: _Coupe3D_; Mortier linteau: _Enduit - Blanc nature; Clef de voûte linteau: _Pierre - Grès 01; Niche: _Mur int Hall; Porte appartient à Zone vers laquelle elle donne: yes; Coût: 0; Emplacement comme: Personnalisé; Surface vitrée totale (gs_list_glassarea_tmp): 0; Supplanter surface vitrée: no; Surface vitrée totale (gs_list_glassarea): 0.7215; Périmètre total vitrage: 0; Degré de protection au feu: CF 1/2H; Performance air libre (mm2/l/m): 0; Type de groupe (FM_Type): Autres; Type de groupe (iFMType): 25; Poids de l'objet: 0; Unité poids de l'objet: kg; Définition orientation porte: 0; Fermeture porte: no; Type panneau de vision: Nbre panneaux vision; Dispositif main. ouvert.: no; Largeurs de battant de porte: 0.90; Opération IFC (ifc_optypestr): Autre; Opération IFC (ifc_optype): 12
AC_Pset_RenovationAndPhasing - Renovation Status: Existing
Name | In | Description | ID de l'élément = Lien et ID d'élément | Zones conflictuelles | Nom de zone liée = À Zone | Nom d'étage d'implantation | Numéro d'étage d'implantation | Surfaces (Toutes) | Orientation = Orientation porte | Battant extérieur = Battant intérieur
5 | RDC | salle de classe 3 | 5 | Circulation 1 | Salle de classe 3 | RDC | 0 | _Verre clair (rapide); _Classe 3-RAL3003; _Huisserie-int | D | _Classe 3-RAL3003 | ArchiCADProperties - De Zone: Circulation 1
6 | RDC | salle de classe 3 | 6 | Circulation 1 | Salle de classe 3 | RDC | 0 | _Verre clair (rapide); _Classe 3-RAL3003; _Huisserie-int | G | _Classe 3-RAL3003
7 | RDC | salle de classe 4 | 7 | Circulation 1 | Salle de classe 4 | RDC | 0 | _Verre clair (rapide); _Classe 4-RAL6026; _Huisserie-int | D | _Classe 4-RAL6026
8 | RDC | salle de classe 4 | 8 | Circulation 1 | Salle de classe 4 | RDC | 0 | _Verre clair (rapide); _Classe 4-RAL6026; _Huisserie-int | G | _Classe 4-RAL6026
9 | RDC | salle de classe 5 | 9 | Circulation 1 | Salle de classe 5 | RDC | 0 | _Verre clair (rapide); _Classe 5-RAL4006; _Huisserie-int | D | _Classe 5-RAL4006
10 | RDC | salle de classe 5 | 10 | Circulation 1 | Salle de classe 5 | RDC | 0 | _Verre clair (rapide); _Classe 5-RAL4006; _Huisserie-int | G | _Classe 5-RAL4006
1 | RDC | Salle de classe 1 | 1 |  | Salle de classe 1 | RDC | 0 | _Verre clair (rapide); _Classe 1-RAL2000; _Huisserie-int | D | _Classe 1-RAL2000 | ArchiCADProperties - De Zone: Circulation 1
2 | RDC | salle de classe 1 | 2 |  | Salle de classe 1 | RDC | 0 | _Verre clair (rapide); _Classe 1-RAL2000; _Huisserie-int | G | _Classe 1-RAL2000
3 | RDC | salle de classe 2 | 3 |  | Salle de classe 2 | RDC | 0 | _Verre clair (rapide); _Classe 2-RAL5018; _Huisserie-int | D | _Classe 2-RAL5018 | ArchiCADProperties - De Zone: Circulation 1
4 | RDC | salle de classe 2 | 4 | Circulation 1 | Salle de classe 2 | RDC | 0 | _Verre clair (rapide); _Classe 2-RAL5018; _Huisserie-int | G | _Classe 2-RAL5018
15 | R+1 | salle de classe 8 | 15 | Circulation 3 | Circulation 3 | R+1 | 1 | _Verre clair (rapide); _Classe 3-RAL3003; _Huisserie-int | D | _Classe 3-RAL3003
16 | R+1 | salle de classe 8 | 16 |  | Salle de classe 8 | R+1 | 1 | _Verre clair (rapide); _Classe 3-RAL3003; _Huisserie-int | G | _Classe 3-RAL3003 | ArchiCADProperties - De Zone: Circulation 3
17 | R+1 | salle de classe 9 | 17 |  | Salle de classe 9 | R+1 | 1 | _Verre clair (rapide); _Classe 4-RAL6026; _Huisserie-int | D | _Classe 4-RAL6026 | ArchiCADProperties - De Zone: Circulation 3
18 | R+1 | salle de classe 9 | 18 |  | Salle de classe 9 | R+1 | 1 | _Verre clair (rapide); _Classe 4-RAL6026; _Huisserie-int | G | _Classe 4-RAL6026
19 | R+1 | salle de classe 10 | 19 |  | Salle de classe 10 | R+1 | 1 | _Verre clair (rapide); _Classe 5-RAL4006; _Huisserie-int | D | _Classe 5-RAL4006 | ArchiCADProperties - De Zone: Circulation 3
20 | R+1 | salle de classe 10 | 20 |  | Salle de classe 10 | R+1 | 1 | _Verre clair (rapide); _Classe 5-RAL4006; _Huisserie-int | G | _Classe 5-RAL4006 | ArchiCADProperties - De Zone: Circulation 3
11 | R+1 | salle de classe 6 | 11 | Circulation 2 | Salle de classe 6 | R+1 | 1 | _Verre clair (rapide); _Classe 1-RAL2000; _Huisserie-int | D | _Classe 1-RAL2000 | ArchiCADProperties - De Zone: Circulation 2
12 | R+1 | salle de classe 6 | 12 | Circulation 2 | Salle de classe 6 | R+1 | 1 | _Verre clair (rapide); _Classe 1-RAL2000; _Huisserie-int | G | _Classe 1-RAL2000
13 | R+1 | salle de classe 7 | 13 | Circulation 2 | Salle de classe 7 | R+1 | 1 | _Verre clair (rapide); _Classe 2-RAL5018; _Huisserie-int | D | _Classe 2-RAL5018
14 | R+1 | salle de classe 7 | 14 | Circulation 2 | Salle de classe 7 | R+1 | 1 | _Verre clair (rapide); _Classe 2-RAL5018; _Huisserie-int | G | _Classe 2-RAL5018

# IfcBuildingElementProxy: Porte double 21 (4)
Material: Matériau de construction IFC
ArchiCADProperties - Nom Élément de Bibliothèque: Porte double 21; Verrouillé: no; Type d'élément: Porte; État de rénovation: Existant; Affichage sur filtre de rénovation: Tous les filtres appropriés; Nom élément de bibliothèque d'ouverture: Porte double 21
AC_Pset_Porte_double_21 - Contours Mur (0-Sans,1-Tout,2-Côté,3-Longueur): 0; Point ch.0-Non,1-2D,2-3D,3-Tous: 3; Afficher points chauds 2D en 3D: yes; Option affichage en plan: 3; Angle de position baie: 0 deg; Trou reprend surface latérale de mur: yes; Division de surface du trou courbe dans murs courbes: no; Type de mur: 1; Position ancre ébrasuer: 1; Basculer: no; Démolition / Nouvelle constr.: 1; Nouveau motif de hachure de mur: Parpaing; Nouveau stylo de hachure de mur: Général - Dessin 0.12; Nouveau stylo fond hachure mur: Fond - Couleur 1; Afficher nouv. constr. sur mur: no; Type de ligne démolition: 1; Aff. param. Démolition/Nouveau: no; Afficher comme imposte: no; Châssis vitré (gs_SidelightTransomRelation): Sous imposte; Châssis vitré (gs_SidelightTransomRelation_m): 1; Tierce vitrée 1: no; Imposte: no; Tolérances uniformes: yes; Taille nominale: 0; Taille trou comme taille nominale: yes; Taille ébrasure comme nominale: no; Taille unité comme nominale: no; Taille sortie comme nominale: no; Taille battant comme nominale: no; Transmettre taille nominale actuelle à sélection: no; Afficher points chaud éditables: yes; Afficher ébrasure sur symbole: 1; Affichage symbolique de l'ouverture: no; Niveau de détail 3D: 2; Direction ouverture tiere vitrée (gs_opening_dir_sl): Opposé à battant; Direction ouverture tiere vitrée (gs_opening_dir_sl_m): 2; Cadre porte (gs_pocket_door_frame): yes; Epaisseur cadre=Epaisseur mur: no; Epaisseur cadre uniforme: yes; Battant centré: yes; Largeur cadre uniforme: no; Style cadre changé automatiquement: no; Nombre de battants: 4; Nombre de battants - côté 2: 3; Style panneau de porte: 46; Position grille (gs_grill_pos): Les deux; Position grille (gs_grill_pos_m): 3; Nbre panneaux vert. côté 2: 4; Nbre panneaux hor. côté 2: 3; Nbre panneaux vert. côté 1: 4; Nbre panneaux hor. côté 1: 3; Afficher comme panneau vitre sur symbole: no; Afficher symbole porte chinoise: no; Afficher symbole comme panneau étanche: no; Poignées uniformes: no; Afficher poignée sur symbole: no; Plaque bas de porte extérieure (bKickBoardOut): no; Plaque bas de porte intérieure (bKickBoardIn): no; Châssis uniformes: no; Type d'ouverture (gs_optype_m_05): 3; Type d'ouverture (gs_optype_m_02): 1; Type d'ouverture (gs_optype_m_06): 1; Type d'ouverture (gs_optype_m_10): 1; Type châssis (MullionStyle_00): Pas de grille; Type châssis (iMullionStyle_00): 1; Type châssis (iMullionStyle_05): 1; Type châssis (iMullionStyle_09): 1; Type châssis (iMullionStyle_02): 1; Type châssis (iMullionStyle_06): 1; Type châssis (iMullionStyle_10): 1; Edition point chaud de grille: yes; Position grille (MullionPosition): Les deux; Position grille (iMullionPosition): 3; Nbre panneaux V châssis princ. côté 1: 4; Nbre panneaux H châssis princ. côté 1: 2; Nbre panneaux V 2 châssis princ. côté 1: 4; Nbre panneaux H 2 châssis princ. côté 1: 2; Nbre panneaux V châssis princ. côté 2: 4; Nbre panneaux H châssis princ. côté 2: 2; Nbre panneaux V 2 châssis princ. côté 2: 4; Nbre panneaux H 2 châssis princ. côté 2: 2; Nbre panneaux V imposte centre: 2; Nbre panneaux H imposte centre: 2; Nbre panneaux V 2 imposte centre: 2; Nbre panneaux H 2 imposte centre: 2; Nbre panneaux vert. imposte côté 1: 2; Nbre panneaux hor. imposte côté 1: 2; Nbre panneaux V 2 imposte côté 1: 2; Nbre panneaux H 2 imposte côté 1: 2; Nbre panneaux vert. imposte côté 2: 2; Nbre panneaux hor. imposte côté 2: 2; Nbre panneaux V 2 imposte côté 2: 2; Nbre panneaux H 2 imposte côté 2: 2; Chambranle extérieur (gs_trim_outside): no; Type chambr. ext. (gs_trimtype_out): Simple; Type chambr. ext. (gs_trimtype_out_int): 1; Type tête chambr. ext.: 1; Chapiteau architrave: yes; Type chapiteau architrave: 1; Couvre surface mur ext.: yes; Largeurs uniformes de chambranle (gs_trim_outside_uniform): yes; Chambranle intérieur.: no; Type chambr. intérieur (gs_trimtype_in): Simple; Type chambr. intérieur (gs_trimtype_in_int): 1; Couvre surface mur int.: yes; Largeurs uniformes de chambranle (gs_trim_inside_uniform): yes; Seuil (bThreshold): no; Type seuil: 2; Angle seuil: 3.1996 deg; Seuil changé automatiquement: no; Appui - porte: no; Appui - Tierce vitrée côté 1: no; Appui - Tierce vitrée: no; Dépassement appui: no; Type d'appui/seuil: 1; Angle appui: 3 deg; Appui courbe dans murs courbes: yes; Isolation sous appui: yes; Utiliser couche isolation mur: no; Niveau détail 3D seuil brique: 1; Style appui changé automatiquement: no; Tablette - côté tierce vitrée 1: no; Tablette - Tierce vitrée: no; Tablette - porte: no; Angle tablette: 0 deg; Tabl. courbe dans murs courbes: yes; Tableau dans murs polygonaux: 1; Aération naturelle: no; Type d'aération naturelle: 2; Volet: no; Type volet: 1; Types volet activés: 126; Nombre de panneaux: 2; Nombre de panneaux 2: 1; Position panneau (gs_shutter_panelPos): Symétrique; Position panneau (gs_shutter_iPanelPos): 1; Hauteur volet automatique: yes; Cadre supplémentaire: no; Type de couverture (gs_slidingShutter_cover): Profil en Z; Type de couverture (gs_slidingShutter_iCover): 1; Direction articulation (gs_foldingShutter_stacking): Intérieur; Direction articulation (gs_foldingShutter_iStacking): 1; Ouvert en 3D: yes; Angle ouverture en 3D (gs_shutter_opAngle): 180 deg; Afficher symbole 2D: yes; Afficher lignes d'ouverture sur symbole: no; Type de panneau: (gs_shutPanel_type): Style 1; Type de panneau: (gs_shutPanel_iType): 1; Largeur cadre inf. différente: no; Largeur volets automatiques: yes; Angle persienne: 30 deg; Nombre trous horizontaux: 5; Nombre trous verticaux: 8; Placement volet roulant (gs_shutRoll_placement): Sur façade; Placement volet roulant (gs_shutRoll_iPlacement): 1; Type boîte (gs_shutRoll_boxType): Rectangulaire; Type boîte (gs_shutRoll_iBoxType): 1; Position rampe (gs_shutRoll_railPos): Sur revêtement; Position rampe (gs_shutRoll_iRailPos): 1; Afficher revêtement derrière parasol (gs_shutRoll_showCasingBehind): no; Isolation derrière cellule (gs_shutRoll_cutWallBehind): no; Inclure hauteur dans hauteur de trou de mur: no; Angle supérieur boîte: 10 deg; Taille boîte par défaut (gs_shutRoll_boxDefaultSize): Largeur ébrasure; Taille boîte par défaut (gs_shutRoll_iBoxDefaultSize): 1; Placement stores (gs_shutLam_placement): Fixé sur façade; Placement stores (gs_shutLam_iPlacement): 1; Isolation derrière cellule (gs_shutLam_cutWallBehind): no; Boîte ouverte: yes; Rampe (gs_shutLam_bRail): yes; Position rampe (gs_shutLam_railPos): Sur revêtement; Position rampe (gs_shutLam_iRailPos): 1; Afficher revêtement derrière parasol (gs_shutLam_showCasingBehind): no; Angle de rotation des lamelles (gs_shutLam_rotation): 45 deg; Angle de rotation des lamelles (gs_shutLam2_rotation): 45 deg; Linteau (bMasonryArch): no; Linteau (gs_masonry_arch_int): 2; Type linteau (gs_masonry_arch_structure): Stuc; Type linteau (gs_masonry_arch_structure_int): 1; Arche sur linteau: yes; Niche sous arche: yes; Angle inclinaison: 75 deg; Surface niche personnalisée: no; Type ébrasure (gs_reveal_type_new): Pas d'ébrasure - arête; Type ébrasure (gs_reveal_type_int): 1; Définir profondeur montant sur côté: 1; Profondeur montant uniforme: yes; Type ébrasure extérieure: Baie simple; Type ébrasure (gs_reveal_doubleOuterTypeInt): 0; Type ébrasure intérieure: Baie simple; Type ébrasure (gs_reveal_doubleInnerTypeInt): 0; Côté angle 2: 20 deg; Côté angle: 20 deg; Angle côté supérieur: 20 deg; Angle côté inférieur: 20 deg; Côté angle extérieur 2: 20 deg; Côté angle extérieur: 20 deg; Angle extérieur côté sup.: 20 deg; Angle extérieur côté inf.: 20 deg; Rampe sous battants: no; Rampe (gs_door_rail_ext): Sans; Rampe (gs_door_rail_ext_m): 1; Utiliser composant finition mur: no; Tourner plâtre surface intérieure: 0; Tourner plâtre surface extérieure: 0; Peut être coté en 2D: no; Afficher en 3D: no; Type de fermeture (gs_closure_type): Pas de fermeture; Type de fermeture (gs_closure_type_int): 1; Tourner couche sur côté (gs_cavity_side): Les deux; Tourner couche sur côté (iCavityClosureSide): 1; Nbre de couches retournées: 1; Num. à partir de (gs_nTurnDir): Face extérieure; Num. à partir de (iCavityClosureTurnDir): 1; Placer fermeture sur côté 1: yes; Placer fermeture sur côté 2: yes; Placer fermeture en haut: no; Placer fermeture en bas: no; Placer fermeture sur couche: 1; Placer fermeture de côté (gs_cc_dutch_ClosureToSide): 1; Ecart à couche externe: yes; Tourner couche sur fermeture: no; Insérer bande d'isolation: yes; Afficher bande d'isolation: yes; Stylo contour (gs_penJoint): Ouvertures - Coupé non structurel; Type de ligne de contour (gs_ltJoint): 1; Motif de hachure (gs_fillJoint): Isolation polystyrène; Stylo hachure (gs_penJointFg): Général - Dessin 0.12; Stylo fond de hachure (gs_penJointBg): Eléments 2D - Dessin; Surface personnalisée: no; Stylo contour (gs_penPlug): Ouvertures - Coupé non structurel; Type de ligne de contour (gs_ltPlug): 1; Motif de hachure (gs_fillPlug): Isolation polystyrène; Stylo hachure (gs_penPlugFg): Général - Dessin 0.12; Stylo fond de hachure (gs_penPlugBg): Eléments 2D - Dessin; Côté montant édité: 1; Côté mur édité: 1; Numéro couche éditée: 1; Tourner couche: no; Considérer couches comme plâtre: no; Tourner épaiseur: 1; Orientation hachure: 1; Ligne de séparation tournant: no; Stylo ligne de séparation: Général - Dessin 0.12; Dernier côté sélectionné: no; Méthode fermeture changée auto.: no; Connexion sur côté 1: no; Connexion sur côté 2: no; Connexion en haut: no; Type d'ouverture (gs_leaf_optype): Battant; Type d'ouverture (gs_leaf_optype_m): 5; Ouverture panneau de fin côté 1: no; Ouverture panneau de fin côté 2: no; Angle ouverture en 2D: 90 deg; Angle ouverture en 3D (gs_open_3D): 0 deg; Angle ouv. battant fin 3D côté 2: 0 deg; Angle ouv. châssis principal côté 1 (openingAngle_05): 0 deg; Angle ouv. châssis principal côté 1 (openingAngle2_05): 0 deg; Angle ouv. châssis principal côté 2 (openingAngle_09): 0 deg; Angle ouv. châssis principal côté 2 (openingAngle2_09): 0 deg; Angle ouv. imposte centre (openingAngle_02): 0 deg; Angle ouv. imposte centre (openingAngle2_02): 0 deg; Angle ouverture imposte côté 1 (openingAngle_06): 0 deg; Angle ouverture imposte côté 1 (openingAngle2_06): 0 deg; Angle ouverture imposte côté 2 (openingAngle_10): 0 deg; Angle ouverture imposte côté 2 (openingAngle2_10): 0 deg; Suppl. Opt. vue pour aff. symb. 2D: no; Type ligne ouverture: 1; Forme ligne ouverture (or_SwingType): Courbé; Forme ligne ouverture (or_iSwingType): 1; Forme ligne ouverture (or_SlidingType): Sans; Forme ligne ouverture (or_iSlidingType): 0; Orient. ligne (or_oplineStyle): Poignée; Orient. ligne (or_iOplineStyle): 1; Suppl. Opt. vue mod. pr proj. 3D tierce/imposte: no; Afficher ligne d'ouverture (or_bWinOplines3d): yes; Type ligne côté ouverture (or_winOpLineType3dIn): Ligne continue; Type ligne côté ouverture (or_iWinOpLineType3dIn): 0; Type ligne côté opposé (or_winOpLineType3dOut): Ligne continue; Type ligne côté opposé (or_iWinOpLineType3dOut): 0; Orient. ligne (or_winOplineStyle): Poignée; Orient. ligne (or_iWinOplineStyle): 1; Stylo ligne ouverture 2D/3D (or_winOpLinePen): Ouvertures - Général; Stylo ligne ouverture 2D/3D (or_iWinOpLinePen): 3; Stylo du symbole: Ouvertures - Général; Stylo ligne coupée chambranle des deux côtés: Ouvertures - Général; Stylo contour battant: Ouvertures - Général; Type ligne contour int. mur: 1; Type ligne contour ext. mur: 1; Ligne contour de tierce vitrée ds mur (gs_wcont_line_sl): Des deux côtés; Ligne contour de tierce vitrée ds mur (iWallContourLineSl): 4; Type ligne contour int. tierce vitrée ds mur: 1; Type ligne contour ext. tierce vitrée ds mur: 1; Stylo ligne contour de mur: Ouvertures - Général; Utiliser hachures: yes; Motif de hachure cadre: Sans Trame; Stylo hachure cadre: Ouvertures - Hachures coupées; Stylo hachure symbole étanche: Général - Dessin 0.12; Stylo fond hachure symbole étanche: Général - Dessin 0.12; Motif hachure symbole plan de porte: Sans Trame; Stylo hachure symbole plan de tierce vitrée: Fond - Couleur 1; Stylo fond hachure symbole plan de tierce vitrée: Fond - Couleur 1; Type ligne seuil et appui: 1; Stylo contour de seuil en coupe: Ouvertures - Général; Stylo hachure seuil en Coupe: Fond - Couleur 1; Stylo fond hachure coupe Seuil: Fond - Couleur 1; Stylo appui 3D et non coupé: Général - Dessin 0.12; Stylo contour appui en Coupe: Général - Dessin 0.12; Motif hachure appui en Coupe: Lame d'air; Stylo hachure d'appui en Coupe: Fond - Couleur 1; Stylo fond hachure appui Coupe: Fond - Couleur 1; Stylo contour isolation coupe: Général - Dessin 0.12; Motif hachure isolation Coupe: Isolation polystyrène; Stylo hachure isolation Coupe: Général - Dessin 0.12; Stylo fond hachure isol. Coupe: Fond - Couleur 1; Stylo latte 3D et non coupé: Général - Dessin 0.12; Stylo contour latte en Coupe: Général - Dessin 0.12; Motif hachure tablette en Coupe: Lame d'air; Stylo hachure tablette en Coupe: Fond - Couleur 1; Stylo fond hach. tablette Coupe: Fond - Couleur 1; Type hachure chambr. intérieur: Lame d'air; Stylo hachure chambr. int.: Fond - Couleur 1; Stylo fond hachure chambr. int.: Fond - Couleur 1; Type hachure chambr. ext.: Lame d'air; Stylo hachure chambr. ext.: Fond - Couleur 1; Stylo fond hachure chambr. ext.: Fond - Couleur 1; Stylo hachure en coupe d'arche: Fond - Couleur 1; Stylo fond hachure appui arche Coupe: Fond - Couleur 1; Motif de hachure de Coupe de Profil de ventilation: Lame d'air; Stylo de hachure de Coupe de Profil de ventilation: Fond - Couleur 1; Stylo de fond de hachure de Coupe de Profil de ventilation: Fond - Couleur 1; Type de ligne symbole volet: 1; Stylo ligne coupée volet: Général - Dessin 0.12; Stylo ligne non coupée 3D/Coupe: Général - Dessin 0.12; Stylo hachure coupée volet: Général - Dessin 0.12; Stylo fond hachure coupé volet: Fond de fenêtre; Motif de hachure d'isolation de volet: Dallage; Stylo de hachure d'isolation de volet: Général - Dessin 0.12; Stylo de fond d'isolation de volet: Fond de fenêtre; Type hachure non coupée: Sans Trame; Valeurs côté ouverture (gs_opside_list): Personnalisé; Valeurs côté ouverture (gs_opside_list_m): 0; Jonction éléments cadree (gs_SashText_typ): Assemblage bout à bout; Jonction éléments cadree (gs_SashText_typ_num): 2; Stylo cadre: Ouvertures - Général; Stylo panneaux: Ouvertures - Général; Stylo linteau: Murs - Général; Résolution de courbe: 32; Ombre: yes; Surfaces de porte uniformes: no; Verrou (gs_lock_mat): _Peinture - Anthracite; Rampe (gs_rail_mat): _Métal - Fer; Plaque bas de porte: _Métal BAVETTE; Surfaces uniformes de chambranle: yes; Profil Ventilation: _Métal BAVETTE; Boîte volet roulant: _Métal - Acier inoxydable; Lames volet roulant: _Peinture - Blanc brillant; Rail volet roulant: _Peinture - Blanc brillant; Boîte store vénitien: _Métal - Acier inoxydable; Segments store vénitien: _Peinture - Blanc brillant; Rail volet coulissant: _Métal - Acier inoxydable; Métal seuil: _Métal BAVETTE; Appui (gs_sill_mat): _Coupe3D_; Mortier appui briques: _Enduit - Blanc nature; Poignée: _Métal - Acier inoxydable; Accessoires poignée: _Métal - Fer; Plaque bas de porte extérieure (matKickBoardOut): _Métal - Acier inoxydable; Plaque bas de porte intérieure (matKickBoardIn): _Métal - Acier inoxydable; Brique linteau: _Coupe3D_; Mortier linteau: _Enduit - Blanc nature; Clef de voûte linteau: _Pierre - Grès 01; Niche: _Mur int Hall; Porte appartient à Zone vers laquelle elle donne: yes; Coût: 0; Emplacement comme: Personnalisé; Surface vitrée totale (gs_list_glassarea_tmp): 0; Supplanter surface vitrée: no; Périmètre total vitrage: 0; Performance air libre (mm2/l/m): 0; Type de groupe (FM_Type): Autres; Type de groupe (iFMType): 25; Poids de l'objet: 0; Unité poids de l'objet: kg; Définition orientation porte: 0; Fermeture porte: no; Type panneau de vision: Nbre panneaux vision; Dispositif main. ouvert.: no; Opération IFC (ifc_optypestr): Porte double battant simple; Opération IFC (ifc_optype): 2
AC_Pset_RenovationAndPhasing - Renovation Status: Existing
Name | In | Classification | ID de l'élément = Lien et ID d'élément | Calque | Matériau de construction / Composite / Profil / Hachure = Type Hachure = Index hachure latérale ouverture | Nom d'étage d'implantation | Numéro d'étage d'implantation | ID de Parent | Surfaces (Toutes) | Position | Fonction structurelle | Dimensions ébrasure = Dimensions trou mur = Dimensions unité = Taille L x H nominale | Dimensions sortie | Dimensions battant | Taille L x H x E nominale | Structure de Mur | Orientation = Orientation porte | Classification ARCHICAD - 21 | Type de direction de mur = Type ligne côté ouverture (or_iOpLineType3dIn) = Type ligne côté opposé (or_iOpLineType3dOut) | Direction d'ouverture | Valeur incrustation allège | Tierce vitrée 2 | Niveau de détail 2D | Style de cadre (gs_frame_style) | Style de cadre (gs_frame_style_m) | Configuration battants (gs_LeavesConfig) | Configuration battants (gs_iLeavesConfig) = Type ébrasure inférieure (gs_reveal_type_bottom_int) | Editer poignée | Poignée d'ouverture (gs_handle_type) | Poignée d'ouverture (gs_handle_type_m) | Poignée d'ouverture (gs_handle_type2_m) | Type d'ouverture (gs_optype_m_09) | Type ébrasure inférieure (gs_reveal_type_bottom) | Tourner automatiquement plâtre surface intérieure = Tourner automatiquement plâtre surface extérieure | Surface = Battant 2 = Battant 3 = Grille extérieure (gs_grill_mat) = Grille intérieure (gs_grill_mat2) = Grille extérieure (gs_leaf_grill_mat) = Grille intérieure (gs_leaf_grill_mat2) = Panneau solide extérieur = Panneau solide intérieur = Persienne extérieure = Persienne intérieure = Chambranle intérieur = Chambranle extérieur (gs_trim_out_mat) = Panneau volet = Cadre panneau volet = Seuil (gs_treshold_mat) = Tablette (gs_board_mat) | Angle ouverture 2D côté 2 (deg) | Type ligne va-et-vient = Type ligne contour int. mur masqué = Type ligne contour ext. mur masqué = Type ligne contour int. tierce vitrée ds mur masqué = Type ligne contour ext. tierce vitrée ds mur masqué | Suppl. Opt. vue pour proj. porte 3D | Afficher ligne d'ouverture (or_bOplines3d) | Type ligne côté ouverture (or_opLineType3dIn) = Type ligne côté opposé (or_opLineType3dOut) | Stylo ligne ouverture 2D/3D (or_opLinePen) | Stylo ligne ouverture 2D/3D (or_iOpLinePen) | Stylo contour cadre | Ligne de contour de mur (gs_wcont_line) | Ligne de contour de mur (iWallContourLine) | Stylo fond de hachure cadre = Stylo fond de hachure battant = Stylo fond de hachure non coupé | Motif de hachure battant | Stylo hachure de battant = Stylo hachure non coupée | Motif hachure symbole étanche | Stylo hachure symbole plan de porte | Stylo fond hachure symbole plan de porte | Motif hachure symbole plan de tierce vitrée = Motif hachure de seuil en Coupe = Motif de hachure arche coupe = Type hachure coupée volet | Stylo vitrage = Stylo vitrage battant | Cadre extérieur = Cadre intérieur | Battant extérieur = Battant intérieur | Vitrage (gs_glass_mat) = Vitrage (gs_leaf_glass_mat) | Surface vitrée totale (gs_list_glassarea) | Largeurs de battant de porte
Porte hall | RDC | Element de construction non défini (Classification Archicad); Fenêtre (Classification ARCHICAD) | Porte hall | 10_M x baseGO__ | Menuis1 | RDC | 0 | M ext hall-Est | _Men ext_RAL9007; _Verre clair (rapide) | Non défini | Non défini | 220×240 | 210×235 | 212×236 | 220×240×36 | _M ext 18 +18 | G | Fenêtre | 1 | 0 | 3 | yes | 2 | Simple feuillure | 3 | Battants uniformes | 1 | 1 | Sans | 0 | 13 | 1 | Uniforme | no | _Men ext_RAL9007 | 90 | 4 | no | yes | Tirets | Général - Dessin 0.12 | 1 | Ouvertures - Général | Sans | 1 | Ouvertures - fonds de hachure | Sans Trame | Ouvertures - Hachures coupées | Hachure solide | Ouvertures - Non coupé/Au-dessus tête | Ouvertures - fonds de hachure | Sans Trame | Ouvertures - Général | _Men ext_RAL9007 | _Men ext_RAL9007 | _Verre clair (rapide) | 3.0272 | 106 / 106 | ArchiCADProperties - Nom de zone liée: Hall d'entrée; De Zone: Hall d'entrée; AC_Pset_Porte_double_21 - Type d'opération tierce vitrée côté 2: Vitrage fixe; Type châssis tierce vitrée côté 2: Pas de grille
P-Ext-BlocSanit | RDC | Element de construction non défini (Classification Archicad); Porte (Classification ARCHICAD) | P-Ext-BlocSanit | 10_M x baseGO__ | Bois - menuiserie | RDC | 0 | M-Ext_BlocSanit | _Classe 2-RAL5018; _Transp - Verre | Non défini | Non défini | 140×230 | 130×225 | 130×225 | 140×230×30 | _M ext 18 +12 | D | Porte | 0 | 1 | 2 | no | 1 | Parallélépipédiques | 1 | Asymétrique | 2 | 1 | Poignée 6 | 13 | 0 | 3 | Baie simple | yes | _Bois - Pin granuleux horizontal | 0 | 37 | no | yes | Ligne continue | Ouvertures - Général | 3 | Ouvertures - Coupé structurel | Intérieur | 2 | Fond - Couleur 1 | Lame d'air | Fond - Couleur 1 | Lambourdage | Fond - Couleur 1 | Transparent | Isolation - Panneau rigide | Ouvertures - Coupé non structurel | _Classe 2-RAL5018 | _Classe 2-RAL5018 | _Transp - Verre | 0.095 | 0.90 / 0.40
P-Ext-BlocSanit | RDC | Element de construction non défini (Classification Archicad); Porte (Classification ARCHICAD) | P-Ext-BlocSanit | 10_M x baseGO__ | Bois - menuiserie | RDC | 0 | M-Ext_BlocSanit | _Classe 1-RAL2000; _Transp - Verre | Non défini | Non défini | 140×230 | 130×225 | 130×225 | 140×230×30 | _M ext 18 +12 | G | Porte | 0 | 1 | 2 | no | 1 | Parallélépipédiques | 1 | Asymétrique | 2 | 1 | Poignée 6 | 13 | 0 | 3 | Baie simple | yes | _Bois - Pin granuleux horizontal | 0 | 37 | no | yes | Ligne continue | Ouvertures - Général | 3 | Ouvertures - Coupé structurel | Intérieur | 2 | Fond - Couleur 1 | Lame d'air | Fond - Couleur 1 | Lambourdage | Fond - Couleur 1 | Transparent | Isolation - Panneau rigide | Ouvertures - Coupé non structurel | _Classe 1-RAL2000 | _Classe 1-RAL2000 | _Transp - Verre | 0.095 | 0.90 / 0.40
35 (DAS) | R+1 | Element de construction non défini (Classification Archicad); Porte (Classification ARCHICAD) | 35 (DAS) | 20_Cloison________ | Sans Trame | R+1 | 1 | Clois recoup | _Serpentin-noir; _Verre clair (rapide); _Huisserie-int | Intérieur | Élément non porteur | 196×210 | 176×200 | 180×202 | 196×210×10 | _Cloison 10cm | G | Porte | 1 | 1 | 2 | no | 2 | Simple feuillure | 3 | Asymétrique | 2 | 2 | Poignée 6 | 13 | 0 | 3 | Baie simple | yes | _Men ext_RAL9007 | 90 | 4 | yes | no | Tirets | reseau chaleur | 97 | Ouvertures - Général | Sans | 1 | Ouvertures - fonds de hachure | Sans Trame | Ouvertures - Hachures coupées | Hachure solide | Ouvertures - Non coupé/Au-dessus tête | Ouvertures - fonds de hachure | Sans Trame | Ouvertures - Coupé non structurel | _Huisserie-int | _Serpentin-noir | _Verre clair (rapide) | 0.552 | 0.90 / 0.90 | ArchiCADProperties - Nom de zone liée: Circulation 3; De Zone: Circulation 2; À Zone: Circulation 3; Résistance au feu: CF 1/2H; Description: couloir R+1 (DAS); Pset_FireRatingProperties - FireResistanceRating: CF 1/2H; AC_Pset_Porte_double_21 - Degré de protection au feu: CF 1/2H

# IfcBuildingElementProxy: Porte double asymétrique 21 (10)
In: RDC
Classification: Element de construction non défini (Classification Archicad); Fenêtre (Classification ARCHICAD); Material: Matériau de construction IFC
Pset_FireRatingProperties - FireResistanceRating: CF 1/2H
ArchiCADProperties - ID de l'élément: Porte classe; Lien et ID d'élément: Porte classe; Calque: 10_M x baseGO__; Nom Élément de Bibliothèque: Porte double asymétrique 21; Matériau de construction / Composite / Profil / Hachure: Sans Trame; Type Hachure: Sans Trame; Verrouillé: no; Nom d'étage d'implantation: RDC; Numéro d'étage d'implantation: 0; Type d'élément: Porte; ID de Parent: M ext-Est; Position: Non défini; État de rénovation: Existant; Affichage sur filtre de rénovation: Tous les filtres appropriés; Fonction structurelle: Non défini; Dimensions ébrasure: 150×250; Dimensions trou mur: 150×250; Dimensions unité: 150×250; Dimensions sortie: 144×247; Dimensions battant: 144×247; Taille L x H nominale: 150×250; Taille L x H x E nominale: 150×250×36; Structure de Mur: _M ext 18 +18 gris; Nom élément de bibliothèque d'ouverture: Porte double asymétrique 21; Index hachure latérale ouverture: Sans Trame; Classification ARCHICAD - 21: Fenêtre
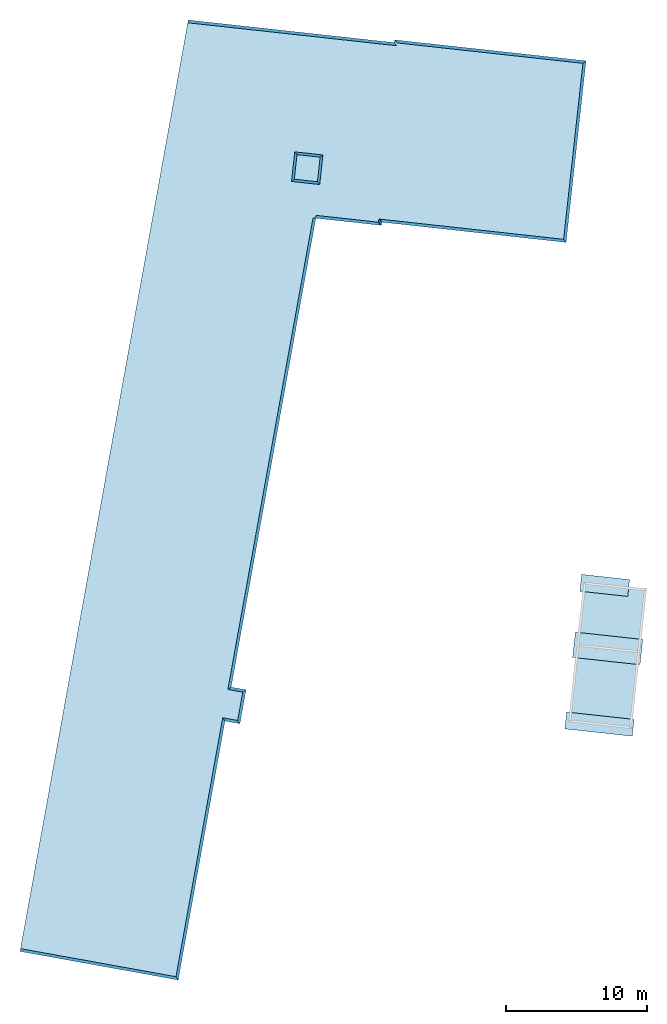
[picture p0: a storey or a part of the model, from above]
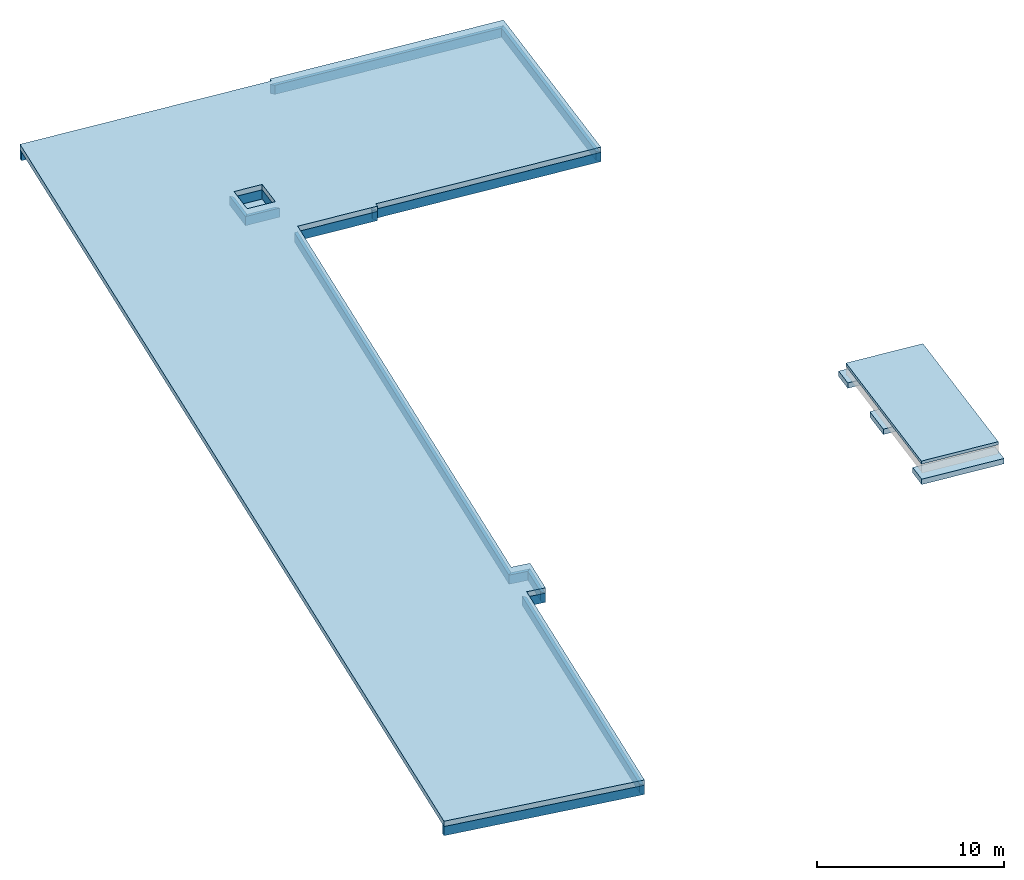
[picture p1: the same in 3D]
Properties of the parts of a building model (IFC2X3), part 7 of 10

# IfcBuildingElementProxy: Porte double avec tierce vitrée 21, Porte cour
AC_Pset_Porte_double_avec_tierce_vitrée_21 - Contours Mur (0-Sans,1-Tout,2-Côté,3-Longueur): 0; Point ch.0-Non,1-2D,2-3D,3-Tous: 3; Afficher points chauds 2D en 3D: yes; Option affichage en plan: 3; Angle de position baie: 0 deg; Trou reprend surface latérale de mur: no; Division de surface du trou courbe dans murs courbes: no; Type de mur: 1; Type de direction de mur: 1; Position ancre ébrasuer: 1; Direction d'ouverture: 0; Basculer: no; Valeur incrustation allège: 3; Démolition / Nouvelle constr.: 1; Nouveau motif de hachure de mur: Parpaing; Nouveau stylo de hachure de mur: Général - Dessin 0.12; Nouveau stylo fond hachure mur: Fond - Couleur 1; Afficher nouv. constr. sur mur: no; Type de ligne démolition: 1; Aff. param. Démolition/Nouveau: no; Afficher comme imposte: no; Tolérances uniformes: yes; Taille nominale: 0; Taille trou comme taille nominale: yes; Taille ébrasure comme nominale: no; Taille unité comme nominale: no; Taille sortie comme nominale: no; Taille battant comme nominale: no; Transmettre taille nominale actuelle à sélection: no; Afficher points chaud éditables: yes; Niveau de détail 2D: 2; Afficher ébrasure sur symbole: 1; Affichage symbolique de l'ouverture: no; Niveau de détail 3D: 2; Direction ouverture tiere vitrée (gs_opening_dir_sl): Opposé à battant; Direction ouverture tiere vitrée (gs_opening_dir_sl_m): 2; Cadre porte (gs_pocket_door_frame): yes; Style de cadre (gs_frame_style): Simple feuillure; Style de cadre (gs_frame_style_m): 3; Epaisseur cadre=Epaisseur mur: no; Epaisseur cadre uniforme: yes; Battant centré: yes; Largeur cadre uniforme: no; Style cadre changé automatiquement: no; Nombre de battants: 4; Nombre de battants - côté 2: 3; Style panneau de porte: 46; Configuration battants (gs_LeavesConfig): Battants uniformes; Configuration battants (gs_iLeavesConfig): 1; Position grille (gs_grill_pos): Les deux; Position grille (gs_grill_pos_m): 3; Nbre panneaux vert. côté 2: 4; Nbre panneaux hor. côté 2: 3; Nbre panneaux vert. côté 1: 4; Nbre panneaux hor. côté 1: 3; Afficher comme panneau vitre sur symbole: no; Afficher symbole porte chinoise: no; Afficher symbole comme panneau étanche: no; Editer poignée: 2; Poignées uniformes: no; Poignée d'ouverture (gs_handle_type): Poignée 6; Poignée d'ouverture (gs_handle_type_m): 13; Afficher poignée sur symbole: no; Poignée d'ouverture (gs_handle_type2_m): 0; Plaque bas de porte extérieure (bKickBoardOut): no; Plaque bas de porte intérieure (bKickBoardIn): no; Châssis vitré (gs_SidelightTransomRelation): Sous imposte; Châssis vitré (gs_SidelightTransomRelation_m): 1; Tierce vitrée 1: no; Tierce vitrée 2: yes; Imposte: no; Division horizontale tierce vitrée: no; Châssis uniformes: no; Type d'ouverture (gs_optype_m_05): 3; Type ouverture panneau adj.: Vitrage fixe; Type d'ouverture (gs_optype_m_09): 1; Type ouverture tierce vitrée inf.: Vitrage fixe; Type d'ouverture (gs_optype_m_11): 1; Type d'ouverture (gs_optype_m_02): 1; Type d'ouverture (gs_optype_m_06): 1; Type d'ouverture (gs_optype_m_10): 1; Type châssis (MullionStyle_00): Pas de grille; Type châssis (iMullionStyle_00): 1; Type châssis (iMullionStyle_05): 1; Type châssis tierce vitrée: Pas de grille; Type châssis (iMullionStyle_09): 1; Type châssis tierce vitrée inf.: Panneau solide; Type châssis (iMullionStyle_11): 15; Type châssis (iMullionStyle_02): 1; Type châssis (iMullionStyle_06): 1; Type châssis (iMullionStyle_10): 1; Edition point chaud de grille: yes; Position grille (MullionPosition): Les deux; Position grille (iMullionPosition): 3; Nbre panneaux V tierce vitrée (hgn_05): 4; Nbre panneaux H tierce vitrée (vgn_05): 2; Nbre panneaux V 2 tierce vitrée (hgn2_05): 4; Nbre panneaux H 2 tierce vitrée (vgn2_05): 2; Nbre panneaux V tierce vitrée (hgn_09): 4; Nbre panneaux H tierce vitrée (vgn_09): 2; Nbre panneaux V 2 tierce vitrée (hgn2_09): 4; Nbre panneaux H 2 tierce vitrée (vgn2_09): 2; Nbre panneaux V tierce vitrée inf.: 4; Nbre panneaux hor. tierce vitrée inf.: 2; Nbre panneaux V 2 tierce vitrée inf.: 4; Nbre panneaux H 2 tierce vitrée inf.: 2; Nbre panneaux V imposte centre: 2; Nbre panneaux H imposte centre: 2; Nbre panneaux V 2 imposte centre: 2; Nbre panneaux H 2 imposte centre: 2; Nbre panneaux V imposte côté: 2; Nbre panneaux H imposte côté: 2; Nbre panneaux vert. 2 imposte côté: 2; Nbre panneaux hor. 2 imposte côté: 2; Nbre panneaux vert. imposte côté 2: 2; Nbre panneaux hor. imposte côté 2: 2; Nbre panneaux V 2 imposte côté 2: 2; Nbre panneaux H 2 imposte côté 2: 2; Style persiennes (iLouverStyle): 1; Angle d'ouverture persiennes: 0 deg; Chambranle extérieur (gs_trim_outside): no; Type chambr. ext. (gs_trimtype_out): Simple; Type chambr. ext. (gs_trimtype_out_int): 1; Type tête chambr. ext.: 1; Chapiteau architrave: yes; Type chapiteau architrave: 1; Couvre surface mur ext.: yes; Largeurs uniformes de chambranle (gs_trim_outside_uniform): yes; Chambranle intérieur.: no; Type chambr. intérieur (gs_trimtype_in): Simple; Type chambr. intérieur (gs_trimtype_in_int): 1; Couvre surface mur int.: yes; Largeurs uniformes de chambranle (gs_trim_inside_uniform): yes; Seuil (bThreshold): no; Type seuil: 2; Angle seuil: 3.1996 deg; Seuil changé automatiquement: no; Appui - porte: no; Appui - Tierce vitrée côté 1: no; Appui - Tierce vitrée: no; Dépassement appui: no; Type d'appui/seuil: 1; Angle appui: 3 deg; Appui courbe dans murs courbes: yes; Isolation sous appui: yes; Utiliser couche isolation mur: no; Niveau détail 3D seuil brique: 1; Style appui changé automatiquement: no; Tablette - côté tierce vitrée 1: no; Tablette - Tierce vitrée: no; Tablette - porte: no; Angle tablette: 0 deg; Tabl. courbe dans murs courbes: yes; Tableau dans murs polygonaux: 1; Aération naturelle: no; Type d'aération naturelle: 2; Châssis vitré (isVentilationProfileInSash_09): yes; Tierce vitrée inf.: no; Volet: no; Type volet: 1; Types volet activés: 126; Nombre de panneaux: 2; Nombre de panneaux 2: 1; Position panneau (gs_shutter_panelPos): Symétrique; Position panneau (gs_shutter_iPanelPos): 1; Hauteur volet automatique: yes; Cadre supplémentaire: no; Type de couverture (gs_slidingShutter_cover): Profil en Z; Type de couverture (gs_slidingShutter_iCover): 1; Direction articulation (gs_foldingShutter_stacking): Intérieur; Direction articulation (gs_foldingShutter_iStacking): 1; Ouvert en 3D: yes; Angle ouverture en 3D (gs_shutter_opAngle): 180 deg; Afficher symbole 2D: yes; Afficher lignes d'ouverture sur symbole: no; Type de panneau: (gs_shutPanel_type): Style 1; Type de panneau: (gs_shutPanel_iType): 1; Largeur cadre inf. différente: no; Largeur volets automatiques: yes; Angle persienne: 30 deg; Nombre trous horizontaux: 5; Nombre trous verticaux: 8; Placement volet roulant (gs_shutRoll_placement): Sur façade; Placement volet roulant (gs_shutRoll_iPlacement): 1; Type boîte (gs_shutRoll_boxType): Rectangulaire; Type boîte (gs_shutRoll_iBoxType): 1; Position rampe (gs_shutRoll_railPos): Sur revêtement; Position rampe (gs_shutRoll_iRailPos): 1; Afficher revêtement derrière parasol (gs_shutRoll_showCasingBehind): no; Isolation derrière cellule (gs_shutRoll_cutWallBehind): no; Inclure hauteur dans hauteur de trou de mur: no; Angle supérieur boîte: 10 deg; Taille boîte par défaut (gs_shutRoll_boxDefaultSize): Largeur ébrasure; Taille boîte par défaut (gs_shutRoll_iBoxDefaultSize): 1; Placement stores (gs_shutLam_placement): Fixé sur façade; Placement stores (gs_shutLam_iPlacement): 1; Isolation derrière cellule (gs_shutLam_cutWallBehind): no; Boîte ouverte: yes; Rampe (gs_shutLam_bRail): yes; Position rampe (gs_shutLam_railPos): Sur revêtement; Position rampe (gs_shutLam_iRailPos): 1; Afficher revêtement derrière parasol (gs_shutLam_showCasingBehind): no; Angle de rotation des lamelles (gs_shutLam_rotation): 45 deg; Angle de rotation des lamelles (gs_shutLam2_rotation): 45 deg; Linteau (bMasonryArch): no; Linteau (gs_masonry_arch_int): 2; Type linteau (gs_masonry_arch_structure): Stuc; Type linteau (gs_masonry_arch_structure_int): 1; Arche sur linteau: yes; Niche sous arche: yes; Angle inclinaison: 75 deg; Surface niche personnalisée: no; Type ébrasure (gs_reveal_type_new): Pas d'ébrasure - arête; Type ébrasure (gs_reveal_type_int): 1; Type ébrasure inférieure (gs_reveal_type_bottom): Baie simple; Type ébrasure inférieure (gs_reveal_type_bottom_int): 2; Définir profondeur montant sur côté: 1; Profondeur montant uniforme: yes; Type ébrasure extérieure: Baie simple; Type ébrasure (gs_reveal_doubleOuterTypeInt): 0; Type ébrasure intérieure: Baie simple; Type ébrasure (gs_reveal_doubleInnerTypeInt): 0; Côté angle 2: 20 deg; Côté angle: 20 deg; Angle côté supérieur: 20 deg; Angle côté inférieur: 20 deg; Côté angle extérieur 2: 20 deg; Côté angle extérieur: 20 deg; Angle extérieur côté sup.: 20 deg; Angle extérieur côté inf.: 20 deg; Rampe sous battants: no; Rampe (gs_door_rail_ext): Sans; Rampe (gs_door_rail_ext_m): 1; Utiliser composant finition mur: no; Tourner automatiquement plâtre surface intérieure: yes; Tourner plâtre surface intérieure: 0; Tourner automatiquement plâtre surface extérieure: yes; Tourner plâtre surface extérieure: 0; Peut être coté en 2D: no; Afficher en 3D: no; Type de fermeture (gs_closure_type): Pas de fermeture; Type de fermeture (gs_closure_type_int): 1; Tourner couche sur côté (gs_cavity_side): Les deux; Tourner couche sur côté (iCavityClosureSide): 1; Nbre de couches retournées: 1; Num. à partir de (gs_nTurnDir): Face extérieure; Num. à partir de (iCavityClosureTurnDir): 1; Placer fermeture sur côté 1: yes; Placer fermeture sur côté 2: yes; Placer fermeture en haut: no; Placer fermeture en bas: no; Placer fermeture sur couche: 1; Placer fermeture de côté (gs_cc_dutch_ClosureToSide): 1; Ecart à couche externe: yes; Tourner couche sur fermeture: no; Insérer bande d'isolation: yes; Afficher bande d'isolation: yes; Stylo contour (gs_penJoint): Ouvertures - Coupé non structurel; Type de ligne de contour (gs_ltJoint): 1; Motif de hachure (gs_fillJoint): Isolation polystyrène; Stylo hachure (gs_penJointFg): Général - Dessin 0.12; Stylo fond de hachure (gs_penJointBg): Eléments 2D - Dessin; Surface personnalisée: no; Surface: _Men ext_RAL9007; Stylo contour (gs_penPlug): Ouvertures - Coupé non structurel; Type de ligne de contour (gs_ltPlug): 1; Motif de hachure (gs_fillPlug): Isolation polystyrène; Stylo hachure (gs_penPlugFg): Général - Dessin 0.12; Stylo fond de hachure (gs_penPlugBg): Eléments 2D - Dessin; Côté montant édité: 1; Côté mur édité: 1; Numéro couche éditée: 1; Tourner couche: no; Considérer couches comme plâtre: no; Tourner épaiseur: 1; Orientation hachure: 1; Ligne de séparation tournant: no; Stylo ligne de séparation: Général - Dessin 0.12; Dernier côté sélectionné: no; Méthode fermeture changée auto.: no; Connexion sur côté 1: no; Connexion sur côté 2: no; Connexion en haut: no; Type d'ouverture (gs_leaf_optype): Battant; Type d'ouverture (gs_leaf_optype_m): 5; Ouverture panneau de fin côté 1: no; Ouverture panneau de fin côté 2: no; Angle ouverture en 2D: 90 deg; Angle ouverture 2D côté 2: 90 deg; Angle ouverture en 2D tierce vitrée 1: 0 deg; Angle ouverture en 2D tierce vitrée 2: 0 deg; Angle ouverture en 3D (gs_open_3D): 0 deg; Angle ouv. battant fin 3D côté 2: 0 deg; Angle ouv. tierce vitrée (openingAngle_05): 0 deg; Angle ouv. tierce vitrée (openingAngle2_05): 0 deg; Angle ouv. tierce vitrée (openingAngle_09): 0 deg; Angle ouv. tierce vitrée (openingAngle2_09): 0 deg; Angle ouv. tierce vitrée inf. (openingAngle_11): 0 deg; Angle ouv. tierce vitrée inf. (openingAngle2_11): 0 deg; Angle ouv. imposte centre (openingAngle_02): 0 deg; Angle ouv. imposte centre (openingAngle2_02): 0 deg; Angle ouverture imposte côté (openingAngle_06): 0 deg; Angle ouverture imposte côté (openingAngle2_06): 0 deg; Angle ouverture imposte côté 2 (openingAngle_10): 0 deg; Angle ouverture imposte côté 2 (openingAngle2_10): 0 deg; Type ligne va-et-vient: 4; Suppl. Opt. vue pour aff. symb. 2D: no; Type ligne ouverture (or_swingLineType): 1; Forme ligne ouverture (or_SwingType): Courbé; Forme ligne ouverture (or_iSwingType): 1; Forme ligne ouverture (or_SlidingType): Sans; Forme ligne ouverture (or_iSlidingType): 0; Suppl. Opt. vue pour proj. porte 3D: no; Afficher ligne d'ouverture (or_bOplines3d): yes; Type ligne côté ouverture (or_opLineType3dIn): Tirets; Type ligne côté ouverture (or_iOpLineType3dIn): 1; Type ligne côté opposé (or_opLineType3dOut): Tirets; Type ligne côté opposé (or_iOpLineType3dOut): 1; Orient. ligne (or_oplineStyle): Poignée; Orient. ligne (or_iOplineStyle): 1; Stylo ligne ouverture 2D/3D (or_opLinePen): Général - Dessin 0.12; Stylo ligne ouverture 2D/3D (or_iOpLinePen): 1; Suppl. Opt. vue pour aff. symb. 2D de tierce vitrée: no; Type ligne ouverture (or_winSwingLineType): 1; Forme ligne ouverture (or_winSwingType): Courbé; Forme ligne ouverture (or_iWinSwingType): 1; Suppl. Opt. vue mod. pr proj. 3D tierce/imposte: no; Afficher ligne d'ouverture (or_bWinOplines3d): yes; Type ligne côté ouverture (or_winOpLineType3dIn): Ligne continue; Type ligne côté ouverture (or_iWinOpLineType3dIn): 0; Type ligne côté opposé (or_winOpLineType3dOut): Ligne continue; Type ligne côté opposé (or_iWinOpLineType3dOut): 0; Orient. ligne (or_winOplineStyle): Poignée; Orient. ligne (or_iWinOplineStyle): 1; Stylo ligne ouverture 2D/3D (or_winOpLinePen): gris foncé; Stylo ligne ouverture 2D/3D (or_iWinOpLinePen): 159; Stylo du symbole: Ouvertures - Général; Stylo contour cadre: Ouvertures - Général; Stylo ligne coupée chambranle des deux côtés: Ouvertures - Général; Stylo contour battant: Ouvertures - Général; Ligne contour de porte ds mur (gs_wcont_line): Sans; Ligne contour de porte ds mur (iWallContourLine): 1; Type ligne contour int. porte ds mur: 1; Type ligne contour ext. porte ds mur: 1; Type ligne contour int. porte ds mur masqué: 4; Type ligne contour ext. porte ds mur masqué: 4; Ligne contour de tierce vitrée ds mur (gs_wcont_line_sl): Des deux côtés; Ligne contour de tierce vitrée ds mur (iWallContourLineSl): 4; Type ligne contour int. tierce vitrée ds mur: 1; Type ligne contour ext. tierce vitrée ds mur: 1; Type ligne contour int. tierce vitrée ds mur masqué: 4; Type ligne contour ext. tierce vitrée ds mur masqué: 4; Stylo ligne contour de mur: Ouvertures - Général; Utiliser hachures: no; Motif de hachure cadre: Sans Trame; Stylo hachure cadre: Ouvertures - Hachures coupées; Stylo fond de hachure cadre: Ouvertures - fonds de hachure; Motif de hachure battant: Sans Trame; Stylo hachure de battant: Ouvertures - Hachures coupées; Stylo fond de hachure battant: Ouvertures - fonds de hachure; Motif hachure symbole étanche: Hachure solide; Stylo hachure symbole étanche: Général - Dessin 0.12; Stylo fond hachure symbole étanche: Général - Dessin 0.12; Motif hachure symbole plan de porte: Sans Trame; Stylo hachure symbole plan de porte: Ouvertures - Général; Stylo fond hachure symbole plan de porte: Ouvertures - fonds de hachure; Motif hachure symbole plan de tierce vitrée: Sans Trame; Stylo hachure symbole plan de tierce vitrée: Fond - Couleur 1; Stylo fond hachure symbole plan de tierce vitrée: Fond - Couleur 1; Type ligne seuil et appui: 1; Stylo contour de seuil en coupe: Ouvertures - Général; Motif hachure de seuil en Coupe: Sans Trame; Stylo hachure seuil en Coupe: Fond - Couleur 1; Stylo fond hachure coupe Seuil: Fond - Couleur 1; Stylo appui 3D et non coupé: Général - Dessin 0.12; Stylo contour appui en Coupe: Général - Dessin 0.12; Motif hachure appui en Coupe: Lame d'air; Stylo hachure d'appui en Coupe: Fond - Couleur 1; Stylo fond hachure appui Coupe: Fond - Couleur 1; Stylo contour isolation coupe: Général - Dessin 0.12; Motif hachure isolation Coupe: Isolation polystyrène; Stylo hachure isolation Coupe: Général - Dessin 0.12; Stylo fond hachure isol. Coupe: Fond - Couleur 1; Stylo latte 3D et non coupé: Général - Dessin 0.12; Stylo contour latte en Coupe: Général - Dessin 0.12; Motif hachure tablette en Coupe: Lame d'air; Stylo hachure tablette en Coupe: Fond - Couleur 1; Stylo fond hach. tablette Coupe: Fond - Couleur 1; Type hachure chambr. intérieur: Lame d'air; Stylo hachure chambr. int.: Fond - Couleur 1; Stylo fond hachure chambr. int.: Fond - Couleur 1; Type hachure chambr. ext.: Lame d'air; Stylo hachure chambr. ext.: Fond - Couleur 1; Stylo fond hachure chambr. ext.: Fond - Couleur 1; Motif de hachure arche coupe: Sans Trame; Stylo hachure en coupe d'arche: Fond - Couleur 1; Stylo fond hachure appui arche Coupe: Fond - Couleur 1; Motif de hachure de Coupe de Profil de ventilation: Lame d'air; Stylo de hachure de Coupe de Profil de ventilation: Fond - Couleur 1; Stylo de fond de hachure de Coupe de Profil de ventilation: Fond - Couleur 1; Type de ligne symbole volet: 1; Stylo ligne coupée volet: Général - Dessin 0.12; Stylo ligne non coupée 3D/Coupe: Général - Dessin 0.12; Type hachure coupée volet: Sans Trame; Stylo hachure coupée volet: Général - Dessin 0.12; Stylo fond hachure coupé volet: Fond de fenêtre; Motif de hachure d'isolation de volet: Dallage; Stylo de hachure d'isolation de volet: Général - Dessin 0.12; Stylo de fond d'isolation de volet: Fond de fenêtre; Type hachure non coupée: Sans Trame; Stylo hachure non coupée: Ouvertures - Hachures coupées; Stylo fond de hachure non coupé: Ouvertures - fonds de hachure; Valeurs côté ouverture (gs_opside_list): Personnalisé; Valeurs côté ouverture (gs_opside_list_m): 0; Jonction éléments cadree (gs_SashText_typ): Assemblage bout à bout; Jonction éléments cadree (gs_SashText_typ_num): 2; Stylo cadre: Ouvertures - Général; Stylo panneaux: Ouvertures - Général; Stylo vitrage: Ouvertures - Général; Stylo vitrage battant: Ouvertures - Général; Stylo linteau: Murs - Général; Résolution de courbe: 32; Ombre: yes; Surfaces de porte uniformes: no; Cadre extérieur: _Men ext_RAL9007; Cadre intérieur: _Men ext_RAL9007; Battant extérieur: _Men ext_RAL9007; Battant intérieur: _Men ext_RAL9007; Battant 2: _Men ext_RAL9007; Battant 3: _Men ext_RAL9007; Tierce vitrée extérieure: _Men ext_RAL9007; Tierce vitrée intérieure: _Men ext_RAL9007; Verrou (gs_lock_mat): _Peinture - Anthracite; Grille extérieure (gs_grill_mat): _Men ext_RAL9007; Grille intérieure (gs_grill_mat2): _Men ext_RAL9007; Grille extérieure (gs_leaf_grill_mat): _Men ext_RAL9007; Grille intérieure (gs_leaf_grill_mat2): _Men ext_RAL9007; Panneau solide extérieur: _Men ext_RAL9007; Panneau solide intérieur: _Men ext_RAL9007; Vitrage (gs_glass_mat): _Verre clair (rapide); Vitrage (gs_leaf_glass_mat): _Verre clair (rapide); Rampe (gs_rail_mat): _Métal - Fer; Persienne extérieure: _Men ext_RAL9007; Persienne intérieure: _Men ext_RAL9007; Persiennes: _Men ext_RAL9007; Plaque bas de porte: _Métal BAVETTE; Surfaces uniformes de chambranle: yes; Chambranle intérieur: _Men ext_RAL9007; Chambranle extérieur (gs_trim_out_mat): _Men ext_RAL9007; Profil Ventilation: _Métal BAVETTE; Panneau volet: _Men ext_RAL9007; Cadre panneau volet: _Men ext_RAL9007; Boîte volet roulant: _Métal - Acier inoxydable; Lames volet roulant: _Peinture - Blanc brillant; Rail volet roulant: _Peinture - Blanc brillant; Boîte store vénitien: _Métal - Acier inoxydable; Segments store vénitien: _Peinture - Blanc brillant; Rail volet coulissant: _Métal - Acier inoxydable; Seuil (gs_treshold_mat): _Men ext_RAL9007; Métal seuil: _Métal BAVETTE; Appui (gs_sill_mat): _Coupe3D_; Mortier appui briques: _Enduit - Blanc nature; Tablette (gs_board_mat): _Men ext_RAL9007; Poignée: _Métal - Acier inoxydable; Accessoires poignée: _Métal - Fer; Plaque bas de porte extérieure (matKickBoardOut): _Métal - Acier inoxydable; Plaque bas de porte intérieure (matKickBoardIn): _Métal - Acier inoxydable; Brique linteau: _Coupe3D_; Mortier linteau: _Enduit - Blanc nature; Clef de voûte linteau: _Pierre - Grès 01; Niche: _Mur int Hall; Porte appartient à Zone vers laquelle elle donne: yes; Coût: 0; Emplacement comme: Personnalisé; Surface vitrée totale (gs_list_glassarea_tmp): 0; Supplanter surface vitrée: no; Surface vitrée totale (gs_list_glassarea): 3.83542; Périmètre total vitrage: 0; Performance air libre (mm2/l/m): 0; Type de groupe (FM_Type): Autres; Type de groupe (iFMType): 25; Poids de l'objet: 0; Unité poids de l'objet: kg; Définition orientation porte: 0; Orientation porte: G; Fermeture porte: no; Type panneau de vision: Nbre panneaux vision; Dispositif main. ouvert.: no; Largeurs de battant de porte: 0.90 / 0.90; Opération IFC (ifc_optypestr): Autre; Opération IFC (ifc_optype): 12
AC_Pset_RenovationAndPhasing - Renovation Status: Existing

# IfcBuildingElementProxy: School Desk (20)
In: RDC
Classification: Element de construction non défini (Classification Archicad); Elément de construction non défini (Classification ARCHICAD); Material: Matériau de construction IFC
ArchiCADProperties - Calque: 21_Agencemt_____; Nom Élément de Bibliothèque: School Desk; Matériau de construction / Composite / Profil / Hachure: Sans Trame; Type Hachure: Sans Trame; Verrouillé: no; Nom d'étage d'implantation: RDC; Numéro d'étage d'implantation: 0; Type d'élément: Objet; Surfaces (Toutes): _Peinture - Noir; _Bois bureaux; _gris satiné; Position: Non défini; État de rénovation: Existant; Affichage sur filtre de rénovation: Tous les filtres appropriés; Fonction structurelle: Non défini; Surface: _Peinture - Ocre jaune; Classification ARCHICAD - 20: Elément de construction non défini
AC_Pset_School_Desk - Show 2D Hotspots in 3D: no; Desk Type: Single; 3D Detail Level: Detailed; Hooks: yes; Storage (bStorage): yes; Storage Type: Open; No. of Drawers: 1; Knob (bKnob): yes; Knob Style: Style 5; Contour Pen: gris moyen (007); Fill Pen: Général - fonds de hachures; Fill Background Pen: Général - fonds de hachures; Resolution: 8; Shadow: yes; Leg: _Bois-Pin vertical; Frame: _gris satiné; Tabletop / Drawer Front: _Bois bureaux; Storage (gs_drawer_mat): _gris satiné; Knob (gs_knob_mat): _Metal-Inox; Leg Base: _Peinture - Noir; Cost: 0; Group Type: Furniture; Type de groupe: 16; Object Weight: 0; Object Weight Unit: kg
AC_Pset_RenovationAndPhasing - Renovation Status: Existing
Name | ID de l'élément = Lien et ID d'élément = ID de Parent | Zones conflictuelles = Nom de zone liée | Angle de rotation (deg) | Fill Type
bureau-maitre | bureau-maitre | Salle de classe 5 | 270 | Sans Trame
3 x bureau-fixe | bureau-fixe | Salle de classe 3 | 2.03555e-13 | Hachure solide (2)
3 x bureau-fixe | bureau-fixe | Salle de classe 5 | 2.03555e-13 | Hachure solide (2)
bureau-maitre | bureau-maitre | Salle de classe 1 | 270 | Sans Trame
3 x bureau-fixe | bureau-fixe | Salle de classe 1 | 2.03555e-13 | Hachure solide (2)
3 x bureau-fixe | bureau-fixe | Salle de classe 4 | 2.03555e-13 | Hachure solide (2)
bureau-maitre | bureau-maitre | Salle de classe 3 | 270 | Sans Trame
3 x bureau-fixe | bureau-fixe | Salle de classe 2 | 2.03555e-13 | Hachure solide (2)
bureau-maitre | bureau-maitre | Salle de classe 4 | 270 | Sans Trame
bureau-maitre | bureau-maitre | Salle de classe 2 | 270 | Sans Trame

# IfcBuildingElementProxy: Trappe-visite_JM (7)
In: R+1
Classification: Element de construction non défini (Classification Archicad); Porte (Classification ARCHICAD); Material: Matériau de construction IFC
Pset_FireRatingProperties - FireResistanceRating: CF 1/2H
ArchiCADProperties - ID de l'élément: trappe clapet-CF; Lien et ID d'élément: trappe clapet-CF; Calque: 20_Cloison________; Nom Élément de Bibliothèque: Trappe-visite_JM; Matériau de construction / Composite / Profil / Hachure: Sans Trame; Type Hachure: Sans Trame; Verrouillé: no; Nom d'étage d'implantation: R+1; Numéro d'étage d'implantation: 1; Type d'élément: Porte; ID de Parent: clois tk-couloir; Surfaces (Toutes): _Mur int blanc; Position: Non défini; État de rénovation: Existant; Affichage sur filtre de rénovation: Tous les filtres appropriés; Fonction structurelle: Non défini; Dimensions ébrasure: 150×240; Dimensions trou mur: 150×240; Dimensions unité: 150×240; Dimensions sortie: 107×210; Dimensions battant: 109×211; Structure de Mur: _Cloison tk; Nom élément de bibliothèque d'ouverture: Trappe-visite_JM; Index hachure latérale ouverture: Sans Trame; Classification ARCHICAD - 21: Porte
AC_Pset_Trappe-visite_JM - Contours Mur (0-Sans,1-Tout,2-Côté,3-Longueur): 0; Point ch.0-Non,1-2D,2-3D,3-Tous: 3; Afficher points chauds 2D en 3D: yes; Option affichage en plan: 5; Angle de position baie: 0 deg; Trou reprend surface latérale de mur: yes; Division de surface du trou courbe dans murs courbes: no; Type de mur: 1; Position ancre ébrasuer: 1; Direction d'ouverture: -1; Valeur incrustation allège: 0; Démolition / Nouvelle constr.: 1; Afficher comme imposte: no; Afficher points chaud éditables: no; Niveau de détail 2D: 1; Afficher ébrasure sur symbole: 1; Affichage symbolique de l'ouverture: no; Niveau de détail 3D: 2; Taille nominale: 0; Taille trou comme taille nominale: yes; Taille ébrasure comme nominale: no; Taille unité comme nominale: no; Taille sortie comme nominale: no; Taille battant comme nominale: no; Transmettre taille nominale actuelle à sélection: no; Largeur cadre uniforme: yes; Epaisseur cadre=Epaisseur mur: no; Style cadre changé automatiquement: no; Trappe sans panneau: no; Position loquet: Clic; Tierce vitrée droite: no; Tierce vitrée gauche: yes; Imposte: yes; Chambranle extérieur: no; Type chambr. ext. (gs_trimtype_out_int): 1; Largeurs uniformes de chambranle (gs_trim_outside_uniform): yes; Chambranle intérieur.: no; Type chambr. intérieur (gs_trimtype_in_int): 1; Largeurs uniformes de chambranle (gs_trim_inside_uniform): yes; Seuil: no; Type seuil: 1; Angle seuil: 0 deg; Seuil changé automatiquement: no; Seuil porte: no; Type d'appui/seuil: 1; Angle appui: 0 deg; Niveau détail 3D seuil brique: 1; Style appui changé automatiquement: no; Volet: no; Type volet: 0; Types volet activés: 0; Nombre de panneaux: 2; Nombre de panneaux 2: 1; Position panneau (gs_shutter_panelPos): Symétrique; Position panneau (gs_shutter_iPanelPos): 1; Hauteur volet automatique: yes; Cadre supplémentaire: no; Type de couverture (gs_slidingShutter_cover): Profil en Z; Type de couverture (gs_slidingShutter_iCover): 1; Direction articulation (gs_foldingShutter_stacking): Intérieur; Direction articulation (gs_foldingShutter_iStacking): 1; Ouvert en 3D: no; Angle ouverture en 3D (gs_shutter_opAngle): 180 deg; Afficher symbole 2D: no; Afficher lignes d'ouverture sur symbole: no; Type de panneau: (gs_shutPanel_type): Style 1; Type de panneau: (gs_shutPanel_iType): 1; Largeur cadre inf. différente: no; Largeur volets automatiques: yes; Angle persienne: 30 deg; Nombre trous horizontaux: 5; Nombre trous verticaux: 8; Placement volet roulant (gs_shutRoll_placement): Sur façade; Placement volet roulant (gs_shutRoll_iPlacement): 1; Type boîte (gs_shutRoll_boxType): Rectangulaire; Type boîte (gs_shutRoll_iBoxType): 1; Position rampe (gs_shutRoll_railPos): Sur revêtement; Position rampe (gs_shutRoll_iRailPos): 1; Afficher revêtement derrière parasol (gs_shutRoll_showCasingBehind): no; Isolation derrière cellule (gs_shutRoll_cutWallBehind): no; Angle supérieur boîte: 10 deg; Taille boîte par défaut (gs_shutRoll_boxDefaultSize): Largeur ébrasure; Taille boîte par défaut (gs_shutRoll_iBoxDefaultSize): 1; Placement stores (gs_shutLam_placement): Fixé sur façade; Placement stores (gs_shutLam_iPlacement): 1; Isolation derrière cellule (gs_shutLam_cutWallBehind): no; Boîte ouverte: no; Rampe: no; Position rampe (gs_shutLam_railPos): Sur revêtement; Position rampe (gs_shutLam_iRailPos): 1; Afficher revêtement derrière parasol (gs_shutLam_showCasingBehind): no; Angle de rotation des lamelles (gs_shutLam_rotation): 45 deg; Angle de rotation des lamelles (gs_shutLam2_rotation): 45 deg; Linteau (bMasonryArch): no; Linteau (gs_masonry_arch_int): 0; Type linteau (gs_masonry_arch_structure): Stuc; Type linteau (gs_masonry_arch_structure_int): 0; Arche sur linteau: yes; Niche sous arche: yes; Angle inclinaison: 75 deg; Surface niche personnalisée: no; Type ébrasure (gs_reveal_type_int): 0; Type ébrasure inférieure (gs_reveal_type_bottom): Baie simple; Type ébrasure inférieure (gs_reveal_type_bottom_int): 2; Type ébrasure extérieure: Baie simple; Type ébrasure (gs_reveal_doubleOuterTypeInt): 0; Type ébrasure intérieure: Baie simple; Type ébrasure (gs_reveal_doubleInnerTypeInt): 0; Profondeur montant uniforme: yes; Côté angle 2: 20 deg; Côté angle: 20 deg; Angle côté supérieur: 20 deg; Angle côté inférieur: 20 deg; Utiliser composant finition mur: no; Tourner automatiquement plâtre surface intérieure: no; Tourner plâtre surface intérieure: 0; Tourner automatiquement plâtre surface extérieure: no; Tourner plâtre surface extérieure: 0; Peut être coté en 2D: no; Afficher en 3D: no; Type de fermeture (gs_closure_type_int): 0; Tourner couche sur côté (gs_cavity_side): Les deux; Tourner couche sur côté (iCavityClosureSide): 0; Nbre de couches retournées: 0; Num. à partir de (iCavityClosureTurnDir): 1; Placer fermeture sur côté 2: yes; Placer fermeture sur côté 1: yes; Placer fermeture en haut: no; Placer fermeture en bas: no; Placer fermeture sur couche: 1; Placer fermeture de côté (gs_cc_dutch_ClosureToSide): 1; Ecart à couche externe: no; Tourner couche sur fermeture: no; Insérer bande d'isolation: no; Afficher bande d'isolation: no; Stylo contour (gs_penJoint): ATTENTION; Type de ligne de contour (gs_ltJoint): 1; Motif de hachure (gs_fillJoint): Isolation polystyrène; Stylo hachure (gs_penJointFg): Général - Dessin 0.12; Stylo fond de hachure (gs_penJointBg): Maillage - Contours et hachures de recouvrement; Surface personnalisée: no; Surface: _Men ext_RAL9007; Stylo contour (gs_penPlug): ATTENTION; Type de ligne de contour (gs_ltPlug): 1; Motif de hachure (gs_fillPlug): Isolation polystyrène; Stylo hachure (gs_penPlugFg): Général - Dessin 0.12; Stylo fond de hachure (gs_penPlugBg): Maillage - Contours et hachures de recouvrement; Côté montant édité: 1; Côté mur édité: 1; Numéro couche éditée: 1; Tourner couche: no; Considérer couches comme plâtre: no; Tourner épaiseur: 1; Orientation hachure: 1; Ligne de séparation tournant: no; Stylo ligne de séparation: Général - Dessin 0.12; Dernier côté sélectionné: no; Méthode fermeture changée auto.: no; Connexion à gauche: no; Connexion à droite: no; Connexion en haut: no; Angle ouverture en 2D: 90 deg; Angle ouverture en 3D (gs_open_3D): 0 deg; Suppl. Opt. vue pour aff. symb. 2D: no; Type ligne ouverture: 1; Forme ligne ouverture (or_SwingType): Courbé; Forme ligne ouverture (or_iSwingType): 1; Forme ligne ouverture (or_SlidingType): Sans; Forme ligne ouverture (or_iSlidingType): 0; Suppl. Opt. vue pour proj. 3D: no; Afficher ligne d'ouverture: no; Type ligne côté ouverture (or_opLineType3dIn): Tirets; Type ligne côté ouverture (or_iOpLineType3dIn): 1; Type ligne côté opposé (or_opLineType3dOut): Ligne continue; Type ligne côté opposé (or_iOpLineType3dOut): 0; Orient. ligne (or_oplineStyle): Poignée; Orient. ligne (or_iOplineStyle): 1; Stylo ligne ouverture 2D/3D (or_opLinePen): Ouvertures - Général; Stylo ligne ouverture 2D/3D (or_iOpLinePen): 3; Stylo du symbole: Ouvertures - Général; Stylo contour cadre: Transparent; Stylo ligne coupée chambranle des deux côtés: Ouvertures - Général; Stylo battant en 2D: Ouvertures - Général; Ligne de contour de mur (gs_wcont_line): Sans; Ligne de contour de mur (iWallContourLine): 1; Type ligne contour int. mur: 1; Type ligne contour ext. mur: 1; Type ligne contour int. mur masqué: 4; Type ligne contour ext. mur masqué: 4; Stylo ligne contour de mur: Ouvertures - Général; Utiliser hachures: no; Motif de hachure cadre: Sans Trame; Stylo hachure cadre: Fond - Couleur 1; Stylo fond de hachure cadre: Fond - Couleur 1; Motif de hachure battant: Lame d'air; Stylo hachure de battant: Fond - Couleur 1; Stylo fond de hachure battant: Fond - Couleur 1; Motif hachure symbole en plan: Sans Trame; Stylo hachure symbole en plan: Fond - Couleur 1; Stylo fond hachure symbole plan: Transparent; Type ligne seuil et appui: 1; Stylo contour de seuil en coupe: Ouvertures - Général; Motif hachure de seuil en Coupe: Sans Trame; Stylo hachure seuil en Coupe: Fond - Couleur 1; Stylo fond hachure coupe Seuil: Fond - Couleur 1; Stylo seuil 3D: Général - Dessin 0.12; Stylo contour en coupe: Général - Dessin 0.12; Motif hachure appui en Coupe: Sans Trame; Stylo hachure d'appui en Coupe: Fond - Couleur 1; Stylo fond hachure appui Coupe: Fond - Couleur 1; Stylo contour isolation coupe: Général - Dessin 0.12; Motif hachure isolation Coupe: Isolation polystyrène; Stylo hachure isolation Coupe: Général - Dessin 0.12; Stylo fond hachure isol. Coupe: Fond - Couleur 1; Type hachure chambr. intérieur: Sans Trame; Stylo hachure chambr. int.: Fond - Couleur 1; Stylo fond hachure chambr. int.: Fond - Couleur 1; Type hachure chambr. ext.: Sans Trame; Stylo hachure chambr. ext.: Fond - Couleur 1; Stylo fond hachure chambr. ext.: Fond - Couleur 1; Motif de hachure arche coupe: Sans Trame; Stylo hachure en coupe d'arche: Fond - Couleur 1; Stylo fond hachure appui arche Coupe: Fond - Couleur 1; Type de ligne symbole volet: 1; Stylo ligne coupée volet: Général - Dessin 0.12; Stylo ligne non coupée 3D/Coupe: Général - Dessin 0.12; Type hachure coupée volet: Sans Trame; Stylo hachure coupée volet: Général - Dessin 0.12; Stylo fond hachure coupé volet: Fond de fenêtre; Motif de hachure d'isolation de volet: Dallage; Stylo de hachure d'isolation de volet: Général - Dessin 0.12; Stylo de fond d'isolation de volet: Fond de fenêtre; Stylo cadre: Eléments 2D - Général; Stylo panneau: Eléments 2D - Général; Stylo vitrage: Eléments 2D - Général; Stylo linteau: Eléments 2D - Général; Surface de cadre: _Mur int blanc; Surface de panneau: _Mur int blanc; Surface meneau: _Men ext_RAL9007; Surface vitre: _Verre clair (rapide); Surface intérieure chambranle: _Men ext_RAL9007; Surface extérieure chambranle: _Men ext_RAL9007; Surface panneau de volet: _Men ext_RAL9007; Surface cadre volet: _Men ext_RAL9007; Surface boîte volet roulant: _Métal - Acier inoxydable; Surface lames volet roulant: _Peinture - Blanc brillant; Surface rail volet roulant: _Peinture - Blanc brillant; Surface boîtier de stores: _Métal - Acier inoxydable; Surface segments de stores: _Peinture - Blanc brillant; Surface rail volet coulissant: _Métal - Acier inoxydable; Surface de seuil: _Men ext_RAL9007; Surface métal seuil: _Métal BAVETTE; Surface d'appui: _Men ext_RAL9007; Surface mortier appui briques: _Enduit - Blanc nature; Surface de poignée: _Men ext_RAL9007; Surface brique linteau: _Coupe3D_; Surface mortier linteau: _Enduit - Blanc nature; Surface clef de voûte linteau: _Pierre - Grès 01; Surface niche: _Mur int Hall; Porte appartient à Zone vers laquelle elle donne: yes; Coût: 0; Emplacement comme: Personnalisé; Surface vitrée totale (gs_list_glassarea_tmp): 0; Supplanter surface vitrée: no; Surface vitrée totale (gs_list_glassarea): 0; Périmètre total vitrage: 0; Type de groupe (FM_Type): Autres; Type de groupe (iFMType): 25; Poids de l'objet: 0; Unité poids de l'objet: kg; Définition orientation porte: 0; Opération IFC (ifc_optypestr): Non défini; Opération IFC (ifc_optype): 0
AC_Pset_RenovationAndPhasing - Renovation Status: Existing
Name | Zones conflictuelles = Nom de zone liée = À Zone | Taille L x H nominale | Taille L x H x E nominale | Type de direction de mur
4 x trappe clapet-CF | Circulation 3 | 60×40 | 60×40×5 | 0
2 x trappe clapet-CF | Circulation 2 | 60×40 | 60×40×5 | 0
trappe clapet-CF | Circulation 3 | 40×40 | 40×40×5 | 1

# IfcBuildingElementProxy: Type d'escalier (2)
In: RDC
Classification: Escalier (Classification ARCHICAD)
ArchiCADProperties - Verrouillé: no; Nom d'étage d'implantation: RDC; Numéro d'étage d'implantation: 0; Type d'élément: Escalier; Étage supérieur lié absolu: R+1; Étage supérieur lié relatif: Étage d'implantation + 1; Étage supérieur lié: Étage d'implantation + 1 (R+1); État de rénovation: Existant; Affichage sur filtre de rénovation: Tous les filtres appropriés; Fonction structurelle: Élément porteur; Angle d'inclinaison de contremarche par défaut: 90 deg; Pente de l'escalier: 28.0725 deg; Nombre de marches par volées: 20; Nombre de contremarches par volées: 20; Classification ARCHICAD - 21: Escalier
AC_Pset_RenovationAndPhasing - Renovation Status: Existing
Name | ID de l'élément = Lien et ID d'élément = ID de Parent | Calque | Zones conflictuelles | Matériaux de construction (Tous) | Surfaces (Toutes) | Position
ESC-001 | ESC-001 | 10_M refendGO__ | Hall d'entrée; Rangt. 1 | Bois - Massif 01; _BA banché | _Béton - Lissé; _Plastique - Caoutchouc (2); _Sol PVC couloir | Intérieur
ESC-2 | ESC-2 | 10_M x baseGO__ | Rangt. 2 | _BA banché | _Béton - Lissé | Extérieur

# IfcBuildingElementProxy: Type de garde-corps, garde-corps esc
In: R+1
Classification: Garde-corps (Classification ARCHICAD)
ArchiCADProperties - ID de l'élément: main-courante esc ext; Lien et ID d'élément: main-courante esc ext; Calque: 20_Serrurerie______; Verrouillé: no; Nom d'étage d'implantation: R+1; Numéro d'étage d'implantation: 1; Type d'élément: Garde-corps; ID de Parent: main-courante esc ext; Matériaux de construction (Tous): Bois - Massif 01; Métal - Inox; Surfaces (Toutes): _Men ext_RAL9007; _Métal - Zinc; Position: Non défini; État de rénovation: Existant; Affichage sur filtre de rénovation: Tous les filtres appropriés; Fonction structurelle: Non défini; Classification ARCHICAD - 21: Garde-corps
AC_Pset_RenovationAndPhasing - Renovation Status: Existing

# IfcBuildingElementProxy: Urinoir 21 (4)
In: RDC
Classification: Element de construction non défini (Classification Archicad); Material: Matériau de construction IFC
ArchiCADProperties - ID de l'élément: urinoir_BlocSanit; Lien et ID d'élément: urinoir_BlocSanit; Calque: 21_App Sanit_____; Nom Élément de Bibliothèque: Urinoir 21; Matériau de construction / Composite / Profil / Hachure: Hachure solide; Type Hachure: Hachure solide; Verrouillé: no; Nom d'étage d'implantation: RDC; Numéro d'étage d'implantation: 0; Type d'élément: Équipement; ID de Parent: urinoir_BlocSanit; Surfaces (Toutes): _Metal-Inox; _Sanitaire-porcelaine; Position: Non défini; État de rénovation: Existant; Affichage sur filtre de rénovation: Tous les filtres appropriés; Fonction structurelle: Élément non porteur; Angle de rotation: 94.0168 deg; Surface: _Peinture - Ocre jaune
AC_Pset_Urinoir_21 - Style (stStyle): Style 1; Style (iStyle): 1; Afficher points chauds 2D en 3D: no; Définir programme: no; 3D (gs_detlevel_3D): Détaillé; 3D (gs_detlevel_3D_m): 2; Type effluent (DirEffluent): A l'arrière; Type effluent (DirEffluent_ID): 1; Connexion d'eau: yes; Type outil (ConToolType_1): 2; Système MEP (ConSystem_1): Non défini; Type de forme (ConType_1): Cercle; Type connexion (ConConnectorType_1): Soudé; Connexion eau résiduaire: yes; Type outil (ConToolType_2): 2; Système MEP (ConSystem_2): Non défini; Type de forme (ConType_2): Cercle; Type connexion (ConConnectorType_2): Soudé; Résolution: 24; Ombre: yes; Type de symbole (gs_symbol_type): Type 2; Type de symbole (iSymbolType): 2; Activer types de symbole: no; Niveau de détail 2D (gs_detlevel_2D): Selon échelle; Niveau de détail 2D (gs_detlevel_2D_m): 0; Stylo contour: Eléments 2D - Général; Motif de hachure: Sans Trame; Stylo hachure: Général - Dessin 0.12; Stylo fond de hachure: Transparent; Cuvette: _Sanitaire-porcelaine; Connexion: _Metal-Inox; Poignée chasse: _Métal - Acier inoxydable; Utiliser surface de système: no; Surface de système: _Peinture - Cadmium jaune; Nombre connexions: 2; Coût: 0; Type de groupe (FM_Type): Sanitaires; Type de groupe (iFMType): 13; Aire: 0; Volume: 0; Poids de l'objet: 0; Unité poids de l'objet: kg
AC_Pset_RenovationAndPhasing - Renovation Status: Existing

# IfcBuildingElementProxy: WC 21 (13)
Classification: Element de construction non défini (Classification Archicad); Material: Matériau de construction IFC
ArchiCADProperties - Calque: 21_App Sanit_____; Nom Élément de Bibliothèque: WC 21; Matériau de construction / Composite / Profil / Hachure: Sans Trame; Type Hachure: Sans Trame; Verrouillé: no; Type d'élément: Équipement; Surfaces (Toutes): _Mur int blanc; _Metal-Inox; _Sanitaire-porcelaine; _lunette-WC; Position: Non défini; État de rénovation: Existant; Affichage sur filtre de rénovation: Tous les filtres appropriés; Fonction structurelle: Non défini; Surface: _Peinture-11
AC_Pset_WC_21 - Afficher points chauds 2D en 3D: no; Définir programme: no; Type support: Monté sur mur; Type cuvette support sol: Type 4; Type cuvette support mur: Type 1; Siège (gs_seat): Fermé; Couvercle: yes; Type chasse (strFlushType): Bâti-support; Type réservoir: Type 1; Type réservoir élevé: Type 1; Type bouton bâti-support: Type 1; Type chasse (strFlushometerType): Simple; Position bouton: Face; Afficher bâti-support en 2D: yes; Afficher bâti-support en 3D: no; Type effluent: A l'arrière; Connexion d'eau: yes; Type outil (ConToolType_1): 2; Système MEP (ConSystem_1): Non défini; Type de forme (ConType_1): Cercle; Type connexion (ConConnectorType_1): Soudé; Connexion eau résiduaire: yes; Type outil (ConToolType_2): 2; Système MEP (ConSystem_2): Non défini; Type de forme (ConType_2): Cercle; Type connexion (ConConnectorType_2): Soudé; Niveau de détail 3D: Détaillé; Résolution: 32; Ombre: yes; Afficher 3D (Projection 2D): yes; Niveau de détail 2D: Selon échelle; Stylo contour: Eléments 2D - Général; Motif de hachure: Sans Trame; Stylo hachure: Général - Dessin 0.12; Stylo fond de hachure: Transparent; Cuvette (gs_bowl_mat): _Sanitaire-porcelaine; Siège (matSeatCover): _lunette-WC; Réservoir: _Enduit minéral blanc; Tuyau de réservoir: _Metal-Inox; Bouton: _Mur int blanc; Détecteur: _chassis int; Tuyau de débimètre: _Metal-Inox; Connexion: _Metal-Inox; Nombre connexions: 2; Aire: 0; Volume: 0; Coût: 0; Type de groupe (FM_Type): Sanitaires; Type de groupe (iFMType): 13; Poids de l'objet: 0; Unité poids de l'objet: kg
AC_Pset_RenovationAndPhasing - Renovation Status: Existing
Name | In | ID de l'élément = Lien et ID d'élément = ID de Parent | Nom d'étage d'implantation | Numéro d'étage d'implantation | Angle de rotation (deg)
WC-hall | RDC | WC-hall | RDC | 0 | 93.9466 | ArchiCADProperties - Zones conflictuelles: Sanitaires; Nom de zone liée: Sanitaires
2 x WC-couloir | RDC | WC-couloir | RDC | 0 | 90 | ArchiCADProperties - Zones conflictuelles: Sanitaires; Nom de zone liée: Sanitaires
WC-hall | RDC | WC-hall | RDC | 0 | 273.947 | ArchiCADProperties - Zones conflictuelles: Sanitaires; Nom de zone liée: Sanitaires
WC-PMR_BlocSanit | RDC | WC-PMR_BlocSanit | RDC | 0 | 4.02
4 x WC-PMR_BlocSanit | RDC | WC-PMR_BlocSanit | RDC | 0 | 4.01357
WC-PMR_BlocSanit | RDC | WC-PMR_BlocSanit | RDC | 0 | 184.014
WC-PMR_BlocSanit | RDC | WC-PMR_BlocSanit | RDC | 0 | 184.02
2 x WC-couloir | R+1 | WC-couloir | R+1 | 1 | 90 | ArchiCADProperties - Zones conflictuelles: Sanitaires; Nom de zone liée: Sanitaires

# IfcBuildingElementProxy: _Agglos, socle gabion pluri
In: RDC
Classification: Mur (Classification ARCHICAD); Element de construction non défini (Classification Archicad); Material: _Agglos
ArchiCADProperties - ID de l'élément: socle gabion pluri; Lien et ID d'élément: socle gabion pluri; Calque: 10_M x baseGO__; Matériau de construction / Composite / Profil / Hachure: _Agglos; Matériau de construction: _Agglos; Verrouillé: no; Nom d'étage d'implantation: RDC; Numéro d'étage d'implantation: 0; Type d'élément: Forme; ID de Parent: socle gabion pluri; Matériaux de construction (Tous): _Agglos; Surfaces (Toutes): _Béton - Lissé; Position: Extérieur; Classification par DIN 277: Non défini; État de rénovation: Existant; Affichage sur filtre de rénovation: Tous les filtres appropriés; Fonction structurelle: Élément non porteur; Ombres portées: yes; Ombrage reçu: yes; Surface: _Béton - Lissé; Classification ARCHICAD - 21: Mur
AC_Pset_RenovationAndPhasing - Renovation Status: Existing

# IfcBuildingElementProxy: _Agglos 200 (4)
In: RDC
Classification: Mur (Classification ARCHICAD); Element de construction non défini (Classification Archicad); Material: _Agglos
ArchiCADProperties - ID de l'élément: M ext esc-dessous; Lien et ID d'élément: M ext esc-dessous; Calque: 10_M x baseGO__; Matériau de construction / Composite / Profil / Hachure: _Agglos; Matériau de construction: _Agglos; Verrouillé: no; Nom d'étage d'implantation: RDC; Numéro d'étage d'implantation: 0; Type d'élément: Mur; Étage supérieur lié absolu: R+1; Étage supérieur lié relatif: Étage d'implantation + 1; Étage supérieur lié: Étage d'implantation + 1 (R+1); Type de structure: Basique; ID de Parent: M ext esc-dessous; Matériaux de construction (Tous): _Agglos; Angle d'inclinaison: 90 deg; Nombre de percements: 0; Surface latérale: _Isolation - Polystyrène; Position: Intérieur; État de rénovation: Existant; Affichage sur filtre de rénovation: Tous les filtres appropriés; Fonction structurelle: Élément porteur; Complexité de mur: Droit; Option de géométrie: Uniforme; Emplacement de ligne de référence: Face extérieure; Surface de face extérieure: _Isolation - Polystyrène; Angle d'inclinaison interne de mur: 90 deg; Angle d'inclinaison externe de mur: 90 deg; Génération de modèle analytique structurel: yes; Classification ARCHICAD - 21: Mur
AC_Pset_RenovationAndPhasing - Renovation Status: Existing
Name | Surfaces (Toutes) | Surface de face intérieure
M ext esc-dessous | _Enduit minéral blanc; _Isolation - Polystyrène | _Enduit minéral blanc
3 x M ext esc-dessous | _Isolation - Polystyrène; _Enduit minéral RAL7004 | _Enduit minéral RAL7004

# IfcBuildingElementProxy: _BA banché 180 (10)
Classification: Mur (Classification ARCHICAD); Element de construction non défini (Classification Archicad); Material: _BA banché
ArchiCADProperties - Matériau de construction / Composite / Profil / Hachure: _BA banché; Matériau de construction: _BA banché; Verrouillé: no; Type d'élément: Mur; Type de structure: Basique; Matériaux de construction (Tous): _BA banché; Angle d'inclinaison: 90 deg; Nombre de percements: 0; État de rénovation: Existant; Affichage sur filtre de rénovation: Tous les filtres appropriés; Fonction structurelle: Élément porteur; Complexité de mur: Droit; Option de géométrie: Uniforme; Emplacement de ligne de référence: Face extérieure; Angle d'inclinaison interne de mur: 90 deg; Angle d'inclinaison externe de mur: 90 deg; Génération de modèle analytique structurel: yes; Classification ARCHICAD - 21: Mur
AC_Pset_RenovationAndPhasing - Renovation Status: Existing
Name | In | ID de l'élément = Lien et ID d'élément = ID de Parent | Calque | Nom d'étage d'implantation | Numéro d'étage d'implantation | Étage supérieur lié absolu | Étage supérieur lié relatif | Étage supérieur lié | Surfaces (Toutes) | Surface latérale | Position | Surface de face intérieure | Surface de face extérieure
5 x M-fondat_BlocSanit | Fondations | M-fondat_BlocSanit | 10_M x baseGO__ | Fondations | -1 | RDC | Étage d'implantation + 1 | Étage d'implantation + 1 (RDC) | _Béton - Lissé; _Enduit minéral blanc | _Enduit minéral blanc | Extérieur | _Béton - Lissé | _Béton - Lissé
M Refend_BlocSanit | RDC | M Refend_BlocSanit | 10_M refendGO__ | RDC | 0 | R+1 | Étage d'implantation + 1 | Étage d'implantation + 1 (R+1) | _Béton - Lissé; _Enduit minéral blanc; _Plafd blanc; _Mur int BlocSanit | _Mur int BlocSanit | Intérieur | _Mur int BlocSanit | _Mur int BlocSanit
3 x M-acrot_BlocSanit | R+1 | M-acrot_BlocSanit | 10_M x baseGO__ | R+1 | 1 | Non lié | Non lié | Non lié | _Béton - Lissé; _Enduit minéral blanc | _Enduit minéral blanc | Extérieur | _Béton - Lissé | _Enduit minéral blanc
M-acrot_BlocSanit | R+1 | M-acrot_BlocSanit | 10_M x baseGO__ | R+1 | 1 | Non lié | Non lié | Non lié | _Béton - Lissé; _Enduit minéral blanc | _Enduit minéral blanc | Extérieur | _Béton - Lissé | _Béton - Lissé

# IfcBuildingElementProxy: _BA banché RAL9007 150 (3)
Classification: Element de construction non défini (Classification Archicad); Mobilier (Classification ARCHICAD); Material: _BA banché RAL9007
ArchiCADProperties - Calque: 10_Plancher_Sol__.3CF; Matériau de construction / Composite / Profil / Hachure: _BA banché RAL9007; Matériau de construction: _BA banché RAL9007; Verrouillé: no; Type d'élément: Dalle; Type de structure: Basique; Matériaux de construction (Tous): _BA banché RAL9007; Hachure de recouvrement: 25 %; Nombre de percements: 0; Position: Intérieur; État de rénovation: Existant; Affichage sur filtre de rénovation: Tous les filtres appropriés; Fonction structurelle: Élément non porteur; Emplacement de plan de référence: Haut; Classification ARCHICAD - 21: Mobilier
AC_Pset_RenovationAndPhasing - Renovation Status: Existing
Name | In | ID de l'élément = Lien et ID d'élément = ID de Parent | Nom d'étage d'implantation | Numéro d'étage d'implantation | Surfaces (Toutes) | Surface supérieure | Surface latérale | Surface inférieure
Seuil acces cour | RDC | Seuil acces cour | RDC | 0 | _Béton - Lissé; _Men ext_RAL9007 | _Men ext_RAL9007 | _Béton - Lissé | _Béton - Lissé
Seuil-MR-terrasse | R+1 | Seuil-MR-terrasse | R+1 | 1 | _Béton - Lissé; _Men ext_RAL9007 | _Men ext_RAL9007 | _Béton - Lissé | _Béton - Lissé
Relevé-terrasse | R+1 | Relevé-terrasse | R+1 | 1 | _MENEAU gris RAL 9007; _Enduit minéral RAL7004 | _Enduit minéral RAL7004 | _Enduit minéral RAL7004 | _MENEAU gris RAL 9007

# IfcBuildingElementProxy: _BA banché RAL9007 180 (37)
Material: _BA banché RAL9007
AC_Pset_RenovationAndPhasing - Renovation Status: Existing
Name | In | Classification | ID de l'élément = Lien et ID d'élément = ID de Parent | Calque | Matériau de construction / Composite / Profil / Hachure = Matériau de construction = Matériaux de construction (Tous) | Nom de zone liée | Verrouillé | Nom d'étage d'implantation | Numéro d'étage d'implantation | Type d'élément = Classification ARCHICAD - 21 | Étage supérieur lié absolu | Étage supérieur lié relatif | Étage supérieur lié | Type de structure | Surfaces (Toutes) | Angle d'inclinaison (deg) = Angle d'inclinaison interne de mur (deg) = Angle d'inclinaison externe de mur (deg) | Nombre de percements | Surface latérale | Position | État de rénovation | Affichage sur filtre de rénovation | Fonction structurelle | Complexité de mur | Option de géométrie | Emplacement de ligne de référence | Surface de face intérieure | Surface de face extérieure | Génération de modèle analytique structurel
M refend | RDC | Mur (Classification ARCHICAD); Element de construction non défini (Classification Archicad) | M refend | 10_M refendGO__ | _BA banché RAL9007 | Sanitaires | no | RDC | 0 | Mur | R+1 | Étage d'implantation + 1 | Étage d'implantation + 1 (R+1) | Basique | _Mur int blanc; _Mur int Hall; _MENEAU gris RAL 9007 | 90 | 0 | _Mur int Hall | Intérieur | Existant | Tous les filtres appropriés | Élément porteur | Droit | Uniforme | Face extérieure | _Mur int blanc | _Mur int Hall | yes | ArchiCADProperties - Zones conflictuelles: local TGBT; Sanitaires; Sanitaires
M refend | RDC | Mur (Classification ARCHICAD); Element de construction non défini (Classification Archicad) | M refend | 10_M refendGO__ | _BA banché RAL9007 | Accès cour | no | RDC | 0 | Mur | R+1 | Étage d'implantation + 1 | Étage d'implantation + 1 (R+1) | Basique | _Mur int blanc; _Enduit minéral blanc; _MENEAU gris RAL 9007; _Enduit minéral RAL7004 | 90 | 0 | _Enduit minéral blanc | Intérieur | Existant | Tous les filtres appropriés | Élément porteur | Droit | Uniforme | Face extérieure | _Mur int blanc | _Mur int blanc | yes | ArchiCADProperties - Zones conflictuelles: Accès cour
M refend | RDC | Mur (Classification ARCHICAD); Element de construction non défini (Classification Archicad) | M refend | 10_M refendGO__ | _BA banché RAL9007 | Local entretien | no | RDC | 0 | Mur | R+1 | Étage d'implantation + 1 | Étage d'implantation + 1 (R+1) | Basique | _Mur int blanc; _MENEAU gris RAL 9007 | 90 | 0 | _MENEAU gris RAL 9007 | Intérieur | Existant | Tous les filtres appropriés | Élément porteur | Droit | Uniforme | Face extérieure | _Mur int blanc | _Mur int blanc | yes | ArchiCADProperties - Zones conflictuelles: Accès cour; Local entretien
M refend | RDC | Mur (Classification ARCHICAD); Element de construction non défini (Classification Archicad) | M refend | 10_M refendGO__ | _BA banché RAL9007 | Salle de classe 2 | no | RDC | 0 | Mur | R+1 | Étage d'implantation + 1 | Étage d'implantation + 1 (R+1) | Basique | _Mur int blanc; _MENEAU gris RAL 9007 | 90 | 0 | _MENEAU gris RAL 9007 | Intérieur | Existant | Tous les filtres appropriés | Élément porteur | Droit | Uniforme | Face extérieure | _Mur int blanc | _Mur int blanc | yes
M refend | RDC | Mur (Classification ARCHICAD); Element de construction non défini (Classification Archicad) | M refend | 10_M refendGO__ | _BA banché RAL9007 | Sanitaires | no | RDC | 0 | Mur | R+1 | Étage d'implantation + 1 | Étage d'implantation + 1 (R+1) | Basique | _Mur int blanc; _MENEAU gris RAL 9007 | 90 | 0 | _MENEAU gris RAL 9007 | Intérieur | Existant | Tous les filtres appropriés | Élément porteur | Droit | Uniforme | Face extérieure | _Mur int blanc | _Mur int blanc | yes
M refend | RDC | Mur (Classification ARCHICAD); Element de construction non défini (Classification Archicad) | M refend | 10_M refendGO__ | _BA banché RAL9007 | Sanitaires | no | RDC | 0 | Mur | R+1 | Étage d'implantation + 1 | Étage d'implantation + 1 (R+1) | Basique | _Mur int blanc; _MENEAU gris RAL 9007 | 90 | 0 | _MENEAU gris RAL 9007 | Intérieur | Existant | Tous les filtres appropriés | Élément porteur | Droit | Uniforme | Face extérieure | _Mur int blanc | _Mur int blanc | yes | ArchiCADProperties - Zones conflictuelles: Accès cour; Circulation 1; Sanitaires
2 x M refend | RDC | Mur (Classification ARCHICAD); Element de construction non défini (Classification Archicad) | M refend | 10_M refendGO__ | _BA banché RAL9007 | Salle de classe 1 | no | RDC | 0 | Mur | R+1 | Étage d'implantation + 1 | Étage d'implantation + 1 (R+1) | Basique | _Mur int blanc; _MENEAU gris RAL 9007 | 90 | 0 | _MENEAU gris RAL 9007 | Intérieur | Existant | Tous les filtres appropriés | Élément porteur | Droit | Uniforme | Face extérieure | _Mur int blanc | _Mur int blanc | yes | ArchiCADProperties - Zones conflictuelles: Circulation 1
M refend | RDC | Mur (Classification ARCHICAD); Element de construction non défini (Classification Archicad) | M refend | 10_M refendGO__ | _BA banché RAL9007 | Salle de classe 3 | no | RDC | 0 | Mur | R+1 | Étage d'implantation + 1 | Étage d'implantation + 1 (R+1) | Basique | _Mur int blanc; _MENEAU gris RAL 9007 | 90 | 0 | _MENEAU gris RAL 9007 | Intérieur | Existant | Tous les filtres appropriés | Élément porteur | Droit | Uniforme | Face extérieure | _Mur int blanc | _Mur int blanc | yes | ArchiCADProperties - Zones conflictuelles: Circulation 1
M refend | RDC | Mur (Classification ARCHICAD); Element de construction non défini (Classification Archicad) | M refend | 10_M refendGO__ | _BA banché RAL9007 | Local entretien | no | RDC | 0 | Mur | R+1 | Étage d'implantation + 1 | Étage d'implantation + 1 (R+1) | Basique | _Mur int blanc; _MENEAU gris RAL 9007 | 90 | 0 | _MENEAU gris RAL 9007 | Intérieur | Existant | Tous les filtres appropriés | Élément porteur | Droit | Uniforme | Face extérieure | _Mur int blanc | _Mur int blanc | yes
M refend | RDC | Mur (Classification ARCHICAD); Element de construction non défini (Classification Archicad) | M refend | 10_M refendGO__ | _BA banché RAL9007 | Activités RASED | no | RDC | 0 | Mur | Non lié | Non lié | Non lié | Basique | _Mur int blanc; _Mur int Hall; _MENEAU gris RAL 9007 | 90 | 0 | _Mur int Hall | Intérieur | Existant | Tous les filtres appropriés | Élément porteur | Droit | Uniforme | Face extérieure | _Mur int blanc | _Mur int blanc | yes
M refend | RDC | Mur (Classification ARCHICAD); Element de construction non défini (Classification Archicad) | M refend | 10_M refendGO__ | _BA banché RAL9007 | Salle de classe 4 | no | RDC | 0 | Mur | R+1 | Étage d'implantation + 1 | Étage d'implantation + 1 (R+1) | Basique | _Mur int blanc; _MENEAU gris RAL 9007 | 90 | 0 | _MENEAU gris RAL 9007 | Intérieur | Existant | Tous les filtres appropriés | Élément porteur | Droit | Uniforme | Face extérieure | _Mur int blanc | _Mur int blanc | yes | ArchiCADProperties - Zones conflictuelles: Circulation 1
M refend | RDC | Mur (Classification ARCHICAD); Element de construction non défini (Classification Archicad) | M refend | 10_M refendGO__ | _BA banché RAL9007 | Salle de classe 1 | no | RDC | 0 | Mur | R+1 | Étage d'implantation + 1 | Étage d'implantation + 1 (R+1) | Basique | _Mur int blanc; _MENEAU gris RAL 9007 | 90 | 0 | _MENEAU gris RAL 9007 | Intérieur | Existant | Tous les filtres appropriés | Élément porteur | Droit | Uniforme | Face extérieure | _Mur int blanc | _Mur int blanc | yes
M refend | RDC | Mur (Classification ARCHICAD); Element de construction non défini (Classification Archicad) | M refend | 10_M refendGO__ | _BA banché RAL9007 | Salle de classe 4 | no | RDC | 0 | Mur | R+1 | Étage d'implantation + 1 | Étage d'implantation + 1 (R+1) | Basique | _Mur int blanc; _MENEAU gris RAL 9007 | 90 | 0 | _MENEAU gris RAL 9007 | Intérieur | Existant | Tous les filtres appropriés | Élément porteur | Droit | Uniforme | Face extérieure | _Mur int blanc | _Mur int blanc | yes
cloison rangt1 | RDC | Mur (Classification ARCHICAD); Element de construction non défini (Classification Archicad) | cloison rangt1 | 10_M x baseGO__ | _BA banché RAL9007 | Rangt. 1 | no | RDC | 0 | Mur | Non lié | Non lié | Non lié | Basique | _Enduit minéral blanc; _MENEAU gris RAL 9007 | 90 | 0 | _Enduit minéral blanc | Intérieur | Existant | Tous les filtres appropriés | Élément porteur | Droit | Uniforme | Face extérieure | _Enduit minéral blanc | _Enduit minéral blanc | yes
M refend | RDC | Mur (Classification ARCHICAD); Element de construction non défini (Classification Archicad) | M refend | 10_M refendGO__ | _BA banché RAL9007 | Salle de classe 3 | no | RDC | 0 | Mur | R+1 | Étage d'implantation + 1 | Étage d'implantation + 1 (R+1) | Basique | _Mur int blanc; _MENEAU gris RAL 9007 | 90 | 0 | _MENEAU gris RAL 9007 | Intérieur | Existant | Tous les filtres appropriés | Élément porteur | Droit | Uniforme | Face extérieure | _Mur int blanc | _Mur int blanc | yes
M refend | RDC | Mur (Classification ARCHICAD); Element de construction non défini (Classification Archicad) | M refend | 10_M refendGO__ | _BA banché RAL9007 | Activités RASED | no | RDC | 0 | Mur | R+1 | Étage d'implantation + 1 | Étage d'implantation + 1 (R+1) | Basique | _Mur int Hall; _MENEAU gris RAL 9007; __Enduit minéral RAL7004 | 90 | 0 | _MENEAU gris RAL 9007 | Intérieur | Existant | Tous les filtres appropriés | Élément porteur | Droit | Uniforme | Face extérieure | _Mur int Hall | _Mur int Hall | yes | ArchiCADProperties - Zones conflictuelles: Activités RASED
M refend | RDC | Mur (Classification ARCHICAD); Element de construction non défini (Classification Archicad) | M refend | 10_M refendGO__ | _BA banché RAL9007 | Attente / Tisanerie | no | RDC | 0 | Mur | Non lié | Non lié | Non lié | Basique | _Mur int blanc; _Mur int Hall | 90 | 0 | _Mur int Hall | Intérieur | Existant | Tous les filtres appropriés | Élément porteur | Droit | Uniforme | Face extérieure | _Mur int Hall | _Mur int blanc | yes
M refend | RDC | Mur (Classification ARCHICAD)
M refend | R+1 | Mur (Classification ARCHICAD); Element de construction non défini (Classification Archicad) | M refend | 10_M refendGO__ | _BA banché RAL9007 | Circulation 3 | no | R+1 | 1 | Mur | Toit & PM | Étage d'implantation + 1 | Étage d'implantation + 1 (Toit & PM) | Basique | _Mur int blanc; _MENEAU gris RAL 9007 | 90 | 0 | _MENEAU gris RAL 9007 | Intérieur | Existant | Tous les filtres appropriés | Élément porteur | Droit | Uniforme | Face extérieure | _Mur int blanc | _Mur int blanc | yes | ArchiCADProperties - Zones conflictuelles: Circulation 3
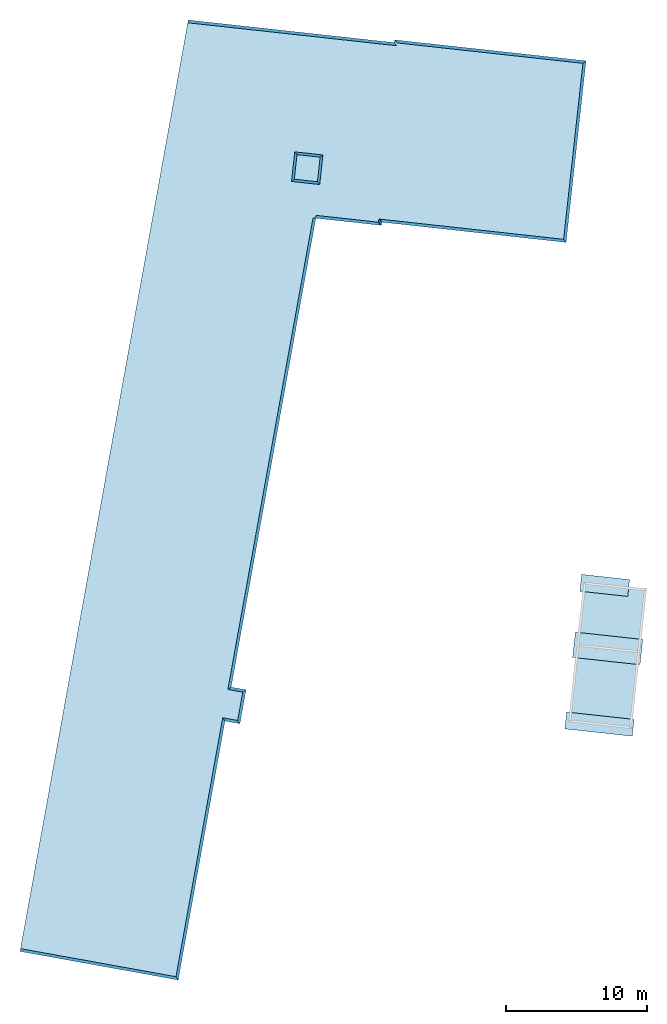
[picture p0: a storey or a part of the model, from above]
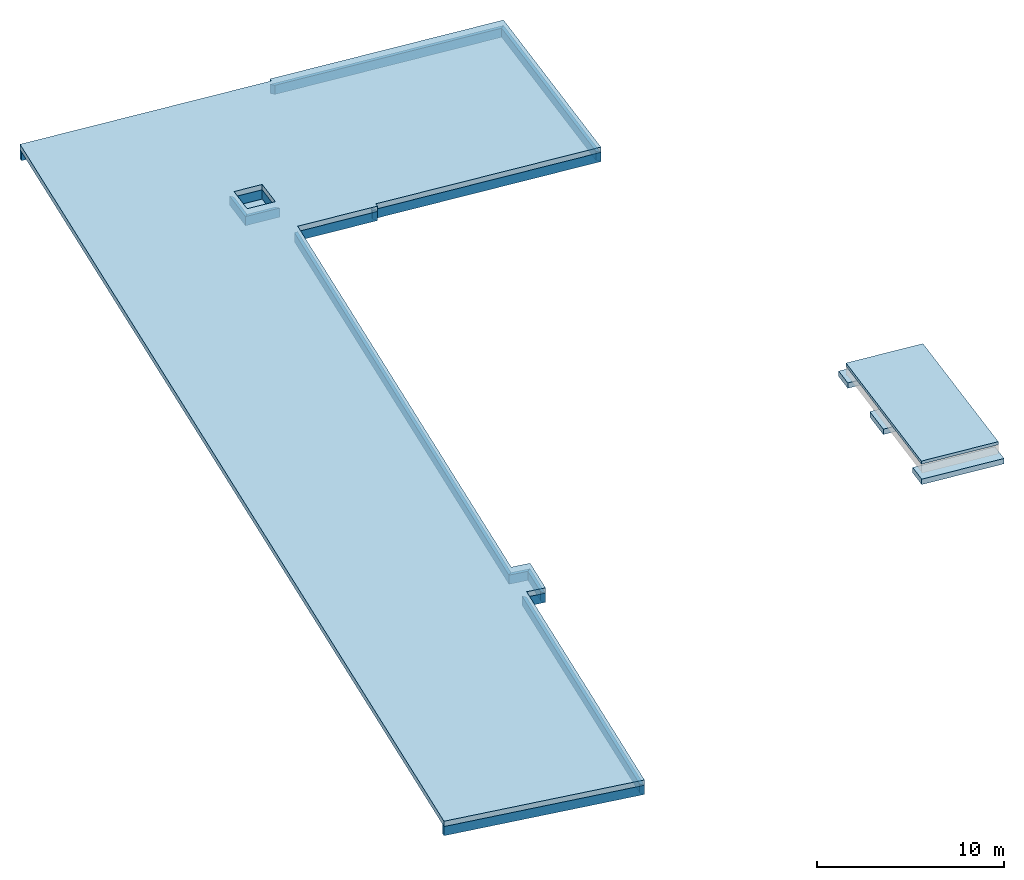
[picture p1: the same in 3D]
Properties of the parts of a building model (IFC2X3), part 8 of 10

# IfcBuildingElementProxy: _BA banché RAL9007 180 (37)
Name | In | Classification | ID de l'élément = Lien et ID d'élément = ID de Parent | Calque | Matériau de construction / Composite / Profil / Hachure = Matériau de construction = Matériaux de construction (Tous) | Nom de zone liée | Verrouillé | Nom d'étage d'implantation | Numéro d'étage d'implantation | Type d'élément = Classification ARCHICAD - 21 | Étage supérieur lié absolu | Étage supérieur lié relatif | Étage supérieur lié | Type de structure | Surfaces (Toutes) | Angle d'inclinaison (deg) = Angle d'inclinaison interne de mur (deg) = Angle d'inclinaison externe de mur (deg) | Nombre de percements | Surface latérale | Position | État de rénovation | Affichage sur filtre de rénovation | Fonction structurelle | Complexité de mur | Option de géométrie | Emplacement de ligne de référence | Surface de face intérieure | Surface de face extérieure | Génération de modèle analytique structurel
M refend | R+1 | Mur (Classification ARCHICAD); Element de construction non défini (Classification Archicad) | M refend | 10_M refendGO__ | _BA banché RAL9007 | Circulation 3 | no | R+1 | 1 | Mur | Toit & PM | Étage d'implantation + 1 | Étage d'implantation + 1 (Toit & PM) | Basique | _Mur int blanc; _Enduit minéral blanc; _MENEAU gris RAL 9007 | 90 | 0 | _Mur int blanc | Intérieur | Existant | Tous les filtres appropriés | Élément porteur | Droit | Uniforme | Face extérieure | _Mur int blanc | _Mur int blanc | yes | ArchiCADProperties - Zones conflictuelles: Circulation 3
2 x M refend | R+1 | Mur (Classification ARCHICAD); Element de construction non défini (Classification Archicad) | M refend | 10_M refendGO__ | _BA banché RAL9007 | Salle de classe 6 | no | R+1 | 1 | Mur | Toit & PM | Étage d'implantation + 1 | Étage d'implantation + 1 (Toit & PM) | Basique | _Mur int blanc; _MENEAU gris RAL 9007 | 90 | 0 | _MENEAU gris RAL 9007 | Intérieur | Existant | Tous les filtres appropriés | Élément porteur | Droit | Uniforme | Face extérieure | _Mur int blanc | _Mur int blanc | yes
M refend | R+1 | Mur (Classification ARCHICAD); Element de construction non défini (Classification Archicad) | M refend | 10_M refendGO__ | _BA banché RAL9007 | Salle de classe 8 | no | R+1 | 1 | Mur | Toit & PM | Étage d'implantation + 1 | Étage d'implantation + 1 (Toit & PM) | Basique | _Mur int blanc; _MENEAU gris RAL 9007 | 90 | 0 | _MENEAU gris RAL 9007 | Intérieur | Existant | Tous les filtres appropriés | Élément porteur | Droit | Uniforme | Face extérieure | _Mur int blanc | _Mur int blanc | yes
M refend | R+1 | Mur (Classification ARCHICAD); Element de construction non défini (Classification Archicad) | M refend | 10_M refendGO__ | _BA banché RAL9007 | Salle de classe 7 | no | R+1 | 1 | Mur | Toit & PM | Étage d'implantation + 1 | Étage d'implantation + 1 (Toit & PM) | Basique | _Mur int blanc; _MENEAU gris RAL 9007 | 90 | 0 | _MENEAU gris RAL 9007 | Intérieur | Existant | Tous les filtres appropriés | Élément porteur | Droit | Uniforme | Face extérieure | _Mur int blanc | _Mur int blanc | yes
M refend | R+1 | Mur (Classification ARCHICAD); Element de construction non défini (Classification Archicad) | M refend | 10_M refendGO__ | _BA banché RAL9007 | Salle de réunion (maîtres) | no | R+1 | 1 | Mur | Toit & PM | Étage d'implantation + 1 | Étage d'implantation + 1 (Toit & PM) | Basique | _Mur int Hall; _MENEAU gris RAL 9007 | 90 | 0 | _Mur int Hall | Intérieur | Existant | Tous les filtres appropriés | Élément porteur | Droit | Uniforme | Face extérieure | _Mur int Hall | _Mur int Hall | yes
M refend | R+1 | Mur (Classification ARCHICAD); Element de construction non défini (Classification Archicad) | M refend | 10_M refendGO__ | _BA banché RAL9007 | Bureau direction | no | R+1 | 1 | Mur | Toit & PM | Étage d'implantation + 1 | Étage d'implantation + 1 (Toit & PM) | Basique | _Mur int Hall; _MENEAU gris RAL 9007 | 90 | 0 | _Mur int Hall | Intérieur | Existant | Tous les filtres appropriés | Élément porteur | Droit | Uniforme | Face extérieure | _Mur int Hall | _MENEAU gris RAL 9007 | yes
M refend | R+1 | Mur (Classification ARCHICAD); Element de construction non défini (Classification Archicad) | M refend | 10_M refendGO__ | _BA banché RAL9007 | Sanitaires | no | R+1 | 1 | Mur | Toit & PM | Étage d'implantation + 1 | Étage d'implantation + 1 (Toit & PM) | Basique | _Mur int blanc; _MENEAU gris RAL 9007 | 90 | 0 | _MENEAU gris RAL 9007 | Intérieur | Existant | Tous les filtres appropriés | Élément porteur | Droit | Uniforme | Face extérieure | _Mur int blanc | _Mur int blanc | yes
M refend | R+1 | Mur (Classification ARCHICAD); Element de construction non défini (Classification Archicad) | M refend | 10_M refendGO__ | _BA banché RAL9007 | Salle de classe 6 | no | R+1 | 1 | Mur | Toit & PM | Étage d'implantation + 1 | Étage d'implantation + 1 (Toit & PM) | Basique | _Mur int blanc; _MENEAU gris RAL 9007 | 90 | 0 | _Mur int blanc | Intérieur | Existant | Tous les filtres appropriés | Élément porteur | Droit | Uniforme | Face extérieure | _Mur int blanc | _Mur int blanc | yes | ArchiCADProperties - Zones conflictuelles: Circulation 2
2 x M refend | R+1 | Mur (Classification ARCHICAD); Element de construction non défini (Classification Archicad) | M refend | 10_M refendGO__ | _BA banché RAL9007 | Salle de réunion (maîtres) | no | R+1 | 1 | Mur | Toit & PM | Étage d'implantation + 1 | Étage d'implantation + 1 (Toit & PM) | Basique | _Mur int Hall; _MENEAU gris RAL 9007 | 90 | 0 | _MENEAU gris RAL 9007 | Intérieur | Existant | Tous les filtres appropriés | Élément porteur | Droit | Uniforme | Face extérieure | _Mur int Hall | _Mur int Hall | yes | ArchiCADProperties - Zones conflictuelles: Circulation 2
M refend | R+1 | Mur (Classification ARCHICAD); Element de construction non défini (Classification Archicad) | M refend | 10_M refendGO__ | _BA banché RAL9007 | Circulation 3 | no | R+1 | 1 | Mur | Toit & PM | Étage d'implantation + 1 | Étage d'implantation + 1 (Toit & PM) | Basique | _Mur int blanc; _MENEAU gris RAL 9007 | 90 | 0 | _MENEAU gris RAL 9007 | Intérieur | Existant | Tous les filtres appropriés | Élément porteur | Droit | Uniforme | Face extérieure | _Mur int blanc | _Mur int blanc | yes | ArchiCADProperties - Zones conflictuelles: Sanitaires
M refend | R+1 | Mur (Classification ARCHICAD); Element de construction non défini (Classification Archicad) | M refend | 10_M refendGO__ | _BA banché RAL9007 | Salle de réunion (maîtres) | no | R+1 | 1 | Mur | Toit & PM | Étage d'implantation + 1 | Étage d'implantation + 1 (Toit & PM) | Basique | _Mur int Hall; _MENEAU gris RAL 9007 | 90 | 0 | _MENEAU gris RAL 9007 | Intérieur | Existant | Tous les filtres appropriés | Élément porteur | Droit | Uniforme | Face extérieure | _Mur int Hall | _Mur int Hall | yes | ArchiCADProperties - Zones conflictuelles: Circulation 2; Salle de réunion (maîtres)
M refend | R+1 | Mur (Classification ARCHICAD); Element de construction non défini (Classification Archicad) | M refend | 10_M refendGO__ | _BA banché RAL9007 | Salle de classe 9 | no | R+1 | 1 | Mur | Toit & PM | Étage d'implantation + 1 | Étage d'implantation + 1 (Toit & PM) | Basique | _Mur int blanc; _MENEAU gris RAL 9007 | 90 | 0 | _Mur int blanc | Intérieur | Existant | Tous les filtres appropriés | Élément porteur | Droit | Uniforme | Face extérieure | _Mur int blanc | _Mur int blanc | yes
facade ascenseur | R+1 | Mur (Classification ARCHICAD); Element de construction non défini (Classification Archicad) | facade ascenseur | 10_M x baseGO__ | _BA banché RAL9007 | Circulation 2 | no | R+1 | 1 | Mur | Toit & PM | Étage d'implantation + 1 | Étage d'implantation + 1 (Toit & PM) | Basique | _Mur int blanc; _Mur int Hall; _MENEAU gris RAL 9007 | 90 | 0 | _MENEAU gris RAL 9007 | Intérieur | Existant | Tous les filtres appropriés | Élément porteur | Droit | Uniforme | Face extérieure | _Mur int blanc | _Mur int Hall | yes
M refend | R+1 | Mur (Classification ARCHICAD); Element de construction non défini (Classification Archicad) | M refend | 10_M refendGO__ | _BA banché RAL9007 | Bureau direction | no | R+1 | 1 | Mur | Toit & PM | Étage d'implantation + 1 | Étage d'implantation + 1 (Toit & PM) | Basique | _Mur int Hall; _MENEAU gris RAL 9007 | 90 | 0 | _Mur int Hall | Intérieur | Existant | Tous les filtres appropriés | Élément porteur | Droit | Uniforme | Face extérieure | _MENEAU gris RAL 9007 | _Mur int Hall | yes | ArchiCADProperties - Zones conflictuelles: Circulation 2
M retour | Toit & PM | Mur (Classification ARCHICAD); Element de construction non défini (Classification Archicad) | M retour | 10_M x baseGO__ | _BA banché RAL9007 |  | no | Toit & PM | 2 | Mur | Non lié | Non lié | Non lié | Basique | _Mur int blanc; _Enduit minéral blanc; _MENEAU gris RAL 9007 | 90 | 0 | _MENEAU gris RAL 9007 | Extérieur | Existant | Tous les filtres appropriés | Élément porteur | Droit | Uniforme | Face extérieure | _Mur int blanc | _Enduit minéral blanc | yes

# IfcBuildingElementProxy: _BA banché RAL9007 5 (4)
In: RDC
Classification: Mur (Classification ARCHICAD); Element de construction non défini (Classification Archicad); Material: _BA banché RAL9007
ArchiCADProperties - ID de l'élément: Peinture murale; Lien et ID d'élément: Peinture murale; Calque: 10_M x baseGO__; Matériau de construction / Composite / Profil / Hachure: _BA banché RAL9007; Matériau de construction: _BA banché RAL9007; Zones conflictuelles: Salle plurivalente; Nom de zone liée: Salle plurivalente; Verrouillé: no; Nom d'étage d'implantation: RDC; Numéro d'étage d'implantation: 0; Type d'élément: Mur; Étage supérieur lié absolu: Non lié; Étage supérieur lié relatif: Non lié; Étage supérieur lié: Non lié; Type de structure: Basique; ID de Parent: Peinture murale; Matériaux de construction (Tous): _BA banché RAL9007; Surfaces (Toutes): _Enduit minéral blanc; _MENEAU gris RAL 9007; Angle d'inclinaison: 90 deg; Nombre de percements: 0; Surface latérale: _Enduit minéral blanc; Position: Intérieur; État de rénovation: Existant; Affichage sur filtre de rénovation: Tous les filtres appropriés; Fonction structurelle: Élément non porteur; Complexité de mur: Droit; Option de géométrie: Uniforme; Emplacement de ligne de référence: Face extérieure; Surface de face intérieure: _MENEAU gris RAL 9007; Surface de face extérieure: _Enduit minéral blanc; Angle d'inclinaison interne de mur: 90 deg; Angle d'inclinaison externe de mur: 90 deg; Classification ARCHICAD - 21: Mur
AC_Pset_RenovationAndPhasing - Renovation Status: Existing

# IfcBuildingElementProxy: _Bois contreplaqué 50 (10)
Classification: Element de construction non défini (Classification Archicad); Mobilier (Classification ARCHICAD); Material: _Bois contreplaqué
ArchiCADProperties - Calque: 20_Men Int________; Matériau de construction / Composite / Profil / Hachure: _Bois contreplaqué; Matériau de construction: _Bois contreplaqué; Verrouillé: no; Type d'élément: Dalle; Type de structure: Basique; Matériaux de construction (Tous): _Bois contreplaqué; Surfaces (Toutes): _Huisserie-int; Hachure de recouvrement: 25 %; Nombre de percements: 0; Surface supérieure: _Huisserie-int; Surface latérale: _Huisserie-int; Surface inférieure: _Huisserie-int; Position: Intérieur; État de rénovation: Existant; Affichage sur filtre de rénovation: Tous les filtres appropriés; Fonction structurelle: Élément non porteur; Emplacement de plan de référence: Haut; Classification ARCHICAD - 21: Mobilier
AC_Pset_RenovationAndPhasing - Renovation Status: Existing
Name | In | ID de l'élément = Lien et ID d'élément = ID de Parent | Nom de zone liée | Nom d'étage d'implantation | Numéro d'étage d'implantation
socle-tableau-classe | RDC | socle-tableau-classe | Salle de classe 2 | RDC | 0
socle-tableau | RDC | socle-tableau | Salle de classe 3 | RDC | 0
socle-tableau | RDC | socle-tableau | Salle de classe 4 | RDC | 0
socle-tableau | RDC | socle-tableau | Salle de classe 5 | RDC | 0
socle-tableau-classe | RDC | socle-tableau-classe | Salle de classe 1 | RDC | 0
socle-tableau | R+1 | socle-tableau | Salle de classe 8 | R+1 | 1
socle-tableau | R+1 | socle-tableau | Salle de classe 6 | R+1 | 1
socle-tableau | R+1 | socle-tableau | Salle de classe 10 | R+1 | 1
socle-tableau | R+1 | socle-tableau | Salle de classe 9 | R+1 | 1
socle-tableau | R+1 | socle-tableau | Salle de classe 7 | R+1 | 1

# IfcBuildingElementProxy: _Cloison 10cm 100 (5)
In: RDC
Classification: Mur (Classification ARCHICAD)
AC_Pset_RenovationAndPhasing - Renovation Status: Existing

# IfcBuildingElementProxy: _Cloison 50 (2)
Classification: Mur (Classification ARCHICAD); Element de construction non défini (Classification Archicad); Material: _Cloison
ArchiCADProperties - Calque: 20_Cloison________; Matériau de construction / Composite / Profil / Hachure: _Cloison; Matériau de construction: _Cloison; Zones conflictuelles: Sanitaires; Nom de zone liée: Sanitaires; Verrouillé: no; Type d'élément: Mur; Étage supérieur lié relatif: Étage d'implantation + 1; Type de structure: Basique; Matériaux de construction (Tous): _Cloison; Angle d'inclinaison: 90 deg; Nombre de percements: 0; Position: Intérieur; État de rénovation: Existant; Affichage sur filtre de rénovation: Tous les filtres appropriés; Fonction structurelle: Élément non porteur; Complexité de mur: Droit; Option de géométrie: Uniforme; Angle d'inclinaison interne de mur: 90 deg; Angle d'inclinaison externe de mur: 90 deg; Classification ARCHICAD - 21: Mur
AC_Pset_RenovationAndPhasing - Renovation Status: Existing
Name | In | ID de l'élément = Lien et ID d'élément = ID de Parent | Nom d'étage d'implantation | Numéro d'étage d'implantation | Étage supérieur lié absolu | Étage supérieur lié | Surfaces (Toutes) | Surface latérale | Emplacement de ligne de référence | Surface de face intérieure = Surface de face extérieure
clois-WC-RDC | RDC | clois-WC-RDC | RDC | 0 | R+1 | Étage d'implantation + 1 (R+1) | _Enduit minéral blanc; Revêt. murs int. | _Enduit minéral blanc | Centre | _Enduit minéral blanc
cloison-WC-R+1 | R+1 | cloison-WC-R+1 | R+1 | 1 | Toit & PM | Étage d'implantation + 1 (Toit & PM) | _Mur int blanc; Revêt. murs int. | Revêt. murs int. | Face extérieure | _Mur int blanc

# IfcBuildingElementProxy: _Dalle-flott 2+13 150, dalle-flottante CTA
In: R+1
Classification: Element de construction non défini (Classification Archicad); Plafond (Classification ARCHICAD); Material: _BA banché
ArchiCADProperties - ID de l'élément: dalle-flottante CTA; Lien et ID d'élément: dalle-flottante CTA; Calque: 10_Plancher_Sol__.3CF; Matériau de construction / Composite / Profil / Hachure: _Dalle-flott 2+13; Structure Composite: _Dalle-flott 2+13; Verrouillé: no; Nom d'étage d'implantation: R+1; Numéro d'étage d'implantation: 1; Type d'élément: Dalle; Type de structure: Composite; ID de Parent: dalle-flottante CTA; Matériaux de construction (Tous): _BA banché; _Etanchéité 2; Surfaces (Toutes): _Béton - Lissé; _Etanchéité - Membrane souple; Hachure de recouvrement: Dallage 60x60; Nombre de percements: 0; Surface supérieure: _Béton - Lissé; Surface inférieure: _Etanchéité - Membrane souple; Position: Intérieur; État de rénovation: Existant; Affichage sur filtre de rénovation: Tous les filtres appropriés; Fonction structurelle: Élément non porteur; Emplacement de plan de référence: Bas; Classification ARCHICAD - 21: Plafond
AC_Pset_RenovationAndPhasing - Renovation Status: Existing

# IfcBuildingElementProxy: _DalleToit 20+10+2 gris 340, Toit_BlocSanit
In: R+1
Classification: Element de construction non défini (Classification Archicad); Toit (Classification ARCHICAD); Material: _BA banché
ArchiCADProperties - ID de l'élément: Toit_BlocSanit; Lien et ID d'élément: Toit_BlocSanit; Calque: 10_Toit___________.3CF; Matériau de construction / Composite / Profil / Hachure: _DalleToit 20+10+2 gris; Structure Composite: _DalleToit 20+10+2 gris; Verrouillé: no; Nom d'étage d'implantation: R+1; Numéro d'étage d'implantation: 1; Type d'élément: Dalle; Type de structure: Composite; ID de Parent: Toit_BlocSanit; Matériaux de construction (Tous): _Etanchéité; _BA banché; _Isol Polyst Extrud 610; _Fini placo 500; Surfaces (Toutes): _Béton - Lissé; _Mur int blanc; _Enduit minéral blanc; _Etanchéité - Membrane souple; _Isolation - Polystyrène; _Plafd blanc; Hachure de recouvrement: 25 %; Nombre de percements: 0; Surface supérieure: _Mur int blanc; Surface inférieure: _Plafd blanc; Position: Intérieur; État de rénovation: Existant; Affichage sur filtre de rénovation: Tous les filtres appropriés; Fonction structurelle: Élément porteur; Emplacement de plan de référence: Haut; Génération de modèle analytique structurel: yes; Classification ARCHICAD - 21: Toit
AC_Pset_RenovationAndPhasing - Renovation Status: Existing

# IfcBuildingElementProxy: _M ext 18 +10 gris 280 (11)
Classification: Mur (Classification ARCHICAD); Element de construction non défini (Classification Archicad); Material: _BA banché RAL9007
ArchiCADProperties - ID de l'élément: M retour_isol; Lien et ID d'élément: M retour_isol; Calque: 10_M refendGO__; Matériau de construction / Composite / Profil / Hachure: _M ext 18 +10 gris; Structure Composite: _M ext 18 +10 gris; Verrouillé: no; Type d'élément: Mur; Étage supérieur lié relatif: Étage d'implantation + 1; Type de structure: Composite; ID de Parent: M retour_isol; Matériaux de construction (Tous): _BA banché RAL9007; _Isol Laine2verre; _Fini placo 600; Angle d'inclinaison: 90 deg; Nombre de percements: 0; État de rénovation: Existant; Affichage sur filtre de rénovation: Tous les filtres appropriés; Fonction structurelle: Élément porteur; Complexité de mur: Droit; Option de géométrie: Uniforme; Emplacement de ligne de référence: Face extérieure; Angle d'inclinaison interne de mur: 90 deg; Angle d'inclinaison externe de mur: 90 deg; Génération de modèle analytique structurel: yes; Classification ARCHICAD - 21: Mur
AC_Pset_RenovationAndPhasing - Renovation Status: Existing
Name | In | Nom de zone liée | Nom d'étage d'implantation | Numéro d'étage d'implantation | Étage supérieur lié absolu | Étage supérieur lié | Surfaces (Toutes) | Position | Surface de face intérieure | Surface de face extérieure
M retour_isol | RDC | Local entretien | RDC | 0 | R+1 | Étage d'implantation + 1 (R+1) | _Isolation - Laine de verre/roche (2); _Enduit minéral blanc; _MENEAU gris RAL 9007; _Plafd blanc | Intérieur | _Enduit minéral blanc | _Enduit minéral blanc
2 x M retour_isol | RDC | Salle de classe 1 | RDC | 0 | R+1 | Étage d'implantation + 1 (R+1) | _Mur int blanc; _Isolation - Laine de verre/roche (2); _MENEAU gris RAL 9007; _Plafd blanc | Extérieur | _Mur int blanc | _Mur int blanc
M retour_isol | RDC | Salle de classe 2 | RDC | 0 | R+1 | Étage d'implantation + 1 (R+1) | _Mur int blanc; _Isolation - Laine de verre/roche (2); _MENEAU gris RAL 9007; _Plafd blanc | Extérieur | _Mur int blanc | _Mur int blanc
M retour_isol | RDC | Salle de classe 4 | RDC | 0 | R+1 | Étage d'implantation + 1 (R+1) | _Mur int blanc; _Isolation - Laine de verre/roche (2); _MENEAU gris RAL 9007; _Plafd blanc | Extérieur | _Mur int blanc | _Mur int blanc
M retour_isol | RDC | Salle de classe 3 | RDC | 0 | R+1 | Étage d'implantation + 1 (R+1) | _Mur int blanc; _Isolation - Laine de verre/roche (2); _Enduit minéral blanc; _MENEAU gris RAL 9007; _Plafd blanc | Extérieur | _Mur int blanc | _Mur int blanc
M retour_isol | R+1 | Salle de classe 9 | R+1 | 1 | Toit & PM | Étage d'implantation + 1 (Toit & PM) | _Mur int blanc; _Isolation - Laine de verre/roche (2); _Enduit minéral blanc; _MENEAU gris RAL 9007; _Plafd blanc | Extérieur | _Mur int blanc | _Enduit minéral blanc
M retour_isol | R+1 | Salle de classe 8 | R+1 | 1 | Toit & PM | Étage d'implantation + 1 (Toit & PM) | _Mur int blanc; _Isolation - Laine de verre/roche (2); _Enduit minéral blanc; _MENEAU gris RAL 9007; _Plafd blanc | Extérieur | _Mur int blanc | _Enduit minéral blanc
M retour_isol | R+1 | Salle de classe 7 | R+1 | 1 | Toit & PM | Étage d'implantation + 1 (Toit & PM) | _Mur int blanc; _Isolation - Laine de verre/roche (2); _Enduit minéral blanc; _MENEAU gris RAL 9007; _Plafd blanc | Extérieur | _Mur int blanc | _Enduit minéral blanc
M retour_isol | R+1 | Salle de classe 6 | R+1 | 1 | Toit & PM | Étage d'implantation + 1 (Toit & PM) | _Mur int blanc; _Isolation - Laine de verre/roche (2); _Enduit minéral blanc; _MENEAU gris RAL 9007; _Plafd blanc | Extérieur | _Mur int blanc | _Enduit minéral blanc
M retour_isol | R+1 | Salle de classe 6 | R+1 | 1 | Toit & PM | Étage d'implantation + 1 (Toit & PM) | _Mur int blanc; _Isolation - Laine de verre/roche (2); _MENEAU gris RAL 9007; _Plafd blanc | Extérieur | _Mur int blanc | _Mur int blanc | ArchiCADProperties - Surface latérale: _Mur int blanc

# IfcBuildingElementProxy: _M ext 18 +12 300 (4)
In: RDC
Classification: Mur (Classification ARCHICAD); Element de construction non défini (Classification Archicad); Material: _BA banché
ArchiCADProperties - ID de l'élément: M-Ext_BlocSanit; Lien et ID d'élément: M-Ext_BlocSanit; Calque: 10_M x baseGO__; Matériau de construction / Composite / Profil / Hachure: _M ext 18 +12; Structure Composite: _M ext 18 +12; Verrouillé: no; Nom d'étage d'implantation: RDC; Numéro d'étage d'implantation: 0; Type d'élément: Mur; Étage supérieur lié absolu: R+1; Étage supérieur lié relatif: Étage d'implantation + 1; Étage supérieur lié: Étage d'implantation + 1 (R+1); Type de structure: Composite; ID de Parent: M-Ext_BlocSanit; Matériaux de construction (Tous): _BA banché; _Isol Laine2verre; _Fini placo 600; Surfaces (Toutes): _Béton - Lissé; _Isolation - Laine de verre/roche (2); _Enduit minéral blanc; _Plafd blanc; Angle d'inclinaison: 90 deg; Nombre de percements: 0; Surface latérale: _Enduit minéral blanc; Position: Extérieur; État de rénovation: Existant; Affichage sur filtre de rénovation: Tous les filtres appropriés; Fonction structurelle: Élément porteur; Complexité de mur: Droit; Option de géométrie: Uniforme; Emplacement de ligne de référence: Face extérieure; Surface de face intérieure: _Plafd blanc; Angle d'inclinaison interne de mur: 90 deg; Angle d'inclinaison externe de mur: 90 deg; Génération de modèle analytique structurel: yes; Classification ARCHICAD - 21: Mur
AC_Pset_RenovationAndPhasing - Renovation Status: Existing
Name | Surface de face extérieure
3 x M-Ext_BlocSanit | _Enduit minéral blanc
M-Ext_BlocSanit | _Béton - Lissé

# IfcBuildingElementProxy: _M ext 18 +18 360 (10)
Classification: Mur (Classification ARCHICAD); Element de construction non défini (Classification Archicad); Material: _BA banché RAL9007
ArchiCADProperties - Matériau de construction / Composite / Profil / Hachure: _M ext 18 +18; Structure Composite: _M ext 18 +18; Verrouillé: no; Type d'élément: Mur; Type de structure: Composite; Matériaux de construction (Tous): _BA banché RAL9007; _Isol Laine2verre; _Fini placo 600; Angle d'inclinaison: 90 deg; Nombre de percements: 0; État de rénovation: Existant; Affichage sur filtre de rénovation: Tous les filtres appropriés; Fonction structurelle: Élément porteur; Complexité de mur: Droit; Option de géométrie: Uniforme; Angle d'inclinaison interne de mur: 90 deg; Angle d'inclinaison externe de mur: 90 deg; Génération de modèle analytique structurel: yes; Classification ARCHICAD - 21: Mur
AC_Pset_RenovationAndPhasing - Renovation Status: Existing
Name | In | ID de l'élément = Lien et ID d'élément = ID de Parent | Calque | Nom de zone liée | Nom d'étage d'implantation | Numéro d'étage d'implantation | Étage supérieur lié absolu | Étage supérieur lié relatif | Étage supérieur lié | Surfaces (Toutes) | Position | Emplacement de ligne de référence | Surface de face intérieure | Surface de face extérieure
M ext hall-Est | RDC | M ext hall-Est | 10_M x baseGO__ | Salle plurivalente | RDC | 0 | R+1 | Étage d'implantation + 1 | Étage d'implantation + 1 (R+1) | _Men ext_RAL9007; _Mur int blanc; _Isolation - Laine de verre/roche (2); _Enduit minéral blanc; _MENEAU gris RAL 9007; __Enduit minéral RAL7004; _Plafd blanc | Extérieur | Face extérieure | _Mur int blanc | __Enduit minéral RAL7004 | ArchiCADProperties - Zones conflictuelles: Salle plurivalente; Surface latérale: _Enduit minéral blanc
M ext-Ouest | RDC | M ext-Ouest | 10_M x baseGO__ | Circulation 1 | RDC | 0 | R+1 | Étage d'implantation + 1 | Étage d'implantation + 1 (R+1) | _Mur int blanc; _Isolation - Laine de verre/roche (2); _Enduit minéral blanc; _MENEAU gris RAL 9007; _Plafd blanc | Extérieur | Face extérieure | _Mur int blanc | _Enduit minéral blanc
M ext-Ouest | RDC | M ext-Ouest | 10_M x baseGO__ | Circulation 1 | RDC | 0 | R+1 | Étage d'implantation + 1 | Étage d'implantation + 1 (R+1) | _Mur int blanc; _Isolation - Laine de verre/roche (2); _Enduit minéral blanc; _MENEAU gris RAL 9007; _Plafd blanc | Extérieur | Face extérieure | _Mur int blanc | _Enduit minéral blanc | ArchiCADProperties - Surface latérale: _Enduit minéral blanc
M ext-Ouest | RDC | M ext-Ouest | 10_M x baseGO__ | Circulation 1 | RDC | 0 | R+1 | Étage d'implantation + 1 | Étage d'implantation + 1 (R+1) | _Mur int blanc; _Isolation - Laine de verre/roche (2); _Enduit minéral blanc; _MENEAU gris RAL 9007 | Extérieur | Face extérieure | _Mur int blanc | _Enduit minéral blanc | ArchiCADProperties - Surface latérale: _Enduit minéral blanc
M refend | RDC | M refend | 10_M refendGO__ | Salle plurivalente | RDC | 0 | R+1 | Étage d'implantation + 1 | Étage d'implantation + 1 (R+1) | _Mur int blanc; _Isolation - Laine de verre/roche (2); _Enduit minéral blanc; _MENEAU gris RAL 9007; _Plafd blanc | Extérieur | Face extérieure | _Mur int blanc | _Enduit minéral blanc | ArchiCADProperties - Zones conflictuelles: Salle plurivalente
M ext hall-Sud | RDC | M ext hall-Sud | 10_M x baseGO__ | Circulation 2 | RDC | 0 | Toit & PM | Étage d'implantation + 2 | Étage d'implantation + 2 (Toit & PM) | _Men ext_RAL9007; _Isolation - Laine de verre/roche (2); _MENEAU gris RAL 9007; __Enduit minéral RAL7004; _Plafd blanc | Extérieur | Face extérieure | _Men ext_RAL9007 | __Enduit minéral RAL7004
M ext-milieu | R+1 | M ext-milieu | 10_M x baseGO__ | Salle de classe 8 | R+1 | 1 | Toit & PM | Étage d'implantation + 1 | Étage d'implantation + 1 (Toit & PM) | _Mur int blanc; _Isolation - Laine de verre/roche (2); _Enduit minéral blanc; _MENEAU gris RAL 9007; _Plafd blanc | Intérieur | Extérieur d'âme | _Mur int blanc | _Enduit minéral blanc
M refend | R+1 | M refend | 10_M refendGO__ | Circulation 3 | R+1 | 1 | Toit & PM | Étage d'implantation + 1 | Étage d'implantation + 1 (Toit & PM) | _Mur int blanc; _Isolation - Laine de verre/roche (2); _MENEAU gris RAL 9007; _Plafd blanc | Intérieur | Face extérieure | _Mur int blanc | _MENEAU gris RAL 9007 | ArchiCADProperties - Surface latérale: _Mur int blanc
M refend | R+1 | M refend | 10_M refendGO__ | Sanitaires | R+1 | 1 | Non lié | Non lié | Non lié | _Mur int blanc; _Isolation - Laine de verre/roche (2); _Enduit minéral blanc; _MENEAU gris RAL 9007; _Plafd blanc | Intérieur | Extérieur d'âme | _Mur int blanc | _Enduit minéral blanc
M ext-Ouest | R+1 | M ext-Ouest | 10_M x baseGO__ | Circulation 2 | R+1 | 1 | Toit & PM | Étage d'implantation + 1 | Étage d'implantation + 1 (Toit & PM) | _Mur int blanc; _Isolation - Laine de verre/roche (2); _Enduit minéral blanc; _MENEAU gris RAL 9007; _Plafd blanc | Extérieur | Face extérieure | _Mur int blanc | _Enduit minéral blanc

# IfcBuildingElementProxy: _M ext 18 +18 MILIEU 360 (2)
Classification: Mur (Classification ARCHICAD); Element de construction non défini (Classification Archicad); Material: _BA banché MILIEU
ArchiCADProperties - Calque: 10_M x baseGO__; Matériau de construction / Composite / Profil / Hachure: _M ext 18 +18 MILIEU; Structure Composite: _M ext 18 +18 MILIEU; Verrouillé: no; Type d'élément: Mur; Étage supérieur lié relatif: Étage d'implantation + 1; Type de structure: Composite; Matériaux de construction (Tous): _BA banché MILIEU; _Isol Laine2verre; _Fini placo 600; Angle d'inclinaison: 90 deg; Nombre de percements: 0; Position: Extérieur; État de rénovation: Existant; Affichage sur filtre de rénovation: Tous les filtres appropriés; Fonction structurelle: Élément porteur; Complexité de mur: Droit; Option de géométrie: Uniforme; Surface de face intérieure: _Mur int blanc; Surface de face extérieure: _Enduit minéral blanc; Angle d'inclinaison interne de mur: 90 deg; Angle d'inclinaison externe de mur: 90 deg; Génération de modèle analytique structurel: yes; Classification ARCHICAD - 21: Mur
AC_Pset_RenovationAndPhasing - Renovation Status: Existing
Name | In | ID de l'élément = Lien et ID d'élément = ID de Parent | Nom de zone liée | Nom d'étage d'implantation | Numéro d'étage d'implantation | Étage supérieur lié absolu | Étage supérieur lié | Surfaces (Toutes) | Emplacement de ligne de référence
M ext-Ouest | RDC | M ext-Ouest | Circulation 1 | RDC | 0 | R+1 | Étage d'implantation + 1 (R+1) | _Mur int blanc; _Isolation - Laine de verre/roche (2); _Enduit minéral blanc; _Enduit minéral RAL7004 | Face extérieure | ArchiCADProperties - Surface latérale: _Enduit minéral blanc
M ext entretien-Est | R+1 | M ext entretien-Est | Circulation 3 | R+1 | 1 | Toit & PM | Étage d'implantation + 1 (Toit & PM) | _Mur int blanc; _Isolation - Laine de verre/roche (2); _Enduit minéral blanc; _Enduit minéral RAL7004; _Plafd blanc | Extérieur d'âme

# IfcBuildingElementProxy: _M ext 18 +18 gris 360 (19)
Classification: Mur (Classification ARCHICAD); Element de construction non défini (Classification Archicad); Material: _BA banché RAL9007
ArchiCADProperties - Matériau de construction / Composite / Profil / Hachure: _M ext 18 +18 gris; Structure Composite: _M ext 18 +18 gris; Verrouillé: no; Type d'élément: Mur; Étage supérieur lié relatif: Étage d'implantation + 1; Type de structure: Composite; Matériaux de construction (Tous): _BA banché RAL9007; _Isol Laine2verre; _Fini placo 600; Angle d'inclinaison: 90 deg; Nombre de percements: 0; Position: Extérieur; État de rénovation: Existant; Affichage sur filtre de rénovation: Tous les filtres appropriés; Fonction structurelle: Élément porteur; Complexité de mur: Droit; Option de géométrie: Uniforme; Surface de face intérieure: _Mur int blanc; Angle d'inclinaison interne de mur: 90 deg; Angle d'inclinaison externe de mur: 90 deg; Génération de modèle analytique structurel: yes; Classification ARCHICAD - 21: Mur
AC_Pset_RenovationAndPhasing - Renovation Status: Existing
Name | In | ID de l'élément = Lien et ID d'élément = ID de Parent | Calque | Nom de zone liée | Nom d'étage d'implantation | Numéro d'étage d'implantation | Étage supérieur lié absolu | Étage supérieur lié | Surfaces (Toutes) | Emplacement de ligne de référence | Surface de face extérieure | Surface latérale
M ext entretien-Sud | RDC | M ext entretien-Sud | 10_M x baseGO__ | Local entretien | RDC | 0 | R+1 | Étage d'implantation + 1 (R+1) | _Mur int blanc; _Isolation - Laine de verre/roche (2); _MENEAU gris RAL 9007; _Plafd blanc | Extérieur d'âme | _Mur int blanc | ArchiCADProperties - Zones conflictuelles: Accès cour
M ext-Sud | RDC | M ext-Sud | 10_M x baseGO__ | Salle de classe 5 | RDC | 0 | R+1 | Étage d'implantation + 1 (R+1) | _Mur int blanc; _Isolation - Laine de verre/roche (2); _Enduit minéral blanc; _MENEAU gris RAL 9007; _Plafd blanc | Face extérieure | _Enduit minéral blanc
M ext-milieu | RDC | M ext-milieu | 10_M refendGO__ | Salle de classe 4 | RDC | 0 | R+1 | Étage d'implantation + 1 (R+1) | _Mur int blanc; _Isolation - Laine de verre/roche (2); _Enduit minéral blanc; _MENEAU gris RAL 9007; _Plafd blanc | Face extérieure | _Enduit minéral blanc
M ext escalier | RDC | M ext escalier | 10_M x baseGO__ | Rangt. 2 | RDC | 0 | R+1 | Étage d'implantation + 1 (R+1) | _Mur int blanc; _Isolation - Laine de verre/roche (2); _Enduit minéral blanc; _MENEAU gris RAL 9007; _Enduit minéral RAL7004; _Plafd blanc | Extérieur d'âme | _Enduit minéral RAL7004 | _Enduit minéral blanc
M ext-Nord | RDC | M ext-Nord | 10_M x baseGO__ | Rangt. 1 | RDC | 0 | R+1 | Étage d'implantation + 1 (R+1) | _Mur int blanc; _Isolation - Laine de verre/roche (2); _MENEAU gris RAL 9007; __Enduit minéral RAL7004; _Plafd blanc | Face extérieure | __Enduit minéral RAL7004
M ext-Est | RDC | M ext-Est | 10_M x baseGO__ | Salle de classe 1 | RDC | 0 | R+1 | Étage d'implantation + 1 (R+1) | _Mur int blanc; _Isolation - Laine de verre/roche (2); _Enduit minéral blanc; _MENEAU gris RAL 9007; _Plafd blanc | Face extérieure | _Enduit minéral blanc | _Enduit minéral blanc
M ext-Ouest | RDC | M ext-Ouest | 10_M x baseGO__ | Bureau RASED | RDC | 0 | R+1 | Étage d'implantation + 1 (R+1) | _Mur int blanc; _Isolation - Laine de verre/roche (2); _MENEAU gris RAL 9007; __Enduit minéral RAL7004; _Plafd blanc | Face extérieure | __Enduit minéral RAL7004
M ext pluri-Sud | RDC | M ext pluri-Sud | 10_M x baseGO__ | Salle plurivalente | RDC | 0 | R+1 | Étage d'implantation + 1 (R+1) | _Mur int blanc; _Isolation - Laine de verre/roche (2); _Enduit minéral blanc; _MENEAU gris RAL 9007; _Plafd blanc | Face extérieure | _Enduit minéral blanc | _Enduit minéral blanc
M ext-Est | RDC | M ext-Est | 10_M x baseGO__ | Salle de classe 3 | RDC | 0 | R+1 | Étage d'implantation + 1 (R+1) | _Mur int blanc; _Isolation - Laine de verre/roche (2); _Enduit minéral blanc; _MENEAU gris RAL 9007; _Plafd blanc | Face extérieure | _Enduit minéral blanc | _Enduit minéral blanc
M ext-Est | RDC | M ext-Est | 10_M x baseGO__ | Salle de classe 4 | RDC | 0 | R+1 | Étage d'implantation + 1 (R+1) | _Mur int blanc; _Isolation - Laine de verre/roche (2); _Enduit minéral blanc; _MENEAU gris RAL 9007; _Plafd blanc | Face extérieure | _Enduit minéral blanc | _Enduit minéral blanc
M ext sortie-cour | RDC | M ext sortie-cour | 10_M x baseGO__ | Accès cour | RDC | 0 | R+1 | Étage d'implantation + 1 (R+1) | _Mur int blanc; _Isolation - Laine de verre/roche (2); _MENEAU gris RAL 9007; _Enduit minéral RAL7004; _Plafd blanc | Extérieur d'âme | _Enduit minéral RAL7004 | _Enduit minéral RAL7004
M ext-Nord | R+1 | M ext-Nord | 10_M x baseGO__ | Circulation 2 | R+1 | 1 | Toit & PM | Étage d'implantation + 1 (Toit & PM) | _Mur int blanc; _Isolation - Laine de verre/roche (2); _MENEAU gris RAL 9007; __Enduit minéral RAL7004; _Plafd blanc | Face extérieure | __Enduit minéral RAL7004
M ext-Sud | R+1 | M ext-Sud | 10_M x baseGO__ | Circulation 3 | R+1 | 1 | Toit & PM | Étage d'implantation + 1 (Toit & PM) | _Mur int blanc; _Isolation - Laine de verre/roche (2); _Enduit minéral blanc; _MENEAU gris RAL 9007; _Plafd blanc | Face extérieure | _Enduit minéral blanc
M ext-Est | R+1 | M ext-Est | 10_M x baseGO__ | Salle de classe 9 | R+1 | 1 | Toit & PM | Étage d'implantation + 1 (Toit & PM) | _Mur int blanc; _Isolation - Laine de verre/roche (2); _Enduit minéral blanc; _MENEAU gris RAL 9007; _Plafd blanc | Face extérieure | _Enduit minéral blanc | _Enduit minéral blanc
M ext-hall-Est | R+1 | M ext-hall-Est | 10_M x baseGO__ |  | R+1 | 1 | Toit & PM | Étage d'implantation + 1 (Toit & PM) | _Men ext_RAL9007; _Mur int blanc; _Isolation - Laine de verre/roche (2); _Enduit minéral blanc; _MENEAU gris RAL 9007; __Enduit minéral RAL7004; _Plafd blanc | Face extérieure | __Enduit minéral RAL7004 | _Enduit minéral blanc
M ext-Est | R+1 | M ext-Est | 10_M x baseGO__ | Salle de classe 6 | R+1 | 1 | Toit & PM | Étage d'implantation + 1 (Toit & PM) | _Mur int blanc; _Isolation - Laine de verre/roche (2); _Enduit minéral blanc; _MENEAU gris RAL 9007; _Plafd blanc | Face extérieure | _Enduit minéral blanc | _Enduit minéral blanc
M ext-Est | R+1 | M ext-Est | 10_M x baseGO__ | Salle de classe 8 | R+1 | 1 | Toit & PM | Étage d'implantation + 1 (Toit & PM) | _Mur int blanc; _Isolation - Laine de verre/roche (2); _Enduit minéral blanc; _MENEAU gris RAL 9007; _Plafd blanc | Face extérieure | _Enduit minéral blanc | _Enduit minéral blanc
M ext-milieu | R+1 | M ext-milieu | 10_M x baseGO__ | Circulation 3 | R+1 | 1 | Toit & PM | Étage d'implantation + 1 (Toit & PM) | _Mur int blanc; _Isolation - Laine de verre/roche (2); _Enduit minéral blanc; _MENEAU gris RAL 9007; _Plafd blanc | Face extérieure | _Enduit minéral blanc
M ext-Ouest | R+1 | M ext-Ouest | 10_M x baseGO__ | Circulation 2 | R+1 | 1 | Toit & PM | Étage d'implantation + 1 (Toit & PM) | _Mur int blanc; _Isolation - Laine de verre/roche (2); _MENEAU gris RAL 9007; __Enduit minéral RAL7004; _Plafd blanc | Face extérieure | __Enduit minéral RAL7004

# IfcBuildingElementProxy: _M ext bard. 6+18+18 gris 420 (2)
In: RDC
Classification: Mur (Classification ARCHICAD)
ArchiCADProperties - Calque: 10_M x baseGO__; Matériau de construction / Composite / Profil / Hachure: _M ext bard. 6+18+18 gris; Structure Composite: _M ext bard. 6+18+18 gris; Nom de zone liée: Local entretien; Verrouillé: no; Nom d'étage d'implantation: RDC; Numéro d'étage d'implantation: 0; Type d'élément: Mur; Étage supérieur lié absolu: R+1; Étage supérieur lié relatif: Étage d'implantation + 1; Étage supérieur lié: Étage d'implantation + 1 (R+1); Type de structure: Composite; Matériaux de construction (Tous): Bois - Bardage; _BA banché RAL9007; _Isol Laine2verre; _Fini placo 600; Surfaces (Toutes): _Mur int blanc; _Isolation - Laine de verre/roche (2); _MENEAU gris RAL 9007; _Bois - Planches en bois ; _Bardage Bois-Horiz ocre; _Plafd blanc; Angle d'inclinaison: 90 deg; Nombre de percements: 0; Position: Extérieur; État de rénovation: Existant; Affichage sur filtre de rénovation: Tous les filtres appropriés; Fonction structurelle: Élément porteur; Complexité de mur: Droit; Option de géométrie: Uniforme; Emplacement de ligne de référence: Extérieur d'âme; Surface de face intérieure: _Mur int blanc; Surface de face extérieure: _Bardage Bois-Horiz ocre; Angle d'inclinaison interne de mur: 90 deg; Angle d'inclinaison externe de mur: 90 deg; Génération de modèle analytique structurel: yes; Classification ARCHICAD - 21: Mur
AC_Pset_RenovationAndPhasing - Renovation Status: Existing
Name | ID de l'élément = Lien et ID d'élément = ID de Parent
M ext-milieu | M ext-milieu
M ext entretien-Est | M ext entretien-Est

# IfcBuildingElementProxy: _M ext couloir 360 x 3000 (3)
In: RDC
Classification: Mur (Classification ARCHICAD); Element de construction non défini (Classification Archicad); Material: _BA banché RAL9007
ArchiCADProperties - ID de l'élément: M ext-Ouest; Lien et ID d'élément: M ext-Ouest; Calque: 10_M x baseGO__; Matériau de construction / Composite / Profil / Hachure: _M ext couloir; Profil complexe: _M ext couloir; Nom de zone liée: Circulation 1; Verrouillé: no; Nom d'étage d'implantation: RDC; Numéro d'étage d'implantation: 0; Type d'élément: Mur; Étage supérieur lié absolu: R+1; Étage supérieur lié relatif: Étage d'implantation + 1; Étage supérieur lié: Étage d'implantation + 1 (R+1); Type de structure: Profil complexe; ID de Parent: M ext-Ouest; Matériaux de construction (Tous): _BA banché RAL9007; _Isol Laine2verre; _Fini placo 600; Surfaces (Toutes): _Mur int blanc; _Isolation - Laine de verre/roche (2); _Enduit minéral blanc; _MENEAU gris RAL 9007; _Plafd blanc; Angle d'inclinaison: 90 deg; Nombre de percements: 0; Position: Extérieur; État de rénovation: Existant; Affichage sur filtre de rénovation: Tous les filtres appropriés; Fonction structurelle: Élément porteur; Complexité de mur: Droit; Option de géométrie: Uniforme; Surface de face intérieure: GENERAL; Angle d'inclinaison interne de mur: 90 deg; Angle d'inclinaison externe de mur: 90 deg; Génération de modèle analytique structurel: yes; Classification ARCHICAD - 21: Mur
AC_Pset_RenovationAndPhasing - Renovation Status: Existing

# IfcBuildingElementProxy: _M ext pluri Est 560 x 3750, M ext pluri-Est
In: RDC
Classification: Mur (Classification ARCHICAD); Element de construction non défini (Classification Archicad); Material: _BA banché RAL9007
ArchiCADProperties - ID de l'élément: M ext pluri-Est; Lien et ID d'élément: M ext pluri-Est; Calque: 10_M x baseGO__; Matériau de construction / Composite / Profil / Hachure: _M ext pluri Est; Profil complexe: _M ext pluri Est; Nom de zone liée: Salle plurivalente; Verrouillé: no; Nom d'étage d'implantation: RDC; Numéro d'étage d'implantation: 0; Type d'élément: Mur; Étage supérieur lié absolu: R+1; Étage supérieur lié relatif: Étage d'implantation + 1; Étage supérieur lié: Étage d'implantation + 1 (R+1); Type de structure: Profil complexe; ID de Parent: M ext pluri-Est; Matériaux de construction (Tous): _BA banché RAL9007; _Isol Laine2verre; _Fini placo 600; Surfaces (Toutes): _Mur int blanc; _Isolation - Laine de verre/roche (2); _Enduit minéral blanc; _MENEAU gris RAL 9007; _Plafd blanc; Angle d'inclinaison: 90 deg; Nombre de percements: 0; Surface latérale: _Men ext_RAL9007; Position: Extérieur; État de rénovation: Existant; Affichage sur filtre de rénovation: Tous les filtres appropriés; Fonction structurelle: Élément porteur; Complexité de mur: Droit; Option de géométrie: Uniforme; Surface de face intérieure: GENERAL; Angle d'inclinaison interne de mur: 90 deg; Angle d'inclinaison externe de mur: 90 deg; Génération de modèle analytique structurel: yes; Classification ARCHICAD - 21: Mur
AC_Pset_RenovationAndPhasing - Renovation Status: Existing

# IfcBuildingElementProxy: _M ext pluri Nord 560 x 3750, M ext pluri-Nord
In: RDC
Classification: Mur (Classification ARCHICAD); Element de construction non défini (Classification Archicad); Material: _BA banché RAL9007
ArchiCADProperties - ID de l'élément: M ext pluri-Nord; Lien et ID d'élément: M ext pluri-Nord; Calque: 10_M x baseGO__; Matériau de construction / Composite / Profil / Hachure: _M ext pluri Nord; Profil complexe: _M ext pluri Nord; Verrouillé: no; Nom d'étage d'implantation: RDC; Numéro d'étage d'implantation: 0; Type d'élément: Mur; Étage supérieur lié absolu: R+1; Étage supérieur lié relatif: Étage d'implantation + 1; Étage supérieur lié: Étage d'implantation + 1 (R+1); Type de structure: Profil complexe; ID de Parent: M ext pluri-Nord; Matériaux de construction (Tous): _BA banché RAL9007; _Isol Laine2verre; _Fini placo 600; Surfaces (Toutes): _Mur int blanc; _Isolation - Laine de verre/roche (2); _Enduit minéral blanc; _MENEAU gris RAL 9007; _Plafd blanc; Angle d'inclinaison: 90 deg; Nombre de percements: 0; Surface latérale: _MENEAU gris RAL 9007; Position: Extérieur; État de rénovation: Existant; Affichage sur filtre de rénovation: Tous les filtres appropriés; Fonction structurelle: Élément porteur; Complexité de mur: Droit; Option de géométrie: Uniforme; Surface de face intérieure: GENERAL; Angle d'inclinaison interne de mur: 90 deg; Angle d'inclinaison externe de mur: 90 deg; Génération de modèle analytique structurel: yes; Classification ARCHICAD - 21: Mur
AC_Pset_RenovationAndPhasing - Renovation Status: Existing

# IfcBuildingElementProxy: _acrotere 230 x 600 (4)
In: R+1
Classification: Mur (Classification ARCHICAD); Element de construction non défini (Classification Archicad); Material: _BA banché RAL9007
ArchiCADProperties - ID de l'élément: M acrot-pluri; Lien et ID d'élément: M acrot-pluri; Calque: 10_M x baseGO__; Matériau de construction / Composite / Profil / Hachure: _acrotere; Profil complexe: _acrotere; Verrouillé: no; Nom d'étage d'implantation: R+1; Numéro d'étage d'implantation: 1; Type d'élément: Mur; Étage supérieur lié absolu: Non lié; Étage supérieur lié relatif: Non lié; Étage supérieur lié: Non lié; Type de structure: Profil complexe; ID de Parent: M acrot-pluri; Matériaux de construction (Tous): _menuiserie alu; _BA banché RAL9007; Surfaces (Toutes): _Men ext_RAL9007; _Enduit minéral blanc; _MENEAU gris RAL 9007; Angle d'inclinaison: 90 deg; Nombre de percements: 0; Surface latérale: _Enduit minéral blanc; Position: Extérieur; État de rénovation: Existant; Affichage sur filtre de rénovation: Tous les filtres appropriés; Fonction structurelle: Élément porteur; Complexité de mur: Droit; Option de géométrie: Uniforme; Surface de face intérieure: GENERAL; Angle d'inclinaison interne de mur: 90 deg; Angle d'inclinaison externe de mur: 90 deg; Génération de modèle analytique structurel: yes; Classification ARCHICAD - 21: Mur
AC_Pset_RenovationAndPhasing - Renovation Status: Existing

# IfcBuildingElementProxy: _acrotere 230 x 850, M acrot-pluri
In: R+1
Classification: Mur (Classification ARCHICAD); Element de construction non défini (Classification Archicad); Material: _BA banché RAL9007
ArchiCADProperties - ID de l'élément: M acrot-pluri; Lien et ID d'élément: M acrot-pluri; Calque: 10_M x baseGO__; Matériau de construction / Composite / Profil / Hachure: _acrotere; Profil complexe: _acrotere; Verrouillé: no; Nom d'étage d'implantation: R+1; Numéro d'étage d'implantation: 1; Type d'élément: Mur; Étage supérieur lié absolu: Non lié; Étage supérieur lié relatif: Non lié; Étage supérieur lié: Non lié; Type de structure: Profil complexe; ID de Parent: M acrot-pluri; Matériaux de construction (Tous): _menuiserie alu; _BA banché RAL9007; Surfaces (Toutes): _Men ext_RAL9007; _Enduit minéral blanc; _MENEAU gris RAL 9007; Angle d'inclinaison: 90 deg; Nombre de percements: 0; Surface latérale: _Enduit minéral blanc; Position: Extérieur; État de rénovation: Existant; Affichage sur filtre de rénovation: Tous les filtres appropriés; Fonction structurelle: Élément porteur; Complexité de mur: Droit; Option de géométrie: Uniforme; Surface de face intérieure: GENERAL; Angle d'inclinaison interne de mur: 90 deg; Angle d'inclinaison externe de mur: 90 deg; Génération de modèle analytique structurel: yes; Classification ARCHICAD - 21: Mur
AC_Pset_RenovationAndPhasing - Renovation Status: Existing

# IfcBuildingElementProxy: _panneau mélaminé 19 (140)
Material: _panneau mélaminé
ArchiCADProperties - Matériau de construction / Composite / Profil / Hachure: _panneau mélaminé; Matériau de construction: _panneau mélaminé; Verrouillé: no; Type d'élément: Mur; Étage supérieur lié absolu: Non lié; Étage supérieur lié relatif: Non lié; Étage supérieur lié: Non lié; Type de structure: Basique; Matériaux de construction (Tous): _panneau mélaminé; Angle d'inclinaison: 90 deg; Nombre de percements: 0; Position: Intérieur; État de rénovation: Existant; Affichage sur filtre de rénovation: Tous les filtres appropriés; Fonction structurelle: Élément non porteur; Complexité de mur: Droit; Option de géométrie: Uniforme; Angle d'inclinaison interne de mur: 90 deg; Angle d'inclinaison externe de mur: 90 deg
AC_Pset_RenovationAndPhasing - Renovation Status: Existing
Name | In | Classification | ID de l'élément = Lien et ID d'élément = ID de Parent | Calque | Zones conflictuelles = Nom de zone liée | Nom d'étage d'implantation | Numéro d'étage d'implantation | Surfaces (Toutes) | Surface latérale = Surface de face intérieure = Surface de face extérieure | Emplacement de ligne de référence | Classification ARCHICAD - 21
cloison pl-classe | RDC | Mur (Classification ARCHICAD); Element de construction non défini (Classification Archicad) | cloison pl-classe | 20_Men Int________ | Salle de classe 1 | RDC | 0 | _Peinture - Blanc brillant; _Panneau-mélaminé | _Panneau-mélaminé | Centre | Mur
cloison pl-classe | RDC | Mur (Classification ARCHICAD); Element de construction non défini (Classification Archicad) | cloison pl-classe | 20_Men Int________ | Salle de classe 1 | RDC | 0 | _Peinture - Blanc brillant; _Panneau-mélaminé | _Panneau-mélaminé | Face extérieure | Mur
3 x cloison pl-classe | RDC | Mur (Classification ARCHICAD); Element de construction non défini (Classification Archicad) | cloison pl-classe | 20_Men Int________ | Salle de classe 1 | RDC | 0 | _Panneau-mélaminé | _Panneau-mélaminé | Centre | Mur
2 x cloison pl-classe | RDC | Mur (Classification ARCHICAD); Element de construction non défini (Classification Archicad) | cloison pl-classe | 20_Cloison________ | Salle de classe 1 | RDC | 0 | _Panneau-mélaminé | _Panneau-mélaminé | Centre | Mur
4 x cloison pl-classe | RDC | Mur (Classification ARCHICAD); Element de construction non défini (Classification Archicad) | cloison pl-classe | 20_Men Int________ | Salle de classe 3 | RDC | 0 | _Panneau-mélaminé | _Panneau-mélaminé | Centre | Mur
2 x raidiseur-fd-classe simple | RDC | Element de construction non défini (Classification Archicad); Mobilier (Classification ARCHICAD) | raidiseur-fd-classe simple | 20_Men Int________ | Salle de classe 1 | RDC | 0 | _Mur int blanc | _Mur int blanc | Face intérieure | Mobilier
2 x cloison pl-classe | RDC | Mur (Classification ARCHICAD); Element de construction non défini (Classification Archicad) | cloison pl-classe | 20_Cloison________ | Salle de classe 5 | RDC | 0 | _Panneau-mélaminé | _Panneau-mélaminé | Centre | Mur
cloison-fd-classe D | RDC | Mur (Classification ARCHICAD); Element de construction non défini (Classification Archicad) | cloison-fd-classe D | 20_Men Int________ | Salle de classe 1 | RDC | 0 | _Panneau-mélaminé | _Panneau-mélaminé | Face extérieure | Mur
2 x cloison pl-classe | RDC | Mur (Classification ARCHICAD); Element de construction non défini (Classification Archicad) | cloison pl-classe | 20_Cloison________ | Salle de classe 4 | RDC | 0 | _Panneau-mélaminé | _Panneau-mélaminé | Centre | Mur
4 x cloison pl-classe | RDC | Mur (Classification ARCHICAD); Element de construction non défini (Classification Archicad) | cloison pl-classe | 20_Men Int________ | Salle de classe 4 | RDC | 0 | _Panneau-mélaminé | _Panneau-mélaminé | Centre | Mur
cloison-fd-classe G | RDC | Mur (Classification ARCHICAD); Element de construction non défini (Classification Archicad) | cloison-fd-classe G | 20_Men Int________ | Salle de classe 1 | RDC | 0 | _Panneau-mélaminé | _Panneau-mélaminé | Face extérieure | Mur
cloison pl-classe | RDC | Mur (Classification ARCHICAD); Element de construction non défini (Classification Archicad) | cloison pl-classe | 20_Men Int________ | Salle de classe 1 | RDC | 0 | _Panneau-mélaminé | _Panneau-mélaminé | Face extérieure | Mur
cloison-fd-classe D | RDC | Mur (Classification ARCHICAD); Element de construction non défini (Classification Archicad) | cloison-fd-classe D | 20_Men Int________ | Salle de classe 5 | RDC | 0 | _Peinture - Blanc brillant; _Panneau-mélaminé | _Panneau-mélaminé | Face extérieure | Mur
2 x cloison pl-classe | RDC | Mur (Classification ARCHICAD); Element de construction non défini (Classification Archicad) | cloison pl-classe | 20_Cloison________ | Salle de classe 3 | RDC | 0 | _Panneau-mélaminé | _Panneau-mélaminé | Centre | Mur
2 x raidiseur-fd-classe simple | RDC | Element de construction non défini (Classification Archicad); Mobilier (Classification ARCHICAD) | raidiseur-fd-classe simple | 20_Men Int________ | Salle de classe 5 | RDC | 0 | _Mur int blanc; _Peinture - Blanc brillant | _Mur int blanc | Face intérieure | Mobilier
cloison-fd-classe G | RDC | Mur (Classification ARCHICAD); Element de construction non défini (Classification Archicad) | cloison-fd-classe G | 20_Men Int________ | Salle de classe 2 | RDC | 0 | _Peinture - Blanc brillant; _Panneau-mélaminé | _Panneau-mélaminé | Face extérieure | Mur
cloison-fd-classe D | RDC | Mur (Classification ARCHICAD); Element de construction non défini (Classification Archicad) | cloison-fd-classe D | 20_Men Int________ | Salle de classe 2 | RDC | 0 | _Panneau-mélaminé | _Panneau-mélaminé | Face extérieure | Mur
cloison-fd-classe G | RDC | Mur (Classification ARCHICAD); Element de construction non défini (Classification Archicad) | cloison-fd-classe G | 20_Men Int________ | Salle de classe 3 | RDC | 0 | _Panneau-mélaminé | _Panneau-mélaminé | Face extérieure | Mur
cloison-fd-classe D | RDC | Mur (Classification ARCHICAD); Element de construction non défini (Classification Archicad) | cloison-fd-classe D | 20_Men Int________ | Salle de classe 3 | RDC | 0 | _Panneau-mélaminé | _Panneau-mélaminé | Face extérieure | Mur
cloison-fd-classe G | RDC | Mur (Classification ARCHICAD); Element de construction non défini (Classification Archicad) | cloison-fd-classe G | 20_Men Int________ | Salle de classe 4 | RDC | 0 | _Panneau-mélaminé | _Panneau-mélaminé | Face extérieure | Mur
cloison-fd-classe D | RDC | Mur (Classification ARCHICAD); Element de construction non défini (Classification Archicad) | cloison-fd-classe D | 20_Men Int________ | Salle de classe 4 | RDC | 0 | _Panneau-mélaminé | _Panneau-mélaminé | Face extérieure | Mur
cloison-fd-classe G | RDC | Mur (Classification ARCHICAD); Element de construction non défini (Classification Archicad) | cloison-fd-classe G | 20_Men Int________ | Salle de classe 5 | RDC | 0 | _Peinture - Blanc brillant; _Panneau-mélaminé | _Panneau-mélaminé | Face extérieure | Mur
4 x cloison pl-classe | RDC | Mur (Classification ARCHICAD); Element de construction non défini (Classification Archicad) | cloison pl-classe | 20_Men Int________ | Salle de classe 5 | RDC | 0 | _Panneau-mélaminé | _Panneau-mélaminé | Centre | Mur
2 x raidiseur-sous-tableau | RDC | Element de construction non défini (Classification Archicad); Mobilier (Classification ARCHICAD) | raidiseur-sous-tableau | 20_Men Int________ | Salle de classe 1 | RDC | 0 | _Mur int blanc | _Mur int blanc | Centre | Mobilier
cloison pl-classe | RDC | Mur (Classification ARCHICAD); Element de construction non défini (Classification Archicad) | cloison pl-classe | 20_Men Int________ | Salle de classe 4 | RDC | 0 | _Peinture - Blanc brillant; _Panneau-mélaminé | _Panneau-mélaminé | Face extérieure | Mur
2 x raidiseur-sous-tableau | RDC | Element de construction non défini (Classification Archicad); Mobilier (Classification ARCHICAD) | raidiseur-sous-tableau | 20_Men Int________ | Salle de classe 3 | RDC | 0 | _Mur int blanc | _Mur int blanc | Centre | Mobilier
4 x cloison pl-classe | RDC | Mur (Classification ARCHICAD); Element de construction non défini (Classification Archicad) | cloison pl-classe | 20_Men Int________ | Salle de classe 2 | RDC | 0 | _Panneau-mélaminé | _Panneau-mélaminé | Centre | Mur
2 x raidiseur-sous-tableau | RDC | Element de construction non défini (Classification Archicad); Mobilier (Classification ARCHICAD) | raidiseur-sous-tableau | 20_Men Int________ | Salle de classe 4 | RDC | 0 | _Mur int blanc | _Mur int blanc | Centre | Mobilier
cloison pl-classe | RDC | Mur (Classification ARCHICAD); Element de construction non défini (Classification Archicad) | cloison pl-classe | 20_Men Int________ | Salle de classe 4 | RDC | 0 | _Panneau-mélaminé | _Panneau-mélaminé | Face extérieure | Mur
cloison pl-classe | RDC | Mur (Classification ARCHICAD); Element de construction non défini (Classification Archicad) | cloison pl-classe | 20_Men Int________ | Salle de classe 3 | RDC | 0 | _Panneau-mélaminé | _Panneau-mélaminé | Face extérieure | Mur
cloison pl-classe | RDC | Mur (Classification ARCHICAD); Element de construction non défini (Classification Archicad) | cloison pl-classe | 20_Men Int________ | Salle de classe 3 | RDC | 0 | _Peinture - Blanc brillant; _Panneau-mélaminé | _Panneau-mélaminé | Face extérieure | Mur
2 x cloison pl-classe | RDC | Mur (Classification ARCHICAD); Element de construction non défini (Classification Archicad) | cloison pl-classe | 20_Cloison________ | Salle de classe 2 | RDC | 0 | _Panneau-mélaminé | _Panneau-mélaminé | Centre | Mur
2 x raidiseur-sous-tableau | RDC | Element de construction non défini (Classification Archicad); Mobilier (Classification ARCHICAD) | raidiseur-sous-tableau | 20_Men Int________ | Salle de classe 5 | RDC | 0 | _Mur int blanc | _Mur int blanc | Centre | Mobilier
cloison pl-classe | RDC | Mur (Classification ARCHICAD); Element de construction non défini (Classification Archicad) | cloison pl-classe | 20_Men Int________ | Salle de classe 5 | RDC | 0 | _Panneau-mélaminé | _Panneau-mélaminé | Face extérieure | Mur
cloison pl-classe | RDC | Mur (Classification ARCHICAD); Element de construction non défini (Classification Archicad) | cloison pl-classe | 20_Men Int________ | Salle de classe 5 | RDC | 0 | _Peinture - Blanc brillant; _Panneau-mélaminé | _Panneau-mélaminé | Face extérieure | Mur
cloison pl-classe | RDC | Mur (Classification ARCHICAD); Element de construction non défini (Classification Archicad) | cloison pl-classe | 20_Men Int________ | Salle de classe 2 | RDC | 0 | _Peinture - Blanc brillant; _Panneau-mélaminé | _Panneau-mélaminé | Face extérieure | Mur
cloison pl-classe | RDC | Mur (Classification ARCHICAD); Element de construction non défini (Classification Archicad) | cloison pl-classe | 20_Men Int________ | Salle de classe 2 | RDC | 0 | _Panneau-mélaminé | _Panneau-mélaminé | Face extérieure | Mur
2 x raidiseur-sous-tableau | RDC | Element de construction non défini (Classification Archicad); Mobilier (Classification ARCHICAD) | raidiseur-sous-tableau | 20_Men Int________ | Salle de classe 2 | RDC | 0 | _Mur int blanc | _Mur int blanc | Centre | Mobilier
2 x raidiseur-fd-classe simple | RDC | Element de construction non défini (Classification Archicad); Mobilier (Classification ARCHICAD) | raidiseur-fd-classe simple | 20_Men Int________ | Salle de classe 2 | RDC | 0 | _Mur int blanc; _Peinture - Blanc brillant | _Mur int blanc | Face intérieure | Mobilier
2 x raidiseur-fd-classe simple | RDC | Element de construction non défini (Classification Archicad); Mobilier (Classification ARCHICAD) | raidiseur-fd-classe simple | 20_Men Int________ | Salle de classe 3 | RDC | 0 | _Mur int blanc | _Mur int blanc | Face intérieure | Mobilier
2 x raidiseur-fd-classe simple | RDC | Element de construction non défini (Classification Archicad); Mobilier (Classification ARCHICAD) | raidiseur-fd-classe simple | 20_Men Int________ | Salle de classe 4 | RDC | 0 | _Mur int blanc | _Mur int blanc | Face intérieure | Mobilier
cloison-fd-classe G | R+1 | Mur (Classification ARCHICAD); Element de construction non défini (Classification Archicad) | cloison-fd-classe G | 20_Men Int________ | Salle de classe 8 | R+1 | 1 | _Panneau-mélaminé | _Panneau-mélaminé | Face extérieure | Mur
4 x cloison pl-classe | R+1 | Mur (Classification ARCHICAD); Element de construction non défini (Classification Archicad) | cloison pl-classe | 20_Men Int________ | Salle de classe 6 | R+1 | 1 | _Peinture - Blanc brillant; _Panneau-mélaminé | _Panneau-mélaminé | Centre | Mur
cloison pl-classe | R+1 | Mur (Classification ARCHICAD); Element de construction non défini (Classification Archicad) | cloison pl-classe | 20_Cloison________ | Salle de classe 9 | R+1 | 1 | _Peinture - Blanc brillant; _Panneau-mélaminé | _Panneau-mélaminé | Face extérieure | Mur
cloison-fd-classe G | R+1 | Mur (Classification ARCHICAD); Element de construction non défini (Classification Archicad) | cloison-fd-classe G | 20_Men Int________ | Salle de classe 10 | R+1 | 1 | _Peinture - Blanc brillant; _Panneau-mélaminé | _Panneau-mélaminé | Face extérieure | Mur
cloison-fd-classe D | R+1 | Mur (Classification ARCHICAD); Element de construction non défini (Classification Archicad) | cloison-fd-classe D | 20_Men Int________ | Salle de classe 8 | R+1 | 1 | _Panneau-mélaminé | _Panneau-mélaminé | Face extérieure | Mur
cloison-fd-classe D | R+1 | Mur (Classification ARCHICAD); Element de construction non défini (Classification Archicad) | cloison-fd-classe D | 20_Men Int________ | Salle de classe 10 | R+1 | 1 | _Panneau-mélaminé | _Panneau-mélaminé | Face extérieure | Mur
cloison pl-classe | R+1 | Mur (Classification ARCHICAD); Element de construction non défini (Classification Archicad) | cloison pl-classe | 20_Cloison________ | Salle de classe 7 | R+1 | 1 | _Peinture - Blanc brillant; _Panneau-mélaminé | _Panneau-mélaminé | Face extérieure | Mur
2 x cloison pl-classe | R+1 | Mur (Classification ARCHICAD); Element de construction non défini (Classification Archicad) | cloison pl-classe | 20_Cloison________ | Salle de classe 8 | R+1 | 1 | _Peinture - Blanc brillant; _Panneau-mélaminé | _Panneau-mélaminé | Centre | Mur
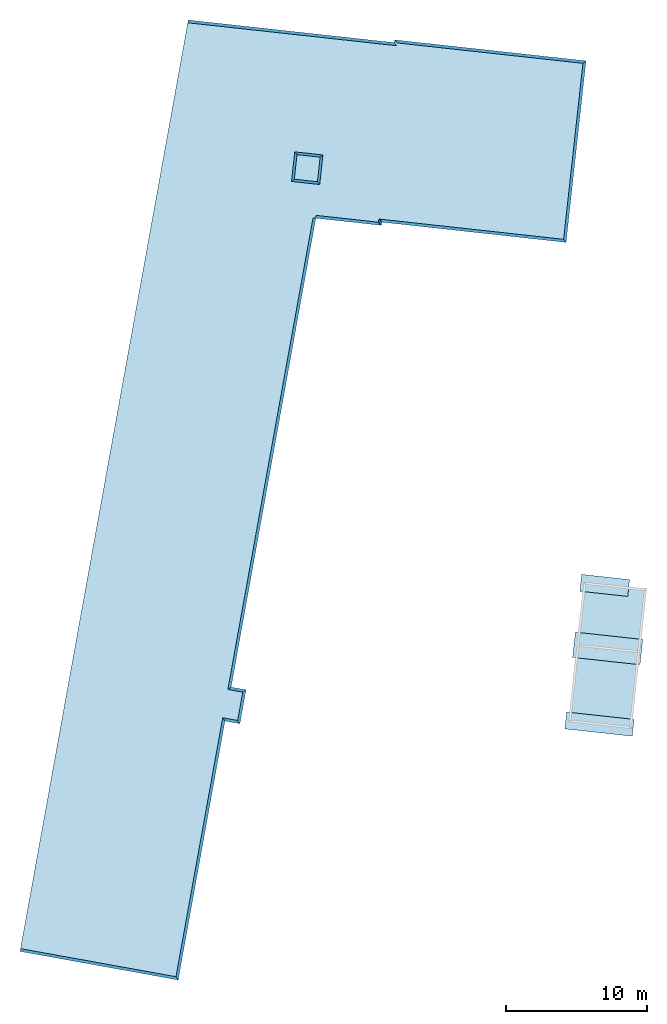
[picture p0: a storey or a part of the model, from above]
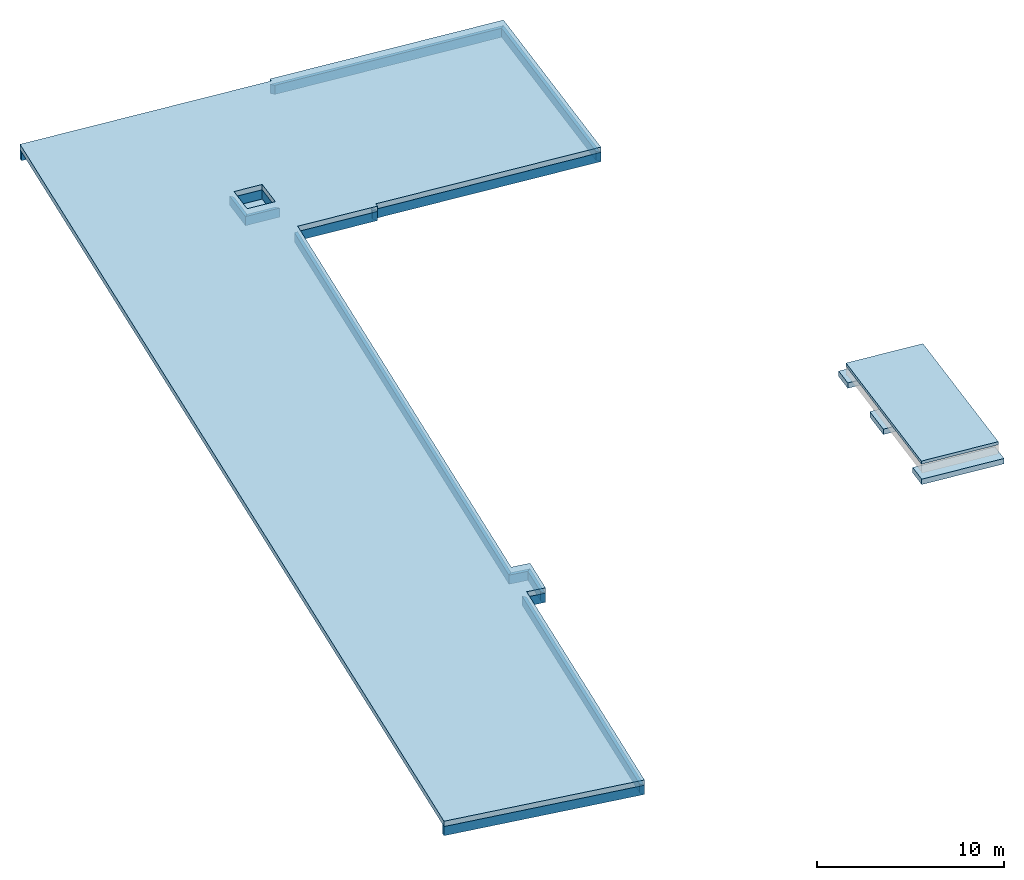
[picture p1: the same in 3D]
Properties of the parts of a building model (IFC2X3), part 9 of 10

# IfcBuildingElementProxy: _panneau mélaminé 19 (140)
Name | In | Classification | ID de l'élément = Lien et ID d'élément = ID de Parent | Calque | Zones conflictuelles = Nom de zone liée | Nom d'étage d'implantation | Numéro d'étage d'implantation | Surfaces (Toutes) | Surface latérale = Surface de face intérieure = Surface de face extérieure | Emplacement de ligne de référence | Classification ARCHICAD - 21
cloison-fd-classe G | R+1 | Mur (Classification ARCHICAD); Element de construction non défini (Classification Archicad) | cloison-fd-classe G | 20_Men Int________ | Salle de classe 9 | R+1 | 1 | _Peinture - Blanc brillant; _Panneau-mélaminé | _Panneau-mélaminé | Face extérieure | Mur
cloison-fd-classe D | R+1 | Mur (Classification ARCHICAD); Element de construction non défini (Classification Archicad) | cloison-fd-classe D | 20_Men Int________ | Salle de classe 9 | R+1 | 1 | _Panneau-mélaminé | _Panneau-mélaminé | Face extérieure | Mur
cloison pl-classe | R+1 | Mur (Classification ARCHICAD); Element de construction non défini (Classification Archicad) | cloison pl-classe | 20_Cloison________ | Salle de classe 10 | R+1 | 1 | _Panneau-mélaminé | _Panneau-mélaminé | Face extérieure | Mur
cloison pl-classe | R+1 | Mur (Classification ARCHICAD); Element de construction non défini (Classification Archicad) | cloison pl-classe | 20_Cloison________ | Salle de classe 10 | R+1 | 1 | _Peinture - Blanc brillant; _Panneau-mélaminé | _Panneau-mélaminé | Face extérieure | Mur
cloison pl-classe | R+1 | Mur (Classification ARCHICAD); Element de construction non défini (Classification Archicad) | cloison pl-classe | 20_Cloison________ | Salle de classe 9 | R+1 | 1 | _Panneau-mélaminé | _Panneau-mélaminé | Face extérieure | Mur
2 x cloison pl-classe | R+1 | Mur (Classification ARCHICAD); Element de construction non défini (Classification Archicad) | cloison pl-classe | 20_Cloison________ | Salle de classe 8 | R+1 | 1 | _Peinture - Blanc brillant; _Panneau-mélaminé | _Panneau-mélaminé | Face extérieure | Mur
cloison pl-classe | R+1 | Mur (Classification ARCHICAD); Element de construction non défini (Classification Archicad) | cloison pl-classe | 20_Cloison________ | Salle de classe 7 | R+1 | 1 | _Panneau-mélaminé | _Panneau-mélaminé | Face extérieure | Mur
cloison pl-classe | R+1 | Mur (Classification ARCHICAD); Element de construction non défini (Classification Archicad) | cloison pl-classe | 20_Cloison________ | Salle de classe 6 | R+1 | 1 | _Peinture - Blanc brillant; _Panneau-mélaminé | _Panneau-mélaminé | Face extérieure | Mur
cloison pl-classe | R+1 | Mur (Classification ARCHICAD); Element de construction non défini (Classification Archicad) | cloison pl-classe | 20_Cloison________ | Salle de classe 6 | R+1 | 1 | _Panneau-mélaminé | _Panneau-mélaminé | Face extérieure | Mur
2 x raidiseur-sous-tableau | R+1 | Element de construction non défini (Classification Archicad); Mobilier (Classification ARCHICAD) | raidiseur-sous-tableau | 20_Men Int________ | Salle de classe 8 | R+1 | 1 | _Mur int blanc | _Mur int blanc | Centre | Mobilier
2 x cloison pl-classe | R+1 | Mur (Classification ARCHICAD); Element de construction non défini (Classification Archicad) | cloison pl-classe | 20_Cloison________ | Salle de classe 6 | R+1 | 1 | _Peinture - Blanc brillant; _Panneau-mélaminé | _Panneau-mélaminé | Centre | Mur
4 x cloison pl-classe | R+1 | Mur (Classification ARCHICAD); Element de construction non défini (Classification Archicad) | cloison pl-classe | 20_Men Int________ | Salle de classe 8 | R+1 | 1 | _Peinture - Blanc brillant; _Panneau-mélaminé | _Panneau-mélaminé | Centre | Mur
2 x cloison pl-classe | R+1 | Mur (Classification ARCHICAD); Element de construction non défini (Classification Archicad) | cloison pl-classe | 20_Cloison________ | Salle de classe 10 | R+1 | 1 | _Peinture - Blanc brillant; _Panneau-mélaminé | _Panneau-mélaminé | Centre | Mur
2 x cloison pl-classe | R+1 | Mur (Classification ARCHICAD); Element de construction non défini (Classification Archicad) | cloison pl-classe | 20_Cloison________ | Salle de classe 9 | R+1 | 1 | _Peinture - Blanc brillant; _Panneau-mélaminé | _Panneau-mélaminé | Centre | Mur
4 x cloison pl-classe | R+1 | Mur (Classification ARCHICAD); Element de construction non défini (Classification Archicad) | cloison pl-classe | 20_Men Int________ | Salle de classe 9 | R+1 | 1 | _Peinture - Blanc brillant; _Panneau-mélaminé | _Panneau-mélaminé | Centre | Mur
4 x cloison pl-classe | R+1 | Mur (Classification ARCHICAD); Element de construction non défini (Classification Archicad) | cloison pl-classe | 20_Men Int________ | Salle de classe 10 | R+1 | 1 | _Peinture - Blanc brillant; _Panneau-mélaminé | _Panneau-mélaminé | Centre | Mur
4 x cloison pl-classe | R+1 | Mur (Classification ARCHICAD); Element de construction non défini (Classification Archicad) | cloison pl-classe | 20_Men Int________ | Salle de classe 7 | R+1 | 1 | _Peinture - Blanc brillant; _Panneau-mélaminé | _Panneau-mélaminé | Centre | Mur
2 x cloison pl-classe | R+1 | Mur (Classification ARCHICAD); Element de construction non défini (Classification Archicad) | cloison pl-classe | 20_Cloison________ | Salle de classe 7 | R+1 | 1 | _Peinture - Blanc brillant; _Panneau-mélaminé | _Panneau-mélaminé | Centre | Mur
2 x raidiseur-fd-classe simple | R+1 | Element de construction non défini (Classification Archicad); Mobilier (Classification ARCHICAD) | raidiseur-fd-classe simple | 20_Men Int________ | Salle de classe 6 | R+1 | 1 | _Mur int blanc | _Mur int blanc | Face intérieure | Mobilier
2 x raidiseur-fd-classe simple | R+1 | Element de construction non défini (Classification Archicad); Mobilier (Classification ARCHICAD) | raidiseur-fd-classe simple | 20_Men Int________ | Salle de classe 7 | R+1 | 1 | _Mur int blanc; _Peinture - Blanc brillant | _Mur int blanc | Face intérieure | Mobilier
2 x raidiseur-fd-classe simple | R+1 | Element de construction non défini (Classification Archicad); Mobilier (Classification ARCHICAD) | raidiseur-fd-classe simple | 20_Men Int________ | Salle de classe 8 | R+1 | 1 | _Mur int blanc | _Mur int blanc | Face intérieure | Mobilier
2 x raidiseur-fd-classe simple | R+1 | Element de construction non défini (Classification Archicad); Mobilier (Classification ARCHICAD) | raidiseur-fd-classe simple | 20_Men Int________ | Salle de classe 10 | R+1 | 1 | _Mur int blanc; _Peinture - Blanc brillant | _Mur int blanc | Face intérieure | Mobilier
2 x raidiseur-fd-classe simple | R+1 | Element de construction non défini (Classification Archicad); Mobilier (Classification ARCHICAD) | raidiseur-fd-classe simple | 20_Men Int________ | Salle de classe 9 | R+1 | 1 | _Mur int blanc | _Mur int blanc | Face intérieure | Mobilier
2 x raidiseur-sous-tableau | R+1 | Element de construction non défini (Classification Archicad); Mobilier (Classification ARCHICAD) | raidiseur-sous-tableau | 20_Men Int________ | Salle de classe 6 | R+1 | 1 | _Mur int blanc | _Mur int blanc | Centre | Mobilier
2 x raidiseur-sous-tableau | R+1 | Element de construction non défini (Classification Archicad); Mobilier (Classification ARCHICAD) | raidiseur-sous-tableau | 20_Men Int________ | Salle de classe 9 | R+1 | 1 | _Mur int blanc | _Mur int blanc | Centre | Mobilier
2 x raidiseur-sous-tableau | R+1 | Element de construction non défini (Classification Archicad); Mobilier (Classification ARCHICAD) | raidiseur-sous-tableau | 20_Men Int________ | Salle de classe 10 | R+1 | 1 | _Mur int blanc | _Mur int blanc | Centre | Mobilier
2 x raidiseur-sous-tableau | R+1 | Element de construction non défini (Classification Archicad); Mobilier (Classification ARCHICAD) | raidiseur-sous-tableau | 20_Men Int________ | Salle de classe 7 | R+1 | 1 | _Mur int blanc | _Mur int blanc | Centre | Mobilier
cloison-fd-classe D | R+1 | Mur (Classification ARCHICAD); Element de construction non défini (Classification Archicad) | cloison-fd-classe D | 20_Men Int________ | Salle de classe 7 | R+1 | 1 | _Panneau-mélaminé | _Panneau-mélaminé | Face extérieure | Mur
cloison-fd-classe G | R+1 | Mur (Classification ARCHICAD); Element de construction non défini (Classification Archicad) | cloison-fd-classe G | 20_Men Int________ | Salle de classe 7 | R+1 | 1 | _Peinture - Blanc brillant; _Panneau-mélaminé | _Panneau-mélaminé | Face extérieure | Mur
cloison-fd-classe G | R+1 | Mur (Classification ARCHICAD); Element de construction non défini (Classification Archicad) | cloison-fd-classe G | 20_Men Int________ | Salle de classe 6 | R+1 | 1 | _Panneau-mélaminé | _Panneau-mélaminé | Face extérieure | Mur
cloison-fd-classe D | R+1 | Mur (Classification ARCHICAD); Element de construction non défini (Classification Archicad) | cloison-fd-classe D | 20_Men Int________ | Salle de classe 6 | R+1 | 1 | _Panneau-mélaminé | _Panneau-mélaminé | Face extérieure | Mur

# IfcBuildingElementProxy: _panneau mélaminé 38 (30)
Classification: Element de construction non défini (Classification Archicad); Mobilier (Classification ARCHICAD); Material: _panneau mélaminé
ArchiCADProperties - ID de l'élément: raidiseur-fd-classe double; Lien et ID d'élément: raidiseur-fd-classe double; Calque: 20_Men Int________; Matériau de construction / Composite / Profil / Hachure: _panneau mélaminé; Matériau de construction: _panneau mélaminé; Verrouillé: no; Type d'élément: Mur; Étage supérieur lié absolu: Non lié; Étage supérieur lié relatif: Non lié; Étage supérieur lié: Non lié; Type de structure: Basique; ID de Parent: raidiseur-fd-classe double; Matériaux de construction (Tous): _panneau mélaminé; Angle d'inclinaison: 90 deg; Nombre de percements: 0; Surface latérale: _Panneau-mélaminé; Position: Intérieur; État de rénovation: Existant; Affichage sur filtre de rénovation: Tous les filtres appropriés; Fonction structurelle: Élément non porteur; Complexité de mur: Droit; Option de géométrie: Uniforme; Emplacement de ligne de référence: Centre; Surface de face intérieure: _Panneau-mélaminé; Surface de face extérieure: _Panneau-mélaminé; Angle d'inclinaison interne de mur: 90 deg; Angle d'inclinaison externe de mur: 90 deg; Classification ARCHICAD - 21: Mobilier
AC_Pset_RenovationAndPhasing - Renovation Status: Existing
Name | In | Zones conflictuelles = Nom de zone liée | Nom d'étage d'implantation | Numéro d'étage d'implantation | Surfaces (Toutes)
2 x raidiseur-fd-classe double | RDC | Salle de classe 1 | RDC | 0 | _Panneau-mélaminé
raidiseur-fd-classe double | RDC | Salle de classe 1 | RDC | 0 | _Peinture - Blanc brillant; _Panneau-mélaminé
3 x raidiseur-fd-classe double | RDC | Salle de classe 5 | RDC | 0 | _Peinture - Blanc brillant; _Panneau-mélaminé
3 x raidiseur-fd-classe double | RDC | Salle de classe 2 | RDC | 0 | _Peinture - Blanc brillant; _Panneau-mélaminé
raidiseur-fd-classe double | RDC | Salle de classe 3 | RDC | 0 | _Peinture - Blanc brillant; _Panneau-mélaminé
2 x raidiseur-fd-classe double | RDC | Salle de classe 3 | RDC | 0 | _Panneau-mélaminé
raidiseur-fd-classe double | RDC | Salle de classe 4 | RDC | 0 | _Peinture - Blanc brillant; _Panneau-mélaminé
2 x raidiseur-fd-classe double | RDC | Salle de classe 4 | RDC | 0 | _Panneau-mélaminé
2 x raidiseur-fd-classe double | R+1 | Salle de classe 6 | R+1 | 1 | _Panneau-mélaminé
raidiseur-fd-classe double | R+1 | Salle de classe 6 | R+1 | 1 | _Peinture - Blanc brillant; _Panneau-mélaminé
3 x raidiseur-fd-classe double | R+1 | Salle de classe 7 | R+1 | 1 | _Peinture - Blanc brillant; _Panneau-mélaminé
raidiseur-fd-classe double | R+1 | Salle de classe 8 | R+1 | 1 | _Peinture - Blanc brillant; _Panneau-mélaminé
2 x raidiseur-fd-classe double | R+1 | Salle de classe 8 | R+1 | 1 | _Panneau-mélaminé
3 x raidiseur-fd-classe double | R+1 | Salle de classe 10 | R+1 | 1 | _Peinture - Blanc brillant; _Panneau-mélaminé
raidiseur-fd-classe double | R+1 | Salle de classe 9 | R+1 | 1 | _Peinture - Blanc brillant; _Panneau-mélaminé
2 x raidiseur-fd-classe double | R+1 | Salle de classe 9 | R+1 | 1 | _Panneau-mélaminé

# IfcBuildingElementProxy: _panneau mélaminé 40 (30)
Classification: Mur (Classification ARCHICAD); Element de construction non défini (Classification Archicad); Material: _panneau mélaminé
ArchiCADProperties - Calque: 20_Men Int________; Matériau de construction / Composite / Profil / Hachure: _panneau mélaminé; Matériau de construction: _panneau mélaminé; Verrouillé: no; Type d'élément: Mur; Étage supérieur lié absolu: Non lié; Étage supérieur lié relatif: Non lié; Étage supérieur lié: Non lié; Type de structure: Basique; Matériaux de construction (Tous): _panneau mélaminé; Angle d'inclinaison: 90 deg; Nombre de percements: 0; Surface latérale: _Panneau-mélaminé; Position: Intérieur; État de rénovation: Existant; Affichage sur filtre de rénovation: Tous les filtres appropriés; Fonction structurelle: Élément non porteur; Complexité de mur: Droit; Option de géométrie: Uniforme; Emplacement de ligne de référence: Face extérieure; Surface de face intérieure: _Panneau-mélaminé; Surface de face extérieure: _Panneau-mélaminé; Angle d'inclinaison interne de mur: 90 deg; Angle d'inclinaison externe de mur: 90 deg; Classification ARCHICAD - 21: Mur
AC_Pset_RenovationAndPhasing - Renovation Status: Existing
Name | In | ID de l'élément = Lien et ID d'élément = ID de Parent | Zones conflictuelles = Nom de zone liée | Nom d'étage d'implantation | Numéro d'étage d'implantation | Surfaces (Toutes)
tableau-classe | RDC | tableau-classe | Salle de classe 3 | RDC | 0 | _Peinture - Blanc brillant; _Panneau-mélaminé
tableau-classe | RDC | tableau-classe | Salle de classe 4 | RDC | 0 | _Peinture - Blanc brillant; _Panneau-mélaminé
cloison-fd-classe G | RDC | cloison-fd-classe G | Salle de classe 1 | RDC | 0 | _Peinture - Blanc brillant; _Panneau-mélaminé
cloison-fd-classe D | RDC | cloison-fd-classe D | Salle de classe 1 | RDC | 0 | _Panneau-mélaminé
tableau-classe | RDC | tableau-classe | Salle de classe 5 | RDC | 0 | _Peinture - Blanc brillant; _Panneau-mélaminé
tableau-classe | RDC | tableau-classe | Salle de classe 1 | RDC | 0 | _Peinture - Blanc brillant; _Panneau-mélaminé
tableau-classe | RDC | tableau-classe | Salle de classe 2 | RDC | 0 | _Peinture - Blanc brillant; _Panneau-mélaminé
cloison-fd-classe G | RDC | cloison-fd-classe G | Salle de classe 5 | RDC | 0 | _Peinture - Blanc brillant; _Panneau-mélaminé
cloison-fd-classe D | RDC | cloison-fd-classe D | Salle de classe 5 | RDC | 0 | _Peinture - Blanc brillant; _Panneau-mélaminé
cloison-fd-classe D | RDC | cloison-fd-classe D | Salle de classe 2 | RDC | 0 | _Peinture - Blanc brillant; _Panneau-mélaminé
cloison-fd-classe G | RDC | cloison-fd-classe G | Salle de classe 2 | RDC | 0 | _Peinture - Blanc brillant; _Panneau-mélaminé
cloison-fd-classe D | RDC | cloison-fd-classe D | Salle de classe 3 | RDC | 0 | _Panneau-mélaminé
cloison-fd-classe G | RDC | cloison-fd-classe G | Salle de classe 3 | RDC | 0 | _Peinture - Blanc brillant; _Panneau-mélaminé
cloison-fd-classe D | RDC | cloison-fd-classe D | Salle de classe 4 | RDC | 0 | _Panneau-mélaminé
cloison-fd-classe G | RDC | cloison-fd-classe G | Salle de classe 4 | RDC | 0 | _Peinture - Blanc brillant; _Panneau-mélaminé
tableau-classe | R+1 | tableau-classe | Salle de classe 8 | R+1 | 1 | _Peinture - Blanc brillant; _Panneau-mélaminé
cloison-fd-classe D | R+1 | cloison-fd-classe D | Salle de classe 8 | R+1 | 1 | _Panneau-mélaminé
cloison-fd-classe G | R+1 | cloison-fd-classe G | Salle de classe 8 | R+1 | 1 | _Peinture - Blanc brillant; _Panneau-mélaminé
cloison-fd-classe G | R+1 | cloison-fd-classe G | Salle de classe 10 | R+1 | 1 | _Peinture - Blanc brillant; _Panneau-mélaminé
cloison-fd-classe D | R+1 | cloison-fd-classe D | Salle de classe 10 | R+1 | 1 | _Peinture - Blanc brillant; _Panneau-mélaminé
cloison-fd-classe D | R+1 | cloison-fd-classe D | Salle de classe 9 | R+1 | 1 | _Panneau-mélaminé
cloison-fd-classe G | R+1 | cloison-fd-classe G | Salle de classe 9 | R+1 | 1 | _Peinture - Blanc brillant; _Panneau-mélaminé
tableau-classe | R+1 | tableau-classe | Salle de classe 9 | R+1 | 1 | _Peinture - Blanc brillant; _Panneau-mélaminé
tableau-classe | R+1 | tableau-classe | Salle de classe 10 | R+1 | 1 | _Peinture - Blanc brillant; _Panneau-mélaminé
tableau-classe | R+1 | tableau-classe | Salle de classe 6 | R+1 | 1 | _Peinture - Blanc brillant; _Panneau-mélaminé
tableau-classe | R+1 | tableau-classe | Salle de classe 7 | R+1 | 1 | _Peinture - Blanc brillant; _Panneau-mélaminé
cloison-fd-classe G | R+1 | cloison-fd-classe G | Salle de classe 7 | R+1 | 1 | _Peinture - Blanc brillant; _Panneau-mélaminé
cloison-fd-classe D | R+1 | cloison-fd-classe D | Salle de classe 7 | R+1 | 1 | _Peinture - Blanc brillant; _Panneau-mélaminé
cloison-fd-classe D | R+1 | cloison-fd-classe D | Salle de classe 6 | R+1 | 1 | _Panneau-mélaminé
cloison-fd-classe G | R+1 | cloison-fd-classe G | Salle de classe 6 | R+1 | 1 | _Peinture - Blanc brillant; _Panneau-mélaminé

# IfcBuildingElementProxy: _terrasse-accessible 150, lames-composites
In: R+1
Classification: Element de construction non défini (Classification Archicad); Plafond (Classification ARCHICAD); Material: _lames-composites
ArchiCADProperties - ID de l'élément: lames-composites; Lien et ID d'élément: lames-composites; Calque: 10_Plancher_Sol__.3CF; Matériau de construction / Composite / Profil / Hachure: _terrasse-accessible; Structure Composite: _terrasse-accessible; Verrouillé: no; Nom d'étage d'implantation: R+1; Numéro d'étage d'implantation: 1; Type d'élément: Dalle; Type de structure: Composite; ID de Parent: lames-composites; Matériaux de construction (Tous): _lames-composites; _Vide (300); _Etanchéité 2; Surfaces (Toutes): _Air - Vide d'air; _Enduit minéral blanc; _Etanchéité - Membrane souple; _Bardage Bois Vertical; _INVISIBLE_; _Bardage Bois-Horiz ocre; Hachure de recouvrement: Dallage 60x60; Nombre de percements: 0; Surface supérieure: _Bardage Bois Vertical; Surface inférieure: _INVISIBLE_; Position: Intérieur; État de rénovation: Existant; Affichage sur filtre de rénovation: Tous les filtres appropriés; Fonction structurelle: Élément non porteur; Emplacement de plan de référence: Bas; Classification ARCHICAD - 21: Plafond
AC_Pset_RenovationAndPhasing - Renovation Status: Existing

# IfcBuildingElementProxy: porte-couliss-triple_JM2 (20)
Classification: Element de construction non défini (Classification Archicad); Porte (Classification ARCHICAD); Material: Matériau de construction IFC
Pset_FireRatingProperties - FireResistanceRating: CF 1/2H
ArchiCADProperties - Nom Élément de Bibliothèque: porte-couliss-triple_JM2; Matériau de construction / Composite / Profil / Hachure: Sans Trame; Type Hachure: Sans Trame; Verrouillé: no; Type d'élément: Porte; Position: Non défini; État de rénovation: Existant; Affichage sur filtre de rénovation: Tous les filtres appropriés; Fonction structurelle: Non défini; Orientation: G; Nom élément de bibliothèque d'ouverture: porte-couliss-triple_JM2; Index hachure latérale ouverture: Sans Trame; Classification ARCHICAD - 21: Porte
AC_Pset_porte-couliss-triple_JM2 - Contours Mur (0-Sans,1-Tout,2-Côté,3-Longueur): 2; Point ch.0-Non,1-2D,2-3D,3-Tous: 3; Points chauds auto. en 3D: yes; Trou reprend surface latérale de mur: yes; Division de surface du trou courbe dans murs courbes: no; test: no; Panneau perso (perso1): no; Nom du battant perso (pano_perso1): battant de porte 1; Panneau perso (perso2): no; Nom du battant perso (pano_perso2): battant de porte 1; Panneau perso (perso3): no; Nom du battant perso (pano_perso3): battant de porte 3; Angle ouverture en 2D: 90 deg; Stylo contour: Ouvertures - 0; Stylo coupe: Ouvertures - Coupé non structurel; Afficher rails: no; Angle ouverture en 3D: 0 deg; Stylo 3D: Eléments 2D - Général; Stylo cadre: Eléments 2D - Général; Stylo panneaux: Eléments 2D - Général; Huisserie (gs_frame_mat): _Huisserie-int; Cadre coulissant 1: _Huisserie-int; Cadre coulissant 2: _Huisserie-int; Panneau bas 2: _Panneau-mélaminé; Panneau principal 2: _Panneau-mélaminé; Cadre coulissant 3: _Huisserie-int; Panneau bas 3: _Mur int blanc; Panneau principal 3: _Mur int blanc; Opération IFC (ifc_optypestr): Non défini; Opération IFC (ifc_optype): 0
AC_Pset_RenovationAndPhasing - Renovation Status: Existing
Name | In | ID de l'élément = Lien et ID d'élément | Calque | Zones conflictuelles = Nom de zone liée = De Zone = À Zone | Nom d'étage d'implantation | Numéro d'étage d'implantation | ID de Parent | Surfaces (Toutes) | Taille L x H nominale | Taille L x H x E nominale | Structure de Mur | Trou (0,1,2) (+2=rond) = Trou (poignée) 0,1,2 (trou3) | Coulissant 2 = idem = Coulissant 3 = idem | Trou (poignée) 0,1,2 (trou2) | Panneau bas 1 = Panneau principal 1
coulissant-classe | RDC | coulissant-classe | 20_Cloison________ | Salle de classe 1 | RDC | 0 | clois face pl-classe | _Mur int blanc; _Huisserie-int; _grille-hall noir | 797×210 | 797×210×8 | _Cloison tableau | 0 | no | 0 | _grille-hall noir
coulissant-classe | RDC | coulissant-classe | 20_Cloison________ | Salle de classe 5 | RDC | 0 | clois face pl-classe | _Mur int blanc; _Huisserie-int; _grille-hall noir | 797×210 | 797×210×8 | _Cloison tableau | 0 | no | 0 | _grille-hall noir
couliss-tableau-classe | RDC | couliss-tableau-classe | 20_Men Int________ | Salle de classe 3 | RDC | 0 | clois sous-tableau-classe | _Huisserie-int; _Panneau-mélaminé | 269×65 | 269×65×7 | _Percement (999) | 4 | yes | 1 | _Panneau-mélaminé
couliss-tableau-classe | RDC | couliss-tableau-classe | 20_Men Int________ | Salle de classe 4 | RDC | 0 | clois sous-tableau-classe | _Huisserie-int; _Panneau-mélaminé | 269×65 | 269×65×7 | _Percement (999) | 4 | yes | 1 | _Panneau-mélaminé
coulissant-classe | RDC | coulissant-classe | 20_Cloison________ | Salle de classe 3 | RDC | 0 | clois face pl-classe | _Mur int blanc; _Huisserie-int; _grille-hall noir | 797×210 | 797×210×8 | _Cloison tableau | 0 | no | 0 | _grille-hall noir
couliss-tableau-classe | RDC | couliss-tableau-classe | 20_Men Int________ | Salle de classe 5 | RDC | 0 | clois sous-tableau-classe | _Huisserie-int; _Panneau-mélaminé | 269×65 | 269×65×7 | _Percement (999) | 4 | yes | 1 | _Panneau-mélaminé
coulissant-classe | RDC | coulissant-classe | 20_Cloison________ | Salle de classe 2 | RDC | 0 | clois face pl-classe | _Mur int blanc; _Huisserie-int; _grille-hall noir | 797×210 | 797×210×8 | _Cloison tableau | 0 | no | 0 | _grille-hall noir
coulissant-classe | RDC | coulissant-classe | 20_Cloison________ | Salle de classe 4 | RDC | 0 | clois face pl-classe | _Mur int blanc; _Huisserie-int; _grille-hall noir | 797×210 | 797×210×8 | _Cloison tableau | 0 | no | 0 | _grille-hall noir
couliss-tableau-classe | RDC | couliss-tableau-classe | 20_Men Int________ | Salle de classe 2 | RDC | 0 | clois sous-tableau-classe | _Huisserie-int; _Panneau-mélaminé | 269×65 | 269×65×7 | _Percement (999) | 4 | yes | 1 | _Panneau-mélaminé
couliss-tableau-classe | RDC | couliss-tableau-classe | 20_Men Int________ | Salle de classe 1 | RDC | 0 | clois sous-tableau-classe | _Huisserie-int; _Panneau-mélaminé | 269×65 | 269×65×7 | _Percement (999) | 4 | yes | 1 | _Panneau-mélaminé
coulissant-classe | R+1 | coulissant-classe | 20_Cloison________ | Salle de classe 6 | R+1 | 1 | clois face pl-classe | _Mur int blanc; _Huisserie-int; _grille-hall noir | 797×210 | 797×210×8 | _Cloison tableau | 0 | no | 0 | _grille-hall noir
coulissant-classe | R+1 | coulissant-classe | 20_Cloison________ | Salle de classe 9 | R+1 | 1 | clois face pl-classe | _Mur int blanc; _Huisserie-int; _grille-hall noir | 797×210 | 797×210×8 | _Cloison tableau | 0 | no | 0 | _grille-hall noir
coulissant-classe | R+1 | coulissant-classe | 20_Cloison________ | Salle de classe 10 | R+1 | 1 | clois face pl-classe | _Mur int blanc; _Huisserie-int; _grille-hall noir | 797×210 | 797×210×8 | _Cloison tableau | 0 | no | 0 | _grille-hall noir
coulissant-classe | R+1 | coulissant-classe | 20_Cloison________ | Salle de classe 7 | R+1 | 1 | clois face pl-classe | _Mur int blanc; _Huisserie-int; _grille-hall noir | 797×210 | 797×210×8 | _Cloison tableau | 0 | no | 0 | _grille-hall noir
coulissant-classe | R+1 | coulissant-classe | 20_Cloison________ | Salle de classe 8 | R+1 | 1 | clois face pl-classe | _Mur int blanc; _Huisserie-int; _grille-hall noir | 797×210 | 797×210×8 | _Cloison tableau | 0 | no | 0 | _grille-hall noir
couliss-tableau-classe | R+1 | couliss-tableau-classe | 20_Men Int________ | Salle de classe 8 | R+1 | 1 | clois sous-tableau-classe | _Huisserie-int; _Panneau-mélaminé | 269×65 | 269×65×7 | _Percement (999) | 4 | yes | 1 | _Panneau-mélaminé
couliss-tableau-classe | R+1 | couliss-tableau-classe | 20_Men Int________ | Salle de classe 9 | R+1 | 1 | clois sous-tableau-classe | _Huisserie-int; _Panneau-mélaminé | 269×65 | 269×65×7 | _Percement (999) | 4 | yes | 1 | _Panneau-mélaminé
couliss-tableau-classe | R+1 | couliss-tableau-classe | 20_Men Int________ | Salle de classe 10 | R+1 | 1 | clois sous-tableau-classe | _Huisserie-int; _Panneau-mélaminé | 269×65 | 269×65×7 | _Percement (999) | 4 | yes | 1 | _Panneau-mélaminé
couliss-tableau-classe | R+1 | couliss-tableau-classe | 20_Men Int________ | Salle de classe 7 | R+1 | 1 | clois sous-tableau-classe | _Huisserie-int; _Panneau-mélaminé | 269×65 | 269×65×7 | _Percement (999) | 4 | yes | 1 | _Panneau-mélaminé
couliss-tableau-classe | R+1 | couliss-tableau-classe | 20_Men Int________ | Salle de classe 6 | R+1 | 1 | clois sous-tableau-classe | _Huisserie-int; _Panneau-mélaminé | 269×65 | 269×65×7 | _Percement (999) | 4 | yes | 1 | _Panneau-mélaminé

# IfcColumn: Bois - Equarri 02 50 x 50 (2)
In: R+1
Classification: Poteau (Classification ARCHICAD); Poteau (Classification Archicad); Material: Bois - Equarri 02
ArchiCADProperties - ID de l'élément: tasseau pare-vue; Lien et ID d'élément: tasseau pare-vue; Calque: 10_M x baseGO__; Matériau de construction / Composite / Profil / Hachure: Bois - Equarri 02; Matériau de construction: Bois - Equarri 02; Zones conflictuelles: Terrasse; Nom de zone liée: Terrasse; Verrouillé: no; Nom d'étage d'implantation: R+1; Numéro d'étage d'implantation: 1; Type d'élément: Poteau; Étage supérieur lié absolu: Non lié; Étage supérieur lié relatif: Non lié; Étage supérieur lié: Non lié; Type de structure: Basique; ID de Parent: tasseau pare-vue; Matériaux de construction (Tous): Bois - Equarri 02; Surfaces (Toutes): _Bois - Pin granuleux vertical; Hachure de recouvrement: Sans Trame (3); Angle d'inclinaison: 90 deg; État de rénovation: Existant; Affichage sur filtre de rénovation: Tous les filtres appropriés; Fonction structurelle: Élément non porteur; Coupe transversale de Poteau: Rectangulaire; Angle d'inclinaison de Poteau: 90 deg; Surface d'extrusion: _Bois - Pin granuleux vertical; Surface de fin: _Bois - Pin granuleux vertical; Classification ARCHICAD - 20: Poteau
Pset_ColumnCommon - Reference: Bois - Equarri 02 50 x 50; Slope: 90 deg; IsExternal: yes; LoadBearing: no
AC_Pset_RenovationAndPhasing - Renovation Status: Existing
Name | Position
tasseau pare-vue | Extérieur
tasseau pare-vue | Non défini

# IfcColumn: _BA banché D250 (3)
In: RDC
Classification: Poteau (Classification ARCHICAD); Poteau (Classification Archicad); Material: _BA banché
ArchiCADProperties - ID de l'élément: Poteau preau; Lien et ID d'élément: Poteau preau; Calque: 10_M x baseGO__; Matériau de construction / Composite / Profil / Hachure: _BA banché; Matériau de construction: _BA banché; Verrouillé: no; Nom d'étage d'implantation: RDC; Numéro d'étage d'implantation: 0; Type d'élément: Poteau; Étage supérieur lié absolu: R+1; Étage supérieur lié relatif: Étage d'implantation + 1; Étage supérieur lié: Étage d'implantation + 1 (R+1); Type de structure: Basique; ID de Parent: Poteau preau; Matériaux de construction (Tous): _BA banché; Surfaces (Toutes): _Enduit minéral blanc; Hachure de recouvrement: Sans Trame (3); Angle d'inclinaison: 90 deg; Position: Non défini; État de rénovation: Existant; Affichage sur filtre de rénovation: Tous les filtres appropriés; Fonction structurelle: Élément porteur; Coupe transversale de Poteau: Circulaire; Angle d'inclinaison de Poteau: 90 deg; Surface d'extrusion: _Enduit minéral blanc; Surface de fin: _Enduit minéral blanc; Génération de modèle analytique structurel: yes; Classification ARCHICAD - 20: Poteau
Pset_ColumnCommon - Reference: _BA banché D250; Slope: 90 deg; IsExternal: yes; LoadBearing: yes
AC_Pset_RenovationAndPhasing - Renovation Status: Existing

# IfcCurtainWall: Type de mur-rideau (2)
In: R+1
Classification: Mur-rideau (Classification ARCHICAD)
ArchiCADProperties - ID de l'élément: pare-vue CTA; Lien et ID d'élément: pare-vue CTA; Calque: 10_M x baseGO__; Zones conflictuelles: Terrasse; Verrouillé: no; Nom d'étage d'implantation: R+1; Numéro d'étage d'implantation: 1; Type d'élément: Mur-rideau; ID de Parent: pare-vue CTA; Matériaux de construction (Tous): _Acier; Angle d'inclinaison: 90 deg; Position: Extérieur; État de rénovation: Existant; Affichage sur filtre de rénovation: Tous les filtres appropriés; Fonction structurelle: Élément non porteur; Angle de motif: 90 deg; Angle d'inclinaison de mur-rideau: 90 deg; Classification ARCHICAD - 20: Mur-rideau
AC_Pset_RenovationAndPhasing - Renovation Status: Existing
Pset_CurtainWallCommon - IsExternal: yes
Name | Surfaces (Toutes)
pare-vue CTA | _Men ext_RAL9007; _Métal - Acier; _INVISIBLE_; _Bois-Horiz ocre | ArchiCADProperties - Nom de zone liée: Terrasse
pare-vue CTA | _Métal - Acier; _Bois-Horiz ocre

# IfcDiscreteAccessory: Sphère 21 (40)
Classification: Accessoire distinct (Classification ARCHICAD); Accessoire composé (Classification Archicad); Material: Matériau de construction IFC
ArchiCADProperties - ID de l'élément: roulette-tiroir; Lien et ID d'élément: roulette-tiroir; Calque: 21_Agencemt_____; Nom Élément de Bibliothèque: Sphère 21; Matériau de construction / Composite / Profil / Hachure: Sans Trame; Type Hachure: Sans Trame; Verrouillé: no; Type d'élément: Objet; ID de Parent: roulette-tiroir; Surfaces (Toutes): _Métal - Aluminium naturel; Position: Non défini; État de rénovation: Existant; Affichage sur filtre de rénovation: Tous les filtres appropriés; Fonction structurelle: Non défini; Angle de rotation: 90 deg; Surface: _Peinture - Ocre jaune; Classification ARCHICAD - 20: Accessoire distinct
AC_Pset_Sphère_21 - 3D: 2; Résolution: 36; Ombre: yes; Afficher points chauds 2D en 3D: yes; Stylo contour: Eléments 2D - Général; Motif de hachure: Sans Trame; Stylo hachure: Fond - Couleur 1; Stylo fond de hachure: Fond - Couleur 1; Sphère: _Métal - Aluminium naturel; Coût: 0; Type de groupe (FM_Type): Autres; Type de groupe (iFMType): 25; Poids de l'objet: 0; Unité poids de l'objet: kg
AC_Pset_RenovationAndPhasing - Renovation Status: Existing
Name | In | Nom de zone liée | Nom d'étage d'implantation | Numéro d'étage d'implantation
4 x roulette-tiroir | RDC | Salle de classe 1 | RDC | 0
4 x roulette-tiroir | RDC | Salle de classe 5 | RDC | 0
4 x roulette-tiroir | RDC | Salle de classe 2 | RDC | 0
4 x roulette-tiroir | RDC | Salle de classe 3 | RDC | 0
4 x roulette-tiroir | RDC | Salle de classe 4 | RDC | 0
4 x roulette-tiroir | R+1 | Salle de classe 8 | R+1 | 1
4 x roulette-tiroir | R+1 | Salle de classe 6 | R+1 | 1
4 x roulette-tiroir | R+1 | Salle de classe 7 | R+1 | 1
4 x roulette-tiroir | R+1 | Salle de classe 10 | R+1 | 1
4 x roulette-tiroir | R+1 | Salle de classe 9 | R+1 | 1

# IfcFurnishingElement: Banc-couloir (10)
Type - ElementType: SYSTEM_FURNITURE
Classification: Mobilier (Classification ARCHICAD); Elément d'ameublement (Classification Archicad); Material: _Bois contreplaqué
ArchiCADProperties - ID de l'élément: banc-couloir; Lien et ID d'élément: banc-couloir; Calque: 20_Men Int________; Nom Élément de Bibliothèque: Banc-couloir; Matériau de construction / Composite / Profil / Hachure: Sans Trame; Type Hachure: Sans Trame; Verrouillé: no; Type d'élément: Objet; ID de Parent: banc-couloir; Matériaux de construction (Tous): _Bois contreplaqué; _menuiserie alu; Surfaces (Toutes): _Men ext_RAL9007; _Bois vestiaire; Position: Non défini; État de rénovation: Existant; Affichage sur filtre de rénovation: Tous les filtres appropriés; Fonction structurelle: Non défini; Angle de rotation: 0 deg; Surface: _Peinture-11; Classification ARCHICAD - 20: Mobilier
AC_Pset_Banc-couloir - Afficher points chauds 2D en 3D: yes; Utiliser environnement mémorisé: no; Suppr consoles en 2D: yes; Hachure consoles: Sans Trame; Hachure assise: Sans Trame; Ligne 1: 1; Assise (materialAttribute_1): _Bois vestiaire; Consoles (materialAttribute_2): _Men ext_RAL9007; Contour assise: Eléments 2D - Général; fond hach assise: Général - fonds de hachures; Contour consoles: Menuis; fond hach consoles: Général - fonds de hachures; Stylo 1: vitrage; Stylo 5: Jaune; Stylo 7: Fond - Couleur 1; Stylo 8: VMC-soufflage; Assise (buildingMatAttribute_1): 75 %; Consoles (buildingMatAttribute_2): 0
AC_Pset_RenovationAndPhasing - Renovation Status: Existing
Name | In | Zones conflictuelles = Nom de zone liée | Nom d'étage d'implantation | Numéro d'étage d'implantation
5 x banc-couloir | RDC | Circulation 1 | RDC | 0
2 x banc-couloir | R+1 | Circulation 2 | R+1 | 1
3 x banc-couloir | R+1 | Circulation 3 | R+1 | 1

# IfcFurnishingElement: Caisson à roulettes 3 21 (40)
Type - ElementType: SYSTEM_FURNITURE
Classification: Mobilier (Classification ARCHICAD); Elément d'ameublement (Classification Archicad); Material: Matériau de construction IFC
ArchiCADProperties - ID de l'élément: tiroirs-classe; Lien et ID d'élément: tiroirs-classe; Calque: 21_Agencemt_____; Nom Élément de Bibliothèque: Caisson à roulettes 3 21; Matériau de construction / Composite / Profil / Hachure: Sans Trame; Type Hachure: Sans Trame; Verrouillé: no; Type d'élément: Objet; ID de Parent: tiroirs-classe; Surfaces (Toutes): _Métal - Acier inoxydable; _Peinture - Blanc brillant; Bois rose; Position: Non défini; État de rénovation: Existant; Affichage sur filtre de rénovation: Tous les filtres appropriés; Fonction structurelle: Non défini; Angle de rotation: 90 deg; Surface: _Peinture - Ocre jaune; Classification ARCHICAD - 20: Mobilier
AC_Pset_Caisson_à_roulettes_3_21 - Niveau de détail 3D: Détaillé; Nbre de tiroirs (0 sans): 5; Biseau arête: no; Base (bBase): no; Bouton (bKnob): yes; Style bouton: 1; Placement bouton: 1; Nbre poignées par tiroir: 1; Tiroir en 2D: no; Symbole 2D: 1; Stylo contour: Eléments 2D - Général; Motif de hachure: Sans Trame; Stylo hachure: Fond - Couleur 1; Stylo fond de hachure: Fond - Couleur 1; Ombre: yes; Résolution: 20; Afficher points chauds 2D en 3D: yes; Meuble: Bois rose; Base (toe_mat): _Métal - Acier inoxydable; Tiroir: _Peinture - Blanc brillant; Bouton (gs_knob_mat): _Métal - Fer; Coût: 0; Type de groupe (FM_Type): Ameublement; Type de groupe (iFMType): 16; Poids de l'objet: 0; Unité poids de l'objet: kg
AC_Pset_RenovationAndPhasing - Renovation Status: Existing
Name | In | Zones conflictuelles = Nom de zone liée | Nom d'étage d'implantation | Numéro d'étage d'implantation
4 x tiroirs-classe | RDC | Salle de classe 5 | RDC | 0
4 x tiroirs-classe | RDC | Salle de classe 1 | RDC | 0
4 x tiroirs-classe | RDC | Salle de classe 2 | RDC | 0
4 x tiroirs-classe | RDC | Salle de classe 3 | RDC | 0
4 x tiroirs-classe | RDC | Salle de classe 4 | RDC | 0
4 x tiroirs-classe | R+1 | Salle de classe 8 | R+1 | 1
4 x tiroirs-classe | R+1 | Salle de classe 6 | R+1 | 1
4 x tiroirs-classe | R+1 | Salle de classe 7 | R+1 | 1
4 x tiroirs-classe | R+1 | Salle de classe 10 | R+1 | 1
4 x tiroirs-classe | R+1 | Salle de classe 9 | R+1 | 1

# IfcFurnishingElement: Chaise d'école 21 (143)
In: RDC
Type - ElementType: SYSTEM_FURNITURE
Classification: Mobilier (Classification ARCHICAD); Elément d'ameublement (Classification Archicad); Material: Matériau de construction IFC
ArchiCADProperties - ID de l'élément: chaise; Lien et ID d'élément: chaise; Calque: 21_Agencemt_____; Nom Élément de Bibliothèque: Chaise d'école 21; Matériau de construction / Composite / Profil / Hachure: Sans Trame; Type Hachure: Sans Trame; Verrouillé: no; Nom d'étage d'implantation: RDC; Numéro d'étage d'implantation: 0; Type d'élément: Objet; ID de Parent: chaise; Position: Non défini; État de rénovation: Existant; Affichage sur filtre de rénovation: Tous les filtres appropriés; Fonction structurelle: Non défini; Surface: _Peinture - Ocre jaune; Classification ARCHICAD - 20: Mobilier
AC_Pset_Chaise_d'école_21 - Afficher points chauds 2D en 3D: no; Niveau de détail 3D: Détaillé; Niveau de détail 2D: Selon échelle; Type de symbole: Rectangle avec dossier 1; Stylo contour: gris moyen (007); Motif de hachure: Sans Trame; Stylo hachure: Fond - Couleur 1; Stylo fond de hachure: Fond - Couleur 1; Résolution: 24; Ombre: yes; Edition points chauds extra: yes; Cadre: _gris satiné; Siège et dossier: _Bois bureaux; Dossier: _Divers - Peau (2); Coût: 0; Type de groupe (FM_Type): Ameublement; Type de groupe (iFMType): 16; Poids de l'objet: 0; Unité poids de l'objet: kg
AC_Pset_RenovationAndPhasing - Renovation Status: Existing
Name | Zones conflictuelles = Nom de zone liée | Surfaces (Toutes) | Angle de rotation (deg) | Base pied
28 x chaise | Salle de classe 4 | _Peinture - Noir; _Bois bureaux; _gris satiné | 90 | _Peinture - Noir
26 x chaise | Salle de classe 1 | _Peinture - Noir; _Bois bureaux; _gris satiné | 90 | _Peinture - Noir
28 x chaise | Salle de classe 3 | _Peinture - Noir; _Bois bureaux; _gris satiné | 90 | _Peinture - Noir
28 x chaise | Salle de classe 5 | _Peinture - Noir; _Bois bureaux; _gris satiné | 90 | _Peinture - Noir
28 x chaise | Salle de classe 2 | _Peinture - Noir; _Bois bureaux; _gris satiné | 90 | _Peinture - Noir
chaise | Salle de classe 3 | _Peinture - Noir; _Bois bureaux; _gris satiné | 270 | _Peinture - Noir
chaise | Salle de classe 5 | _Peinture - Noir; _Bois bureaux; _gris satiné | 270 | _Peinture - Noir
chaise | Salle de classe 1 | _Peinture - Noir; _Bois bureaux; _gris satiné | 270 | _Peinture - Noir
2 x chaise | Salle de classe 1 | _Men ext_RAL9007; _Bois bureaux; _gris satiné | 90 | _Men ext_RAL9007

# IfcFurnishingElement: Râtelier mural 21 (10)
Type - ElementType: SYSTEM_FURNITURE
Classification: Mobilier (Classification ARCHICAD); Elément d'ameublement (Classification Archicad); Material: Matériau de construction IFC
ArchiCADProperties - ID de l'élément: pateres-couloir; Lien et ID d'élément: pateres-couloir; Calque: 20_Men Int________; Nom Élément de Bibliothèque: Râtelier mural 21; Matériau de construction / Composite / Profil / Hachure: Sans Trame; Type Hachure: Sans Trame; Verrouillé: no; Type d'élément: Objet; ID de Parent: pateres-couloir; Surfaces (Toutes): _Men ext_RAL9007; _Bois vestiaire; Position: Non défini; État de rénovation: Existant; Affichage sur filtre de rénovation: Tous les filtres appropriés; Fonction structurelle: Non défini; Angle de rotation: 0 deg; Surface: _Peinture-11; Classification ARCHICAD - 20: Mobilier
AC_Pset_Râtelier_mural_21 - Style: 1; Niveau de détail 3D: 2; Nombre de crochets: 28; Stylo contour: gris moyen (007); Motif de hachure: Sans Trame; Stylo hachure: Fond - Couleur 1; Stylo fond de hachure: Fond - Couleur 1; Résolution: 8; Ombre: no; Afficher points chauds 2D en 3D: yes; Cadre: _Bois vestiaire; Crochet: _Men ext_RAL9007; Coût: 0; Type de groupe (FM_Type): Ameublement; Type de groupe (iFMType): 16; Poids de l'objet: 0; Unité poids de l'objet: kg
AC_Pset_RenovationAndPhasing - Renovation Status: Existing
Name | In | Zones conflictuelles = Nom de zone liée | Nom d'étage d'implantation | Numéro d'étage d'implantation
5 x pateres-couloir | RDC | Circulation 1 | RDC | 0
2 x pateres-couloir | R+1 | Circulation 2 | R+1 | 1
3 x pateres-couloir | R+1 | Circulation 3 | R+1 | 1

# IfcFurnishingElement: Table de bureau 21 (78)
In: RDC
Type - ElementType: SYSTEM_FURNITURE
Classification: Mobilier (Classification ARCHICAD); Elément d'ameublement (Classification Archicad); Material: Matériau de construction IFC
ArchiCADProperties - ID de l'élément: bureau-2pl; Lien et ID d'élément: bureau-2pl; Calque: 21_Agencemt_____; Nom Élément de Bibliothèque: Table de bureau 21; Matériau de construction / Composite / Profil / Hachure: Sans Trame; Type Hachure: Sans Trame; Verrouillé: no; Nom d'étage d'implantation: RDC; Numéro d'étage d'implantation: 0; Type d'élément: Objet; ID de Parent: bureau-2pl; Surfaces (Toutes): _Bois bureaux; _gris satiné; Position: Non défini; État de rénovation: Existant; Affichage sur filtre de rénovation: Tous les filtres appropriés; Fonction structurelle: Non défini; Angle de rotation: 90 deg; Surface: _Peinture - Ocre jaune; Classification ARCHICAD - 20: Mobilier
AC_Pset_Table_de_bureau_21 - Niveau de détail 3D (gs_detlevel_3D): Détaillé; Niveau de détail 3D (gs_detlevel_3D_m): 2; Style plateau (gs_tabletop_style): Rectangle; Style plateau (gs_tabletop_style_m): 1; Style arête dessus de table (gs_tabletop_edge_style): Rectangulaire; Style arête dessus de table (gs_tabletop_edge_style_m): 1; Style pieds (gs_leg_type): Pied en T; Style pieds (gs_leg_type_m): 5; Rouleau: yes; Stylo contour: gris moyen (007); Motif de hachure: Sans Trame; Stylo hachure: Général - fonds de hachures; Stylo fond de hachure: Général - fonds de hachures; Résolution: 8; Ombre: yes; Afficher points chauds 2D en 3D: no; Pied: _gris satiné; Plateau: _Bois bureaux; Arête de plateau: _gris satiné; Base pied: _Peinture - Noir; Coût: 0; Type de groupe (FM_Type): Ameublement; Type de groupe (iFMType): 16; Poids de l'objet: 0; Unité poids de l'objet: kg
AC_Pset_RenovationAndPhasing - Renovation Status: Existing
Name | Zones conflictuelles = Nom de zone liée
16 x bureau-2pl | Salle de classe 5
16 x bureau-2pl | Salle de classe 3
15 x bureau-2pl | Salle de classe 2
15 x bureau-2pl | Salle de classe 4
16 x bureau-2pl | Salle de classe 1

# IfcFurnishingElement: Trappe-visite-plfd_JM (2)
In: RDC
Type - ElementType: SYSTEM_FURNITURE
Classification: Mobilier (Classification ARCHICAD); Elément d'ameublement (Classification Archicad); Material: Matériau de construction IFC
ArchiCADProperties - ID de l'élément: trappe_VMC; Lien et ID d'élément: trappe_VMC; Calque: 30_Fini Plafd_____.3CF; Nom Élément de Bibliothèque: Trappe-visite-plfd_JM; Matériau de construction / Composite / Profil / Hachure: Sans Trame; Type Hachure: Sans Trame; Zones conflictuelles: Salle plurivalente; Nom de zone liée: Salle plurivalente; Verrouillé: no; Nom d'étage d'implantation: RDC; Numéro d'étage d'implantation: 0; Type d'élément: Objet; ID de Parent: trappe_VMC; Surfaces (Toutes): _Mur int blanc; Position: Non défini; État de rénovation: Existant; Affichage sur filtre de rénovation: Tous les filtres appropriés; Fonction structurelle: Non défini; Surface: _Peinture-11; Classification ARCHICAD - 20: Mobilier
AC_Pset_Trappe-visite-plfd_JM - Afficher points chauds 2D en 3D: yes; Surface cadre: _Mur int blanc; Trappe sans panneau: no; Surface panneau: _Mur int blanc; Stylo contour: Eléments 2D - Général; Type ligne symbole: 26; Stylo fond de hachure: Fond - Couleur 1; Stylo hachure: Fond - Couleur 1; Motif de hachure: Sans Trame; Coût: 0; Type de groupe (FM_Type): Objets par défaut; Type de groupe (iFMType): 1; Poids de l'objet: 0; Unité poids de l'objet: kg
AC_Pset_RenovationAndPhasing - Renovation Status: Existing
Name | Angle de rotation (deg) | Position loquet
trappe_VMC | 3.97172 | Haut
trappe_VMC | 183.972 | Bas

# IfcSlab: Bois - Bardage 350, habillage-dalle
In: R+1
Type - PredefinedType: FLOOR
Classification: Dalle (Classification ARCHICAD); Dalle de sol (Classification Archicad); Material: Bois - Bardage 0.35 m
ArchiCADProperties - ID de l'élément: habillage-dalle; Lien et ID d'élément: habillage-dalle; Calque: 10_Plancher_Sol__.3CF; Matériau de construction / Composite / Profil / Hachure: Bois - Bardage; Matériau de construction: Bois - Bardage; Verrouillé: no; Nom d'étage d'implantation: R+1; Numéro d'étage d'implantation: 1; Type d'élément: Dalle; Type de structure: Basique; ID de Parent: habillage-dalle; Matériaux de construction (Tous): Bois - Bardage; Surfaces (Toutes): _Bois - Planches en bois ; _Bardage Bois-Horiz ocre; Hachure de recouvrement: 25 %; Nombre de percements: 0; Surface supérieure: _Bardage Bois-Horiz ocre; Surface latérale: _Bardage Bois-Horiz ocre; Surface inférieure: _Bois - Planches en bois; Position: Extérieur; État de rénovation: Existant; Affichage sur filtre de rénovation: Tous les filtres appropriés; Fonction structurelle: Élément non porteur; Emplacement de plan de référence: Haut; Classification ARCHICAD - 20: Dalle
AC_Pset_RenovationAndPhasing - Renovation Status: Existing
Pset_SlabCommon - IsExternal: yes; LoadBearing: no

# IfcSlab: Elément Modèle 207, _BA banché RAL9007
In: R+1
Type - PredefinedType: FLOOR
Material: _BA banché RAL9007
AC_Pset_RenovationAndPhasing - Renovation Status: Existing

# IfcSlab: Elément Modèle 208, _Chape
In: R+1
Type - PredefinedType: FLOOR
Material: _Chape
AC_Pset_RenovationAndPhasing - Renovation Status: Existing

# IfcSlab: IFC Extruded (10)
In: R+1
Type - PredefinedType: FLOOR
AC_Pset_RenovationAndPhasing - Renovation Status: Existing
Name | Material
5 x _BA banché RAL9007 | _BA banché RAL9007
5 x _Chape | _Chape

# IfcSlab: _BA banché 200, Dalle_BlocSanit
In: Fondations
Type - PredefinedType: FLOOR
Classification: Dalle (Classification ARCHICAD); Dalle de sol (Classification Archicad); Material: _BA banché 0.2 m
ArchiCADProperties - ID de l'élément: Dalle_BlocSanit; Lien et ID d'élément: Dalle_BlocSanit; Calque: 10_Plancher_Sol__.3CF; Matériau de construction / Composite / Profil / Hachure: _BA banché; Matériau de construction: _BA banché; Verrouillé: no; Nom d'étage d'implantation: Fondations; Numéro d'étage d'implantation: -1; Type d'élément: Dalle; Type de structure: Basique; ID de Parent: Dalle_BlocSanit; Matériaux de construction (Tous): _BA banché; Surfaces (Toutes): _Béton - Lissé; _Enduit minéral blanc; Hachure de recouvrement: 25 %; Nombre de percements: 0; Surface supérieure: _Béton - Lissé; Surface latérale: _Béton - Lissé; Surface inférieure: _Béton - Lissé; Position: Intérieur; État de rénovation: Existant; Affichage sur filtre de rénovation: Tous les filtres appropriés; Fonction structurelle: Élément porteur; Emplacement de plan de référence: Haut; Génération de modèle analytique structurel: yes; Classification ARCHICAD - 20: Dalle
AC_Pset_RenovationAndPhasing - Renovation Status: Existing
Pset_SlabCommon - IsExternal: no; LoadBearing: yes

# IfcSlab: _BA banché 350 (3)
In: Fondations
Type - PredefinedType: FLOOR
Classification: Dalle (Classification ARCHICAD); Dalle de sol (Classification Archicad); Material: _BA banché 0.35 m
ArchiCADProperties - ID de l'élément: Semelle_BlocSanit; Lien et ID d'élément: Semelle_BlocSanit; Calque: 10_M x baseGO__; Matériau de construction / Composite / Profil / Hachure: _BA banché; Matériau de construction: _BA banché; Verrouillé: no; Nom d'étage d'implantation: Fondations; Numéro d'étage d'implantation: -1; Type d'élément: Dalle; Type de structure: Basique; ID de Parent: Semelle_BlocSanit; Matériaux de construction (Tous): _BA banché; Surfaces (Toutes): _Béton - Lissé; _Enduit minéral blanc; Hachure de recouvrement: 25 %; Nombre de percements: 0; Surface supérieure: _Béton - Lissé; Surface latérale: _Enduit minéral blanc; Surface inférieure: _Béton - Lissé; Position: Intérieur; État de rénovation: Existant; Affichage sur filtre de rénovation: Tous les filtres appropriés; Fonction structurelle: Élément porteur; Emplacement de plan de référence: Haut; Génération de modèle analytique structurel: yes; Classification ARCHICAD - 20: Dalle
AC_Pset_RenovationAndPhasing - Renovation Status: Existing
Pset_SlabCommon - IsExternal: no; LoadBearing: yes

# IfcSlab: _BA banché RAL9007 350 (2)
In: Fondations
Type - PredefinedType: FLOOR
Classification: Dalle (Classification ARCHICAD); Dalle de sol (Classification Archicad); Material: _BA banché RAL9007 0.35 m
ArchiCADProperties - Calque: 10_Plancher_Sol__.3CF; Matériau de construction / Composite / Profil / Hachure: _BA banché RAL9007; Matériau de construction: _BA banché RAL9007; Verrouillé: no; Nom d'étage d'implantation: Fondations; Numéro d'étage d'implantation: -1; Type d'élément: Dalle; Type de structure: Basique; Matériaux de construction (Tous): _BA banché RAL9007; Hachure de recouvrement: 25 %; Nombre de percements: 0; Position: Intérieur; État de rénovation: Existant; Affichage sur filtre de rénovation: Tous les filtres appropriés; Fonction structurelle: Élément porteur; Emplacement de plan de référence: Haut; Génération de modèle analytique structurel: yes; Classification ARCHICAD - 20: Dalle
AC_Pset_RenovationAndPhasing - Renovation Status: Existing
Pset_SlabCommon - IsExternal: no; LoadBearing: yes
Name | ID de l'élément = Lien et ID d'élément = ID de Parent | Surfaces (Toutes) | Surface supérieure = Surface inférieure | Surface latérale
Radier-ascens | Radier-ascens | _MENEAU gris RAL 9007 | _MENEAU gris RAL 9007 | _MENEAU gris RAL 9007
Radier-general | Radier-general | _Béton - Lissé; _Enduit minéral blanc | _Béton - Lissé | _Enduit minéral blanc

# IfcSlab: _Bois contreplaqué 40 (110)
Type - PredefinedType: FLOOR
Classification: Dalle (Classification ARCHICAD); Dalle de sol (Classification Archicad); Material: _Bois contreplaqué 0.04 m
ArchiCADProperties - Calque: 20_Men Int________; Matériau de construction / Composite / Profil / Hachure: _Bois contreplaqué; Matériau de construction: _Bois contreplaqué; Verrouillé: no; Type d'élément: Dalle; Type de structure: Basique; Matériaux de construction (Tous): _Bois contreplaqué; Surfaces (Toutes): _PlanW-mélaminé; Hachure de recouvrement: 25 %; Nombre de percements: 0; Surface supérieure: _PlanW-mélaminé; Surface latérale: _PlanW-mélaminé; Surface inférieure: _PlanW-mélaminé; Position: Intérieur; État de rénovation: Existant; Affichage sur filtre de rénovation: Tous les filtres appropriés; Fonction structurelle: Élément non porteur; Emplacement de plan de référence: Haut; Classification ARCHICAD - 20: Dalle
AC_Pset_RenovationAndPhasing - Renovation Status: Existing
Pset_SlabCommon - IsExternal: no; LoadBearing: no
Name | In | ID de l'élément = Lien et ID d'élément = ID de Parent | Zones conflictuelles | Nom de zone liée | Nom d'étage d'implantation | Numéro d'étage d'implantation
8 x tablette fd classe | RDC | tablette fd classe | Salle de classe 1 | Salle de classe 1 | RDC | 0
8 x tablette fd classe | RDC | tablette fd classe | Salle de classe 5 | Salle de classe 5 | RDC | 0
2 x tablette fd classe fx | RDC | tablette fd classe fx | Salle de classe 1 | Salle de classe 1 | RDC | 0
2 x tablette fd classe fx | RDC | tablette fd classe fx | Salle de classe 5 | Salle de classe 5 | RDC | 0
plan-travail classe | RDC | plan-travail classe | Salle de classe 5 | Salle de classe 5 | RDC | 0
plan-travail classe | RDC | plan-travail classe | Salle de classe 1 | Salle de classe 1 | RDC | 0
plan-travail classe | RDC | plan-travail classe | Salle de classe 2 | Salle de classe 2 | RDC | 0
tablette fd classe fx | RDC | tablette fd classe fx | Salle de classe 2 | Salle de classe 2 | RDC | 0
tablette fd classe fx | RDC | tablette fd classe fx | Salle de classe 2 |  | RDC | 0
5 x tablette fd classe | RDC | tablette fd classe | Salle de classe 2 | Salle de classe 2 | RDC | 0
3 x tablette fd classe | RDC | tablette fd classe | Salle de classe 2 |  | RDC | 0
plan-travail classe | RDC | plan-travail classe | Salle de classe 3 | Salle de classe 3 | RDC | 0
tablette fd classe fx | RDC | tablette fd classe fx | Salle de classe 3 | Salle de classe 3 | RDC | 0
tablette fd classe fx | RDC | tablette fd classe fx | Salle de classe 3 |  | RDC | 0
5 x tablette fd classe | RDC | tablette fd classe | Salle de classe 3 | Salle de classe 3 | RDC | 0
3 x tablette fd classe | RDC | tablette fd classe | Salle de classe 3 |  | RDC | 0
plan-travail classe | RDC | plan-travail classe | Salle de classe 4 | Salle de classe 4 | RDC | 0
2 x tablette fd classe fx | RDC | tablette fd classe fx | Salle de classe 4 | Salle de classe 4 | RDC | 0
8 x tablette fd classe | RDC | tablette fd classe | Salle de classe 4 | Salle de classe 4 | RDC | 0
2 x tablette fd classe fx | R+1 | tablette fd classe fx | Salle de classe 8 | Salle de classe 8 | R+1 | 1
8 x tablette fd classe | R+1 | tablette fd classe | Salle de classe 8 | Salle de classe 8 | R+1 | 1
8 x tablette fd classe | R+1 | tablette fd classe | Salle de classe 6 | Salle de classe 6 | R+1 | 1
2 x tablette fd classe fx | R+1 | tablette fd classe fx | Salle de classe 6 | Salle de classe 6 | R+1 | 1
plan-travail classe | R+1 | plan-travail classe | Salle de classe 6 | Salle de classe 6 | R+1 | 1
plan-travail classe | R+1 | plan-travail classe | Salle de classe 7 | Salle de classe 7 | R+1 | 1
2 x tablette fd classe fx | R+1 | tablette fd classe fx | Salle de classe 7 | Salle de classe 7 | R+1 | 1
8 x tablette fd classe | R+1 | tablette fd classe | Salle de classe 7 | Salle de classe 7 | R+1 | 1
plan-travail classe | R+1 | plan-travail classe | Salle de classe 8 | Salle de classe 8 | R+1 | 1
8 x tablette fd classe | R+1 | tablette fd classe | Salle de classe 10 | Salle de classe 10 | R+1 | 1
2 x tablette fd classe fx | R+1 | tablette fd classe fx | Salle de classe 10 | Salle de classe 10 | R+1 | 1
plan-travail classe | R+1 | plan-travail classe | Salle de classe 10 | Salle de classe 10 | R+1 | 1
plan-travail classe | R+1 | plan-travail classe | Salle de classe 9 | Salle de classe 9 | R+1 | 1
2 x tablette fd classe fx | R+1 | tablette fd classe fx | Salle de classe 9 | Salle de classe 9 | R+1 | 1
8 x tablette fd classe | R+1 | tablette fd classe | Salle de classe 9 | Salle de classe 9 | R+1 | 1

# IfcSlab: _Bois contreplaqué 50 (10)
Type - PredefinedType: FLOOR
Classification: Dalle (Classification ARCHICAD); Dalle de sol (Classification Archicad); Material: _Bois contreplaqué 0.05 m
ArchiCADProperties - ID de l'élément: plan-sous tableau; Lien et ID d'élément: plan-sous tableau; Calque: 20_Men Int________; Matériau de construction / Composite / Profil / Hachure: _Bois contreplaqué; Matériau de construction: _Bois contreplaqué; Verrouillé: no; Type d'élément: Dalle; Type de structure: Basique; ID de Parent: plan-sous tableau; Matériaux de construction (Tous): _Bois contreplaqué; Surfaces (Toutes): _Huisserie-int; Hachure de recouvrement: 25 %; Nombre de percements: 0; Surface supérieure: _Huisserie-int; Surface latérale: _Huisserie-int; Surface inférieure: _Huisserie-int; Position: Intérieur; État de rénovation: Existant; Affichage sur filtre de rénovation: Tous les filtres appropriés; Fonction structurelle: Élément non porteur; Emplacement de plan de référence: Haut; Classification ARCHICAD - 20: Dalle
AC_Pset_RenovationAndPhasing - Renovation Status: Existing
Pset_SlabCommon - IsExternal: no; LoadBearing: no
Name | In | Zones conflictuelles = Nom de zone liée | Nom d'étage d'implantation | Numéro d'étage d'implantation
plan-sous tableau | RDC | Salle de classe 1 | RDC | 0
plan-sous tableau | RDC | Salle de classe 3 | RDC | 0
plan-sous tableau | RDC | Salle de classe 2 | RDC | 0
plan-sous tableau | RDC | Salle de classe 4 | RDC | 0
plan-sous tableau | RDC | Salle de classe 5 | RDC | 0
plan-sous tableau | R+1 | Salle de classe 8 | R+1 | 1
plan-sous tableau | R+1 | Salle de classe 6 | R+1 | 1
plan-sous tableau | R+1 | Salle de classe 7 | R+1 | 1
plan-sous tableau | R+1 | Salle de classe 9 | R+1 | 1
plan-sous tableau | R+1 | Salle de classe 10 | R+1 | 1

# IfcSlab: _Chappe isol 15 150 (5)
In: RDC
Type - PredefinedType: FLOOR
Classification: Dalle (Classification ARCHICAD); Dalle de sol (Classification Archicad); Material: _Chape 0.06 m
ArchiCADProperties - Calque: 10_Plancher_Sol__.3CF; Matériau de construction / Composite / Profil / Hachure: _Chappe isol 15; Structure Composite: _Chappe isol 15; Verrouillé: no; Nom d'étage d'implantation: RDC; Numéro d'étage d'implantation: 0; Type d'élément: Dalle; Type de structure: Composite; Matériaux de construction (Tous): _Chape; _Isol Polyst Extrud 470; Hachure de recouvrement: 25 %; Nombre de percements: 0; Surface inférieure: _Isolation - Polystyrène; Position: Intérieur; État de rénovation: Existant; Affichage sur filtre de rénovation: Tous les filtres appropriés; Fonction structurelle: Élément non porteur; Emplacement de plan de référence: Haut; Classification ARCHICAD - 20: Dalle
AC_Pset_RenovationAndPhasing - Renovation Status: Existing
Pset_SlabCommon - IsExternal: no; LoadBearing: no
Name | ID de l'élément = Lien et ID d'élément = ID de Parent | Surfaces (Toutes) | Surface supérieure
chappe-RDC | chappe-RDC | _Béton - Lissé; _Isolation - Polystyrène; _Sol PVC classe | _Sol PVC classe
chappe-RDC | chappe-RDC | _Béton - Lissé; _Isolation - Polystyrène; _Sol PVC classe | _Sol PVC classe | ArchiCADProperties - Nom de zone liée: Bureau RASED
chappe-RDC | chappe-RDC | _Béton - Lissé; _Isolation - Polystyrène; _Sol PVC classe | _Sol PVC classe | ArchiCADProperties - Nom de zone liée: Local entretien
Chappe-Hall-ascens-RDC | Chappe-Hall-ascens-RDC | _Béton - Lissé; _Isolation - Polystyrène; _Carrelage 30x30 | _Carrelage 30x30
chappe-BlocSanit | chappe-BlocSanit | _Béton - Lissé; _Isolation - Polystyrène; _Carrelage 30x30 | _Carrelage 30x30

# IfcSlab: _Dalle 20+15 gris 350 (2)
In: R+1
Type - PredefinedType: FLOOR
Classification: Dalle (Classification ARCHICAD)
ArchiCADProperties - Calque: 10_Plancher_Sol__.3CF; Matériau de construction / Composite / Profil / Hachure: _Dalle 20+15 gris; Structure Composite: _Dalle 20+15 gris; Verrouillé: no; Nom d'étage d'implantation: R+1; Numéro d'étage d'implantation: 1; Type d'élément: Dalle; Type de structure: Composite; Matériaux de construction (Tous): _Chape; _Isol Polyst Extrud 470; _BA banché RAL9007; Hachure de recouvrement: 25 %; Nombre de percements: 0; Surface supérieure: _Sol PVC couloir; Surface latérale: _Enduit minéral blanc; Position: Intérieur; État de rénovation: Existant; Affichage sur filtre de rénovation: Tous les filtres appropriés; Fonction structurelle: Élément porteur; Emplacement de plan de référence: Haut; Génération de modèle analytique structurel: yes; Classification ARCHICAD - 20: Dalle
AC_Pset_RenovationAndPhasing - Renovation Status: Existing
Pset_SlabCommon - LoadBearing: yes; IsExternal: no
Name | ID de l'élément = Lien et ID d'élément = ID de Parent | Surfaces (Toutes) | Surface inférieure
dalle-couloir | dalle-couloir | _Béton - Lissé; _Enduit minéral blanc; _MENEAU gris RAL 9007; _Isolation - Polystyrène; _Sol PVC couloir; _Enduit minéral RAL7004 | _Enduit minéral RAL7004 | ArchiCADProperties - Zones conflictuelles: Local entretien; Rangt. 2; Nom de zone liée: Sanitaires
dalle-reunion-couloir | dalle-reunion-couloir | _Béton - Lissé; _Mur int blanc; _Enduit minéral blanc; _MENEAU gris RAL 9007; _Isolation - Polystyrène; _Sol PVC couloir; __Enduit minéral RAL7004; _Plafd blanc | _Plafd blanc

# IfcSlab: _Dalle 25+15 gris 400 (4)
In: R+1
Type - PredefinedType: FLOOR
Classification: Dalle (Classification ARCHICAD)
ArchiCADProperties - Calque: 10_Plancher_Sol__.3CF; Matériau de construction / Composite / Profil / Hachure: _Dalle 25+15 gris; Structure Composite: _Dalle 25+15 gris; Verrouillé: no; Nom d'étage d'implantation: R+1; Numéro d'étage d'implantation: 1; Type d'élément: Dalle; Type de structure: Composite; Matériaux de construction (Tous): _Chape; _Isol Polyst Extrud 470; _BA banché RAL9007; Hachure de recouvrement: 25 %; Nombre de percements: 0; Surface supérieure: _Sol PVC couloir; Surface inférieure: _MENEAU gris RAL 9007; Position: Intérieur; État de rénovation: Existant; Affichage sur filtre de rénovation: Tous les filtres appropriés; Fonction structurelle: Élément porteur; Emplacement de plan de référence: Haut; Génération de modèle analytique structurel: yes; Classification ARCHICAD - 20: Dalle
AC_Pset_RenovationAndPhasing - Renovation Status: Existing
Pset_SlabCommon - LoadBearing: yes; IsExternal: no
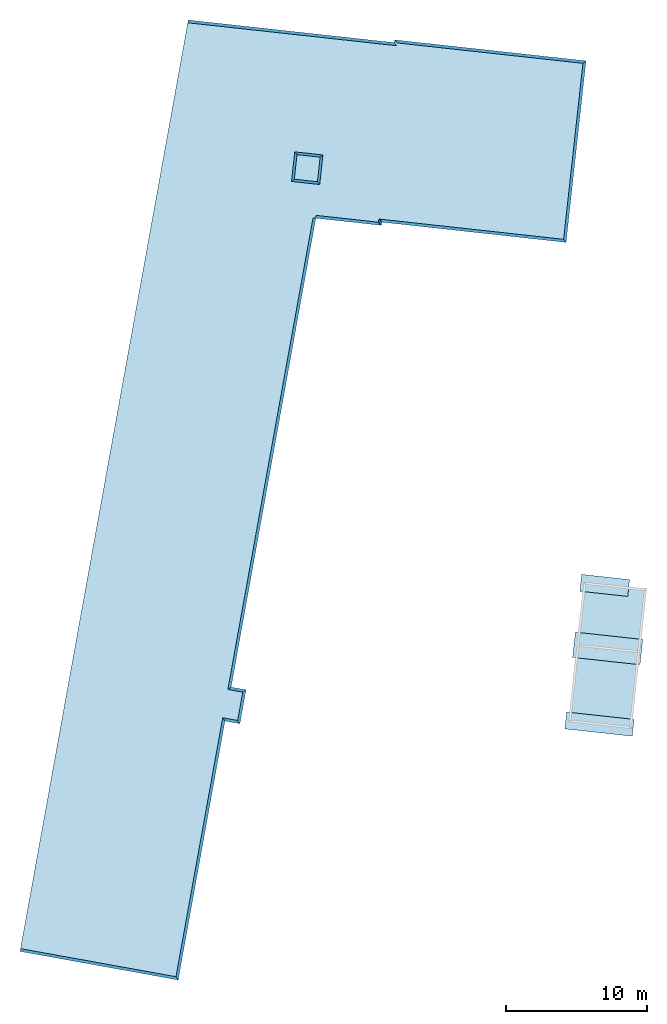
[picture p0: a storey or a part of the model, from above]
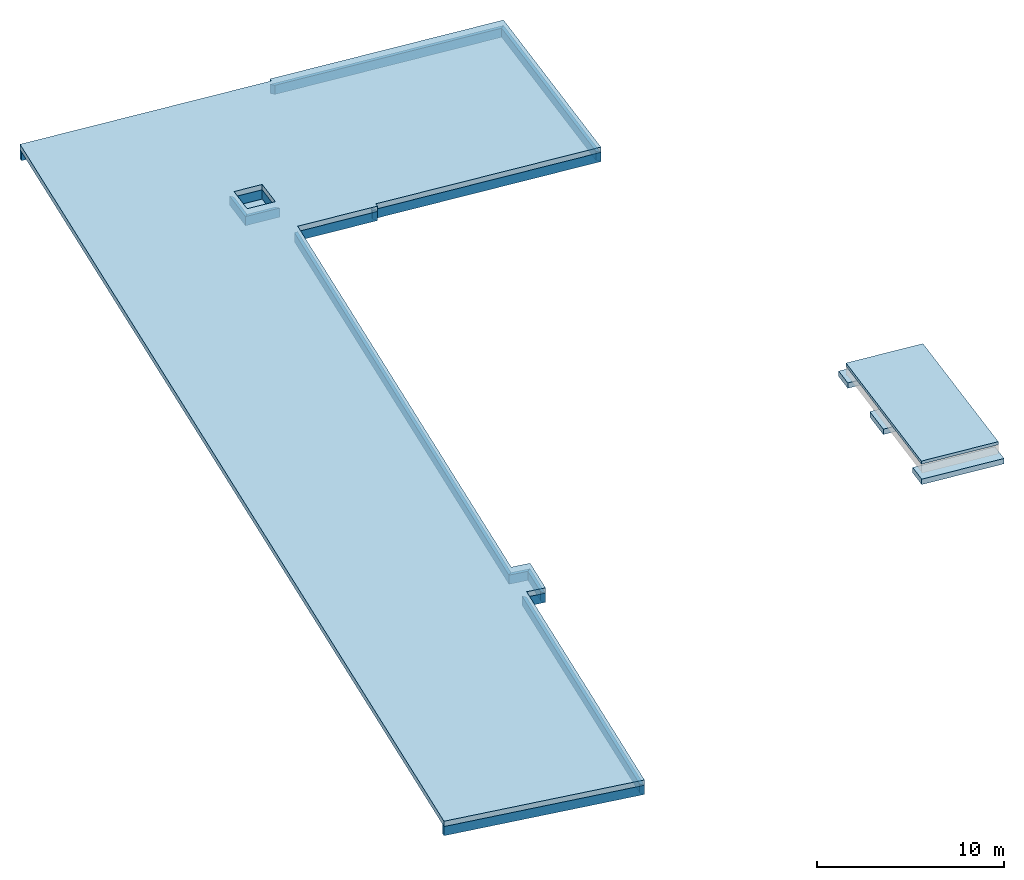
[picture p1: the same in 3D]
Properties of the parts of a building model (IFC2X3), part 10 of 10

# IfcSlab: _Dalle 25+15 gris 400 (4)
Name | ID de l'élément = Lien et ID d'élément = ID de Parent | Nom de zone liée | Surfaces (Toutes) | Surface latérale
dalle-reunion-couloir | dalle-reunion-couloir | Salle de réunion (maîtres) | _Béton - Lissé; _Mur int blanc; _Mur int Hall; _MENEAU gris RAL 9007; _Isolation - Polystyrène; _Sol PVC couloir; __Enduit minéral RAL7004 | _Mur int blanc | ArchiCADProperties - Zones conflictuelles: local TGBT; Rangt. 1
Dalle-classe | Dalle-classe | Salle de classe 9 | _Béton - Lissé; _Enduit minéral blanc; _MENEAU gris RAL 9007; _Isolation - Polystyrène; _Sol PVC couloir | _Enduit minéral blanc
Dalle-classe | Dalle-classe | Salle de classe 8 | _Béton - Lissé; _Enduit minéral blanc; _MENEAU gris RAL 9007; _Isolation - Polystyrène; _Sol PVC couloir | _Enduit minéral blanc
Dalle-classe | Dalle-classe | Salle de classe 6 | _Béton - Lissé; _Enduit minéral blanc; _MENEAU gris RAL 9007; _Isolation - Polystyrène; _Sol PVC couloir | _Enduit minéral blanc

# IfcSlab: _DalleToit 20+28 gris 480 (2)
In: Toit & PM
Type - PredefinedType: FLOOR
Classification: Dalle (Classification ARCHICAD); Dalle de sol (Classification Archicad); Material: _BA banché RAL9007 0.2 m
ArchiCADProperties - Calque: 10_Toit___________.3CF; Matériau de construction / Composite / Profil / Hachure: _DalleToit 20+28 gris; Structure Composite: _DalleToit 20+28 gris; Verrouillé: no; Nom d'étage d'implantation: Toit & PM; Numéro d'étage d'implantation: 2; Type d'élément: Dalle; Type de structure: Composite; Matériaux de construction (Tous): _Fini Gravier; _Etanchéité; _Isol Polyst Extrud 470; _Isol Polyst Extrud 470; _BA banché RAL9007; Nombre de percements: 0; Surface supérieure: _Gravillon; Surface latérale: _Enduit minéral blanc; Position: Extérieur; État de rénovation: Existant; Affichage sur filtre de rénovation: Tous les filtres appropriés; Fonction structurelle: Élément porteur; Emplacement de plan de référence: Sommet de l'âme; Génération de modèle analytique structurel: yes; Classification ARCHICAD - 20: Dalle
AC_Pset_RenovationAndPhasing - Renovation Status: Existing
Pset_SlabCommon - IsExternal: yes; LoadBearing: yes
Name | ID de l'élément = Lien et ID d'élément = ID de Parent | Surfaces (Toutes) | Hachure de recouvrement | Surface inférieure
Dalle-toiture | Dalle-toiture | _Enduit minéral blanc; _MENEAU gris RAL 9007; _Etanchéité - Membrane souple; _Isolation - Polystyrène; _Gravillon fin; _Enduit minéral RAL7004; _Gravillon | Faux-plancher avec plots | _Enduit minéral RAL7004
dalle-toiture | dalle-toiture | _Enduit minéral blanc; _MENEAU gris RAL 9007; _Etanchéité - Membrane souple; _Isolation - Polystyrène; _Gravillon fin; __Enduit minéral RAL7004; _Gravillon | 25 % | _Enduit minéral blanc

# IfcSlab: _DalleToit 25+28 gris 530 (3)
In: Toit & PM
Type - PredefinedType: FLOOR
Classification: Dalle (Classification ARCHICAD); Dalle de sol (Classification Archicad); Material: _BA banché RAL9007 0.25 m
ArchiCADProperties - ID de l'élément: dalle-toiture; Lien et ID d'élément: dalle-toiture; Calque: 10_Toit___________.3CF; Matériau de construction / Composite / Profil / Hachure: _DalleToit 25+28 gris; Structure Composite: _DalleToit 25+28 gris; Verrouillé: no; Nom d'étage d'implantation: Toit & PM; Numéro d'étage d'implantation: 2; Type d'élément: Dalle; Type de structure: Composite; ID de Parent: dalle-toiture; Matériaux de construction (Tous): _Fini Gravier; _Etanchéité; _Isol Polyst Extrud 470; _Isol Polyst Extrud 470; _BA banché RAL9007; Hachure de recouvrement: 25 %; Nombre de percements: 0; Surface supérieure: _Gravillon; Position: Extérieur; État de rénovation: Existant; Affichage sur filtre de rénovation: Tous les filtres appropriés; Fonction structurelle: Élément porteur; Emplacement de plan de référence: Sommet de l'âme; Génération de modèle analytique structurel: yes; Classification ARCHICAD - 20: Dalle
AC_Pset_RenovationAndPhasing - Renovation Status: Existing
Pset_SlabCommon - IsExternal: yes; LoadBearing: yes
Name | Surfaces (Toutes) | Surface latérale | Surface inférieure
dalle-toiture | _Mur int blanc; _Enduit minéral blanc; _MENEAU gris RAL 9007; _Etanchéité - Membrane souple; _Isolation - Polystyrène; _Gravillon fin; _Gravillon | _Enduit minéral blanc | _Enduit minéral blanc
dalle-toiture | _Enduit minéral blanc; _MENEAU gris RAL 9007; _Etanchéité - Membrane souple; _Isolation - Polystyrène; _Gravillon fin; _Enduit minéral RAL7004; _Gravillon | _Enduit minéral blanc | _Enduit minéral RAL7004
dalle-toiture | _Enduit minéral blanc; _MENEAU gris RAL 9007; _Etanchéité - Membrane souple; _Isolation - Polystyrène; _Gravillon fin; __Enduit minéral RAL7004; _Gravillon | __Enduit minéral RAL7004 | _Enduit minéral blanc

# IfcSlab: _DalleToit 25+38 gris 630, Dalle-toiture-pluri
In: R+1
Type - PredefinedType: FLOOR
Classification: Dalle (Classification ARCHICAD); Dalle de sol (Classification Archicad); Material: _BA banché RAL9007 0.25 m
ArchiCADProperties - ID de l'élément: Dalle-toiture-pluri; Lien et ID d'élément: Dalle-toiture-pluri; Calque: 10_Toit___________.3CF; Matériau de construction / Composite / Profil / Hachure: _DalleToit 25+38 gris; Structure Composite: _DalleToit 25+38 gris; Verrouillé: no; Nom d'étage d'implantation: R+1; Numéro d'étage d'implantation: 1; Type d'élément: Dalle; Type de structure: Composite; ID de Parent: Dalle-toiture-pluri; Matériaux de construction (Tous): _vegetation extensive; _Etanchéité; _Isol Polyst Extrud 470; _Isol Polyst Extrud 470; _BA banché RAL9007; Surfaces (Toutes): _Enduit minéral blanc; _MENEAU gris RAL 9007; _Etanchéité - Membrane souple; _Isolation - Polystyrène; _bac-canopia; Hachure de recouvrement: 25 %; Nombre de percements: 0; Surface supérieure: _bac-canopia; Surface latérale: _Enduit minéral blanc; Surface inférieure: _Enduit minéral blanc; Position: Extérieur; État de rénovation: Existant; Affichage sur filtre de rénovation: Tous les filtres appropriés; Fonction structurelle: Élément porteur; Emplacement de plan de référence: Sommet de l'âme; Génération de modèle analytique structurel: yes; Classification ARCHICAD - 20: Dalle
AC_Pset_RenovationAndPhasing - Renovation Status: Existing
Pset_SlabCommon - IsExternal: yes; LoadBearing: yes

# IfcSlab: _Iso 8+2 (prio) 100, isol GR32-85mm new
In: RDC
Type - PredefinedType: FLOOR
Classification: Dalle (Classification ARCHICAD); Dalle de sol (Classification Archicad); Material: MANQUANT 0.1 m
ArchiCADProperties - ID de l'élément: isol GR32-85mm new; Lien et ID d'élément: isol GR32-85mm new; Calque: 20_Plafd-isol_____.2-3; Matériau de construction / Composite / Profil / Hachure: _Iso 8+2 (prio); Structure Composite: _Iso 8+2 (prio); Verrouillé: no; Nom d'étage d'implantation: RDC; Numéro d'étage d'implantation: 0; Type d'élément: Dalle; Type de structure: Composite; ID de Parent: isol GR32-85mm new; Matériaux de construction (Tous): _Isol Laine2verre (prio); _Fini placo 600; Surfaces (Toutes): _Isolation - Laine de verre/roche (2); _Plafd blanc; Hachure de recouvrement: hachure -45; Nombre de percements: 0; Surface supérieure: _Isolation - Laine de verre/roche (2); Surface inférieure: _Plafd blanc; Position: Intérieur; État de rénovation: Existant; Affichage sur filtre de rénovation: Tous les filtres appropriés; Fonction structurelle: Élément non porteur; Emplacement de plan de référence: Haut; Classification ARCHICAD - 20: Dalle
AC_Pset_RenovationAndPhasing - Renovation Status: Existing
Pset_SlabCommon - IsExternal: no; LoadBearing: no

# IfcTransportElement: Ascenseur 21, gabarit PMR
In: RDC
Classification: Equipement de transport (Classification ARCHICAD); Elément de transport (Classification Archicad); Material: Matériau de construction IFC
ArchiCADProperties - ID de l'élément: gabarit PMR; Lien et ID d'élément: gabarit PMR; Calque: 26_Ascen elevat__; Nom Élément de Bibliothèque: Ascenseur 21; Matériau de construction / Composite / Profil / Hachure: Sans Trame; Type Hachure: Sans Trame; Zones conflictuelles: Circulation 1; Circulation 2; Verrouillé: no; Nom d'étage d'implantation: RDC; Numéro d'étage d'implantation: 0; Type d'élément: Objet; ID de Parent: gabarit PMR; Surfaces (Toutes): _Béton - Lissé; _Métal - Acier inoxydable; _Mur int blanc; _Plastique - Laminé; _Métal - Fer; _Métal - Zinc; _Mur int Hall; Position: Non défini; État de rénovation: Existant; Affichage sur filtre de rénovation: Tous les filtres appropriés; Fonction structurelle: Non défini; Angle de rotation: 93.9717 deg; Surface: _Peinture - Ocre jaune; Classification ARCHICAD - 20: Equipement de transport
AC_Pset_Ascenseur_21 - Afficher points chauds 2D en 3D: no; 3D (gs_detlevel_3D): Détaillé; 3D (gs_detlevel_3D_m): 2; Forme (elevator_form): Rectangulaire; Forme (elevator_form_m): 1; Nombre de segments: 7; Type d'ascenseur (elevator_type): Mécanique; Type d'ascenseur (elevator_type_m): 1; Direction deuxième ouverture (dir_second_opening): Sans; Direction deuxième ouverture (dir_second_opening_m): 1; Position contrepoids (cweight_pos): Côté 2; Position contrepoids (cweight_pos_m): 3; Nbre étages au-dessus implantation: 1; Nbre étages sous implantation: 0; Etages niveau divisé: no; Nbre étages niveau divisé au-dessus implantation: 0; Nbre étages niveau divisé sous implantation: 0; Dépassement ascenseur: yes; Fosse: yes; Style porte cage ascenseur (elev_door_style): Coulissant; Style porte cage ascenseur (elev_door_style_m): 1; Style porte cabine ascenseur (door_style): Style 1; Style porte cabine ascenseur (door_style_m): 1; Cadre ouverture: yes; Nom d'étage à éditer (edited_story): 0. RDC; Nom d'étage à éditer (edited_story_m): 0; Position porte étage édité (edited_story_door_pos): Face; Position porte étage édité (edited_story_door_pos_m): 1; Tableau de bord: yes; Position tableau de bord: 1; Surface panneau de porte: _Mur int Hall; Surface vitre de porte: _Verre clair (rapide); Surface cadre d'ouverture: _Mur int Hall; Surface tableau de bord: _Métal - Acier inoxydable; Surface de bouton: _Métal - Fer; Position cabine (Etage) (car_pos_story): 0. RDC; Position cabine (Etage) (car_pos_story_m): 0; Surface extérieure de cabine: _Plastique - Laminé; Surface latérale intérieure de cabine: _Métal - Zinc; Surface plancher de cabine: _Métal - Zinc; Surface plafond de cabine: _Mur int blanc; Surface latérale avant de cabine: _Verre clair (rapide); Surface latérale arrière de cabine: _Plastique - Laminé; Surface meneau: _Métal - Acier inoxydable; Afficher cage d'ascenseur: yes; Surface latérale extérieure de cage d'ascenseur: _Mur int Hall; Surface latérale intérieure de cage d'ascenseur: _Béton - Lissé; Surface d'arête de cage d'ascenseur: _Mur int blanc; Afficher mur ascenseur: no; Surface latérale extérieure de mur d'ascenseur: _Mur int blanc; Surface latérale intérieure de mur d'ascenseur: _Mur int blanc; Surface d'arête de mur d'ascenseur: _Mur int blanc; Dalle supérieure: no; Surface latérale extérieure de dalle supérieure: _Mur int blanc; Surface latérale intérieure de dalle supérieure: _Mur int blanc; Surface d'arête de dalle supérieure: _Mur int blanc; Dalle de la fosse: no; Surface latérale extérieure de dalle d'ascenseur: _Mur int blanc; Surface latérale intérieure de dalle d'ascenseur: _Mur int blanc; Surface d'arête de dalle d'ascenseur: _Mur int blanc; Ouverture porte en 3D (%): 30; Ombre: yes; Résolution: 6; Afficher meneaux: yes; Niveau de détail 2D (gs_detlevel_2D): Selon échelle; Niveau de détail 2D (gs_detlevel_2D_m): 1; Type de ligne ascenseur et cage: 1; Afficher mécanismes en 2D: yes; Type de ligne mécanique: 1; Stylo contour cabine: Eléments 2D - Général; Motif de hachure cabine: Sans Trame; Stylo hachure cabine: Fond - Couleur 1; Stylo fond de hachure cabine: Fond - Couleur 1; Stylo contour mur: Murs - Symboles et séparateurs; Motif de hachure de mur: Sans Trame; Stylo de hachure de mur: Murs - Hachures coupées; Stylo de fond hachure de mur: Fond - Couleur 1; Motif de hachure cadre ouverture: Sans Trame; Stylo hachure cadre ouverture: Murs - Hachures coupées; Stylo fond cadre ouverture: Fond - Couleur 1; Motif de hachure espace: Sans Trame; Stylo hachure espace: Fond - Couleur 1; Stylo fond hachure espace: Fond - Couleur 1; Coût: 0; Type de groupe (FM_Type): Ascenseurs; Type de groupe (iFMType): 4; Poids de l'objet: 0; Unité poids de l'objet: kg; Capacité ascenseur (FM_LiftCapacity): 0; Capacité ascenseur (FM_LiftCapacityNumber): 0; Capacité par personne (FM_TransportablePersons): 0; Capacité par largeur: 0; Capacité par personne (ifc_CapacityByNumber): 0; Opération IFC: 1; Poids objet supplémentaire: 0
AC_Pset_RenovationAndPhasing - Renovation Status: Existing

# IfcWall: _acrotere 230 x 570 (7)
In: Toit & PM
Classification: Mur (Classification ARCHICAD); Mur (Classification Archicad); Material: _BA banché RAL9007
ArchiCADProperties - ID de l'élément: M acrot -classe; Lien et ID d'élément: M acrot -classe; Calque: 10_M x baseGO__; Matériau de construction / Composite / Profil / Hachure: _acrotere; Profil complexe: _acrotere; Verrouillé: no; Nom d'étage d'implantation: Toit & PM; Numéro d'étage d'implantation: 2; Type d'élément: Mur; Étage supérieur lié absolu: Non lié; Étage supérieur lié relatif: Non lié; Étage supérieur lié: Non lié; Type de structure: Profil complexe; ID de Parent: M acrot -classe; Matériaux de construction (Tous): _menuiserie alu; _BA banché RAL9007; Surfaces (Toutes): _Men ext_RAL9007; _Enduit minéral blanc; _MENEAU gris RAL 9007; Angle d'inclinaison: 90 deg; Nombre de percements: 0; Surface latérale: _Enduit minéral blanc; Position: Extérieur; État de rénovation: Existant; Affichage sur filtre de rénovation: Tous les filtres appropriés; Fonction structurelle: Élément porteur; Complexité de mur: Droit; Option de géométrie: Uniforme; Surface de face intérieure: GENERAL; Angle d'inclinaison interne de mur: 90 deg; Angle d'inclinaison externe de mur: 90 deg; Génération de modèle analytique structurel: yes; Classification ARCHICAD - 20: Mur
Pset_ConcreteElementGeneral - ConstructionType: Murs porteurs extérieurs
AC_Pset_RenovationAndPhasing - Renovation Status: Existing
Pset_WallCommon - IsExternal: yes; LoadBearing: yes

# IfcWall: _acrotere ANGLE 230 x 1320, M acrot Sud-hall
In: Toit & PM
Classification: Mur (Classification ARCHICAD); Mur (Classification Archicad); Material: _BA banché RAL9007
ArchiCADProperties - ID de l'élément: M acrot Sud-hall; Lien et ID d'élément: M acrot Sud-hall; Calque: 10_M x baseGO__; Matériau de construction / Composite / Profil / Hachure: _acrotere ANGLE; Profil complexe: _acrotere ANGLE; Verrouillé: no; Nom d'étage d'implantation: Toit & PM; Numéro d'étage d'implantation: 2; Type d'élément: Mur; Étage supérieur lié absolu: Non lié; Étage supérieur lié relatif: Non lié; Étage supérieur lié: Non lié; Type de structure: Profil complexe; ID de Parent: M acrot Sud-hall; Matériaux de construction (Tous): _menuiserie alu; _BA banché RAL9007; Surfaces (Toutes): _Men ext_RAL9007; _Enduit minéral blanc; _MENEAU gris RAL 9007; __Enduit minéral RAL7004; Angle d'inclinaison: 90 deg; Nombre de percements: 0; Surface latérale: _Enduit minéral blanc; Position: Extérieur; État de rénovation: Existant; Affichage sur filtre de rénovation: Tous les filtres appropriés; Fonction structurelle: Élément porteur; Complexité de mur: Droit; Option de géométrie: Uniforme; Surface de face intérieure: GENERAL; Angle d'inclinaison interne de mur: 90 deg; Angle d'inclinaison externe de mur: 90 deg; Génération de modèle analytique structurel: yes; Classification ARCHICAD - 20: Mur
Pset_ConcreteElementGeneral - ConstructionType: Murs porteurs extérieurs
AC_Pset_RenovationAndPhasing - Renovation Status: Existing
Pset_WallCommon - IsExternal: yes; LoadBearing: yes

# IfcWall: _acrotere ANGLE 230 x 770 (4)
In: Toit & PM
Classification: Mur (Classification ARCHICAD); Mur (Classification Archicad); Material: _BA banché RAL9007
ArchiCADProperties - Calque: 10_M x baseGO__; Matériau de construction / Composite / Profil / Hachure: _acrotere ANGLE; Profil complexe: _acrotere ANGLE; Verrouillé: no; Nom d'étage d'implantation: Toit & PM; Numéro d'étage d'implantation: 2; Type d'élément: Mur; Étage supérieur lié absolu: Non lié; Étage supérieur lié relatif: Non lié; Étage supérieur lié: Non lié; Type de structure: Profil complexe; Matériaux de construction (Tous): _menuiserie alu; _BA banché RAL9007; Surfaces (Toutes): _Men ext_RAL9007; _Enduit minéral blanc; _MENEAU gris RAL 9007; __Enduit minéral RAL7004; Angle d'inclinaison: 90 deg; Nombre de percements: 0; Surface latérale: _Enduit minéral blanc; Position: Extérieur; État de rénovation: Existant; Affichage sur filtre de rénovation: Tous les filtres appropriés; Fonction structurelle: Élément porteur; Complexité de mur: Droit; Option de géométrie: Uniforme; Surface de face intérieure: GENERAL; Angle d'inclinaison interne de mur: 90 deg; Angle d'inclinaison externe de mur: 90 deg; Génération de modèle analytique structurel: yes; Classification ARCHICAD - 20: Mur
Pset_ConcreteElementGeneral - ConstructionType: Murs porteurs extérieurs
AC_Pset_RenovationAndPhasing - Renovation Status: Existing
Pset_WallCommon - IsExternal: yes; LoadBearing: yes
Name | ID de l'élément = Lien et ID d'élément = ID de Parent
M acrot Nord-hall | M acrot Nord-hall
M acrot-Est-hall | M acrot-Est-hall
M acrot Ouest-hall | M acrot Ouest-hall
M acrot Sud-hall | M acrot Sud-hall

# IfcWall: _acrotere JD 210 x 570 (2)
In: Toit & PM
Classification: Mur (Classification ARCHICAD); Mur (Classification Archicad); Material: _BA banché RAL9007
ArchiCADProperties - ID de l'élément: M acrot -classe; Lien et ID d'élément: M acrot -classe; Calque: 10_M x baseGO__; Matériau de construction / Composite / Profil / Hachure: _acrotere JD; Profil complexe: _acrotere JD; Verrouillé: no; Nom d'étage d'implantation: Toit & PM; Numéro d'étage d'implantation: 2; Type d'élément: Mur; Étage supérieur lié absolu: Non lié; Étage supérieur lié relatif: Non lié; Étage supérieur lié: Non lié; Type de structure: Profil complexe; ID de Parent: M acrot -classe; Matériaux de construction (Tous): _menuiserie alu; _BA banché RAL9007; Surfaces (Toutes): _Men ext_RAL9007; _Enduit minéral blanc; _MENEAU gris RAL 9007; Angle d'inclinaison: 90 deg; Nombre de percements: 0; Surface latérale: _Enduit minéral blanc; Position: Extérieur; État de rénovation: Existant; Affichage sur filtre de rénovation: Tous les filtres appropriés; Fonction structurelle: Élément porteur; Complexité de mur: Droit; Option de géométrie: Uniforme; Surface de face intérieure: GENERAL; Angle d'inclinaison interne de mur: 90 deg; Angle d'inclinaison externe de mur: 90 deg; Génération de modèle analytique structurel: yes; Classification ARCHICAD - 20: Mur
Pset_ConcreteElementGeneral - ConstructionType: Murs porteurs extérieurs
AC_Pset_RenovationAndPhasing - Renovation Status: Existing
Pset_WallCommon - IsExternal: yes; LoadBearing: yes

# IfcWall: _acrotere MILIEU 230 x 417 (2)
In: Toit & PM
Classification: Mur (Classification ARCHICAD); Mur (Classification Archicad); Material: _BA banché MILIEU
ArchiCADProperties - ID de l'élément: M acrot milieu; Lien et ID d'élément: M acrot milieu; Calque: 10_M x baseGO__; Matériau de construction / Composite / Profil / Hachure: _acrotere MILIEU; Profil complexe: _acrotere MILIEU; Verrouillé: no; Nom d'étage d'implantation: Toit & PM; Numéro d'étage d'implantation: 2; Type d'élément: Mur; Étage supérieur lié absolu: Non lié; Étage supérieur lié relatif: Non lié; Étage supérieur lié: Non lié; Type de structure: Profil complexe; ID de Parent: M acrot milieu; Matériaux de construction (Tous): _BA banché MILIEU; _menuiserie alu; Surfaces (Toutes): _Men ext_RAL9007; _Enduit minéral blanc; _Enduit minéral RAL7004; Angle d'inclinaison: 90 deg; Nombre de percements: 0; Surface latérale: _Enduit minéral blanc; Position: Extérieur; État de rénovation: Existant; Affichage sur filtre de rénovation: Tous les filtres appropriés; Fonction structurelle: Élément porteur; Complexité de mur: Droit; Option de géométrie: Uniforme; Surface de face intérieure: GENERAL; Angle d'inclinaison interne de mur: 90 deg; Angle d'inclinaison externe de mur: 90 deg; Génération de modèle analytique structurel: yes; Classification ARCHICAD - 20: Mur
Pset_ConcreteElementGeneral - ConstructionType: Murs porteurs extérieurs
AC_Pset_RenovationAndPhasing - Renovation Status: Existing
Pset_WallCommon - IsExternal: yes; LoadBearing: yes

# IfcWallStandardCase: _BA banché RAL9007 180 (5)
Classification: Mur (Classification ARCHICAD); Mur (Classification Archicad); Material: _BA banché RAL9007 0.18 m
ArchiCADProperties - Calque: 10_M x baseGO__; Matériau de construction / Composite / Profil / Hachure: _BA banché RAL9007; Matériau de construction: _BA banché RAL9007; Verrouillé: no; Type d'élément: Mur; Étage supérieur lié absolu: Non lié; Étage supérieur lié relatif: Non lié; Étage supérieur lié: Non lié; Type de structure: Basique; Matériaux de construction (Tous): _BA banché RAL9007; Angle d'inclinaison: 90 deg; Nombre de percements: 0; État de rénovation: Existant; Affichage sur filtre de rénovation: Tous les filtres appropriés; Fonction structurelle: Élément porteur; Complexité de mur: Droit; Option de géométrie: Uniforme; Emplacement de ligne de référence: Face extérieure; Angle d'inclinaison interne de mur: 90 deg; Angle d'inclinaison externe de mur: 90 deg; Génération de modèle analytique structurel: yes; Classification ARCHICAD - 20: Mur
Pset_ConcreteElementGeneral - ConstructionType: Murs porteurs extérieurs
AC_Pset_RenovationAndPhasing - Renovation Status: Existing
Pset_WallCommon - LoadBearing: yes
Name | In | ID de l'élément = Lien et ID d'élément = ID de Parent | Nom d'étage d'implantation | Numéro d'étage d'implantation | Surfaces (Toutes) | Surface latérale = Surface de face intérieure | Position | Surface de face extérieure | IsExternal
2 x refend-ascens | Fondations | refend-ascens | Fondations | -1 | _Enduit minéral blanc; _MENEAU gris RAL 9007 | _MENEAU gris RAL 9007 | Intérieur | _Enduit minéral blanc | no
refend-ascens | Fondations | refend-ascens | Fondations | -1 | _MENEAU gris RAL 9007 | _MENEAU gris RAL 9007 | Intérieur | _MENEAU gris RAL 9007 | no
refend-ascens | Fondations | refend-ascens | Fondations | -1 | _Béton - Lissé; _MENEAU gris RAL 9007 | _MENEAU gris RAL 9007 | Intérieur | _Béton - Lissé | no
M acrot -classe | Toit & PM | M acrot -classe | Toit & PM | 2 | _Mur int blanc; _Enduit minéral blanc; _MENEAU gris RAL 9007; __Enduit minéral RAL7004 | _Enduit minéral blanc | Extérieur | _Mur int blanc | yes

# IfcWallStandardCase: _BA banché RAL9007 200 (12)
In: Fondations
Classification: Mur (Classification ARCHICAD); Mur (Classification Archicad); Material: _BA banché RAL9007 0.2 m
ArchiCADProperties - ID de l'élément: beche-hors-gel; Lien et ID d'élément: beche-hors-gel; Calque: 10_M x baseGO__; Matériau de construction / Composite / Profil / Hachure: _BA banché RAL9007; Matériau de construction: _BA banché RAL9007; Verrouillé: no; Nom d'étage d'implantation: Fondations; Numéro d'étage d'implantation: -1; Type d'élément: Mur; Étage supérieur lié absolu: RDC; Étage supérieur lié relatif: Étage d'implantation + 1; Étage supérieur lié: Étage d'implantation + 1 (RDC); Type de structure: Basique; ID de Parent: beche-hors-gel; Matériaux de construction (Tous): _BA banché RAL9007; Angle d'inclinaison: 90 deg; Nombre de percements: 0; Surface latérale: _Béton - Lissé; Position: Extérieur; État de rénovation: Existant; Affichage sur filtre de rénovation: Tous les filtres appropriés; Fonction structurelle: Élément porteur; Complexité de mur: Droit; Option de géométrie: Uniforme; Emplacement de ligne de référence: Face extérieure; Surface de face intérieure: _Béton - Lissé; Surface de face extérieure: _Béton - Lissé; Angle d'inclinaison interne de mur: 90 deg; Angle d'inclinaison externe de mur: 90 deg; Génération de modèle analytique structurel: yes; Classification ARCHICAD - 20: Mur
Pset_ConcreteElementGeneral - ConstructionType: Murs porteurs extérieurs
AC_Pset_RenovationAndPhasing - Renovation Status: Existing
Pset_WallCommon - IsExternal: yes; LoadBearing: yes
Name | Surfaces (Toutes)
10 x beche-hors-gel | _Béton - Lissé; _MENEAU gris RAL 9007
2 x beche-hors-gel | _Béton - Lissé
